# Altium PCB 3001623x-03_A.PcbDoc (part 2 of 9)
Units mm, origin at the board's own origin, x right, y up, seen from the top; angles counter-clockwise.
Board outline 210 x 130 mm, 9 copper layers (1-TOP, 2-GND, 3-INTOP, 4-PWR, 5-PWR, 6-INBOT, Signal_4, 7-GND, 8-BOTTOM), stack 1.979 mm thick; 755 components, 650 nets, 2980 pads, 2365 vias.

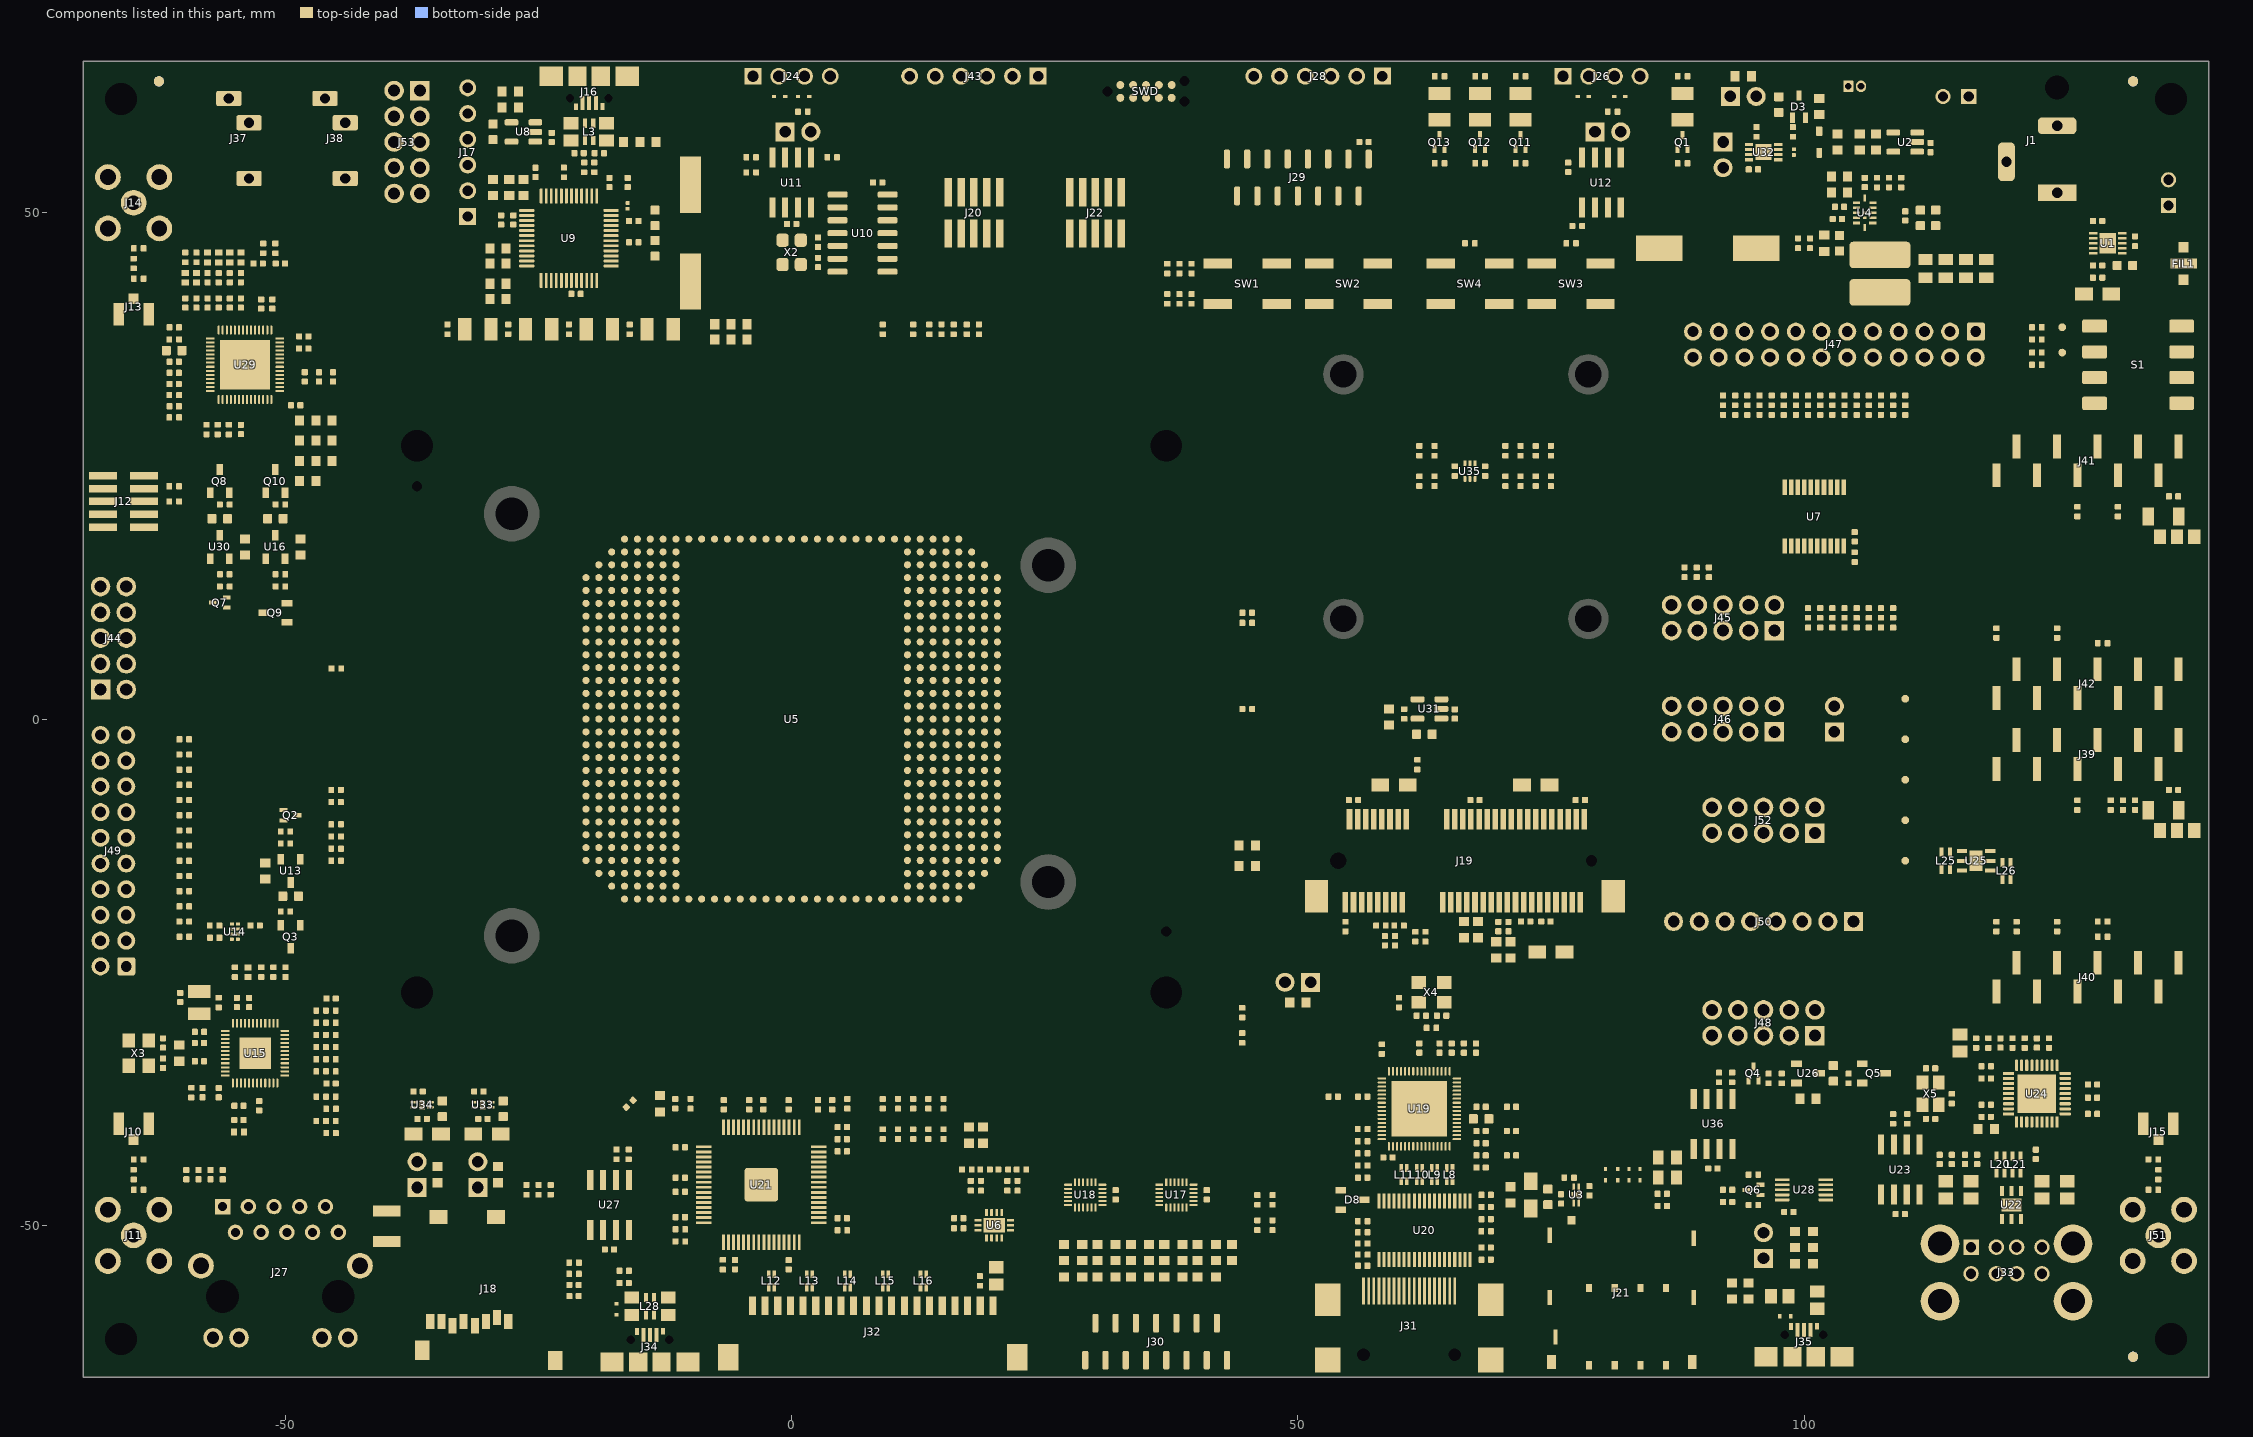
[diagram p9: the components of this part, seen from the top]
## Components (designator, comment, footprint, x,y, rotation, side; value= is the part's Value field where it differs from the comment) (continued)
U18 "NX3DV642" QFN40P340X250X50-24N 29,-47 r90 top locked
U19 "LT8912B" QFN40P750X750X80-65T620N 62,-38.5 r0 top
U20 "CM2020-01" SOP50P640X120-38N 62.5,-50.5 r270 top locked
U21 "SN65DSI83" QFP50P1200X1200X120-65L30T320N -3,-46 r90 top locked
U22 "TPD4E001DRSR" SON95P300X300X80-7N 120.5,-48 r0 top
U23 "MIC2026" SOIC127P600X175-8N 109.5,-44.5 r270 top locked
U24 "USB2514BI-AEZG" QFN50P600X600X100-37AN 123,-37 r90 top locked
U25 "TPD4E001DRSR" SON95P300X300X80-7N 117,-14 r270 top locked
U26 "SI2323DS-T1-E3" SOT95P240X110_GSD-3N 100.4,-35 r270 top
U27 "MIC2026" SOIC127P600X175-8N -18,-48 r270 top locked
U28 "FSUSB20MUX" SOP50P490X110-10L30N 100,-46.5 r180 top locked
U29 "MAX98089" QFN40P700X700X80-57T560X560N -54,35 r90 top locked
U30 "SI2323DS-T1-E3" SOT95P240X110_GSD-3N -56.5,17 r0 top
U31 "AP2202" SOT95P280X145-5N 63,1 r180 top
U32 "MCP6442T-E/MNY" SON50P300X200X80-9N 96,56 r90 top
U33 "SIP32401A" SON50P120X160X60-5T55X91N -30.5,-38.1 r180 top locked
U34 "SIP32401A" SON50P120X160X60-5T55X91N -36.5,-38.1 r180 top locked
U35 "DMN5L06VK-7" SOTFL50P160X60-6N 67,24.5 r90 top
U36 "MIC2026" SOIC127P600X175-8N 91,-40 r270 top locked
X1 "6MHz" "XTAL_ XT9M20HRR" -10,48 r270 top
X2 "RH100-40.000-9-F-1010-EXT-TR" OSCCC320X250X71N 0,46.1 r0 top
X3 "RH100-25.000-20-EXT-TR" OSC210P320X250X90-4N -64.5,-33 r0 top
X4 "RH100-25.000-20-EXT-TR" OSC210P320X250X90-4N 63.2,-27 r270 top
X5 "24MHz" XTAL_C3E-3427 112.5,-37 r90 top locked

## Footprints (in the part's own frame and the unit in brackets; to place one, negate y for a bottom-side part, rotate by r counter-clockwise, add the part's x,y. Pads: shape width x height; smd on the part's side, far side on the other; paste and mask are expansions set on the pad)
"BOBBINTRON_SMA A700T" [mil] "SMA JACK RA"
  round 100 hole 55.12: 1(0,0)
  round 100 hole 61: 2(-100,100) 3(100,100) 4(-100,-100) 5(100,-100)
  body extent -137,-138 457,138, height 398
CAPC1005X55N [mm]
  rrect30% 0.6x0.62 smd mask+0.1: 1(-0.46,0) 2(0.46,0)
  body extent -0.5,-0.25 0.5,0.25, height 0.55
CAPC1608X90N [mm] "0603"
  rrect22% 0.89x0.93 smd: 1(-0.77,0) 2(0.77,0)
  body extent -0.8,-0.4 0.8,0.4, height 0.9
CAPC2013X135N [mm] "0805, 1.35mm max height"
  rect 1.05x1.4 smd: 1(-0.9,0) 2(0.9,0)
  body extent -1,-0.62 1,0.63, height 1.35
CAPC3216X190N [mm]
  rect 1.15x1.8 smd: 1(-1.5,0) 2(1.5,0)
  body extent -1.6,-0.8 1.6,0.8, height 1.9
CAPMP3216X120N [mm]
  rect 1.75x1.3 smd: 1(-1.35,0) 2(1.35,0)
  body extent -1.7,-0.9 1.7,0.9, height 1.21
CONN_CSCD443CCS011B00G [mil] "Bobbintron : CSCD443CCS011B00G"
  rect 65x150 hole 40 slot 126 at 90 deg: 1(0,0)
  rrect50% 65x150 / inner rect 65x150 / far side rrect50% 65x150 hole 40 slot 126 at 90 deg: 2(-260,0)
  rrect50% 150x65 / inner rect 150x65 / far side rrect50% 150x65 hole 40 slot 126 at 0 deg: 3(-120,-197.01)
  round 0 hole 93 unplated: 4(-409,0)
  body extent -571,-207 20,177, height 433
CUI_SJ1-3533N [mm] "CON PWR JCK STEREO 3.5MM R/A 3.05mm"
  rrect25% 1.5x2.5 hole 1 slot 2 at 90 deg: 1(-3.8,-0.1) 2(-1.4,1.9) 3(4.1,1.9)
  body extent -9,-4.1 9,4.1, height 12.3
E-TEC_LPJ474-129M-32ABEW55L [mm]
  round 0.7 smd: A4(-20.32,-13.97) A5(-20.32,-12.7) A6(-20.32,-11.43) A7(-20.32,-10.16) A8(-20.32,-8.89) A9(-20.32,-7.62) A10(-20.32,-6.35) A11(-20.32,-5.08) A12(-20.32,-3.81) A13(-20.32,-2.54) A14(-20.32,-1.27) A15(-20.32,0) A16(-20.32,1.27) A17(-20.32,2.54) A18(-20.32,3.81) A19(-20.32,5.08) A20(-20.32,6.35) A21(-20.32,7.62) A22(-20.32,8.89) A23(-20.32,10.16) A24(-20.32,11.43) A25(-20.32,12.7) A26(-20.32,13.97) AA1(5.08,-17.78) AA29(5.08,17.78) AB1(6.35,-17.78) AB29(6.35,17.78) AC1(7.62,-17.78) AC29(7.62,17.78) AD1(8.89,-17.78) AD29(8.89,17.78) AE1(10.16,-17.78) AE29(10.16,17.78) AF1(11.43,-17.78) AF2(11.43,-16.51) AF3(11.43,-15.24) AF4(11.43,-13.97) AF5(11.43,-12.7) AF6(11.43,-11.43) AF7(11.43,-10.16) AF8(11.43,-8.89) AF9(11.43,-7.62) AF10(11.43,-6.35) AF11(11.43,-5.08) AF12(11.43,-3.81) AF13(11.43,-2.54) AF14(11.43,-1.27) AF15(11.43,0) AF16(11.43,1.27) AF17(11.43,2.54) AF18(11.43,3.81) AF19(11.43,5.08) AF20(11.43,6.35) AF21(11.43,7.62) AF22(11.43,8.89) AF23(11.43,10.16) AF24(11.43,11.43) AF25(11.43,12.7) AF26(11.43,13.97) AF27(11.43,15.24) AF28(11.43,16.51) AF29(11.43,17.78) AG1(12.7,-17.78) AG2(12.7,-16.51) AG3(12.7,-15.24) AG4(12.7,-13.97) AG5(12.7,-12.7) AG6(12.7,-11.43) AG7(12.7,-10.16) AG8(12.7,-8.89) AG9(12.7,-7.62) AG10(12.7,-6.35) AG11(12.7,-5.08) AG12(12.7,-3.81) AG13(12.7,-2.54) AG14(12.7,-1.27) AG15(12.7,0) AG16(12.7,1.27) AG17(12.7,2.54) AG18(12.7,3.81) AG19(12.7,5.08) AG20(12.7,6.35) AG21(12.7,7.62) AG22(12.7,8.89) AG23(12.7,10.16) AG24(12.7,11.43) AG25(12.7,12.7) AG26(12.7,13.97) AG27(12.7,15.24) AG28(12.7,16.51) AG29(12.7,17.78) AH1(13.97,-17.78) AH2(13.97,-16.51) AH3(13.97,-15.24) AH4(13.97,-13.97) AH5(13.97,-12.7) AH6(13.97,-11.43) AH7(13.97,-10.16) AH8(13.97,-8.89) AH9(13.97,-7.62) AH10(13.97,-6.35) AH11(13.97,-5.08) AH12(13.97,-3.81) AH13(13.97,-2.54) AH14(13.97,-1.27) AH15(13.97,0) AH16(13.97,1.27) AH17(13.97,2.54) AH18(13.97,3.81) AH19(13.97,5.08) AH20(13.97,6.35) AH21(13.97,7.62) AH22(13.97,8.89) AH23(13.97,10.16) AH24(13.97,11.43) AH25(13.97,12.7) AH26(13.97,13.97) AH27(13.97,15.24) AH28(13.97,16.51) AH29(13.97,17.78) AJ1(15.24,-17.78) AJ2(15.24,-16.51) AJ3(15.24,-15.24) AJ4(15.24,-13.97) AJ5(15.24,-12.7) AJ6(15.24,-11.43) AJ7(15.24,-10.16) AJ8(15.24,-8.89) AJ9(15.24,-7.62) AJ10(15.24,-6.35) AJ11(15.24,-5.08) AJ12(15.24,-3.81) AJ13(15.24,-2.54) AJ14(15.24,-1.27) AJ15(15.24,0) AJ16(15.24,1.27) AJ17(15.24,2.54) AJ18(15.24,3.81) AJ19(15.24,5.08) AJ20(15.24,6.35) AJ21(15.24,7.62) AJ22(15.24,8.89) AJ23(15.24,10.16) AJ24(15.24,11.43) AJ25(15.24,12.7) AJ26(15.24,13.97) AJ27(15.24,15.24) AJ28(15.24,16.51) AJ29(15.24,17.78) AK1(16.51,-17.78) AK2(16.51,-16.51) AK3(16.51,-15.24) AK4(16.51,-13.97) AK5(16.51,-12.7) AK6(16.51,-11.43) AK7(16.51,-10.16) AK8(16.51,-8.89) AK9(16.51,-7.62) AK10(16.51,-6.35) AK11(16.51,-5.08) AK12(16.51,-3.81) AK13(16.51,-2.54) AK14(16.51,-1.27) AK15(16.51,0) AK16(16.51,1.27) AK17(16.51,2.54) AK18(16.51,3.81) AK19(16.51,5.08) AK20(16.51,6.35) AK21(16.51,7.62) AK22(16.51,8.89) AK23(16.51,10.16) AK24(16.51,11.43) AK25(16.51,12.7) AK26(16.51,13.97) AK27(16.51,15.24) AK28(16.51,16.51) AK29(16.51,17.78) AL2(17.78,-16.51) AL3(17.78,-15.24) AL4(17.78,-13.97) AL5(17.78,-12.7) AL6(17.78,-11.43) AL7(17.78,-10.16) AL8(17.78,-8.89) AL9(17.78,-7.62) AL10(17.78,-6.35) AL11(17.78,-5.08) AL12(17.78,-3.81) AL13(17.78,-2.54) AL14(17.78,-1.27) AL15(17.78,0) AL16(17.78,1.27) AL17(17.78,2.54) AL18(17.78,3.81) AL19(17.78,5.08) AL20(17.78,6.35) AL21(17.78,7.62) AL22(17.78,8.89) AL23(17.78,10.16) AL24(17.78,11.43) AL25(17.78,12.7) AL26(17.78,13.97) AL27(17.78,15.24) AL28(17.78,16.51) AM3(19.05,-15.24) AM4(19.05,-13.97) AM5(19.05,-12.7) AM6(19.05,-11.43) AM7(19.05,-10.16) AM8(19.05,-8.89) AM9(19.05,-7.62) AM10(19.05,-6.35) AM11(19.05,-5.08) AM12(19.05,-3.81) AM13(19.05,-2.54) AM14(19.05,-1.27) AM15(19.05,0) AM16(19.05,1.27) AM17(19.05,2.54) AM18(19.05,3.81) AM19(19.05,5.08) AM20(19.05,6.35) AM21(19.05,7.62) AM22(19.05,8.89) AM23(19.05,10.16) AM24(19.05,11.43) AM25(19.05,12.7) AM26(19.05,13.97) AM27(19.05,15.24) AN4(20.32,-13.97) AN5(20.32,-12.7) AN6(20.32,-11.43) AN7(20.32,-10.16) AN8(20.32,-8.89) AN9(20.32,-7.62) AN10(20.32,-6.35) AN11(20.32,-5.08) AN12(20.32,-3.81) AN13(20.32,-2.54) AN14(20.32,-1.27) AN15(20.32,0) AN16(20.32,1.27) AN17(20.32,2.54) AN18(20.32,3.81) AN19(20.32,5.08) AN20(20.32,6.35) AN21(20.32,7.62) AN22(20.32,8.89) AN23(20.32,10.16) AN24(20.32,11.43) AN25(20.32,12.7) AN26(20.32,13.97) B3(-19.05,-15.24) B4(-19.05,-13.97) B5(-19.05,-12.7) B6(-19.05,-11.43) B7(-19.05,-10.16) B8(-19.05,-8.89) B9(-19.05,-7.62) B10(-19.05,-6.35) B11(-19.05,-5.08) B12(-19.05,-3.81) B13(-19.05,-2.54) B14(-19.05,-1.27) B15(-19.05,0) B16(-19.05,1.27) B17(-19.05,2.54) B18(-19.05,3.81) B19(-19.05,5.08) B20(-19.05,6.35) B21(-19.05,7.62) B22(-19.05,8.89) B23(-19.05,10.16) B24(-19.05,11.43) B25(-19.05,12.7) B26(-19.05,13.97) B27(-19.05,15.24) C2(-17.78,-16.51) C3(-17.78,-15.24) C4(-17.78,-13.97) C5(-17.78,-12.7) C6(-17.78,-11.43) C7(-17.78,-10.16) C8(-17.78,-8.89) C9(-17.78,-7.62) C10(-17.78,-6.35) C11(-17.78,-5.08) C12(-17.78,-3.81) C13(-17.78,-2.54) C14(-17.78,-1.27) C15(-17.78,0) C16(-17.78,1.27) C17(-17.78,2.54) C18(-17.78,3.81) C19(-17.78,5.08) C20(-17.78,6.35) C21(-17.78,7.62) C22(-17.78,8.89) C23(-17.78,10.16) C24(-17.78,11.43) C25(-17.78,12.7) C26(-17.78,13.97) C27(-17.78,15.24) C28(-17.78,16.51) D1(-16.51,-17.78) D2(-16.51,-16.51) D3(-16.51,-15.24) D4(-16.51,-13.97) D5(-16.51,-12.7) D6(-16.51,-11.43) D7(-16.51,-10.16) D8(-16.51,-8.89) D9(-16.51,-7.62) D10(-16.51,-6.35) D11(-16.51,-5.08) D12(-16.51,-3.81) D13(-16.51,-2.54) D14(-16.51,-1.27) D15(-16.51,0) D16(-16.51,1.27) D17(-16.51,2.54) D18(-16.51,3.81) D19(-16.51,5.08) D20(-16.51,6.35) D21(-16.51,7.62) D22(-16.51,8.89) D23(-16.51,10.16) D24(-16.51,11.43) D25(-16.51,12.7) D26(-16.51,13.97) D27(-16.51,15.24) D28(-16.51,16.51) D29(-16.51,17.78) E1(-15.24,-17.78) E2(-15.24,-16.51) E3(-15.24,-15.24) E4(-15.24,-13.97) E5(-15.24,-12.7) E6(-15.24,-11.43) E7(-15.24,-10.16) E8(-15.24,-8.89) E9(-15.24,-7.62) E10(-15.24,-6.35) E11(-15.24,-5.08) E12(-15.24,-3.81) E13(-15.24,-2.54) E14(-15.24,-1.27) E15(-15.24,0) E16(-15.24,1.27) E17(-15.24,2.54) E18(-15.24,3.81) E19(-15.24,5.08) E20(-15.24,6.35) E21(-15.24,7.62) E22(-15.24,8.89) E23(-15.24,10.16) E24(-15.24,11.43) E25(-15.24,12.7) E26(-15.24,13.97) E27(-15.24,15.24) E28(-15.24,16.51) E29(-15.24,17.78) F1(-13.97,-17.78) F2(-13.97,-16.51) F3(-13.97,-15.24) F4(-13.97,-13.97) F5(-13.97,-12.7) F6(-13.97,-11.43) F7(-13.97,-10.16) F8(-13.97,-8.89) F9(-13.97,-7.62) F10(-13.97,-6.35) F11(-13.97,-5.08) F12(-13.97,-3.81) F13(-13.97,-2.54) F14(-13.97,-1.27) F15(-13.97,0) F16(-13.97,1.27) F17(-13.97,2.54) F18(-13.97,3.81) F19(-13.97,5.08) F20(-13.97,6.35) F21(-13.97,7.62) F22(-13.97,8.89) F23(-13.97,10.16) F24(-13.97,11.43) F25(-13.97,12.7) F26(-13.97,13.97) F27(-13.97,15.24) F28(-13.97,16.51) F29(-13.97,17.78) G1(-12.7,-17.78) G2(-12.7,-16.51) G3(-12.7,-15.24) G4(-12.7,-13.97) G5(-12.7,-12.7) G6(-12.7,-11.43) G7(-12.7,-10.16) G8(-12.7,-8.89) G9(-12.7,-7.62) G10(-12.7,-6.35) G11(-12.7,-5.08) G12(-12.7,-3.81) G13(-12.7,-2.54) G14(-12.7,-1.27) G15(-12.7,0) G16(-12.7,1.27) G17(-12.7,2.54) G18(-12.7,3.81) G19(-12.7,5.08) G20(-12.7,6.35) G21(-12.7,7.62) G22(-12.7,8.89) G23(-12.7,10.16) G24(-12.7,11.43) G25(-12.7,12.7) G26(-12.7,13.97) G27(-12.7,15.24) G28(-12.7,16.51) G29(-12.7,17.78) H1(-11.43,-17.78) H2(-11.43,-16.51) H3(-11.43,-15.24) H4(-11.43,-13.97) H5(-11.43,-12.7) H6(-11.43,-11.43) H7(-11.43,-10.16) H8(-11.43,-8.89) H9(-11.43,-7.62) H10(-11.43,-6.35) H11(-11.43,-5.08) H12(-11.43,-3.81) H13(-11.43,-2.54) H14(-11.43,-1.27) H15(-11.43,0) H16(-11.43,1.27) H17(-11.43,2.54) H18(-11.43,3.81) H19(-11.43,5.08) H20(-11.43,6.35) H21(-11.43,7.62) H22(-11.43,8.89) H23(-11.43,10.16) H24(-11.43,11.43) H25(-11.43,12.7) H26(-11.43,13.97) H27(-11.43,15.24) H28(-11.43,16.51) H29(-11.43,17.78) J1(-10.16,-17.78) J29(-10.16,17.78) K1(-8.89,-17.78) K29(-8.89,17.78) L1(-7.62,-17.78) L29(-7.62,17.78) M1(-6.35,-17.78) M29(-6.35,17.78) N1(-5.08,-17.78) N29(-5.08,17.78) P1(-3.81,-17.78) P29(-3.81,17.78) R1(-2.54,-17.78) R29(-2.54,17.78) T1(-1.27,-17.78) T29(-1.27,17.78) U1(0,-17.78) U29(0,17.78) V1(1.27,-17.78) V29(1.27,17.78) W1(2.54,-17.78) W29(2.54,17.78) Y1(3.81,-17.78) Y29(3.81,17.78)
  round 0 hole 3.15 unplated: MH1(-37,27) MH2(37,27) MH3(37,-27) MH4(-37,-27)
  round 0 hole 1: MH5(-37,23) MH6(37,-21)
  Keep-Out Layer board cut-out: -10.75,16 -10.75,-16 -10.75,-16.098 -10.712,-16.292 -10.636,-16.474 -10.527,-16.638 -10.388,-16.777 -10.224,-16.886 -10.042,-16.962 -9.848,-17 -9.75,-17 -9.75,-17 10,-17 10.074,-17 10.219,-16.971 10.355,-16.915 10.478,-16.833 10.583,-16.728 10.665,-16.605 10.721,-16.469 10.75,-16.324 10.75,-16.25 10.75,-16.25 10.75,16 10.75,16.098 10.712,16.292 10.636,16.474 10.527,16.637 10.387,16.777 10.224,16.886 10.042,16.962 9.848,17 9.75,17 9.75,17 -9.75,17 -9.848,17 -10.042,16.962 -10.224,16.886 -10.387,16.777 -10.527,16.637 -10.636,16.474 -10.712,16.292 -10.75,16.099 -10.75,16
  Keep-Out Layer region: -38.9,27 -38.9,27.187 -38.827,27.554 -38.684,27.9 -38.476,28.211 -38.211,28.476 -37.9,28.684 -37.554,28.827 -37.187,28.9 -37,28.9 -36.813,28.9 -36.446,28.827 -36.1,28.684 -35.789,28.476 -35.524,28.211 -35.316,27.9 -35.173,27.554 -35.1,27.187 -35.1,27 -35.1,27 -35.1,26.813 -35.173,26.446 -35.316,26.1 -35.524,25.789 -35.789,25.524 -36.1,25.316 -36.446,25.173 -36.813,25.1 -37,25.1 -37,25.1 -37.187,25.1 -37.554,25.173 -37.9,25.316 -38.211,25.524 -38.476,25.789 -38.684,26.1 -38.827,26.446 -38.9,26.813 -38.9,27
  Keep-Out Layer region: 35.1,27 35.1,27.187 35.173,27.554 35.316,27.9 35.524,28.211 35.789,28.476 36.1,28.684 36.446,28.827 36.813,28.9 37,28.9 37.187,28.9 37.554,28.827 37.9,28.684 38.211,28.476 38.476,28.211 38.684,27.9 38.827,27.554 38.9,27.187 38.9,27 38.9,27 38.9,26.813 38.827,26.446 38.684,26.1 38.476,25.789 38.211,25.524 37.9,25.316 37.554,25.173 37.187,25.1 37,25.1 37,25.1 36.813,25.1 36.446,25.173 36.1,25.316 35.789,25.524 35.524,25.789 35.316,26.1 35.173,26.446 35.1,26.813 35.1,27
  Keep-Out Layer region: 35.1,-27 35.1,-26.813 35.173,-26.446 35.316,-26.1 35.524,-25.789 35.789,-25.524 36.1,-25.316 36.446,-25.173 36.813,-25.1 37,-25.1 37.187,-25.1 37.554,-25.173 37.9,-25.316 38.211,-25.524 38.476,-25.789 38.684,-26.1 38.827,-26.446 38.9,-26.813 38.9,-27 38.9,-27 38.9,-27.187 38.827,-27.554 38.684,-27.9 38.476,-28.211 38.211,-28.476 37.9,-28.684 37.554,-28.827 37.187,-28.9 37,-28.9 37,-28.9 36.813,-28.9 36.446,-28.827 36.1,-28.684 35.789,-28.476 35.524,-28.211 35.316,-27.9 35.173,-27.554 35.1,-27.187 35.1,-27
  Keep-Out Layer region: -38.9,-27 -38.9,-26.813 -38.827,-26.446 -38.684,-26.1 -38.476,-25.789 -38.211,-25.524 -37.9,-25.316 -37.554,-25.173 -37.187,-25.1 -37,-25.1 -36.813,-25.1 -36.446,-25.173 -36.1,-25.316 -35.789,-25.524 -35.524,-25.789 -35.316,-26.1 -35.173,-26.446 -35.1,-26.813 -35.1,-27 -35.1,-27 -35.1,-27.187 -35.173,-27.554 -35.316,-27.9 -35.524,-28.211 -35.789,-28.476 -36.1,-28.684 -36.446,-28.827 -36.813,-28.9 -37,-28.9 -37,-28.9 -37.187,-28.9 -37.554,-28.827 -37.9,-28.684 -38.211,-28.476 -38.476,-28.211 -38.684,-27.9 -38.827,-27.554 -38.9,-27.187 -38.9,-27
  Keep-Out Layer region: -37.7,23 -37.7,23.069 -37.673,23.204 -37.62,23.332 -37.544,23.446 -37.446,23.544 -37.332,23.62 -37.204,23.673 -37.069,23.7 -37,23.7 -36.931,23.7 -36.796,23.673 -36.668,23.62 -36.554,23.544 -36.456,23.446 -36.38,23.332 -36.327,23.204 -36.3,23.069 -36.3,23 -36.3,23 -36.3,22.931 -36.327,22.796 -36.38,22.668 -36.456,22.554 -36.554,22.456 -36.668,22.38 -36.796,22.327 -36.931,22.3 -37,22.3 -37,22.3 -37.069,22.3 -37.204,22.327 -37.332,22.38 -37.446,22.456 -37.544,22.554 -37.62,22.668 -37.673,22.796 -37.7,22.931 -37.7,23
  Keep-Out Layer region: 36.3,-21 36.3,-20.931 36.327,-20.796 36.38,-20.668 36.456,-20.554 36.554,-20.456 36.668,-20.38 36.796,-20.327 36.931,-20.3 37,-20.3 37.069,-20.3 37.204,-20.327 37.332,-20.38 37.446,-20.456 37.544,-20.554 37.62,-20.668 37.673,-20.796 37.7,-20.931 37.7,-21 37.7,-21 37.7,-21.069 37.673,-21.204 37.62,-21.332 37.544,-21.446 37.446,-21.544 37.332,-21.62 37.204,-21.673 37.069,-21.7 37,-21.7 37,-21.7 36.931,-21.7 36.796,-21.673 36.668,-21.62 36.554,-21.544 36.456,-21.446 36.38,-21.332 36.327,-21.204 36.3,-21.069 36.3,-21
  body extent -46.8,-36.5 43,36.5, height 52.8
FCI_68002-102HLF#1 [mil]
  rect 74x74 hole 45: 1(-50,0)
  round 74 hole 45: 2(50,0)
  silkscreen extent -135,-7 -120,7, body extent -101,-46 99,49, height 330
FCI_68002-102HLF#2 [mil]
  rect 74x74 hole 45: 1(0,0)
  round 74 hole 45: 2(100,0)
  silkscreen extent -85,-7 -70,7, body extent -51,-46 149,49, height 330
FCI_SFW15S-2STE1LF [mm] "CONN FFC FPC VERT 15POS 1MM SMD"
  rrect50% 0.6x1.85 smd: 1(-7,-1.825) 2(-6,1.825) 3(-5,-1.825) 4(-4,1.825) 5(-3,-1.825) 6(-2,1.825) 7(-1,-1.825) 8(0,1.825) 9(1,-1.825) 10(2,1.825) 11(3,-1.825) 12(4,1.825) 13(5,-1.825) 14(6,1.825) 15(7,-1.825)
  silkscreen extent -9,-3.45 -7.5,-1.95, body extent -10.7,-2.25 10.7,2.25, height 5.31
FIDUCIAL_40MIL_ROUND [mil]
  round 40 smd paste-40 mask+20: 1(0,0)
  1-TOP pour cut-out: -40,0 -40,3.94 -38.46,11.67 -35.45,18.95 -31.07,25.5 -25.5,31.07 -18.95,35.45 -11.67,38.46 -3.94,40 0,40 3.94,40 11.67,38.46 18.95,35.45 25.5,31.07 31.07,25.5 35.45,18.95 38.46,11.67 40,3.94 40,0 40,-3.94 38.46,-11.67 35.45,-18.95 31.07,-25.5 25.5,-31.07 18.95,-35.45 11.67,-38.46 3.94,-40 0,-40 -3.94,-40 -11.67,-38.46 -18.95,-35.45 -25.5,-31.07 -31.07,-25.5 -35.45,-18.95 -38.46,-11.67 -40,-3.94 -40,0
FIL_DLP11S [mm]
  rect 0.75x0.35 smd: 1(-0.65,-0.275) 2(0.65,-0.275) 3(0.65,0.275) 4(-0.65,0.275)
  body extent -0.67,-0.55 0.68,0.55, height 0.92
FIL_DLW21H [mm]
  rect 0.9x0.4 smd: 1(-0.85,-0.4) 2(0.85,-0.4) 3(0.85,0.4) 4(-0.85,0.4)
  1-TOP pour cut-out: -0.4,-0.85 -0.4,0.85 0.4,0.85 0.4,-0.85
  body extent -1.1,-0.7 1.1,0.7, height 1
FIL_NFE31P [mm]
  rect 1x1 smd: 1(-1.6,0) 3(1.6,0)
  rect 1x2.6 smd: 2(0,0)
  body extent -1.78,-0.87 1.77,0.87, height 1.75
FOXCONN_AS0B221-S68Q-7H [mm]
  rect 0.55x2 smd: 1(-11.8,-4.1) 2(-11.4,4.1) 3(-11,-4.1) 4(-10.6,4.1) 5(-10.2,-4.1) 6(-9.8,4.1) 7(-9.4,-4.1) 8(-9,4.1) 9(-8.6,-4.1) 10(-8.2,4.1) 11(-7.8,-4.1) 12(-7.4,4.1) 13(-7,-4.1) 14(-6.6,4.1) 15(-6.2,-4.1) 16(-5.8,4.1) 17(-2.2,-4.1) 18(-1.8,4.1) 19(-1.4,-4.1) 20(-1,4.1) 21(-0.6,-4.1) 22(-0.2,4.1) 23(0.2,-4.1) 24(0.6,4.1) 25(1,-4.1) 26(1.4,4.1) 27(1.8,-4.1) 28(2.2,4.1) 29(2.6,-4.1) 30(3,4.1) 31(3.4,-4.1) 32(3.8,4.1) 33(4.2,-4.1) 34(4.6,4.1) 35(5,-4.1) 36(5.4,4.1) 37(5.8,-4.1) 38(6.2,4.1) 39(6.6,-4.1) 40(7,4.1) 41(7.4,-4.1) 42(7.8,4.1) 43(8.2,-4.1) 44(8.6,4.1) 45(9,-4.1) 46(9.4,4.1) 47(9.8,-4.1) 48(10.2,4.1) 49(10.6,-4.1) 50(11,4.1) 51(11.4,-4.1) 52(11.8,4.1)
  round 0 hole 1.6 unplated: H1(-12.5,0)
  round 0 hole 1.1 unplated: H2(12.5,0)
  rect 2.3x3.2 smd: MT1(-14.65,-3.5) MT2(14.65,-3.5)
  body extent -14.9,-4.75 14.9,4.75, height 6.8
HDRV4W64P254_4X1_1016X248H1067 [mm] "Header, Vertical, 2.54 mm pitch; 0.64 mm lead width, 4 pins, 1 row, 4 pins per row, 10.16 mm L X 2.48 mm W X 10.67 mm H body"
  rect 1.67x1.67 hole 1.11 paste-1.67 mask+0.1: 1(-3.81,0)
  round 1.67 hole 1.11 paste-1.67 mask+0.1: 2(-1.27,0) 3(1.27,0) 4(3.81,0)
  silkscreen extent -5.6,-1.6 -5.4,-1.4, body extent -5.08,-1.24 5.08,1.24, height 10.67
HIROSE_DF14A-20P-1.25H [mm]
  rect 0.7x1.8 smd: 1(11.875,-2.55) 2(10.625,-2.55) 3(9.375,-2.55) 4(8.125,-2.55) 5(6.875,-2.55) 6(5.625,-2.55) 7(4.375,-2.55) 8(3.125,-2.55) 9(1.875,-2.55) 10(0.625,-2.55) 11(-0.625,-2.55) 12(-1.875,-2.55) 13(-3.125,-2.55) 14(-4.375,-2.55) 15(-5.625,-2.55) 16(-6.875,-2.55) 17(-8.125,-2.55) 18(-9.375,-2.55) 19(-10.625,-2.55) 20(-11.875,-2.55)
  rect 2x2.6 smd: MT1(14.275,2.55) MT21(-14.275,2.55)
  silkscreen extent 12.75,-3.05 13.25,-2.55, body extent -14.97,-3.02 14.97,3.67, height 2.49
HIROSE_U.FL-R-SMT(01) [mm]
  rect 1x1.05 smd: 1(0,-1.525)
  rect 1.05x2.2 smd: 2(-1.475,0.025) 3(1.475,0.025)
  1-TOP pour cut-out: -0.95,1.125 0.95,1.125 0.95,-1.075 -0.95,-1.075
  body extent -1.5,-1.5 1.5,1.6, height 1.25
IND_DG6045C [mm] "IND_DG6045C"
  rrect25% 6x2.6 smd mask+0.1: 1(0,1.85) 2(0,-1.85)
  1-TOP keep-out region: -3.1,0.4 -3.1,-0.4 3.1,-0.4 3.1,0.4
  body extent -3.15,-3.15 3.15,3.15, height 4.5
INDC1005X60N [mm]
  rect 0.59x0.72 smd: 1(-0.48,0) 2(0.48,0)
  body extent -0.5,-0.25 0.5,0.25, height 0.6
INDC2013X110N [mm]
  rect 1.2x1.45 smd: 1(-0.85,0) 2(0.85,0)
  body extent -1,-0.62 1,0.63, height 1.1
INDC2520X100L60N [mm] "Inductor, Chip; 2.50 mm L X 2.00 mm W X 1.00 mm H body"
  rect 1.24x2.22 smd: 1(-1.09,0) 2(1.09,0)
  body extent -1.25,-1 1.25,1, height 1
KYCON_KDMIX [mm]
  rect 0.28x2.7 smd: 1(4.5,6.3) 2(4,6.3) 3(3.5,6.3) 4(3,6.3) 5(2.5,6.3) 6(2,6.3) 7(1.5,6.3) 8(1,6.3) 9(0.5,6.3) 10(0,6.3) 11(-0.5,6.3) 12(-1,6.3) 13(-1.5,6.3) 14(-2,6.3) 15(-2.5,6.3) 16(-3,6.3) 17(-3.5,6.3) 18(-4,6.3) 19(-4.5,6.3)
  round 0 hole 1.27 unplated: H1(4.5,0) H2(-4.5,0)
  rect 2.5x3.2 smd: M1(8.05,5.45) M2(-8.05,5.45)
  rect 2.5x2.5 smd: M3(8.05,-0.51) M4(-8.05,-0.51)
  body extent -8.58,-5.17 8.62,6.95, height 6.11
KYCON_KMMX-ABSMT5 [mm]
  rect 0.4x0.7 smd mask+0.058: 1(-1.3,3)
  rect 0.4x1.4 smd: 2(-0.65,2.65) 3(0,2.65) 4(0.65,2.65)
  rect 0.4x0.65 smd mask+0.058: 5(1.3,3.025)
  rect 2.3x1.9 smd: 6(-3.75,0) 9(3.75,0)
  rect 1.8x1.9 smd: 7(-1.15,0) 8(1.15,0)
  round 0 hole 0.813 unplated mask+0: 10(-1.9,2.18) 11(1.9,2.18)
  1-TOP region: 1.1,3.025 1.1,1.95 1.275,1.95 1.275,2.18 1.278,2.235 1.28,2.258 1.282,2.278 1.285,2.29 1.288,2.305 1.292,2.328 1.3,2.355 1.308,2.378 1.315,2.4 1.32,2.412 1.335,2.448 1.342,2.462 1.358,2.49 1.372,2.515 1.388,2.538 1.4,2.555 1.418,2.578 1.435,2.598 1.482,2.645 1.5,2.66 1.5,3.025
  1-TOP region: -1.1,3 -1.1,1.95 -1.275,1.95 -1.275,2.18 -1.278,2.235 -1.28,2.258 -1.282,2.278 -1.285,2.29 -1.288,2.305 -1.292,2.328 -1.3,2.355 -1.308,2.378 -1.315,2.4 -1.32,2.412 -1.335,2.448 -1.342,2.462 -1.358,2.49 -1.372,2.515 -1.388,2.538 -1.4,2.555 -1.418,2.578 -1.435,2.598 -1.482,2.645 -1.5,2.66 -1.5,3
  body extent -4.4,-2.73 4.4,2.87, height 2.78
KYCON_KUSBX-AS2N_FLEX [mm]
  rect 1.524x1.524 hole 1: A1(-3.5,5.33)
  round 1.524 hole 1: A2(-1,5.33) A3(1,5.33) A4(3.5,5.33) B1(-3.5,2.71) B2(-1,2.71) B3(1,2.71) B4(3.5,2.71)
  round 3.81 hole 2.362: SH1(-6.57,0) SH2(-6.57,5.68) SH3(6.57,0) SH4(6.57,5.68)
  body extent -7.83,-10.75 7.83,6.75, height 16.1
LEDM3020X130N [mm]
  rect 1.3x2.2 smd: A(-1.3,0) K(1.3,0)
  body extent -1.6,-1.1 1.6,1.1, height 1.5
MH_185_125_NP [mm]
  round 0 hole 3.175 unplated mask+0.102: 1(0,0)
  Keep-Out Layer circle w0.102: c0,0 r2.349
MOLEX_53047-0210_FLEX [mm]
  rrect20% 1x1.15 hole 0.65: 1(-0.625,0)
  oval 1x1.15 hole 0.65: 2(0.625,0)
  silkscreen extent -3.13,-0.25 -2.63,0.25, body extent -2.15,-1.15 2.1,2.05, height 4.2
MOLEX_78727-0001 [mm]
  rect 0.8x0.6 smd: 1(0.33,4.38) 2(0.33,1.84) 3(0.33,-0.7) 4(0.33,-3.24) 5(-7.29,4.38) 6(-7.29,1.84) 7(-7.29,-0.7) 8(-7.29,-3.24)
  rect 0.85x0.8 smd: 9(-13.99,-4.98)
  rect 1.5x0.42 smd: 10(-2.47,-6.54) 12(-6.35,7.11) 13(-12.21,7.11) 14(-12.51,-7.11) 15(-6.35,-7.11)
  rect 1.4x0.87 smd: 11(0,6.95) 16(0,-6.95)
  body extent -14.58,-7.26 0.64,7.27, height 1.4
MOLEX_87914-1016#1 [mil]
  rect 76x76 hole 47: 1(-200,50)
  round 76 hole 47: 2(-200,-50) 3(-100,50) 4(-100,-50) 5(0,50) 6(0,-50) 7(100,50) 8(100,-50) 9(200,50) 10(200,-50)
  silkscreen extent -293,37 -273,57, body extent -250,-98 250,98, height 320
MOLEX_87914-1016#2 [mil]
  rect 76x76 hole 47: 1(0,0)
  round 76 hole 47: 2(0,-100) 3(100,0) 4(100,-100) 5(200,0) 6(200,-100) 7(300,0) 8(300,-100) 9(400,0) 10(400,-100)
  silkscreen extent -90,-10 -70,10, body extent -50,-148 450,48, height 320
MOLEX_500873-0806 [mm]
  rect 0.8x1.5 smd: 1(0,0) 2(1.1,-0.4) 3(2.2,0) 4(3.3,0.425) 5(4.4,0) 6(5.5,0.425) 7(6.6,0) 8(7.7,0)
  rect 1.8x1.4 smd: 9(1.2,-10.3) 10(6.9,-10.3)
  rect 1.4x1.9 smd: 11(8.5,2.85) 12(-4.65,3.85)
  1-TOP region: 8.6,1.75 9.2,1.75 9.2,-11 8.6,-11
  body extent -5.05,-10.7 8.95,4.5, height 1.87
MOLEX_0022284060 [mil]
  rect 66x66 hole 40: 1(-250,0)
  round 66 hole 40: 2(-150,0) 3(-50,0) 4(50,0) 5(150,0) 6(250,0)
  silkscreen extent -331,-8 -315,8, body extent -300,-49 300,49, height 330
NEXC474Z3.5V10.5X8.5TRF [mm] "NEXC474Z3.5V10.5X8.5TRF"
  rect 2.5x4.6 smd: 1(0,4.8) 2(0,-4.8)
  body extent -5.4,-5.4 5.4,5.4, height 8.5
OSC210P320X250X90-4N [mm]
  rect 1.25x1.425 smd: 1(-0.975,1.25) 2(-0.975,-1.25) 3(0.975,-1.25) 4(0.975,1.25)
  body extent -1.3,-1.63 1.3,1.62, height 0.6
OSCCC320X250X71N [mm] "Oscillator, Corner Concave; 3.20 mm L X 2.50 mm W X 0.71 mm H body"
  rrect50% 1.21x1.31 smd: 1(-0.9,1.2) 2(-0.9,-1.2) 3(0.9,-1.2) 4(0.9,1.2)
  body extent -1.25,-1.6 1.25,1.6, height 0.71
PSON50P195X100X50-8N [mm] "Pullback Small Outline No-Lead (PSON), 0.50 mm pitch; 8 pin, 1.95 mm L X 1.00 mm W X 0.50 mm H body"
  rrect25% 0.4x0.3 smd mask+0.05: 1(-0.3,0.75) 2(-0.3,0.25) 3(-0.3,-0.25) 4(-0.3,-0.75) 5(0.3,-0.75) 6(0.3,-0.25) 7(0.3,0.25) 8(0.3,0.75)
  silkscreen extent -0.8,1.08 -0.6,1.27, body extent -0.5,-0.97 0.5,0.97, height 0.5
QFN40P340X250X50-24N [mm] "Quad Flat No-Lead (QFN), 0.40 mm pitch; rect., 6 pin X 6 pin, 3.40 mm L X 2.50 mm W X 0.50 mm H body"
  rrect30% 0.765x0.2 smd mask+0.05: 1(-1.245,1) 2(-1.245,0.6) 3(-1.245,0.2) 4(-1.245,-0.2) 5(-1.245,-0.6) 6(-1.245,-1) 13(1.245,-1) 14(1.245,-0.6) 15(1.245,-0.2) 16(1.245,0.2) 17(1.245,0.6) 18(1.245,1)
  rrect30% 0.2x0.765 smd mask+0.05: 7(-1,-1.695) 8(-0.6,-1.695) 9(-0.2,-1.695) 10(0.2,-1.695) 11(0.6,-1.695) 12(1,-1.695) 19(1,1.695) 20(0.6,1.695) 21(0.2,1.695) 22(-0.2,1.695) 23(-0.6,1.695) 24(-1,1.695)
  silkscreen extent -1.88,1.42 -1.68,1.62, body extent -1.3,-1.75 1.3,1.75, height 0.5
QFN40P600X600X80-49T380N [mm] "Quad Flat No-Lead (QFN with Tab), 0.40 mm pitch; square, 12 pin X 12 pin, 6.00 mm L X 6.00 mm W X 0.80 mm H body"
  rrect25% 0.84x0.2 smd mask+0.05: 1(-2.95,2.2) 2(-2.95,1.8) 3(-2.95,1.4) 4(-2.95,1) 5(-2.95,0.6) 6(-2.95,0.2) 7(-2.95,-0.2) 8(-2.95,-0.6) 9(-2.95,-1) 10(-2.95,-1.4) 11(-2.95,-1.8) 12(-2.95,-2.2) 25(2.95,-2.2) 26(2.95,-1.8) 27(2.95,-1.4) 28(2.95,-1) 29(2.95,-0.6) 30(2.95,-0.2) 31(2.95,0.2) 32(2.95,0.6) 33(2.95,1) 34(2.95,1.4) 35(2.95,1.8) 36(2.95,2.2)
  rrect25% 0.2x0.84 smd mask+0.05: 13(-2.2,-2.95) 14(-1.8,-2.95) 15(-1.4,-2.95) 16(-1,-2.95) 17(-0.6,-2.95) 18(-0.2,-2.95) 19(0.2,-2.95) 20(0.6,-2.95) 21(1,-2.95) 22(1.4,-2.95) 23(1.8,-2.95) 24(2.2,-2.95) 37(2.2,2.95) 38(1.8,2.95) 39(1.4,2.95) 40(1,2.95) 41(0.6,2.95) 42(0.2,2.95) 43(-0.2,2.95) 44(-0.6,2.95) 45(-1,2.95) 46(-1.4,2.95) 47(-1.8,2.95) 48(-2.2,2.95)
  rect 3.1x3.1 smd paste-3.1 mask+0: 49(0,0)
  1-TOP region: -1.9,-1.9 -1.9,1.55 -1.55,1.9 1.9,1.9 1.9,-1.9 -1.9,-1.9
  silkscreen extent -3.55,2.65 -3.35,2.85, body extent -3.05,-3.05 3.05,3.05, height 0.8
QFN40P700X700X80-57T560X560N [mm] "Quad Flat No-Lead (QFN with Tab), 0.40 mm pitch; square, 14 pin X 14 pin, 7.00 mm L X 7.00 mm W X 0.80 mm H body"
  rrect50% 0.86x0.2 smd mask+0.05: 1(-3.43,2.6) 2(-3.43,2.2) 3(-3.43,1.8) 4(-3.43,1.4) 5(-3.43,1) 6(-3.43,0.6) 7(-3.43,0.2) 8(-3.43,-0.2) 9(-3.43,-0.6) 10(-3.43,-1) 11(-3.43,-1.4) 12(-3.43,-1.8) 13(-3.43,-2.2) 14(-3.43,-2.6) 29(3.43,-2.6) 30(3.43,-2.2) 31(3.43,-1.8) 32(3.43,-1.4) 33(3.43,-1) 34(3.43,-0.6) 35(3.43,-0.2) 36(3.43,0.2) 37(3.43,0.6) 38(3.43,1) 39(3.43,1.4) 40(3.43,1.8) 41(3.43,2.2) 42(3.43,2.6)
  rrect50% 0.2x0.86 smd mask+0.05: 15(-2.6,-3.43) 16(-2.2,-3.43) 17(-1.8,-3.43) 18(-1.4,-3.43) 19(-1,-3.43) 20(-0.6,-3.43) 21(-0.2,-3.43) 22(0.2,-3.43) 23(0.6,-3.43) 24(1,-3.43) 25(1.4,-3.43) 26(1.8,-3.43) 27(2.2,-3.43) 28(2.6,-3.43) 43(2.6,3.43) 44(2.2,3.43) 45(1.8,3.43) 46(1.4,3.43) 47(1,3.43) 48(0.6,3.43) 49(0.2,3.43) 50(-0.2,3.43) 51(-0.6,3.43) 52(-1,3.43) 53(-1.4,3.43) 54(-1.8,3.43) 55(-2.2,3.43) 56(-2.6,3.43)
  rect 4.9x4.9 smd paste-4.9 mask+0: 57(0,0)
  1-TOP region: -2.8,-2.8 -2.8,2.45 -2.45,2.8 2.8,2.8 2.8,-2.8 -2.8,-2.8
  silkscreen extent -4.04,3.08 -3.84,3.27, body extent -3.55,-3.55 3.55,3.55, height 0.8
QFN40P750X750X80-65T620N [mm] "Quad Flat No-Lead (QFN with Tab), 0.40 mm pitch; square, 16 pin X 16 pin, 7.50 mm L X 7.50 mm W X 0.80 mm H body"
  rrect50% 0.81x0.2 smd mask+0.05: 1(-3.705,3) 2(-3.705,2.6) 3(-3.705,2.2) 4(-3.705,1.8) 5(-3.705,1.4) 6(-3.705,1) 7(-3.705,0.6) 8(-3.705,0.2) 9(-3.705,-0.2) 10(-3.705,-0.6) 11(-3.705,-1) 12(-3.705,-1.4) 13(-3.705,-1.8) 14(-3.705,-2.2) 15(-3.705,-2.6) 16(-3.705,-3) 33(3.705,-3) 34(3.705,-2.6) 35(3.705,-2.2) 36(3.705,-1.8) 37(3.705,-1.4) 38(3.705,-1) 39(3.705,-0.6) 40(3.705,-0.2) 41(3.705,0.2) 42(3.705,0.6) 43(3.705,1) 44(3.705,1.4) 45(3.705,1.8) 46(3.705,2.2) 47(3.705,2.6) 48(3.705,3)
  rrect50% 0.2x0.81 smd mask+0.05: 17(-3,-3.705) 18(-2.6,-3.705) 19(-2.2,-3.705) 20(-1.8,-3.705) 21(-1.4,-3.705) 22(-1,-3.705) 23(-0.6,-3.705) 24(-0.2,-3.705) 25(0.2,-3.705) 26(0.6,-3.705) 27(1,-3.705) 28(1.4,-3.705) 29(1.8,-3.705) 30(2.2,-3.705) 31(2.6,-3.705) 32(3,-3.705) 49(3,3.705) 50(2.6,3.705) 51(2.2,3.705) 52(1.8,3.705) 53(1.4,3.705) 54(1,3.705) 55(0.6,3.705) 56(0.2,3.705) 57(-0.2,3.705) 58(-0.6,3.705) 59(-1,3.705) 60(-1.4,3.705) 61(-1.8,3.705) 62(-2.2,3.705) 63(-2.6,3.705) 64(-3,3.705)
  rect 5.5x5.5 smd paste-5.5 mask+0: 65(0,0)
  1-TOP region: -3.1,-3.1 -3.1,2.75 -2.75,3.1 3.1,3.1 3.1,-3.1 -3.1,-3.1
  silkscreen extent -4.53,2.9 -4.33,3.1, body extent -3.8,-3.8 3.8,3.8, height 0.8
QFN50P320X250X90-15T140X210N [mm] "Quad Flat No-Lead (QFN with Tab), 0.50 mm pitch; rect., 4 pin X 3 pin, 3.20 mm L X 2.50 mm W X 0.90 mm H body"
  rrect25% 0.7x0.27 smd mask+0.05: 1(-1.25,0.75) 2(-1.25,0.25) 3(-1.25,-0.25) 4(-1.25,-0.75) 8(1.25,-0.75) 9(1.25,-0.25) 10(1.25,0.25) 11(1.25,0.75)
  rrect25% 0.27x0.7 smd mask+0.05: 5(-0.5,-1.6) 6(0,-1.6) 7(0.5,-1.6) 12(0.5,1.6) 13(0,1.6) 14(-0.5,1.6)
  rect 1.4x2.1 smd paste-2.1 mask+0: 15(0,0)
  silkscreen extent -1.82,1.15 -1.63,1.35, body extent -1.3,-1.65 1.3,1.65, height 0.9
QFN50P600X600X100-37AN [mm]
  rrect50% 1.1x0.3 smd mask+0.05: 1(-2.8,2) 2(-2.8,1.5) 3(-2.8,1) 4(-2.8,0.5) 5(-2.8,0) 6(-2.8,-0.5) 7(-2.8,-1) 8(-2.8,-1.5) 9(-2.8,-2) 19(2.8,-2) 20(2.8,-1.5) 21(2.8,-1) 22(2.8,-0.5) 23(2.8,0) 24(2.8,0.5) 25(2.8,1) 26(2.8,1.5) 27(2.8,2)
  rrect50% 0.3x1.1 smd mask+0.05: 10(-2,-2.8) 11(-1.5,-2.8) 12(-1,-2.8) 13(-0.5,-2.8) 14(0,-2.8) 15(0.5,-2.8) 16(1,-2.8) 17(1.5,-2.8) 18(2,-2.8) 28(2,2.8) 29(1.5,2.8) 30(1,2.8) 31(0.5,2.8) 32(0,2.8) 33(-0.5,2.8) 34(-1,2.8) 35(-1.5,2.8) 36(-2,2.8)
  rect 3.8x3.8 smd: 37(0,0)
  silkscreen extent -3.63,2.53 -3.33,2.83, body extent -3.05,-3.05 3.05,3.05, height 1.01
QFN_MPS_MP2316 [mm]
  rect 0.75x0.25 smd mask+0.05: 1(-0.8,1)
  rect 0.7x0.25 smd mask+0.05: 2(-0.8,0.5) 3(-0.8,0) 4(-0.8,-0.5) 5(-0.8,-1) 7(0.8,-1) 8(0.8,-0.5) 9(0.8,0) 10(0.8,0.5) 11(0.8,1)
  rect 0.25x0.7 smd mask+0.05: 6(0,-1.45) 12(0,1.45)
  rect 0.35x0.25 smd mask+0.05: 13(0,0.5) 14(0,0)
  silkscreen extent -1.8,0.9 -1.6,1.1, body extent -1,-1.5 1,1.5, height 1.01
QFP50P900X900X160-48N [mm]
  rect 1.49x0.28 smd mask+0.051: 1(-4.17,2.75)
  rrect50% 1.49x0.28 smd mask+0.051: 2(-4.17,2.25) 3(-4.17,1.75) 4(-4.17,1.25) 5(-4.17,0.75) 6(-4.17,0.25) 7(-4.17,-0.25) 8(-4.17,-0.75) 9(-4.17,-1.25) 10(-4.17,-1.75) 11(-4.17,-2.25) 12(-4.17,-2.75) 25(4.17,-2.75) 26(4.17,-2.25) 27(4.17,-1.75) 28(4.17,-1.25) 29(4.17,-0.75) 30(4.17,-0.25) 31(4.17,0.25) 32(4.17,0.75) 33(4.17,1.25) 34(4.17,1.75) 35(4.17,2.25) 36(4.17,2.75)
  rrect50% 0.28x1.49 smd mask+0.051: 13(-2.75,-4.17) 14(-2.25,-4.17) 15(-1.75,-4.17) 16(-1.25,-4.17) 17(-0.75,-4.17) 18(-0.25,-4.17) 19(0.25,-4.17) 20(0.75,-4.17) 21(1.25,-4.17) 22(1.75,-4.17) 23(2.25,-4.17) 24(2.75,-4.17) 37(2.75,4.17) 38(2.25,4.17) 39(1.75,4.17) 40(1.25,4.17) 41(0.75,4.17) 42(0.25,4.17) 43(-0.25,4.17) 44(-0.75,4.17) 45(-1.25,4.17) 46(-1.75,4.17) 47(-2.25,4.17) 48(-2.75,4.17)
  silkscreen extent -5.33,2.65 -5.14,2.85, body extent -4.5,-4.5 4.5,4.5, height 1.6
QFP50P1200X1200X120-65L30T320N [mm] "Quad Flat Pack (QFP with Tab), 0.50 mm pitch; square, 16 pin X 16 pin, 10.00 mm L X 10.00 mm W X 1.20 mm H body"
  rect 1.56x0.28 smd mask+0.05: 1(-5.68,3.75)
  rrect25% 1.56x0.28 smd mask+0.05: 2(-5.68,3.25) 3(-5.68,2.75) 4(-5.68,2.25) 5(-5.68,1.75) 6(-5.68,1.25) 7(-5.68,0.75) 8(-5.68,0.25) 9(-5.68,-0.25) 10(-5.68,-0.75) 11(-5.68,-1.25) 12(-5.68,-1.75) 13(-5.68,-2.25) 14(-5.68,-2.75) 15(-5.68,-3.25) 16(-5.68,-3.75) 33(5.68,-3.75) 34(5.68,-3.25) 35(5.68,-2.75) 36(5.68,-2.25) 37(5.68,-1.75) 38(5.68,-1.25) 39(5.68,-0.75) 40(5.68,-0.25) 41(5.68,0.25) 42(5.68,0.75) 43(5.68,1.25) 44(5.68,1.75) 45(5.68,2.25) 46(5.68,2.75) 47(5.68,3.25) 48(5.68,3.75)
  rrect25% 0.28x1.56 smd mask+0.05: 17(-3.75,-5.68) 18(-3.25,-5.68) 19(-2.75,-5.68) 20(-2.25,-5.68) 21(-1.75,-5.68) 22(-1.25,-5.68) 23(-0.75,-5.68) 24(-0.25,-5.68) 25(0.25,-5.68) 26(0.75,-5.68) 27(1.25,-5.68) 28(1.75,-5.68) 29(2.25,-5.68) 30(2.75,-5.68) 31(3.25,-5.68) 32(3.75,-5.68) 49(3.75,5.68) 50(3.25,5.68) 51(2.75,5.68) 52(2.25,5.68) 53(1.75,5.68) 54(1.25,5.68) 55(0.75,5.68) 56(0.25,5.68) 57(-0.25,5.68) 58(-0.75,5.68) 59(-1.25,5.68) 60(-1.75,5.68) 61(-2.25,5.68) 62(-2.75,5.68) 63(-3.25,5.68) 64(-3.75,5.68)
  rrect16% 3.3x3.3 smd paste-3.2 mask+0.1: 65(0,0)
  silkscreen extent -6.35,4.3 -6.15,4.5, body extent -6,-6 6,6, height 1.2
RESC0603X28N [mm]
  rrect32% 0.37x0.4 smd mask+0.102: 1(-0.285,0) 2(0.285,0)
  body extent -0.3,-0.15 0.3,0.15, height 0.28
RESC1005X40N [mm]
  rrect25% 0.57x0.62 smd mask+0.05: 1(-0.48,0) 2(0.48,0)
  body extent -0.5,-0.25 0.5,0.25, height 0.4
RESC1609X55N [mm]
  rect 0.9x1 smd mask+0.05: 1(-0.8,0) 2(0.8,0)
  body extent -0.87,-0.48 0.87,0.48, height 0.55
RESC3225X60N [mm]
  rect 1.1x2.7 smd: 1(-1.5,0) 2(1.5,0)
  body extent -1.7,-1.35 1.7,1.35, height 0.6
SAMTEC_FTSH-105-01-F-DV [mil]
  rect 110x29 smd: 1(-80,100) 2(80,100) 3(-80,50) 4(80,50) 5(-80,0) 6(80,0) 7(-80,-50) 8(80,-50) 9(-80,-100) 10(80,-100)
  silkscreen extent -175,90 -155,110, body extent -115,-208 115,208, height 325
SAMTEC_SMM-110-02-F-S [mm]
  rect 0.8x2.35 smd: 1(-9,-1.425) 2(-7,1.425) 3(-5,-1.425) 4(-3,1.425) 5(-1,-1.425) 6(1,1.425) 7(3,-1.425) 8(5,1.425) 9(7,-1.425) 10(9,1.425)
  silkscreen extent -10.18,-1.74 -9.85,-1.41, body extent -9.99,-2.16 10,2.16, height 4.83
SAMTEC_TSW-108-07-X-S [mil]
  rect 74x74 hole 45: 1(-350,0)
  round 74 hole 45: 2(-250,0) 3(-150,0) 4(-50,0) 5(50,0) 6(150,0) 7(250,0) 8(350,0)
  silkscreen extent -429,-8 -413,8, body extent -400,-50 400,50, height 330
SAMTEC_TSW-110-26-L-D [mil] "150.08"
  rrect20% 70x70 hole 42: 1(-450,-50)
  round 70 hole 42: 2(-450,50) 3(-350,-50) 4(-350,50) 5(-250,-50) 6(-250,50) 7(-150,-50) 8(-150,50) 9(-50,-50) 10(-50,50) 11(50,-50) 12(50,50) 13(150,-50) 14(150,50) 15(250,-50) 16(250,50) 17(350,-50) 18(350,50) 19(450,-50) 20(450,50)
  silkscreen extent -545,-60 -526,-40, body extent -500,-100 500,100, height 330
SAMTEC_TSW-112-26-L-D [mil] "AREA -179.25"
  rrect20% 70x70 hole 42: 1(-550,-50)
  round 70 hole 42: 2(-550,50) 3(-450,-50) 4(-450,50) 5(-350,-50) 6(-350,50) 7(-250,-50) 8(-250,50) 9(-150,-50) 10(-150,50) 11(-50,-50) 12(-50,50) 13(50,-50) 14(50,50) 15(150,-50) 16(150,50) 17(250,-50) 18(250,50) 19(350,-50) 20(350,50) 21(450,-50) 22(450,50) 23(550,-50) 24(550,50)
  silkscreen extent -648,-60 -628,-40, body extent -600,-100 600,100, height 330
SODFL1006X43AN12 [mm]
  rrect25% 0.43x0.32 smd: 1(-0.55,0) 2(0.55,0)
  body extent -0.5,-0.3 0.5,0.3, height 0.4
SODFL1006X43N12 [mm]
  rect 0.32x0.43 smd: 1(-0.55,0) 2(0.55,0)
  body extent -0.58,-0.33 0.58,0.33, height 0.4
SODFL2513X80N [mm]
  rrect25% 0.97x0.57 smd: A(1.07,0)
  rrect25% 0.97x0.6 smd: K(-1.07,0)
  silkscreen extent -1.8,0.5 -1.6,0.7, body extent -1.25,-0.63 1.25,0.63, height 0.8
SOIC127P600X175-8N [mm]
  rect 1.97x0.6 smd mask+0.05: 1(-2.47,1.915) 2(-2.47,0.645) 3(-2.47,-0.625) 4(-2.47,-1.895) 5(2.47,-1.895) 6(2.47,-0.625) 7(2.47,0.645) 8(2.47,1.915)
  silkscreen extent -2.8,2.55 -2.55,2.8, body extent -3.1,-2.48 3.1,2.52, height 1.75
SOIC127P600X175-14N [mm]
  rrect50% 1.97x0.6 smd: 1(-2.47,3.81) 2(-2.47,2.54) 3(-2.47,1.27) 4(-2.47,0) 5(-2.47,-1.27) 6(-2.47,-2.54) 7(-2.47,-3.81) 8(2.47,-3.81) 9(2.47,-2.54) 10(2.47,-1.27) 11(2.47,0) 12(2.47,1.27) 13(2.47,2.54) 14(2.47,3.81)
  silkscreen extent -3.91,4.35 -3.71,4.54, body extent -3,-4.33 3,4.33, height 1.75
SOIC254P991X420-8N [mm]
  rrect25% 2.44x1.3 smd mask+0.05: 1(-4.3,3.81) 2(-4.3,1.27) 3(-4.3,-1.27) 4(-4.3,-3.81) 5(4.3,-3.81) 6(4.3,-1.27) 7(4.3,1.27) 8(4.3,3.81)
  silkscreen extent -4.4,4.85 -4.1,5.15, body extent -3.35,-5.75 3.5,5.75, height 4.2
SON50P120X160X60-5T55X91N [mm] "Small Outline No-Lead (SON with Tab), 0.50 mm pitch; 4 pin, 1.20 mm L X 1.60 mm W X 0.60 mm H body"
  rrect52% 0.67x0.27 smd mask+0.051: 1(-0.81,0.25) 2(-0.81,-0.25) 3(0.81,-0.25) 4(0.81,0.25)
  rect 0.55x0.91 smd paste-0.099 mask+0.025: 5(0,0)
  silkscreen extent -1.56,0.15 -1.37,0.35, body extent -0.85,-0.6 0.85,0.6, height 0.6
SON50P300X200X80-9N [mm]
  rect 0.3x0.8 smd: 1(-0.75,-1.45) 2(-0.25,-1.45) 3(0.25,-1.45) 4(0.75,-1.45) 5(0.75,1.45) 6(0.25,1.45) 7(-0.25,1.45) 8(-0.75,1.45)
  rect 1.6x1.6 smd: 9(0,0)
  silkscreen extent -1.46,-1.58 -1.25,-1.37, body extent -1.05,-1.55 1.05,1.55, height 0.8
SON50P300X300X80-11T164X238N [mm] "Small Outline No-Lead (SON with Tab), 0.50 mm pitch; 10 pin, 3.00 mm L X 3.00 mm W X 0.80 mm H body"
  rect 0.83x0.26 smd mask+0.065: 1(-1.44,1) 2(-1.44,0.5) 3(-1.44,0) 4(-1.44,-0.5) 5(-1.44,-1) 6(1.44,-1) 7(1.44,-0.5) 8(1.44,0) 9(1.44,0.5) 10(1.44,1)
  rect 1.646x1.984 smd paste-1.984 mask+0: 11(0,0)
  1-TOP region: 0,-1.192 -0.623,-1.192 -0.654,-1.189 -0.685,-1.182 -0.714,-1.17 -0.741,-1.154 -0.764,-1.133 -0.785,-1.11 -0.801,-1.083 -0.813,-1.054 -0.82,-1.023 -0.823,0.992 -0.623,1.192 0.623,1.192 0.654,1.189 0.685,1.182 0.714,1.17 0.741,1.154 0.764,1.133 0.785,1.11 0.801,1.083 0.813,1.054 0.82,1.023 0.823,-0.992 0.82,-1.023 0.813,-1.054 0.801,-1.083 0.785,-1.11 0.764,-1.133 0.741,-1.154 0.714,-1.17 0.685,-1.182 0.654,-1.189 0.623,-1.192 0,-1.192
  silkscreen extent -2.27,0.9 -2.08,1.1, body extent -1.55,-1.5 1.55,1.5, height 0.8
SON95P300X300X80-7N [mm]
  rect 0.4x1 smd: 1(-0.95,-1.4) 2(0,-1.4) 3(0.95,-1.4) 4(0.95,1.4) 5(0,1.4) 6(-0.95,1.4)
  rect 2x1.3 smd: 7(0,0)
  silkscreen extent -1.52,-1.97 -1.38,-1.83, body extent -1.58,-1.58 1.58,1.58, height 0.8
SOP50P490X110-10L30N [mm] "Small Outline Pkg (SOP), 0.50 mm pitch; 10 pin, 3.00 mm L X 3.00 mm W X 1.10 mm H body"
  rrect50% 1.45x0.28 smd mask+0.05: 1(-2.16,1) 2(-2.16,0.5) 3(-2.16,0) 4(-2.16,-0.5) 5(-2.16,-1) 6(2.16,-1) 7(2.16,-0.5) 8(2.16,0) 9(2.16,0.5) 10(2.16,1)
  silkscreen extent -2.8,1.5 -2.6,1.7, body extent -2.45,-1.5 2.45,1.5, height 1.1
SOP50P640X120-38N [mm]
  rect 1.5x0.3 smd: 1(-2.9,4.5) 2(-2.9,4) 3(-2.9,3.5) 4(-2.9,3) 5(-2.9,2.5) 6(-2.9,2) 7(-2.9,1.5) 8(-2.9,1) 9(-2.9,0.5) 10(-2.9,0) 11(-2.9,-0.5) 12(-2.9,-1) 13(-2.9,-1.5) 14(-2.9,-2) 15(-2.9,-2.5) 16(-2.9,-3) 17(-2.9,-3.5) 18(-2.9,-4) 19(-2.9,-4.5) 20(2.9,-4.5) 21(2.9,-4) 22(2.9,-3.5) 23(2.9,-3) 24(2.9,-2.5) 25(2.9,-2) 26(2.9,-1.5) 27(2.9,-1) 28(2.9,-0.5) 29(2.9,0) 30(2.9,0.5) 31(2.9,1) 32(2.9,1.5) 33(2.9,2) 34(2.9,2.5) 35(2.9,3) 36(2.9,3.5) 37(2.9,4) 38(2.9,4.5)
  silkscreen extent -3.11,5.12 -2.89,5.34, body extent -3.3,-4.9 3.3,4.9, height 1.1
SOP65P640X120-20N [mm]
  rect 1.5x0.45 smd mask+0.05: 1(-2.9,2.925) 2(-2.9,2.275) 3(-2.9,1.625) 4(-2.9,0.975) 5(-2.9,0.325) 6(-2.9,-0.325) 7(-2.9,-0.975) 8(-2.9,-1.625) 9(-2.9,-2.275) 10(-2.9,-2.925) 11(2.9,-2.925) 12(2.9,-2.275) 13(2.9,-1.625) 14(2.9,-0.975) 15(2.9,-0.325) 16(2.9,0.325) 17(2.9,0.975) 18(2.9,1.625) 19(2.9,2.275) 20(2.9,2.925)
  silkscreen extent -3.05,3.56 -2.79,3.81, body extent -3.2,-3.25 3.2,3.25, height 1.2
SOT65P210X100-3AN [mm]
  rect 0.5x1 smd: 1(-0.65,-1.1) 2(0.65,-1.1) 3(0,1.1)
  body extent -1.2,-1.12 1.2,1.12, height 1
SOT95P240X110_AXK-3N [mm]
  rect 0.65x1.05 smd: A(-0.95,-1.15) K(0,1.15) X(0.95,-1.15)
  body extent -1.46,-1.2 1.46,1.2, height 1.1
SOT95P240X110_GSD-3N [mm]
  rect 0.65x1.05 smd: D(0,1.15) G(-0.95,-1.15) S(0.95,-1.15)
  body extent -1.46,-1.2 1.46,1.2, height 1.1
SOT95P280X145-5N [mm]
  rrect50% 1.36x0.6 smd: 1(-1.18,0.95) 2(-1.18,0) 3(-1.18,-0.95) 4(1.18,-0.95) 5(1.18,0.95)
  silkscreen extent -2.26,1.42 -2.06,1.62, body extent -1.4,-1.45 1.4,1.45, height 1.45
SOTFL50P160X60-6N [mm]
  rrect53% 0.56x0.3 smd mask+0.05: 1(-0.78,0.5) 2(-0.78,0) 3(-0.78,-0.5) 4(0.78,-0.5) 5(0.78,0) 6(0.78,0.5)
  silkscreen extent -1.35,-0.85 0.5,1.1, body extent -0.8,-0.8 0.8,0.8, height 0.6
SOTFL50P160X80_GSD-3N [mm]
  rect 0.4x0.77 smd: D(0,0.69) G(-0.5,-0.69) S(0.5,-0.69)
  body extent -0.85,-0.85 0.85,0.85, height 0.8
SW_KSC221J [mm]
  rect 1x2.8 smd: 1(2,2.9) 2(2,-2.9) 3(-2,2.9) 4(-2,-2.9)
  body extent -3.1,-3.4 3.1,3.4, height 3.5
TC_TC2050-IDC-NL [mil]
  round 31 smd paste-50: 1(-100,-25) 2(-50,-25) 3(0,-25) 4(50,-25) 5(100,-25) 6(100,25) 7(50,25) 8(0,25) 9(-50,25) 10(-100,25)
  round 0 hole 39 unplated mask+4: MT1(-150,0) MT2(150,40) MT3(150,-40)
TE_640456-2 [mm] "CONN HEADER VERT 2POS .100 TIN"
  rect 1.5x1.5 hole 1.02: 1(-1.27,0)
  round 1.5 hole 1.02: 2(1.27,0)
  silkscreen extent -3.35,-0.25 -2.95,0.15, body extent -2.54,-3.14 2.54,2.7, height 10.03
TP0762 [mil] "30mil SMT Round Testpoint"
  round 30 smd paste-100: 1(0,0)
XMULTIPLE_XMG-J1B211 [mil]
  rect 60x60 hole 35 mask+4: 1(-225,350)
  round 60 hole 35 mask+4: 2(-175,250) 3(-125,350) 4(-75,250) 5(-25,350) 6(25,250) 7(75,350) 8(125,250) 9(175,350) 10(225,250)
  round 76 hole 47 mask+4: D1(-261.61,-160) D2(-161.22,-160) D3(161.61,-160) D4(262.01,-160)
  round 0 hole 127.95 unplated mask+4: MNT1(-225,0) MNT2(225,0)
  round 100 hole 63 mask+4: SHLD1(-309.25,120) SHLD2(309.25,120)
  body extent -394,-423 394,417, height 612
"XTAL_ XT9M20HRR" [mm]
  rect 5.55x2.05 smd: 1(-4.775,0) 2(4.775,0)
  body extent -6.15,-2.35 6.15,2.35, height 4.5
XTAL_C3E-3427 [mm]
  rect 1.4x1.15 smd: 1(-1.1,-0.8) 2(1.1,-0.8) 3(1.1,0.8) 4(-1.1,0.8)
  body extent -1.7,-1.35 1.7,1.35, height 0.75

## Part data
C1 C11 C12 C19 C188 C192: library part 1000998, "CAP CER 22UF 10V 20% X5R 0603", Manufacturer=Samsung, Manufacturer_Alt_1="TDK Corporation", Manufacturer_Alt_1_Part_Number=C1608X5R1A226M080AC, Manufacturer_Part_Number=CL10A226MP8NUNE, Package_Type=0603, Temp_Coef=X5R, Tolerance=20, Voltage=10V
C2 C14 C47 C48 C49 C187 C191: library part 1001196, "CAP TANT 100UF 6.3V 20% 1206", Manufacturer=Rohm, Manufacturer_Part_Number=TCTAL0J107M8R, Package_Type=3216, Tolerance=20%, Voltage=6.3V
C3 C10 C37 C40 C43 C66 C68 C82 C88 C94 C97 C99 C102 C104 C106 C108 C128 C129 C132 C143 C164 C171 C186 C190 C196: library part 1001168, "CAP CER 10UF 10V 20% X5R 0402", Manufacturer=Samsung, Manufacturer_Part_Number=CL05A106MP5NUNC, Package_Type=0402, Temp_Coef=X5R, Tolerance=20%, Voltage=10V
C4 C71 C73 C74 C109 C111 C126 C127 C141 C160 C163 C165 C166 C167 C168 C170 C172 C173 C194: library part 1001167, "CAP CER 1UF 10V 10% X5R 0402", Manufacturer=Murata, Manufacturer_Part_Number=GRM155R61A105KE15D, Package_Type=0402, Temp_Coef=X5R, Tolerance=10%, Voltage=10V
C5 C21 C31 C32: library part 1000007, "CAP 47pF 50V 5% NP0 0402", Manufacturer=Murata, Manufacturer_Alt_1="AVX Corporation", Manufacturer_Alt_1_Part_Number=04025A470JAT2A, Manufacturer_Part_Number=GRM1555C1H470JA01D, Package_Type=0402, Temp_Coef="C0G, NP0"
C6 C29 C169 C198: library part 1001303, "CAP CER 2.2UF 16V 10% X5R 0603", Manufacturer="TDK Corporation", Manufacturer_Part_Number=C1608X5R1C225K080AB, Package_Type=0603, Tolerance=10%, Voltage=16V
C7 C30 C145 C146 C147 C149 C150 C154 C156 C185 C197: library part 1000073, "CAP CER 1UF 6.3V 20% X5R 0402", Manufacturer=Murata, Manufacturer_Part_Number=GRM155R60J105ME19D, Package_Type=0402, Temp_Coef=X5R, Voltage=6.3V
C8: library part 1002775, "SMCAP, 0.47F 3.5V SUPERCAP 8.5x10.5x10.8mm SMT", Manufacturer=NIC
C9 C13 C20 C26 C27 C28 C35 C36 C38 C39 C41 C42 C44 C45 C46 C50 C51 C52 C53 C54 C55 C56 C59 C60 C61 C65 C67 C69 C70 C72 C75 C76 C79 C80 C81 C83 C84 C89 C90 C91 C92 C93 C95 C96 C98 C100 C101 C103 C105 C107 C110 C112 C113 C114 C115 C116 C117 C118 C119 C120 C121 C122 C123 C130 C131 C133 C134 C135 C136 C137 C138 C139 C142 C144 C159 C161 C175 C177 C180 C181 C182 C183 C184 C189 C193 C195: library part 1000006, "CAP 100nF 16V 10% X7R 0402", Manufacturer=Murata, Manufacturer_Part_Number=GRM155R71C104KA88D, Package_Type=0402, Tolerance=10
C15 C16 C17 C18 C178 C179: library part 1000111, "CAP CER 10UF 16V 10% X5R 0805", Manufacturer=Murata, Manufacturer_Part_Number=GRM21BR61C106KE15L, Package_Type=0805, Temp_Coef=X5R, Tolerance=10, Voltage=16V
C22: library part 1000110, "CAP CER 1UF 25V 10% X5R 0603", Manufacturer=Murata, Manufacturer_Alt_1="AVX Corporation", Manufacturer_Alt_1_Part_Number=TMK107BJ105KA-T, Manufacturer_Part_Number=GRM188R61E105KA12D, Package_Type=0603, Temp_Coef=X5R, Tolerance=10%, Voltage=25V
C23: library part 1000512, "CAP CER 0.015UF 16V 10% X7R 0402", Manufacturer=Murata, Manufacturer_Part_Number=GRM155R71C153KA01D, Package_Type=0402, Temp_Coef=X7R, Tolerance=10%, Voltage=16V
C24 C25 C77 C78: library part 1001883, "CAP CER 0.22UF 6.3V X7R 0402", Manufacturer="Taiyo Yuden", Manufacturer_Part_Number=JMK105B7224KV-F, Package_Type=0402, Tolerance=10%, Voltage=6.3V
C33 C34: library part 1002726, "CAP CER 20PF 50V C0G/NP0 0603", Manufacturer=Murata, Manufacturer_Part_Number=GRM1885C1H200JA01D, Package_Type=0603, Temp_Coef="C0G, NP0", Tolerance=5%, Voltage=50V
C57 C58 C148 C151 C152 C153 C155 C157: library part 1001541, "CAP CER 10PF 50V 5% NP0 0402", Manufacturer=Murata, Manufacturer_Part_Number=GRM1555C1H100JA01D, Package_Type=0402, Temp_Coef="C0G, NP0", Tolerance=5, Voltage=50V
C62 C63 C85 C86: library part 1001166, "CAP CER 22PF 50V 5% NP0 0402", Manufacturer=Murata, Manufacturer_Part_Number=GRM1555C1H220JA01D, Package_Type=0402, Temp_Coef="C0G, NP0", Tolerance=5%, Voltage=50V
C64 C87 C140 C158 C162: library part 1002727, "CAP CER 2200PF 50V X7R 5% 0603", Manufacturer=Kemet, Manufacturer_Part_Number=C0603C222J5RACTU, Package_Type=0603, Temp_Coef=X7R, Tolerance=5%, Voltage=50V
C124 C125: library part 1002646, "CAP CER 33PF 50V C0G/NP0 0402", Manufacturer=Murata, Manufacturer_Part_Number=GCM1555C1H330JA16D, Package_Type=0402, Tolerance=5%, Voltage=50
C174 C176: library part 1000566, "CAP CER 100UF 10V 20% X5R 1206", Manufacturer="TDK Corporation", Manufacturer_Part_Number=C3216X5R1A107M, Package_Type=1206, Temp_Coef=X5R, Tolerance=20%, Voltage=10V
D1 D4 D6 D11: library part 1001189, "LED GREEN 573NM 1208 SMD", Manufacturer=Dialight, Package_Type=SMT
D2: library part 1002592, "DIODE SCHOTTKY 30V 30MA SMINI2", Manufacturer="Panasonic - ECG", Package_Type=SODFL
D3: library part 1000794, "DIODE SCHOTTKY 30V 200MA SOT323", Manufacturer="Fairchild Semiconductor", Manufacturer Alt 1=none, Manufacturer Part Num=0082610201, Package_Type=SOT323, Part Number=SDS1920004
D5 D7 D10: library part 1001188, "LED YELLOW 588NM 1208 SMD", Manufacturer=Dialight, Package_Type=SMT
D8: library part 1001169, "DIODE SCHOTTKY 30V 0.2A SOT23-3", Manufacturer="Fairchild Semiconductor", Package_Type=SMT
D9 D21: library part 1001264, "TVS DIODE 5VWM SOD923", Manufacturer="On Semiconductor", Package_Type=SMT
D12: library part 1001190, "LED RED 653NM 20MA 1208 SMD", Manufacturer=Dialight, Package_Type=SMT
D13 D14 D15 D16 D17 D18 D19 D20: library part 1001637, "TVS DIODE 3.3VWM SOD923", Manufacturer="On Semiconductor", Package_Type=SMT
FIDUCIAL1 FIDUCIAL2 FIDUCIAL3 FIDUCIAL4 FIDUCIAL5 FIDUCIAL6: library part CAD0023, "40 Mil Round Fiducial", Package_Type=SMT
FIL1: library part 1002745, "FILTER LC(T) 22PF SMD", Manufacturer=Murata, Package_Type=1206
H1 H2 H3 H4: library part CAD0006, "NPTH for Tooling, 0.125in dia.", Package_Type=TH
J1: library part 1001105, "DC Power Jack", Manufacturer="Bobbintron Electrical Corp", Package_Type=TH
J2 J5: library part 1002003, "CONN HEADER VERT 2POS .100 TIN", Manufacturer="TE Connectivity", Package_Type=TH
J3 J6 J7 J8 J9 J23 J25 J36 J54: library part 1001128, "CONN HEADER 2POS .100\" SGL GOLD", Manufacturer=Samtec, Manufacturer_Part_Number=TSW-102-07-G-S, Package_Type=TH
J4: library part 1001136, "CONN HEADER 2POS 1.25MM VERT TIN", Manufacturer=Molex, Manufacturer_Part_Number=53047-0210, Package_Type=TH
J10 J13 J15: library part 1000027, "RF Connectors U.FL RECEPTACLE SMT GLD M CONTACT", Manufacturer=Hirose, Package_Type=SMT
J11 J14 J51: library part 1002720, "CONN SMA JACK R/A 50 OHM L15.1MM PCB TH", Manufacturer="Bobbintron Electrical Corp", Package_Type=TH
J12 J20 J22: library part 1000034, "CONN HEADER 10POS DUAL .05\" SMD", Manufacturer=Samtec, Package_Type=SMT
J16 J34 J35: library part 1001117, "CONN RECEPT MICRO-USB TYPE AB R/A", Manufacturer=KYCON, Package_Type=SMT
J17 J28 J43: library part 1002721, "CONN HEADER VERT 6POS 2.54MM", Manufacturer=Molex, Package_Type=TH
J18: library part 1001118, "CONN TRANSFLSH R/A PUSH-PUSH SMD", Manufacturer=Molex, Package_Type=SMT
J19: library part 1001130, "SMCONN,MINI PCI EXP, 6.8MM HT", Manufacturer=Foxconn, Manufacturer_Part_Number=AS0B226-S68Q-7H, Package_Type=SMT
J21: library part 1001120, "MEMORY CARD 6POS PUSH/PULL SMD", Manufacturer=Molex, Package_Type=SMT
J24 J26: library part 1002743, "CONN HEADER VERT 4POS 2.54MM", Manufacturer=Semtech, Manufacturer_Part_Number=TSW-104-14-G-S, Package_Type=TH
J27: library part 1002612, "CONN MAGJACK 1PORT 1000 BASE-T IND", Manufacturer=XMultiple, Manufacturer_Part_Number=XMG-J1B2211NPA-1-DIG, Package_Type=TH
J29 J30: library part 1001866, "CONN FFC FPC VERT 15POS 1MM SMD", Manufacturer=FCI, Package_Type=SMT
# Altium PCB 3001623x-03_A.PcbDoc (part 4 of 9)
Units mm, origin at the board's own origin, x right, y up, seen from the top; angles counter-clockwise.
Board outline 210 x 130 mm, 9 copper layers (1-TOP, 2-GND, 3-INTOP, 4-PWR, 5-PWR, 6-INBOT, Signal_4, 7-GND, 8-BOTTOM), stack 1.979 mm thick; 755 components, 650 nets, 2980 pads, 2365 vias.

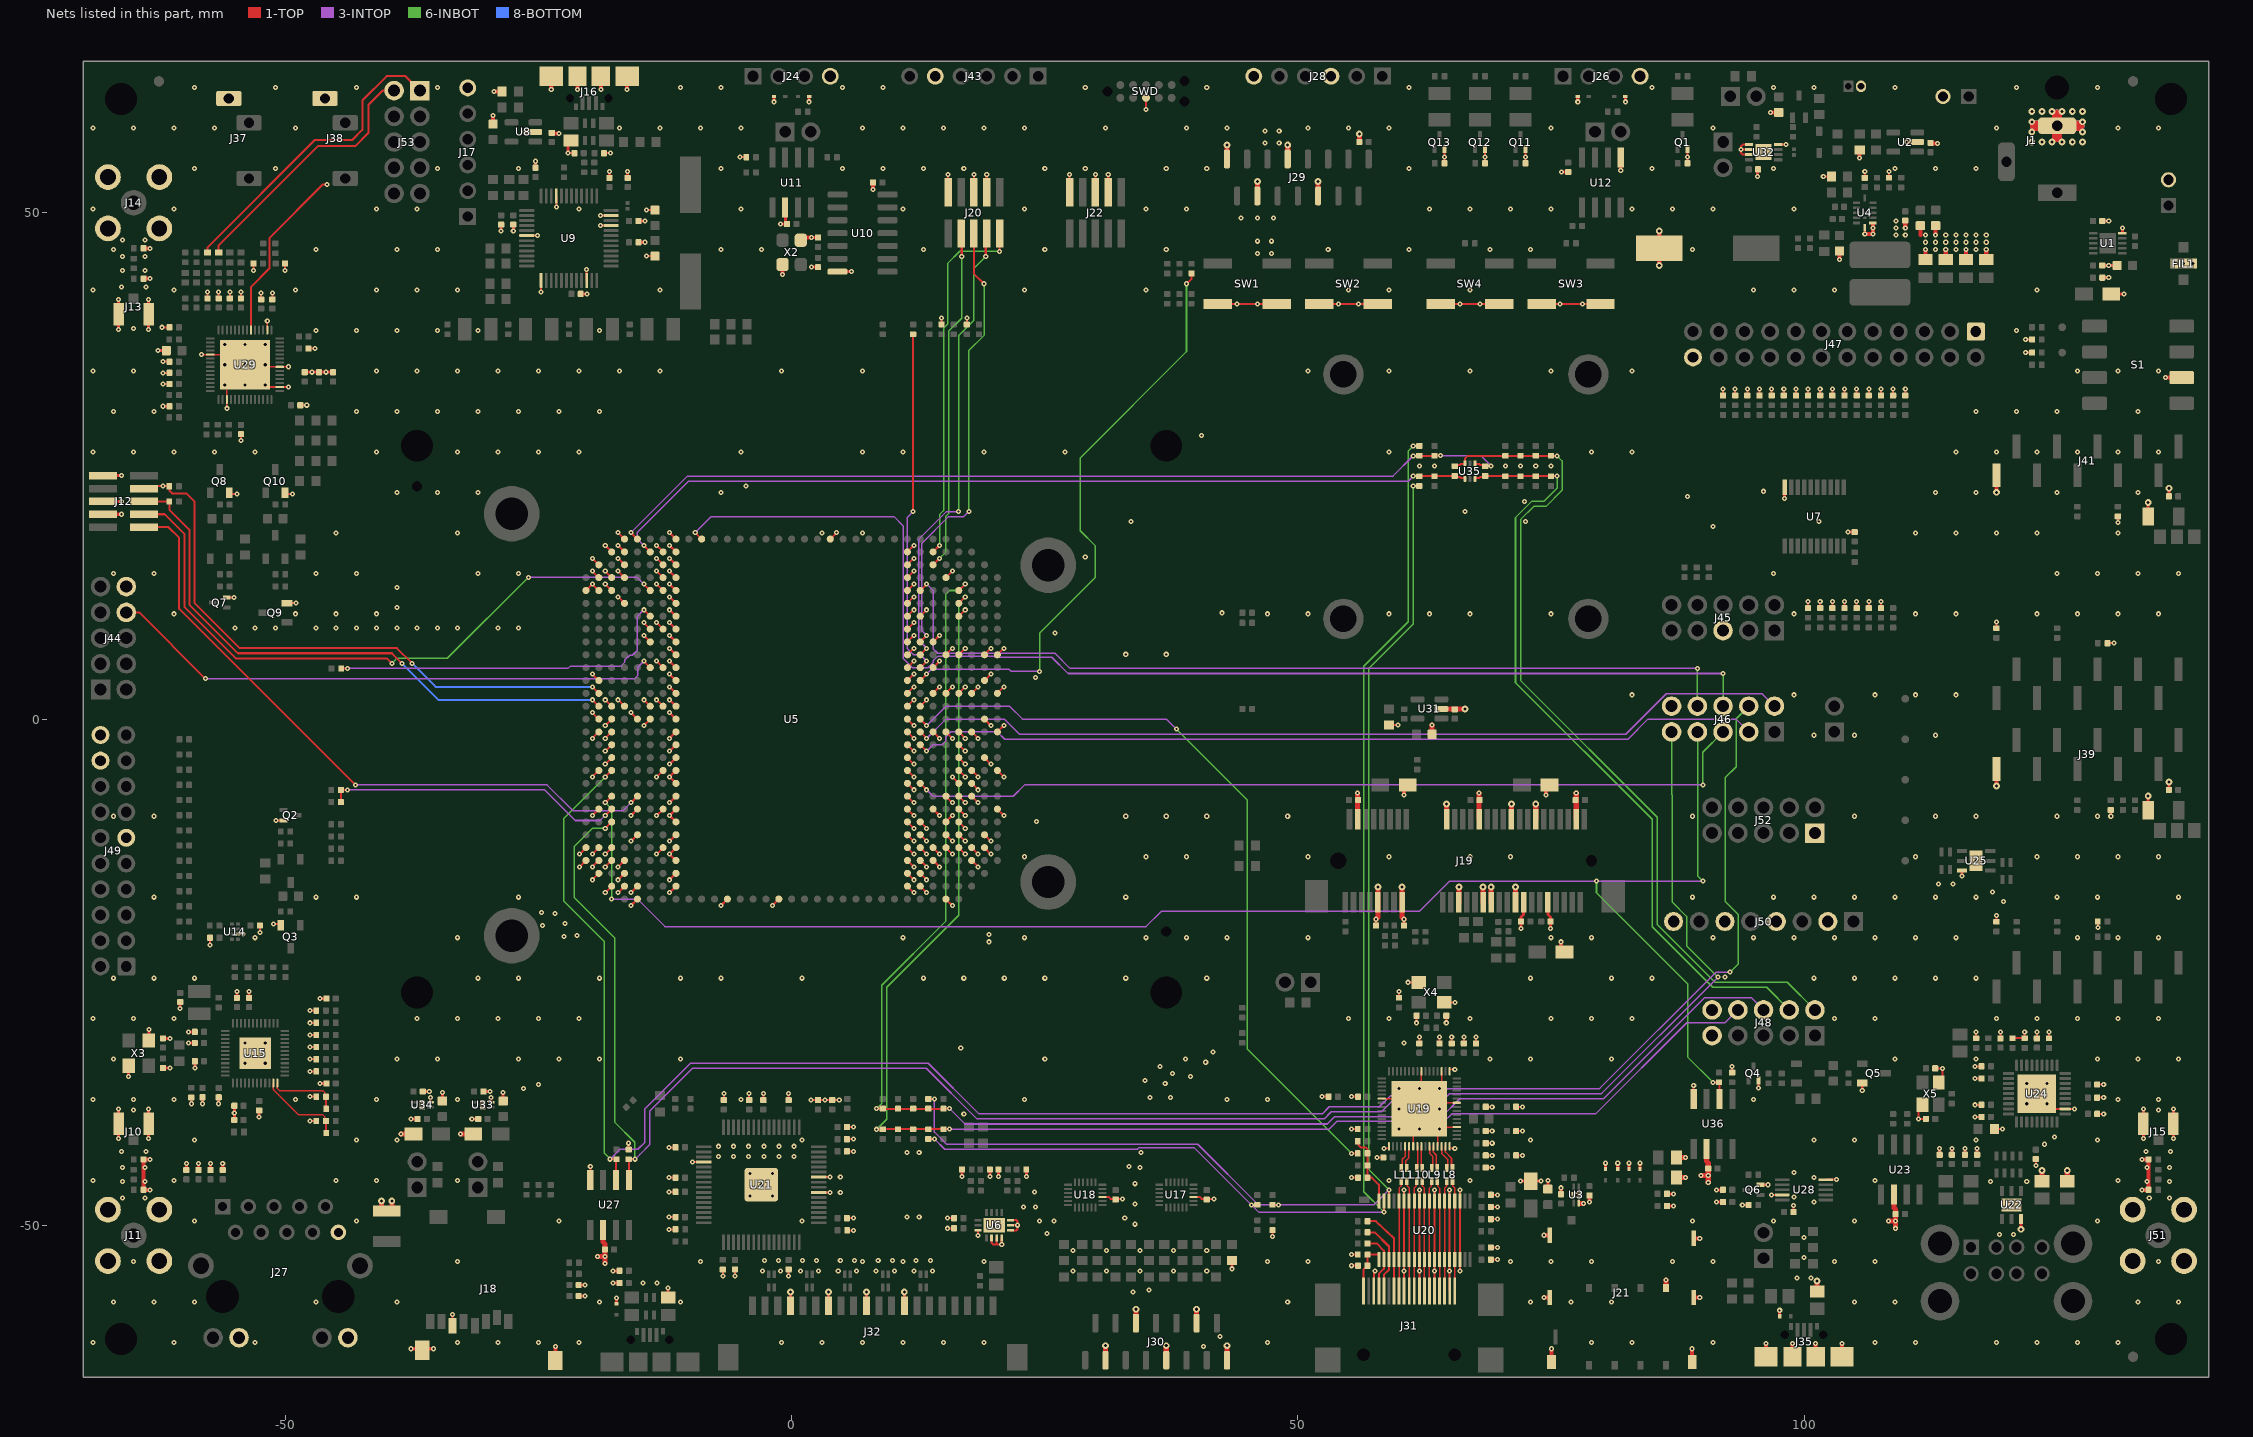
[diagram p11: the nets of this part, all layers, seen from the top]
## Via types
v1: diameter 0.5, hole 0.2, 1-TOP to 8-BOTTOM, 1743 vias
v2: diameter 0.5/0.5/0.5/0.5/0.5 (per signal layer), hole 0.2, 1-TOP to 8-BOTTOM, 440 vias
v3: diameter 0.68, hole 0.3, 1-TOP to 8-BOTTOM, 182 vias

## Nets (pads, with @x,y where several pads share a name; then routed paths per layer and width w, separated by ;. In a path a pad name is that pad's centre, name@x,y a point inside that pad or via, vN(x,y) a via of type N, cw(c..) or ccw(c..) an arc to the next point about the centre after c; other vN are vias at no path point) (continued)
GND: C1.1 C2.2 C3.1 C4.1 C5.1 C6.1 C7.1 C8.2 C10.1 C11.1 C12.1 C13.1 C14.2 C15.1 C16.1 C17.1 C18.1 C19.1 C20.1 C22.1 C23.1 C26.1 C27.1 C28.1 C29.1 C30.1 C31.1 C32.1 C33.1 C34.1 C35.1 C36.2 C37.1 C38.1 C39.1 C40.1 C41.1 C42.1 C43.1 C44.1 C47.2 C48.2 C49.2 C50.1 C51.1 C52.1 C53.1 C54.1 C55.2 C56.2 C57.1 C58.1 C59.1 C60.1 C61.1 C62.1 C63.1 C65.1 C66.1 C67.1 C68.1 C69.1 C70.1 C71.1 C72.1 C73.1 C74.1 C75.1 C76.1 C77.1 C78.1 C79.2 C80.2 C81.1 C82.1 C83.1 C84.1 C85.1 C86.1 C88.1 C89.1 C90.1 C91.1 C92.1 C93.1 C94.1 C95.1 C96.1 C97.1 C98.1 C99.1 C100.1 C101.1 C102.1 C103.1 C104.1 C105.1 C106.1 C107.1 C108.1 C109.1 C110.2 C111.1 C112.1 C113.1 C114.1 C115.1 C116.1 C117.1 C118.1 C119.1 C120.1 C121.1 C122.1 C123.1 C124.2 C125.2 C126.2 C127.1 C128.1 C129.1 C130.1 C131.1 C132.1 C133.1 C134.1 C135.1 C136.1 C137.1 C138.1 C139.1 C141.1 C142.1 C143.1 C144.2 C145.2 C148.2 C151.2 C152.2 C153.2 C155.2 C157.2 C159.1 C161.1 C163.1 C164.1 C165.2 C166.2 C167.2 C168.1 C169.1 C170.1 C171.1 C172.2 C173.2 C174.1 C175.1 C176.1 C177.1 C178.1 C179.1 C180.1 C181.1 C182.1 C183.1 C184.1 C185.1 C186.1 C187.2 C188.1 C189.1 C190.1 C191.2 C192.1 C193.1 C194.1 C195.1 C196.1 C197.1 C198.1 D9.1 D13.1 D14.1 D15.1 D16.1 D17.1 D18.1 D19.1 D20.1 D21.1 FIL1.2 J1.2 J2.2 J4.2 J5.2 J10.2 J10.3 J11.2 J11.3 J11.4 J11.5 J12.4 J12.6 J12.10 J13.2 J13.3 J14.2 J14.3 J14.4 J14.5 J15.2 J15.3 J16.6 J16.7 J16.8 J16.9 J17.6 J18.6 J18.11 J18.12 J19.4 J19.9 J19.15 J19.18 J19.21 J19.26 J19.27 J19.29 J19.34 J19.35 J19.37 J19.40 J19.43 J19.50 J20.3 J20.5 J20.9 J21.5 J21.11 J21.12 J21.13 J21.14 J21.15 J21.16 J22.3 J22.5 J22.9 J24.4 J26.4 J27.10 J27.D2 J27.D4 J28.3 J28.6 J29.6 J29.9 J29.12 J29.15 J30.3 J30.6 J30.9 J30.12 J30.15 J31.2 J31.5 J31.8 J31.11 J31.17 J32.4 J32.7 J32.10 J32.13 J35.6 J35.7 J35.8 J35.9 J37.1 J38.1 J39.10 J41.10 J43.5 J44.10 J45.5 J46.10 J47.1 J47.24 J48.9 J48.10 J49.11 J49.18 J49.20 J50.2 J50.4 J50.6 J50.8 J51.2 J51.3 J51.4 J51.5 J52.1 L4.2 L23.1 L24.1 L29.1 L31.2 Q1.S Q2.S Q3.S Q4.S Q5.S Q6.S Q7.S Q8.S Q9.S Q10.S Q11.S Q12.S Q13.S R11.2 R17.1 R26.1 R27.1 R54.1 R55.1 R61.1 R62.1 R73.1 R74.1 R75.2 R76.2 R78.2 R80.1 R82.1 R84.1 R101.2 R102.2 R103.2 R104.2 R105.2 R106.2 R107.2 R108.2 R109.2 R110.2 R111.2 R112.2 R113.2 R114.2 R115.2 R116.2 R125.1 R126.1 R127.1 R128.1 R129.1 R130.1 R131.1 R140.1 R162.1 R163.1 R168.1 R180.1 R184.1 R194.1 R195.1 R196.1 R197.1 R198.1 R199.1 R200.1 R201.1 R202.1 R203.1 R228.2 R229.1 R230.1 R242.2 R243.1 R246.1 R251.2 R252.1 R253.1 R254.1 R255.1 R256.1 R264.1 R304.1 R307.1 R308.2 R309.1 R312.1 R313.2 R317.2 R318.2 R319.2 R322.1 R332.1 R337.2 R350.1 R358.1 S1.6 SW1.1 SW1.2 SW2.1 SW2.2 SW3.1 SW3.2 SW4.1 SW4.2 SWD.3 U1.5 U2.2 U3.2 U3.5 U4.1 U4.12 U5.A4 U5.A5 U5.A25 U5.AF2 U5.AF3 U5.AF4 U5.AF5 U5.AF6 U5.AF7 U5.AF8 U5.AF9 U5.AF10 U5.AF11 U5.AF12 U5.AF13 U5.AF14 U5.AF15 U5.AF16 U5.AF17 U5.AF18 U5.AF19 U5.AF20 U5.AF21 U5.AF22 U5.AF23 U5.AF24 U5.AF25 U5.AF26 U5.AF27 U5.AF28 U5.AG2 U5.AG3 U5.AG4 U5.AG5 U5.AG6 U5.AG7 U5.AG16 U5.AG23 U5.AH4 U5.AH5 U5.AH8 U5.AH14 U5.AH17 U5.AH19 U5.AH21 U5.AJ1 U5.AJ5 U5.AJ6 U5.AJ7 U5.AJ9 U5.AJ14 U5.AJ17 U5.AJ20 U5.AJ26 U5.AK5 U5.AK6 U5.AK7 U5.AK8 U5.AK9 U5.AK10 U5.AK11 U5.AK12 U5.AK13 U5.AK14 U5.AK17 U5.AK20 U5.AK23 U5.AL4 U5.AL5 U5.AL9 U5.AL10 U5.AL11 U5.AL14 U5.AL17 U5.AM5 U5.AM6 U5.AM12 U5.AM15 U5.AM18 U5.AM20 U5.AN8 U5.AN11 U5.AN14 U5.AN17 U5.AN20 U5.B3 U5.B4 U5.B5 U5.B8 U5.B11 U5.B14 U5.B15 U5.B18 U5.B25 U5.B26 U5.B27 U5.C2 U5.C4 U5.C5 U5.C12 U5.C13 U5.C14 U5.C15 U5.C16 U5.C25 U5.C26 U5.C28 U5.D2 U5.D3 U5.D4 U5.D16 U5.D24 U5.D26 U5.D27 U5.D28 U5.D29 U5.E1 U5.E2 U5.E6 U5.E8 U5.E15 U5.F15 U5.F16 U5.F21 U5.F22 U5.G5 U5.G8 U5.G11 U5.G16 U5.G19 U5.G22 U5.G25 U5.G26 U5.G27 U5.G28 U5.H2 U5.H3 U5.H4 U5.H5 U5.H6 U5.H7 U5.H8 U5.H9 U5.H10 U5.H11 U5.H12 U5.H13 U5.H14 U5.H15 U5.H16 U5.H17 U5.H18 U5.H19 U5.H20 U5.H21 U5.H22 U5.H23 U5.H24 U5.H25 U5.H26 U5.H27 U5.H28 U5.H29 U5.M1 U5.T1 U5.Y29 U6.2 U6.3 U6.4 U6.5 U6.6 U6.7 U6.14 U6.15 U7.10 U8.2 U9.9 U9.18 U9.25 U9.34 U9.45 U9.47 U10.7 U11.2 U12.5 U14.2 U15.49 U17.9 U18.9 U19.6 U19.17 U19.23 U19.29 U19.32 U19.36 U19.42 U19.49 U19.51 U19.56 U19.65 U20.3 U20.5 U20.8 U20.11 U20.14 U20.25 U20.28 U20.31 U20.34 U20.36 U21.23 U21.26 U21.52 U21.65 U22.3 U22.7 U23.6 U24.11 U24.37 U25.3 U25.7 U27.4 U27.6 U28.5 U28.9 U29.3 U29.16 U29.21 U29.30 U29.34 U29.47 U29.57 U31.2 U32.4 U32.5 U32.6 U32.7 U32.9 U33.2 U33.5 U34.2 U34.5 U36.4 U36.6 X2.2 X2.4 X3.2 X3.4 X4.2 X4.4 X5.2 X5.4 | length 655.9
  1-TOP w0.15: v1(-58.3,36) U29.47@-57.43,36 -56.5,36 ; v1(-55.8,30.7) U29.3@-55.8,31.57 -55.8,32.5 ; U29.34@-53.4,38.43 -53.4,39 ; U29.30@-51.8,38.43 v1(-51.8,39.3) ; -51.5,32.8 U29.16@-50.57,32.8 v1(-49.7,32.8) ; -51.5,34.8 U29.21@-50.57,34.8 v1(-49.7,34.8) ; U19.6@58.32,-37.5 U19.65@59.5,-37.5 ; v1(58.5,-42.4) U19.17@59,-42.4 ; U19.23@61.4,-42.205 61.4,-41.3 U19.65@61.4,-41 ; U19.65@62.2,-36 U19.56@62.2,-34.795 ; U19.29@63.8,-42.205 U19.65@63.8,-41 ; U19.65@64.2,-36 U19.51@64.2,-34.795 ; U19.65@64.5,-40.3 U19.36@65.705,-40.3 ; U19.65@64.5,-37.9 64.8,-37.9 U19.42@65.705,-37.9 ; U19.32@65,-42.4 v1(65.5,-42.4) ; U19.49@65,-34.6 v1(65.5,-34.6)
  1-TOP w0.2: J44.10@-65.73,13.08 J44.10@-65.58,13.08 ; v1(-62.2,38.7) C145.2@-61.46,38.7 ; v1(-62.1,30.9) C161.1@-61.46,30.9 ; v1(-62.1,33.1) C166.2@-61.46,33.1 ; v1(-62.1,34.2) C165.2@-61.46,34.2 ; v1(-62.1,35.3) C170.1@-61.46,35.3 ; v1(-59.3,-38) R194.1@-59.3,-37.36 ; C148.2@-57.7,41.56 v1(-57.7,42.2) ; v1(-57.46,-22.3) C61.1@-57.46,-21.6 ; C152.2@-56.6,41.56 v1(-56.6,42.2) ; Q7.S@-55.81,12 v1(-55.075,12) ; Q8.S@-55.55,22.25 v1(-54.8,22.25) ; C153.2@-55.5,41.56 v1(-55.5,42.2) ; U14.2@-54.7,-21.25 v1(-54.2,-21.25) ; v1(-54.4,27.5) C159.1@-54.4,28.14 ; C157.2@-54.4,41.56 v1(-54.4,42.2) ; -53.4,39 -53.4,42.7 -51.592,44.508 -51.592,47.515 -46.307,52.8 -46,52.8 v1(-45.9,52.8) ; v1(-53.16,44.3) C151.2@-53.16,45 ; v1(-52.54,-21.1) C60.1@-52.54,-20.4 ; C163.1@-52.4,41.46 v1(-52.4,42.1) ; C168.1@-51.3,41.46 v1(-51.3,42.1) ; v1(-51.2,-20.25) Q3.S@-50.45,-20.25 ; v1(-50.925,-10) Q2.S@-50.19,-10 ; Q10.S@-50.05,22.25 v1(-49.3,22.25) ; v1(-50.04,44.3) C155.2@-50.04,45 ; Q9.S@-49.85,11.45 v1(-48.975,11.45) ; C164.1@-48.54,31 v1(-47.9,31) ; C167.2@-47.74,36.6 v1(-47.1,36.6) ; v1(-47.6,-39.7) R197.1@-46.96,-39.7 ; v1(-47.6,-37.3) R202.1@-46.96,-37.3 ; v1(-47.6,-34.8) R201.1@-46.96,-34.8 ; v1(-47.6,-33.6) R199.1@-46.96,-33.6 ; v1(-47.6,-32.4) R196.1@-46.96,-32.4 ; v1(-47.6,-31.2) R195.1@-46.96,-31.2 ; v1(-47.6,-30) R198.1@-46.96,-30 ; v1(-47.6,-28.8) R200.1@-46.96,-28.8 ; J18.6@-33.5,-59.925 v1(-33.5,-58.8) ; U9.18@-26.17,47.75 v1(-25.1,47.75) ; v1(-24.75,42.2) U9.25@-24.75,43.33 ; v1(-23.25,50.6) U9.9@-23.25,51.67 ; v1(-22.1,55.9) C32.1@-21.46,55.9 ; v1(-20.955,-14.605) U5.A4@-20.32,-13.97 ; v1(-20.955,-13.335) U5.A5@-20.32,-12.7 ; U5.A25@-20.32,12.7 v1(-19.685,13.335) U5.B25@-19.05,12.7 ; U9.34@-20.25,43.33 v1(-20.25,44.4) ; U27.4@-19.895,-45.53 v1(-19.895,-44.2) ; v1(-19.685,-15.875) U5.B3@-19.05,-15.24 ; v1(-19.685,-14.605) U5.B4@-19.05,-13.97 ; v1(-19.685,-13.335) U5.B5@-19.05,-12.7 ; v1(-19.685,-9.525) U5.B8@-19.05,-8.89 ; v1(-19.685,-5.715) U5.B11@-19.05,-5.08 ; v1(-19.685,-1.905) U5.B14@-19.05,-1.27 ; v1(-19.685,0.635) U5.B15@-19.05,0 ; v1(-19.685,4.445) U5.B18@-19.05,3.81 ; v1(-19.685,14.605) U5.B26@-19.05,13.97 ; v1(-19.685,15.875) U5.B27@-19.05,15.24 ; v1(-18.9,48.75) U9.45@-17.83,48.75 ; v1(-18.9,49.75) U9.47@-17.83,49.75 ; C31.1@-18.54,55.9 v1(-17.9,55.9) ; v1(-18.415,-17.145) U5.C2@-17.78,-16.51 ; v1(-18.415,-14.605) U5.C4@-17.78,-13.97 ; v1(-18.415,-13.335) U5.C5@-17.78,-12.7 ; v1(-18.415,-4.445) U5.C12@-17.78,-3.81 ; v1(-18.415,-3.175) U5.C13@-17.78,-2.54 ; v1(-18.415,-1.905) U5.C14@-17.78,-1.27 ; v1(-18.415,-0.635) U5.C15@-17.78,0 ; v1(-18.415,1.905) U5.C16@-17.78,1.27 ; v1(-18.415,13.335) U5.C25@-17.78,12.7 ; v1(-18.415,14.605) U5.C26@-17.78,13.97 ; v1(-18.415,17.145) U5.C28@-17.78,16.51 ; v1(-17.145,-17.145) U5.D2@-16.51,-16.51 ; v1(-17.145,-15.875) U5.D3@-16.51,-15.24 ; v1(-17.145,-14.605) U5.D4@-16.51,-13.97 ; v1(-17.145,1.905) U5.D16@-16.51,1.27 ; v1(-17.145,12.065) U5.D24@-16.51,11.43 ; v1(-17.145,14.605) U5.D26@-16.51,13.97 ; v1(-17.145,15.875) U5.D27@-16.51,15.24 ; v1(-17.145,17.145) U5.D28@-16.51,16.51 ; v1(-17.145,18.415) U5.D29@-16.51,17.78 ; R184.1@-16.1,-42.52 v1(-16.1,-41.9) ; v1(-15.875,-18.415) U5.E1@-15.24,-17.78 ; v1(-15.875,-17.145) U5.E2@-15.24,-16.51 ; v1(-15.875,-12.065) U5.E6@-15.24,-11.43 ; v1(-15.875,-9.525) U5.E8@-15.24,-8.89 ; v1(-15.875,0.635) U5.E15@-15.24,0 ; v1(-14.605,-0.635) U5.F15@-13.97,0 ; v1(-14.605,1.905) U5.F16@-13.97,1.27 ; v1(-14.605,8.255) U5.F21@-13.97,7.62 ; v1(-14.605,9.525) U5.F22@-13.97,8.89 ; v1(-14.325,45.73) C33.1@-13.5,45.73 ; v1(-14.325,50.27) C34.1@-13.5,50.27 ; v1(-13.335,-13.335) U5.G5@-12.7,-12.7 ; v1(-13.335,-9.525) U5.G8@-12.7,-8.89 ; v1(-13.335,-5.715) U5.G11@-12.7,-5.08 ; v1(-13.335,1.905) U5.G16@-12.7,1.27 ; v1(-13.335,5.715) U5.G19@-12.7,5.08 ; v1(-13.335,9.525) U5.G22@-12.7,8.89 ; v1(-13.335,13.335) U5.G25@-12.7,12.7 ; v1(-13.335,14.605) U5.G26@-12.7,13.97 ; v1(-13.335,15.875) U5.G27@-12.7,15.24 ; v1(-13.335,17.145) U5.G28@-12.7,16.51 ; v1(-12.1,-50.4) R246.1@-11.48,-50.4 ; v1(-12.1,-49.2) C120.1@-11.46,-49.2 ; v1(-12.1,-46.7) C114.1@-11.46,-46.7 ; v1(-12.1,-45.3) C112.1@-11.46,-45.3 ; v1(-12.1,-42.3) C123.1@-11.46,-42.3 ; v1(-12.065,-17.145) U5.H2@-11.43,-16.51 ; v1(-12.065,-15.875) U5.H3@-11.43,-15.24 ; v1(-12.065,-12.065) U5.H6@-11.43,-11.43 ; v1(-12.065,-8.255) U5.H9@-11.43,-7.62 ; v1(-12.065,-4.445) U5.H12@-11.43,-3.81 ; v1(-12.065,-3.175) U5.H13@-11.43,-2.54 ; v1(-12.065,-1.905) U5.H14@-11.43,-1.27 ; v1(-12.065,0.635) U5.H15@-11.43,0 ; v1(-12.065,1.905) U5.H16@-11.43,1.27 ; v1(-12.065,3.175) U5.H17@-11.43,2.54 ; v1(-12.065,4.445) U5.H18@-11.43,3.81 ; v1(-12.065,5.715) U5.H19@-11.43,5.08 ; v1(-12.065,6.985) U5.H20@-11.43,6.35 ; v1(-12.065,8.255) U5.H21@-11.43,7.62 ; v1(-12.065,9.525) U5.H22@-11.43,8.89 ; v1(-12.065,10.795) U5.H23@-11.43,10.16 ; v1(-12.065,12.065) U5.H24@-11.43,11.43 ; v1(-12.065,13.335) U5.H25@-11.43,12.7 ; v1(-12.065,14.605) U5.H26@-11.43,13.97 ; v1(-12.065,15.875) U5.H27@-11.43,15.24 ; v1(-12.065,17.145) U5.H28@-11.43,16.51 ; v1(-12.065,18.415) U5.H29@-11.43,17.78 ; U5.H4@-11.43,-13.97 v1(-12.065,-13.335) U5.H5@-11.43,-12.7 ; U5.H7@-11.43,-10.16 v1(-12.065,-9.525) U5.H8@-11.43,-8.89 ; U5.H10@-11.43,-6.35 v1(-12.065,-5.715) U5.H11@-11.43,-5.08 ; v1(-9.8,-43.75) U21.52@-8.68,-43.75 ; v1(-6.985,-18.415) U5.M1@-6.35,-17.78 ; v1(-6.8,-55) R243.1@-6.8,-54.38 ; C113.1@-6.7,-37.64 v1(-6.7,-37) ; v1(-5.6,-55) C122.1@-5.6,-54.36 ; v1(-5.1,55.5) R168.1@-4.48,55.5 ; C119.1@-4.2,-37.64 v1(-4.2,-37) ; C116.1@-2.8,-37.64 v1(-2.8,-37) ; v1(-1.905,-18.415) U5.T1@-1.27,-17.78 ; v1(-0.3,-55) C118.1@-0.3,-54.36 ; C115.1@-0.3,-37.64 v1(-0.3,-37) ; v1(1.9,-37.64) C108.1@2.6,-37.64 v1(3.3,-37.64) C109.1@4,-37.64 v1(4.7,-37.64) ; U21.23@2.68,-46.75 v1(3.8,-46.75) ; U21.26@2.68,-45.25 v1(3.8,-45.25) ; U5.Y29@3.81,17.78 v1(4.445,18.415) ; C117.1@5.46,-49.3 v1(6.1,-49.3) ; C110.2@5.46,-42.7 v1(6.1,-42.7) ; C111.1@5.46,-41.5 v1(6.1,-41.5) ; C121.1@5.46,-40.3 v1(6.1,-40.3) ; R242.2@5.48,-50.5 v1(6.1,-50.5) ; U5.AF2@11.43,-16.51 v1(12.065,-17.145) ; U5.AF3@11.43,-15.24 v1(12.065,-15.875) ; U5.AF4@11.43,-13.97 v1(12.065,-14.605) ; U5.AF5@11.43,-12.7 v1(12.065,-13.335) ; U5.AF6@11.43,-11.43 v1(12.065,-12.065) ; U5.AF7@11.43,-10.16 v1(12.065,-10.795) ; U5.AF8@11.43,-8.89 v1(12.065,-9.525) ; U5.AF9@11.43,-7.62 v1(12.065,-8.255) ; U5.AF10@11.43,-6.35 v1(12.065,-6.985) ; U5.AF11@11.43,-5.08 v1(12.065,-5.715) ; U5.AF12@11.43,-3.81 v1(12.065,-4.445) ; U5.AF13@11.43,-2.54 v1(12.065,-3.175) ; U5.AF14@11.43,-1.27 v1(12.065,-1.905) ; U5.AF15@11.43,0 v1(12.065,-0.635) ; U5.AF16@11.43,1.27 v1(12.065,1.905) ; U5.AF17@11.43,2.54 v1(12.065,3.175) ; U5.AF18@11.43,3.81 v1(12.065,4.445) ; U5.AF19@11.43,5.08 v1(12.065,5.715) ; U5.AF20@11.43,6.35 v1(12.065,6.985) ; U5.AF21@11.43,7.62 v1(12.065,8.255) ; U5.AF22@11.43,8.89 v1(12.065,9.525) ; U5.AF23@11.43,10.16 v1(12.065,10.795) ; U5.AF24@11.43,11.43 v1(12.065,12.065) ; U5.AF25@11.43,12.7 v1(12.065,13.335) ; U5.AF26@11.43,13.97 v1(12.065,14.605) ; U5.AF27@11.43,15.24 v1(12.065,15.875) ; U5.AF28@11.43,16.51 v1(12.065,17.145) ; U5.AG2@12.7,-16.51 v1(13.335,-17.145) ; U5.AG3@12.7,-15.24 v1(13.335,-15.875) ; U5.AG4@12.7,-13.97 v1(13.335,-14.605) ; U5.AG5@12.7,-12.7 v1(13.335,-13.335) ; U5.AG6@12.7,-11.43 v1(13.335,-12.065) ; U5.AG7@12.7,-10.16 v1(13.335,-10.795) ; U5.AG16@12.7,1.27 v1(13.335,1.905) ; U5.AG23@12.7,10.16 v1(13.335,10.795) ; U5.AH4@13.97,-13.97 v1(14.605,-14.605) ; U5.AH5@13.97,-12.7 v1(14.605,-13.335) ; U5.AH8@13.97,-8.89 v1(14.605,-9.525) ; U5.AH14@13.97,-1.27 v1(14.605,-1.905) ; U5.AH17@13.97,2.54 v1(14.605,3.175) ; U5.AH19@13.97,5.08 v1(14.605,5.715) ; U5.AH21@13.97,7.62 v1(14.605,8.255) ; R82.1@14.8,39 v1(14.8,39.62) ; U5.AJ1@15.24,-17.78 v1(15.875,-18.415) ; U5.AJ5@15.24,-12.7 v1(15.875,-13.335) ; U5.AJ6@15.24,-11.43 v1(15.875,-12.065) ; U5.AJ7@15.24,-10.16 v1(15.875,-9.525) ; U5.AJ9@15.24,-7.62 v1(15.875,-8.255) ; U5.AJ14@15.24,-1.27 v1(15.875,-1.905) ; U5.AJ17@15.24,2.54 v1(15.875,3.175) ; U5.AJ20@15.24,6.35 v1(15.875,6.985) ; U5.AJ26@15.24,13.97 v1(15.875,14.605) ; v1(15.4,-50.3) C27.1@16.04,-50.3 ; v1(15.4,-49.3) C26.1@16.04,-49.3 ; J20.9@15.46,52.032 v1(15.46,53.8) ; v1(15.875,-5.715) U5.AK10@16.51,-6.35 ; U5.AK5@16.51,-12.7 v1(17.145,-13.335) ; U5.AK6@16.51,-11.43 v1(17.145,-12.065) ; U5.AK7@16.51,-10.16 v1(17.145,-10.795) ; U5.AK8@16.51,-8.89 v1(17.145,-9.525) ; U5.AK9@16.51,-7.62 v1(17.145,-8.255) ; U5.AK11@16.51,-5.08 v1(17.145,-5.715) ; U5.AK12@16.51,-3.81 v1(17.145,-4.445) ; U5.AK13@16.51,-2.54 v1(17.145,-3.175) ; U5.AK14@16.51,-1.27 v1(17.145,-1.905) ; U5.AK17@16.51,2.54 v1(17.145,3.175) ; U5.AK20@16.51,6.35 v1(17.145,6.985) ; U5.AK23@16.51,10.16 v1(17.145,10.795) ; R84.1@17.3,39 v1(17.3,39.62) ; U5.AL4@17.78,-13.97 v1(18.415,-14.605) ; U5.AL5@17.78,-12.7 v1(18.415,-13.335) ; U5.AL9@17.78,-7.62 v1(18.415,-8.255) ; U5.AL10@17.78,-6.35 v1(18.415,-6.985) ; U5.AL11@17.78,-5.08 v1(18.415,-5.715) ; U5.AL14@17.78,-1.27 v1(18.415,-1.905) ; U5.AL17@17.78,2.54 v1(18.415,3.175) ; J20.5@18,52.032 v1(18,53.8) ; v1(18.4,-51) U6.14@18.4,-50.5 ; U5.AM5@19.05,-12.7 v1(19.685,-13.335) ; U5.AM6@19.05,-11.43 v1(19.685,-12.065) ; U5.AM12@19.05,-3.81 v1(19.685,-4.445) ; U5.AM15@19.05,0 v1(19.685,-0.635) ; U5.AM18@19.05,3.81 v1(19.685,4.445) ; U5.AM20@19.05,6.35 v1(19.685,6.985) ; J20.3@19.27,52.032 v1(19.27,53.8) ; U6.2@19.75,-51.25 19.75,-51.75 19.9,-51.9 20.25,-51.9 ; U6.3@20.25,-51.25 20.25,-51.9 ; U5.AN8@20.32,-8.89 v1(20.955,-9.525) ; U5.AN11@20.32,-5.08 v1(20.955,-5.715) ; U5.AN14@20.32,-1.27 v1(20.955,-0.635) ; U5.AN17@20.32,2.54 v1(20.955,3.175) ; U5.AN20@20.32,6.35 v1(20.955,6.985) ; U6.4@20.75,-51.25 v1(20.75,-51.9) 20.25,-51.9 ; U6.5@21.6,-50.5 22.2,-50.5 22.3,-50.4 v1(22.3,-50) ; U6.6@21.6,-50 v1(22.3,-50) ; U6.7@21.6,-49.5 22.2,-49.5 22.3,-49.6 v1(22.3,-50) ; J22.9@27.46,52.032 v1(27.46,53.8) ; J22.5@30,52.032 v1(30,53.8) ; U18.9@30.695,-47.2 31.3,-47.2 31.5,-47.4 v1(32.7,-47.4) ; J22.3@31.27,52.032 v1(31.27,53.8) ; v1(35,60.2) SWD.3@35,61.365 ; U17.9@39.695,-47.2 40.3,-47.2 40.5,-47.4 v1(41.7,-47.4) ; SW1.2@42.1,41 v1(44,41) v1(46,41) SW1.1@47.9,41 ; v1(47.5,-51.1) R337.2@47.5,-50.48 ; SW2.2@52.1,41 v1(54,41) v1(56,41) SW2.1@57.9,41 ; v1(52.4,-37.3) C94.1@53.04,-37.3 ; v1(55.3,-54) C96.1@55.94,-54 ; v1(55.3,-52.9) R230.1@55.92,-52.9 ; v1(55.3,-45.3) C92.1@55.94,-45.3 ; v1(55.3,-40.5) R228.2@55.92,-40.5 ; v1(55.3,-37.3) C95.1@55.94,-37.3 ; J31.17@57.5,-56.5 v1@57.5,-54.5 ; v1(57.8,-43.3) C89.1@58.44,-43.3 ; R358.1@59,-0.6 v1(59.9,-0.6) ; R229.1@60,-27.54 v1(60,-26.9) ; J31.11@60.5,-56.5 U20.14@60.5,-47.6 v1(60.5,-46.5) ; v1(60.875,-26) X4.2@61.95,-26 ; v1(61.74,-30) C86.1@61.74,-29.3 ; J31.8@62,-56.5 U20.11@62,-47.6 v1(62,-46.5) ; C91.1@62,-32.04 v1(62,-31.4) ; J31.5@63.5,-56.5 U20.8@63.5,-47.6 v1(63.5,-46.5) ; C107.1@64,-32.04 v1(64,-31.4) ; SW4.2@64.1,41 v1(66,41) v1(68,41) SW4.1@69.9,41 ; X4.4@64.45,-28 v1(65.525,-28) ; R319.2@64.5,54.9 Q13.S@64.5,56.31 ; v1(64.66,-30) C85.1@64.66,-29.3 ; J31.2@65,-56.5 U20.5@65,-47.6 v1(65,-46.5) ; C105.1@65.2,-32.04 v1(65.2,-31.4) ; v1(66,-54.5) U20.36@66,-53.4 v1(66,-46.5) ; C106.1@66.4,-32.04 v1(66.4,-31.4) ; C104.1@67.6,-32.04 v1(67.6,-31.4) ; R318.2@68.5,54.9 Q12.S@68.5,56.31 ; C88.1@68.56,-44.3 v1(69.2,-44.3) ; C98.1@68.56,-43.1 v1(69.2,-43.1) ; C90.1@68.56,-41.9 v1(69.2,-41.9) ; C100.1@68.56,-40.7 v1(69.2,-40.7) ; C103.1@68.56,-38.3 v1(69.2,-38.3) ; C101.1@69.06,-53.4 v1(69.7,-53.4) ; C93.1@69.06,-52.2 v1(69.7,-52.2) ; C84.1@69.06,-49.4 v1(69.7,-49.4) ; C82.1@69.06,-48.2 v1(69.7,-48.2) ; C83.1@69.06,-47 v1(69.7,-47) ; C97.1@71.56,-43.1 v1(72.2,-43.1) ; C99.1@71.56,-40.7 v1(72.2,-40.7) ; C102.1@71.56,-38.3 v1(72.2,-38.3) ; R317.2@72.5,54.9 Q11.S@72.5,56.31 ; SW3.2@74.1,41 v1(75.9,41) v1(78.1,41) SW3.1@79.9,41 ; R11.2@88.5,54.9 Q1.S@88.5,56.31 ; U36.4@89.105,-37.53 v1(89.105,-36.2) ; R108.2@92,31.96 v1(92,32.624) ; R350.1@92.9,-34.92 v1(92.9,-34.3) ; R116.2@93.2,31.96 v1(93.2,32.624) ; v1(93.9,-48) R264.1@94.52,-48 ; R107.2@94.4,31.96 v1(94.4,32.624) ; U32.7@94.55,55.75 93.95,55.75 93.785,55.915 v1(93.785,56.25) ; U32.6@94.55,56.25 v1(93.785,56.25) ; U32.5@94.55,56.75 93.95,56.75 93.785,56.585 v1(93.785,56.25) ; v1(95.5,-36.425) Q4.S@95.5,-35.69 ; R115.2@95.6,31.96 v1(95.6,32.624) ; Q6.S@95.69,-46 v1(96.425,-46) ; v1(96.8,-47) U28.9@97.84,-47 ; R106.2@96.8,31.96 v1(96.8,32.624) ; U32.4@97.45,56.75 v1(98.215,56.75) ; R114.2@98,31.96 v1(98,32.624) ; C144.2@98.96,-48.7 v1(98.96,-48.05) ; R105.2@99.2,31.96 v1(99.2,32.624) ; R131.1@100.4,10.96 v1(100.4,11.6) v1@100.4,11.7 ; R113.2@100.4,31.96 v1(100.4,32.624) ; R127.1@101.6,10.96 v1(101.6,11.6) v1@101.6,11.7 ; R104.2@101.6,31.96 v1(101.6,32.624) ; v1(101.9,53.6) R27.1@102.7,53.6 ; U28.5@102.16,-45.5 v1(103.2,-45.5) ; R130.1@102.8,10.96 v1(102.8,11.6) v1@102.8,11.7 ; R112.2@102.8,31.96 v1(102.8,32.624) ; R129.1@104,10.96 v1(104,11.6) v1@104,11.7 ; R103.2@104,31.96 v1(104,32.624) ; R126.1@105.2,10.96 v1(105.2,11.6) v1@105.2,11.7 ; R111.2@105.2,31.96 v1(105.2,32.624) ; v1(105.75,-36.7) Q5.S@105.75,-35.95 ; v1(106,47.9) U4.12@106,48.55 ; C23.1@106,53.46 v1(106,54.1) ; R128.1@106.4,10.96 v1(106.4,11.6) v1@106.4,11.7 ; R102.2@106.4,31.96 v1(106.4,32.624) ; R125.1@107.6,10.96 v1(107.6,11.6) v1@107.6,11.7 ; R110.2@107.6,31.96 v1(107.6,32.624) ; R26.1@108.4,53.48 v1(108.4,54.1) ; R101.2@108.8,31.96 v1(108.8,32.624) ; R109.2@110,31.96 v1(110,32.624) ; X5.4@111.32,-38 v1(111.32,-39.5) C125.2@112.04,-39.5 ; C124.2@113.06,-34.5 v1(113.68,-34.5) X5.2@113.68,-36 ; v1(116.9,-39.3) C132.1@117.54,-39.3 ; v1(116.9,-38.1) C139.1@117.54,-38.1 ; v1(116.9,-35.5) C136.1@117.54,-35.5 ; v1(116.9,-34.3) R251.2@117.52,-34.3 ; R252.1@117,-31.52 v1(117,-30.9) ; R253.1@118.8,-40.5 v1(119.6,-40.5) ; R308.2@119,-20.02 v1(119,-19.4) ; R313.2@119,8.98 v1(119,9.6) ; C127.1@119.4,-31.54 v1(119.4,-30.9) ; R256.1@120.6,-31.52 R255.1@121.8,-31.52 v1(121.8,-30.9) ; v1(121.9,36.2) R80.1@122.52,36.2 ; v1(121.9,37.5) R78.2@122.52,37.5 ; v1(122.9,-44.105) C133.1@122.9,-43.46 ; C137.1@123,-31.54 v1(123,-30.9) ; R254.1@124.2,-31.52 v1(124.2,-30.9) ; U24.37@124.5,-38.5 v1(126.7,-38.5) ; C134.1@128.96,-39 v1(129.605,-39) ; C138.1@128.96,-37.4 v1(129.605,-37.4) ; C135.1@128.96,-36.1 v1(129.605,-36.1) ; v1(129.02,-20.6) R307.1@129.02,-20 ; R312.1@129.98,7.5 v1(130.6,7.5) ; v1(130.3,-9.6) R304.1@130.3,-8.98 ; v1(131,19.4) R309.1@131,20.02
  1-TOP w0.3: J12.4@-68.032,20.23 v1(-66.2,20.23) ; J12.6@-68.032,21.5 v1(-66.2,21.5) ; J12.10@-68.032,24.04 v1(-66.2,24.04) ; v1(-66.475,-41.45) J10.2@-66.475,-39.975 v1(-66.475,-38.5) ; v1(-66.475,38.5) J13.3@-66.475,39.975 v1(-66.475,41.45) ; v1(-65.5,-35.325) X3.2@-65.5,-34.25 ; v1(-63.525,-41.45) J10.3@-63.525,-39.975 v1(-63.525,-38.5) ; v1(-63.525,38.5) J13.2@-63.525,39.975 v1(-63.525,41.45) ; X3.4@-63.5,-31.75 v1(-63.5,-30.675) ; v1(-62.6,36.4) C169.1@-61.77,36.4 ; C62.1@-62.05,-34.46 v1(-61.425,-34.46) ; C63.1@-62.05,-31.54 v1(-61.425,-31.54) ; v1(-60.4,-28.6) C68.1@-60.4,-27.96 ; C184.1@-59.8,-44.54 v1(-59.8,-43.9) ; v1(-59.6,-32) C67.1@-58.96,-32 ; v1(-59.6,-30.9) C66.1@-58.96,-30.9 ; v1(-58.96,-34.45) C75.1@-58.96,-33.8 ; C183.1@-58.6,-44.54 v1(-58.6,-43.9) ; v1(-58.2,-38) C74.1@-58.2,-37.36 ; C182.1@-57.4,-44.54 v1(-57.4,-43.9) ; v1(-56.6,-38) C77.1@-56.6,-37.36 ; C65.1@-56.2,-44.54 v1(-56.2,-43.9) ; C71.1@-55.06,-39.6 v1(-55.06,-38.9) C70.1@-55.06,-38.2 ; C69.1@-54.8,-27.54 v1(-54.8,-26.9) ; C78.1@-53.6,-27.54 v1(-53.6,-26.9) ; v1(-52.6,-39.3) C76.1@-52.6,-38.66 ; C173.2@-48.1,34.26 C172.2@-46.7,34.26 v1(-46,34.26) C171.1@-45.3,34.26 ; v1(-46.6,-36) C72.1@-45.96,-36 ; v1(-46.6,-27.6) C73.1@-45.96,-27.6 ; v1(-37.6,-62.2) v1(-35.4,-62.2) ; v1(-37.6,-39.5) C193.1@-36.96,-39.5 ; C190.1@-36.44,-36.8 v1(-35.8,-36.8) ; U34.2@-35.69,-37.8 v1(-35.69,-37.4) ; C192.1@-34.5,-37.73 v1(-34.5,-36.9) ; v1(-31.6,-39.5) C189.1@-30.96,-39.5 ; C186.1@-30.44,-36.8 v1(-29.8,-36.8) ; U33.2@-29.69,-37.8 v1(-29.69,-37.4) ; v1(-28.7,48.2) C40.1@-28.7,48.84 ; C188.1@-28.5,-37.73 v1(-28.5,-36.9) ; v1(-27.5,48.2) C41.1@-27.5,48.84 ; C36.2@-25.3,54.46 v1(-25.3,55.1) ; v1(-22.1,55.9) L4.2@-22.1,57.03 ; C44.1@-21.04,-57 v1(-20.4,-57) ; C43.1@-21.04,-55.9 v1(-20.4,-55.9) ; C42.1@-20.84,42 v1(-20.2,42) ; C38.1@-18,53.46 v1(-18,54.1) ; v1(-17.65,-55.7) C143.1@-17.01,-55.7 ; v1(-17.65,-54.5) C142.1@-17.01,-54.5 ; D9.1@-17.3,-57.75 v1(-17.3,-57.2) ; C37.1@-16.2,53.46 v1(-16.2,54.1) ; C39.1@-15.14,47.1 v1(-14.5,47.1) ; C35.1@-15.14,49.2 v1(-14.5,49.2) ; L29.1@-12.2,-57.15 v1(-12.2,-56.2) ; v1(-1.745,60.975) D18.1@-1.745,61.5 ; v1(-1.1,48.9) C56.2@-0.6,48.9 ; U11.2@-0.6,50.53 C56.2@-0.6,48.9 ; C56.2@-0.5,48.9 C56.2@-0.6,48.9 ; J32.4@-0.125,-57.95 v3(-0.125,-56.6) ; v1(1.725,60.975) D17.1@1.725,61.5 ; v1(1.95,44.64) C57.1@2.6,44.64 ; v1(1.95,47.56) C58.1@2.55,47.56 ; J32.7@3.625,-57.95 v3(3.625,-56.6) ; U10.7@4.53,44.19 v1(5.9,44.19) ; J32.10@7.375,-57.95 v3(7.375,-56.6) ; J32.13@11.125,-57.95 v3(11.125,-56.6) ; v1(16.82,-45.19) R75.2@16.82,-44.5 ; v1(19.58,-45.19) R76.2@19.58,-44.5 ; v1(20.42,-45.19) R74.1@20.42,-44.5 ; v1(23.18,-45.19) R73.1@23.18,-44.5 ; v1(43.5,-54.3) R203.1@43.5,-53.5 ; R163.1@57.72,-20.4 v1(57.72,-19.775) ; R162.1@60.48,-20.4 v1(60.48,-19.775) ; v1(72,-45.65) C14.2@73,-45.65 v1(74,-45.65) ; v1(72.04,-20.675) C53.1@72.04,-20 72.04,-19.56 72.3,-19.3 J19.37@72.3,-18.1 ; C19.1@74.7,-46.43 v1(74.7,-45.6) ; J19.43@74.7,-18.1 74.7,-19.3 74.96,-19.56 C54.1@74.96,-20 v1(74.96,-20.675) ; v1(76.05,54.04) C59.1@76.7,54.04 ; v1(77.65,60.975) D20.1@77.65,61.5 ; D16.1@80.4,-44.45 v1(80.4,-43.875) ; D14.1@81.6,-44.45 v1(81.6,-43.875) ; v1(81.895,54.195) U12.5@81.895,55.47 ; v1(82.35,60.975) D19.1@82.35,61.5 ; D13.1@82.7,-44.45 v1(82.7,-43.875) ; D15.1@83.8,-44.45 v1(83.8,-43.875) ; C180.1@86.46,-48.1 v1(87.1,-48.1) ; C181.1@86.46,-46.9 v1(87.1,-46.9) ; v1(91.35,-47.7) C196.1@91.99,-47.7 ; v1(91.35,-46.5) C195.1@91.99,-46.5 ; v1(95.4,53.6) C185.1@95.4,54.3 ; D21.1@97.6,-59 v1(97.6,-58.4) ; v1(98.075,21.8) U7.10@98.075,22.9 ; v1(104.35,18.46) C28.1@105,18.46 ; C131.1@113.4,-43.04 v1(113.4,-42.4) ; C128.1@114.6,-43.04 v1(114.6,-42.4) ; v1(115.6,-15.5) U25.3@115.6,-14.95 ; C130.1@115.9,-43.04 v1(115.9,-42.4) ; C129.1@117.1,-43.04 v1(117.1,-42.4) ; v3(121.45,-50.4) U22.3@121.45,-49.4 ; C3.1@129.46,43.6 v1(130.1,43.6) ; C4.1@129.46,44.8 v1(130.1,44.8) C1.1@130.93,44.8 ; C5.1@129.46,49.2 v1(130.1,49.2) ; C2.2@130.96,42 v1(131.6,42) ; U1.5@131.44,48.1 v1(131.44,48.5) ; v1(133.525,-41.45) J15.2@133.525,-39.975 v1(133.525,-38.5) ; C174.1@134,-9 v3(134,-7.6) ; C176.1@134,20 v3(134,21.4) ; C175.1@136.04,-7 v3(136.04,-6.2) ; C177.1@136.04,22 v3(136.04,22.8) ; v1(136.475,-41.45) J15.3@136.475,-39.975 v1(136.475,-38.5)
  1-TOP w0.4: R55.1@-64.02,-46.5 R54.1@-64.02,-43.5 ; R62.1@-64.02,46.5 v1(-63.38,46.5) ; R54.1@-64,-43.5 v1(-63.4,-43.5) ; R61.1@-64,43.5 v1(-63.4,43.5) ; R55.1@-63.98,-46.5 v1(-63.38,-46.5) ; C29.1@-29.5,58.77 v1(-29.5,59.6) ; v1(-29.4,62) R140.1@-28.6,62 ; v1(-26.4,58) U8.2@-25.32,58 ; v1(-23.75,62.2) J16.9@-23.75,63.5 ; C30.1@-23.7,57.85 v1(-23,57.85) ; J18.12@-23.35,-63.35 v1(-23.35,-62) ; v1(-21.15,62.2) J16.8@-21.15,63.5 ; v1(-18.85,62.2) J16.7@-18.85,63.5 ; v1(-16.25,62.2) J16.6@-16.25,63.5 ; v1(-0.9,43.9) X2.2@-0.9,44.9 ; X2.4@0.95,47.56 v1(1.95,47.56) ; v1(8.04,52.3) C55.2@8.04,53 ; v1(60.5,-7.5) 60.5,-6.85 C47.2@60.85,-6.5 ; v1(74.3,-57.15) J21.15@74.89,-57.15 ; v1(74.3,-50.99) J21.14@74.89,-50.99 ; v1(74.5,-7.5) 74.5,-6.85 C48.2@74.85,-6.5 ; J21.16@75.05,-63.5 v1(75.05,-62.2) ; C20.1@76,-46.94 v1(76,-46.3) ; v1(76,-22) 76,-22.65 C49.2@76.35,-23 ; v1(78.8,-47.7) C10.1@78.8,-47.06 ; v3(85.7,44.8) C8.2@85.7,46.5 v3(85.7,48.2) ; J21.11@88.95,-63.5 v1(88.95,-62.2) ; J21.12@89.11,-57.15 v1(89.7,-57.15) ; J21.13@89.11,-51.29 v1(89.7,-51.29) ; J35.6@96.25,-63 v1(96.25,-61.7) ; v1(96.675,59.93) C6.1@97.5,59.93 ; J35.7@98.85,-63 v1(98.85,-61.7) ; J35.8@101.15,-63 v1(101.15,-61.7) ; v1(103.5,45.4) C22.1@103.5,46.23 ; J35.9@103.75,-63 v1(103.75,-61.7) ; v1(105.5,55.4) R17.1@105.5,56.2 ; v1(106,47.9) v1(106.8,47.9) U4.1@106.8,48.9 ; v1@110,48.6 C13.1@110,49.24 ; v1(110.1,57) U2.2@111.18,57 ; 111.5,47.8 C12.1@111.5,48.73 ; C18.1@112,45.4 v1@112,46.3 ; C7.1@112.5,56.85 v1(113.2,56.85) ; v1(113,47.8) C11.1@113,48.73 ; C17.1@114,45.4 v1@114,46.3 ; C16.1@116,45.4 v1@116,46.3 ; C15.1@118,45.4 v1@118,46.3 ; v3(119,-6.6) J39.10@119,-4.925 ; v3(119,22.4) J41.10@119,24.075 ; v1(133.38,-46.5) R332.1@133.98,-46.5 ; v1(133.4,-43.5) R322.1@134,-43.5 ; R332.1@134.02,-46.5 R322.1@134.02,-43.5 ; v1(135.7,33.73) S1.6@137.3,33.73
  1-TOP w0.5: R180.1@-40.5,-48.6 v3(-40.5,-47.6) ; R180.1@-39.5,-48.6 v3(-39.5,-47.6) ; v1(-38.6,-41) C191.2@-37.35,-41 ; v1(-32.7,-41) C187.2@-31.45,-41 ; v1(-19.16,-53.1) v1(-18.46,-53.1) ; U27.6@-18.625,-50.47 -18.625,-51.675 -18.46,-51.84 C141.1@-18.46,-52.4 v1(-18.46,-53.1) ; v1(-18.46,-53.8) v1(-18.46,-53.1) ; J30.3@31,-63.225 v3(31,-61.9) ; J30.6@34,-59.625 v3(34,-58.3) ; J30.9@37,-63.325 v3(37,-61.9) ; J30.12@40,-59.625 v3(40,-58.3) ; J30.15@43,-63.325 v3(43,-61.9) ; J29.15@43,55.325 v3(43,56.7) ; J29.12@46,51.675 v3(46,53.1) ; J29.9@49,55.325 v3(49,56.7) ; J29.6@52,51.675 v3(52,53.1) ; J19.4@55.9,-9.9 v1(55.9,-7.3) ; C81.1@56.07,57 v3(56.07,57.8) ; v1(57.72,-19.775) 57.9,-19.595 J19.9@57.9,-18.1 v3(57.9,-16.6) ; v3(60.3,-16.6) J19.15@60.3,-18.1 60.3,-19.595 v1(60.48,-19.775) ; C198.1@63.27,-1.5 v1(63.27,-0.6) ; U31.2@64.18,1 v3(66.5,1) ; J19.18@64.7,-9.9 v3(64.7,-8.4) ; J19.21@65.9,-18.1 v3(65.9,-16.6) ; J19.26@67.9,-9.9 v1(67.9,-7.3) ; J19.27@68.3,-18.1 v3(68.3,-16.6) ; J19.29@69.1,-18.1 v3(69.1,-16.6) ; J19.34@71.1,-9.9 v3(71.1,-8.4) ; J19.35@71.5,-18.1 v3(71.5,-16.6) ; J19.40@73.5,-9.9 v3(73.5,-8.4) ; J19.50@77.5,-9.9 v1(77.5,-7.3) ; 77.9,-47.86 v1(78.2,-47.86) ; J21.5@86.38,-56.21 v1(86.38,-55.4) ; C178.1@87.4,-45.3 v1(88.3,-45.3) ; C179.1@87.4,-43.3 v1(88.3,-43.3) ; v1(89.84,-45.1) v1(90.54,-45.1) ; U36.6@90.375,-42.47 90.375,-43.675 90.54,-43.84 C194.1@90.54,-44.4 v1(90.54,-45.1) ; v1(90.54,-45.8) v1(90.54,-45.1) ; L31.2@101.3,-56.55 v3(101.3,-55.5) ; v1(108.34,-49.6) v1(109.04,-49.6) ; U23.6@108.875,-46.97 108.875,-48.275 109.04,-48.44 C126.2@109.04,-48.9 v1(109.04,-49.6) ; v1(109.04,-50.3) v1(109.04,-49.6) ; L23.1@123.5,-45.65 v3(123.5,-44.6) ; L24.1@126,-45.65 v3(126,-44.6)
  1-TOP w1: 122.8,58.604 J1.2@125,58.604 ; 125,57.504 J1.2@125,58.604 ; 125,59.704 J1.2@125,58.604 ; 127.2,58.604 J1.2@125,58.604
  8-BOTTOM w1: 122.8,58.604 J1.2@125,58.604 ; 125,57.504 J1.2@125,58.604 ; 125,59.704 J1.2@125,58.604 ; 127.2,58.604 J1.2@125,58.604
  other v1: 40.7,-62 42.3,-61 33.7,-56.6 35.3,-56.4 -14.7,-55.7 -13.3,-55.7 99.3,-55.2 100.7,-55.2 -2.9,-54.5 -1.1,-54.5 0.85,-54.5 2.65,-54.5 4.6,-54.5 6.4,-54.5 8.35,-54.5 10.15,-54.5 12.1,-54.5 13.9,-54.5 27.8,-54.5 31.1,-54.5 34.4,-54.5 37.7,-54.5 41,-54.5 57.6,-54.5 60.5,-54.5 62,-54.5 63.5,-54.5 65,-54.5 -2.7,-53.5 -1.3,-53.5 1.05,-53.5 2.45,-53.5 4.8,-53.5 6.2,-53.5 8.55,-53.5 9.95,-53.5 12.3,-53.5 13.7,-53.5 100,-53.2 27.8,-52.5 31.1,-52.5 34.4,-52.5 37.7,-52.5 41,-52.5 100,-51.2 119.3,-50.9 120.7,-50.9 25.2,-50.8 33.9,-49.9 24.5,-49.6 25.9,-49.6 32.9,-49.3 11.4,-49.2 12.6,-49.2 22.9,-48.2 24.1,-48.2 33.9,-47.9 101,-47.7 -66.1,-47.3 -63.9,-47.3 134.1,-47.3 136.1,-47.3 99,-47.2 77.5,-47 4.8,-46.75 24,-46.7 33.9,-45.9 -66.1,-45.7 -63.9,-45.7 118.4,-45.7 122,-45.7 133.9,-45.7 136.1,-45.7 101,-45.3 4.8,-45.25 99,-44.8 -66.1,-44.3 -63.9,-44.3 34.4,-44.3 133.9,-44.3 136.1,-44.3 33.3,-44.2 -7.25,-43.2 -5.75,-43.2 -4.25,-43.2 -2.75,-43.2 -1.25,-43.2 0.25,-43.2 11.4,-42.8 12.6,-42.8 34.5,-42.8 -66.2,-42.7 -63.8,-42.7 133.8,-42.7 136.2,-42.7 -7.25,-42.2 -5.75,-42.2 -4.25,-42.2 -2.75,-42.2 -1.25,-42.2 0.25,-42.2 123.75,-42 124.75,-41.3 17,-39 -65,-38.6 135,-38.6 -36.5,-38.1 -30.5,-38.1 35.4,-37.4 37.4,-37.4 -26.5,-36.5 -25,-36.1 36.9,-36 34.9,-35.7 39.4,-35.3 37.6,-35 36.4,-34.3 40.9,-33.9 38.9,-33.6 41.6,-32.9 16.7,-32.5 60.5,-32 92.2,-25.5 19.5,-22 -22.5,-21.5 -21.2,-21.4 19.5,-21.3 -24.6,-20.4 -22.4,-20.2 -23.4,-19.2 -24.7,-19.1 119.7,-18 118.6,-17.1 113.3,-16.3 114.7,-16.3 24.2,-10.1 24.1,4.1 26,8.5 -55,9 -53,9 -51,9 -47,9 -45,9 -43,9 -41,9 -39,9 -37,9 -35,9 -33,9 -29,9 -27,9 42.5,10.5 -39,11 -39,13 29,16 91,19 33.5,19.5 72.5,19.5 101.5,19.5 66.5,20.5 72.4,21.5 88.5,22 96,22.5 -4.5,23 62,25 63.5,25 70.5,25 72,25 73.5,25 75,25 40.5,28 -47.4,34.26 -65,38.6 -66.2,42.7 -63.8,42.7 -66.1,44.3 -63.9,44.3 -66.1,45.7 -63.9,45.7 46,46 47.4,46 112,46.4 113,46.4 114,46.4 115,46.4 116,46.4 117,46.4 118,46.4 112,47.1 113,47.1 114,47.1 115,47.1 116,47.1 117,47.1 118,47.1 46,47.2 47.4,47.2 -66.1,47.3 -63.9,47.3 109.1,47.8 110,47.8 112,47.8 114,47.8 115,47.8 116,47.8 117,47.8 118,47.8 106.8,48.5 109.1,48.5 110,48.5 109.1,49.2 44.4,49.5 46,49.5 47.6,49.5 64.5,55.5 68.5,55.5 72.5,55.5 88.5,55.5 46.76,56.9 48.16,56.9 46.76,58.1 48.16,58.1
  other v2: -69,-61.6 -61,-61.6 -53,-61.6 -33,-61.6 -29,-61.6 -25,-61.6 -21,-61.6 -1,-61.6 3,-61.6 7,-61.6 11,-61.6 15,-61.6 19,-61.6 47,-61.6 79,-61.6 83,-61.6 91,-61.6 107,-61.6 111,-61.6 119,-61.6 123,-61.6 127,-61.6 131,-61.6 -67,-57.6 -63,-57.6 -59,-57.6 -47,-57.6 -39,-57.6 -19,-57.6 -11,-57.6 49,-57.6 73,-57.6 77,-57.6 81,-57.6 105,-57.6 109,-57.6 133,-57.6 137,-57.6 -65,-53.6 -33,-53.6 -9,-53.6 7,-53.6 11,-53.6 19,-53.6 47,-53.6 51,-53.6 71,-53.6 75,-53.6 79,-53.6 87,-53.6 91,-53.6 103,-53.6 107,-53.6 135,-53.6 -59,-49.6 -43,-49.6 -23,-49.6 1,-49.6 89,-49.6 97,-49.6 105,-49.6 129,-49.6 -69,-45.6 -61,-45.6 -45,-45.6 -41,-45.6 -33,-45.6 59,-45.6 67,-45.6 107,-45.6 131,-45.6 -59,-41.6 -43,-41.6 -39,-41.6 1,-41.6 73,-41.6 101,-41.6 105,-41.6 117,-41.6 129,-41.6 -69,-37.6 -65,-37.6 -61,-37.6 -49,-37.6 -41,-37.6 -33,-37.6 -5,-37.6 23,-37.6 43,-37.6 47,-37.6 95,-37.6 131,-37.6 135,-37.6 -67,-33.6 -39,-33.6 -35,-33.6 -27,-33.6 -23,-33.6 -19,-33.6 -11,-33.6 25,-33.6 69,-33.6 73,-33.6 81,-33.6 109,-33.6 117,-33.6 129,-33.6 133,-33.6 137,-33.6 -69,-29.6 -65,-29.6 -61,-29.6 -37,-29.6 -33,-29.6 -29,-29.6 -25,-29.6 -21,-29.6 55,-29.6 59,-29.6 67,-29.6 75,-29.6 79,-29.6 83,-29.6 103,-29.6 107,-29.6 119,-29.6 123,-29.6 127,-29.6 131,-29.6 135,-29.6 -67,-25.6 -63,-25.6 -59,-25.6 -31,-25.6 -27,-25.6 -19,-25.6 -11,-25.6 -7,-25.6 1,-25.6 13,-25.6 17,-25.6 21,-25.6 25,-25.6 33,-25.6 41,-25.6 73,-25.6 81,-25.6 85,-25.6 101,-25.6 105,-25.6 109,-25.6 113,-25.6 117,-25.6 -53,-21.6 -33,-21.6 11,-21.6 23,-21.6 35,-21.6 39,-21.6 43,-21.6 51,-21.6 75,-21.6 79,-21.6 91,-21.6 95,-21.6 99,-21.6 103,-21.6 107,-21.6 111,-21.6 115,-21.6 127,-21.6 131,-21.6 135,-21.6 -63,-17.6 -47,-17.6 -43,-17.6 -27,-17.6 33,-17.6 89,-17.6 97,-17.6 101,-17.6 105,-17.6 109,-17.6 113,-17.6 117,-17.6 125,-17.6 129,-17.6 137,-17.6 23,-13.6 35,-13.6 39,-13.6 51,-13.6 59,-13.6 67,-13.6 71,-13.6 111,-13.6 123,-13.6 127,-13.6 131,-13.6 135,-13.6 -67,-9.6 -63,-9.6 33,-9.6 37,-9.6 41,-9.6 49,-9.6 89,-9.6 105,-9.6 113,-9.6 117,-9.6 125,-9.6 129,-9.6 101,-1.6 105,-1.6 113,-1.6 83,2.4 99,2.4 107,2.4 111,2.4 115,2.4 33,6.4 37,6.4 -61,10.4 -49,10.4 -45,10.4 -41,10.4 47,10.4 51,10.4 59,10.4 63,10.4 67,10.4 75,10.4 99,10.4 111,10.4 115,10.4 123,10.4 127,10.4 131,10.4 135,10.4 -67,14.4 -63,14.4 -47,14.4 -43,14.4 -31,14.4 -27,14.4 97,14.4 125,14.4 129,14.4 133,14.4 137,14.4 -45,18.4 -33,18.4 3,18.4 7,18.4 111,18.4 115,18.4 119,18.4 123,18.4 131,18.4 -39,22.4 -35,22.4 -31,22.4 -7,22.4 113,22.4 117,22.4 125,22.4 133,22.4 -69,26.4 -65,26.4 -61,26.4 -57,26.4 -53,26.4 -41,26.4 -33,26.4 -29,26.4 -25,26.4 -21,26.4 -5,26.4 7,26.4 11,26.4 19,26.4 27,26.4 59,26.4 79,26.4 83,26.4 115,26.4 119,26.4 123,26.4 127,26.4 131,26.4 135,26.4 -67,30.4 -63,30.4 -43,30.4 -39,30.4 -35,30.4 -31,30.4 -27,30.4 -23,30.4 -19,30.4 117,30.4 121,30.4 125,30.4 133,30.4 -69,34.4 -65,34.4 -41,34.4 -37,34.4 -33,34.4 -29,34.4 -25,34.4 -21,34.4 -17,34.4 -13,34.4 -1,34.4 7,34.4 51,34.4 59,34.4 67,34.4 75,34.4 83,34.4 127,34.4 131,34.4 135,34.4 -47,38.4 -43,38.4 -39,38.4 -35,38.4 -31,38.4 -19,38.4 121,38.4 -69,42.4 -61,42.4 -49,42.4 -41,42.4 -37,42.4 -33,42.4 -13,42.4 23,42.4 35,42.4 55,42.4 59,42.4 67,42.4 95,42.4 99,42.4 103,42.4 123,42.4 -67,46.4 -47,46.4 -39,46.4 -35,46.4 -7,46.4 -3,46.4 13,46.4 25,46.4 37,46.4 53,46.4 61,46.4 69,46.4 73,46.4 89,46.4 -69,50.4 -61,50.4 -41,50.4 -37,50.4 -21,50.4 -5,50.4 11,50.4 23,50.4 35,50.4 39,50.4 63,50.4 67,50.4 71,50.4 75,50.4 83,50.4 87,50.4 91,50.4 99,50.4 -59,54.4 -51,54.4 -35,54.4 -27,54.4 -7,54.4 5,54.4 9,54.4 13,54.4 17,54.4 25,54.4 29,54.4 37,54.4 41,54.4 61,54.4 85,54.4 97,54.4 109,54.4 113,54.4 117,54.4 -69,58.4 -65,58.4 -61,58.4 -57,58.4 -49,58.4 -17,58.4 -13,58.4 -9,58.4 -5,58.4 7,58.4 11,58.4 15,58.4 19,58.4 23,58.4 31,58.4 39,58.4 43,58.4 51,58.4 55,58.4 59,58.4 75,58.4 91,58.4 119,58.4 131,58.4 135,58.4 -59,62.4 -51,62.4 -43,62.4 -35,62.4 -11,62.4 -7,62.4 5,62.4 9,62.4 29,62.4 41,62.4 61,62.4 85,62.4 97,62.4 101,62.4 109,62.4 121,62.4 129,62.4
  other v3: 20,-50 120.5,-48 -4.1,-47.1 -1.9,-47.1 -3,-46 -4.1,-44.9 -1.9,-44.9 60,-40.5 62,-40.5 64,-40.5 60,-38.5 62,-38.5 64,-38.5 122,-38 124,-38 60,-36.5 62,-36.5 64,-36.5 122,-36 124,-36 -54,-34 -52,-34 -54,-32 -52,-32 117,-14 -56,33 -54,33 -52,33 -56,35 -54,35 -52,35 -56,37 -54,37 -52,37 136.6,45 137.5,45 138.4,45 96,56 122.5,57 123.5,57 124.5,57 125.5,57 126.5,57 127.5,57 122.5,58 127.5,58 122.5,59 127.5,59 122.5,60 123.5,60 124.5,60 125.5,60 126.5,60 127.5,60
GPIO1_IO03: J46.2 U5.AG14 | length 88.2
  1-TOP w0.2: U5.AG14@12.7,-1.27 v1(13.335,-1.905)
  3-INTOP w0.15: v1(13.335,-1.905) 15.24,0 21,0 22.5,-1.5 82.4,-1.5 86.4,2.5 95.85,2.5 J46.2@97.08,1.27
GPIO1_IO10: J46.3 U5.AG13 | length 84.8
  1-TOP w0.2: U5.AG13@12.7,-2.54 v1(13.335,-3.175)
  3-INTOP w0.15: v1(13.335,-3.175) 13.97,-2.54 14.86,-2.54 15.24,-2.16 15.24,-1.76 15.73,-1.27 20.32,-1.27 21.05,-2 82.6,-2 84.6,0 93.27,0 J46.3@94.54,-1.27
GPIO1_IO11: J46.5 U5.AG10 | length 84.3
  1-TOP w0.2: U5.AG10@12.7,-6.35 v1(13.335,-6.985)
  3-INTOP w0.15: v1(13.335,-6.985) 13.97,-7.62 21.88,-7.62 23,-6.5 v1(90,-6.5)
  6-INBOT w0.15: v1(90,-6.5) 90,-3.27 J46.5@92,-1.27
GPIO1_IO12: R352.2 R353.2 U5.C8 | length 29.6
  1-TOP w0.2: R353.2@-44.52,-8.2 R352.2@-44.52,-7 v1(-43.88,-7) ; v1(-18.415,-9.525) U5.C8@-17.78,-8.89
  3-INTOP w0.15: v1(-43.88,-7) -24.4,-7 -21.38,-10.02 -18.928,-10.02 v1@-18.433,-9.525
GPIO1_IO13: J46.7 R351.1 U5.C9 U36.2 | length 163.2
  1-TOP w0.2: v1(-18.415,-8.255) U5.C9@-17.78,-7.62 ; v1(91,-35.88) R351.1@91.6,-35.88 ; U36.2@91.645,-37.53 R351.1@91.645,-36
  3-INTOP w0.15: v1(-17.78,-17.78) -15.24,-17.78 -12.52,-20.5 -10.6,-20.5 35,-20.5 36.5,-19 62,-19 65,-16 v1(79.5,-16) v1(90,-16)
  6-INBOT w0.15: v1(-18.415,-8.255) -17.78,-8.89 v1(-17.78,-17.78) ; v1(79.5,-16) 79.5,-17.151 88.5,-26.151 88.5,-33.38 v1(91,-35.88) ; J46.7@89.46,-1.27 89.5,-1.31 89.5,-15.5 v1(90,-16)
GPIO1_IO14: J46.9 R184.2 U5.C7 U27.1 | length 187.4
  1-TOP w0.2: v1(-18.415,-10.795) U5.C7@-17.78,-10.16 ; R184.2@-16.1,-43.48 v1@-15.5,-43.48 ; U27.1@-16.085,-45.53 R184.2@-16.085,-43.495
  3-INTOP w0.15: v1(-15.475,-43.48) -14.995,-43 -14,-42.005 -14,-38.7 -9.8,-34.5 13.3,-34.5 18.3,-39.5 52.6,-39.5 53.3,-38.8 58.25,-38.8 59.35,-37.7 64.3,-37.7 65,-37 80,-37 v1(91.5,-25.5)
  6-INBOT w0.15: v1(-18.415,-10.795) -19.685,-10.795 -21.5,-12.61 -21.5,-17.6 -17.5,-21.6 -17.5,-39.8 -15.5,-41.8 v1@-15.5,-43.48 ; J46.9@86.92,-1.27 86.92,-7.42 87,-7.5 87,-18.1 88.4,-19.5 88.4,-22.4 v1(91.5,-25.5)
GPIO1_IO15: J46.4 R261.1 U5.C11 U27.2 | length 197.4
  1-TOP w0.2: v1(-18.415,-5.715) U5.C11@-17.78,-5.08 ; v1@-17.9,-43.48 R261.1@-17.3,-43.48 ; U27.2@-17.355,-45.53 R261.1@-17.355,-43.5
  3-INTOP w0.15: v1(-17.925,-43.48) -16.945,-42.5 -15.202,-42.5 -14.5,-41.798 -14.5,-38.5 -10,-34 13.5,-34 18.5,-39 52.4,-39 53.1,-38.3 58.05,-38.3 59.15,-37.2 64.1,-37.2 64.8,-36.5 79.8,-36.5 91.3,-25 v1(92.7,-25)
  6-INBOT w0.15: v1(-18.415,-5.715) -22.5,-9.8 -22.5,-18.007 -18.5,-22.007 -18.5,-42.88 v1@-17.9,-43.48 ; v1(92.7,-25) 93.5,-24.2 93.5,-19.3 92.2,-18 92.2,-5.8 93.3,-4.7 93.3,0.03 J46.4@94.54,1.27
GPIO3_IO01_1V8: J46.6 U5.K29 | length 121.4
  1-TOP w0.2: v1(-9.525,18.415) U5.K29@-8.89,17.78
  3-INTOP w0.15: v1(-9.525,18.415) -7.94,20 10.1,20 11,19.1 11,6 11.92,5.08 13.48,5.08 13.97,5.57 13.97,5.752 14.408,6.19 20.01,6.19 20.1,6.1 25.7,6.1 27.3,4.5 v1(92,4.5)
  6-INBOT w0.15: J46.6@92,1.27 v1(92,4.5)
GPIO3_IO14_1V8: J46.8 U5.AG25 | length 87.6
  1-TOP w0.2: U5.AG25@12.7,12.7 v1(13.335,13.335)
  3-INTOP w0.15: v1(13.335,13.335) 13.97,12.7 13.97,6.948 14.418,6.5 26,6.5 27.5,5 v1(89.46,5)
  6-INBOT w0.15: J46.8@89.46,1.27 v1(89.46,5)
HDMI_CLK_N: L11.1 U19.21 | length 2.3
  1-TOP w0.15: L11.1@60.225,-44.35 60.323,-44.252 60.323,-43.477 60.623,-43.177 60.623,-42.203 U19.21@60.6,-42.18
HDMI_CLK_P: L11.4 U19.22 | length 2.3
  1-TOP w0.15: L11.4@60.775,-44.35 60.677,-44.252 60.677,-43.624 60.977,-43.324 60.977,-42.203 U19.22@61,-42.18
HDMI_D0_N: L10.1 U19.24 | length 2.2
  1-TOP w0.15: L10.1@61.725,-44.35 61.823,-44.252 61.823,-42.203 U19.24@61.8,-42.18
HDMI_D0_P: L10.4 U19.25 | length 2.2
  1-TOP w0.15: U19.25@62.2,-42.18 62.177,-42.203 62.177,-44.252 L10.4@62.275,-44.35
HDMI_D1_N: L9.1 U19.27 | length 2.3
  1-TOP w0.15: U19.27@63,-42.18 63.023,-42.203 63.023,-42.924 63.323,-43.224 63.323,-44.252 L9.1@63.225,-44.35
HDMI_D1_P: L9.4 U19.28 | length 2.3
  1-TOP w0.15: U19.28@63.4,-42.18 63.377,-42.203 63.377,-42.777 63.677,-43.077 63.677,-44.252 L9.4@63.775,-44.35
HDMI_D2_N: L8.1 U19.30 | length 2.5
  1-TOP w0.15: U19.30@64.2,-42.18 64.223,-42.203 64.223,-42.924 64.823,-43.524 64.823,-44.252 L8.1@64.725,-44.35
HDMI_D2_P: L8.4 U19.31 | length 2.5
  1-TOP w0.15: U19.31@64.6,-42.18 64.577,-42.203 64.577,-42.777 65.177,-43.377 65.177,-44.252 L8.4@65.275,-44.35
HDMI_FIL_CLK_N: J31.12 L11.2 U20.15 U20.24 | length 10.9
  1-TOP w0.15: J31.12@60,-56.5 U20.15@60,-47.6 60,-46.328 60.2,-46.128 L11.2@60.2,-45.65
HDMI_FIL_CLK_P: J31.10 L11.3 U20.13 U20.26 | length 10.9
  1-TOP w0.15: L11.3@60.8,-45.65 60.8,-46.128 61,-46.328 U20.13@61,-47.6 J31.10@61,-56.5
HDMI_FIL_D0_N: J31.9 L10.2 U20.12 U20.27 | length 10.9
  1-TOP w0.15: J31.9@61.5,-56.5 U20.27@61.5,-53.4 U20.12@61.5,-47.6 61.5,-46.328 61.7,-46.128 L10.2@61.7,-45.65
HDMI_FIL_D0_P: J31.7 L10.3 U20.10 U20.29 | length 10.9
  1-TOP w0.15: L10.3@62.3,-45.65 62.3,-46.128 62.5,-46.328 U20.29@62.5,-53.4 J31.7@62.5,-56.5
HDMI_FIL_D1_N: J31.6 L9.2 U20.9 U20.30 | length 10.9
  1-TOP w0.15: J31.6@63,-56.5 U20.9@63,-47.6 63,-46.328 63.2,-46.128 L9.2@63.2,-45.65
HDMI_FIL_D1_P: J31.4 L9.3 U20.7 U20.32 | length 10.9
  1-TOP w0.15: L9.3@63.8,-45.65 63.8,-46.128 64,-46.328 U20.7@64,-47.6 U20.32@64,-53.4 J31.4@64,-56.5
HDMI_FIL_D2_N: J31.3 L8.2 U20.6 U20.33 | length 10.9
  1-TOP w0.15: J31.3@64.5,-56.5 U20.33@64.5,-53.4 U20.6@64.5,-47.6 64.5,-46.328 64.7,-46.128 L8.2@64.7,-45.65
HDMI_FIL_D2_P: J31.1 L8.3 U20.4 U20.35 | length 10.9
  1-TOP w0.15: L8.3@65.3,-45.65 65.3,-46.128 65.5,-46.328 U20.4@65.5,-47.6 J31.1@65.5,-56.5
HDMI_FIL_SCL: J31.15 R233.2 U20.22 | length 7.3
  1-TOP w0.2: R233.2@56.88,-50.7 57.6,-50.7 59,-52.1 U20.22@59,-53.4 59,-54.4 58.5,-54.9 J31.15@58.5,-56.5
HDMI_FIL_SDA: J31.16 R234.2 U20.21 | length 6.1
  1-TOP w0.2: R234.2@56.88,-51.8 57.8,-51.8 58.5,-52.5 U20.21@58.5,-53.4 58.5,-54.3 58,-54.8 J31.16@58,-56.5
HDMI_HPD_1V8: C92.2 R231.2 R232.1 R326.1 U20.19 | length 7.3
  1-TOP w0.2: R326.1@56,-41.7 56,-42.1 56.2,-42.3 56.7,-42.3 56.86,-42.46 C92.2@56.86,-45.3 57.3,-45.3 58,-46 U20.19@58,-47.6
HDMI_HPD_1V8_CPU: R232.2 U5.AG15 | length 77
  1-TOP w0.2: U5.AG15@12.7,0 v1(13.335,-0.635) ; v1(55.3,-42.9) R232.2@55.92,-42.9
  3-INTOP w0.15: v1(13.335,-0.635) 15.24,1.27 21.53,1.27 22.8,0 37,0 v1(38,-1)
  6-INBOT w0.15: v1(38,-1) 45,-8 45,-32.6 v1(55.3,-42.9)
HDMI_SCL_1V8: R286.2 R327.1 R328.1 U20.17 | length 126.9
  1-TOP w0.2: R286.2@13.5,-37.52 v1(14.1,-37.52) ; R327.1@47.5,-48 v1(48.1,-48) ; U20.17@59,-47.6 v1(59,-46.5) ; v1(61.4,23.02) R328.1@62,23.02
  3-INTOP w0.15: v1(14.1,-37.52) 14.1,-40.8 15.3,-42 40.12,-42 46.12,-48 v1(48.1,-48) 57.5,-48 v1(59,-46.5)
  6-INBOT w0.15: v1(59,-46.5) 57,-44.5 57,5 61.4,9.4 v1(61.4,23.02)
HDMI_SDA_1V8: R287.2 R329.1 R330.1 U20.18 | length 129
  1-TOP w0.2: R287.2@13.5,-41.48 v1(14.1,-41.48) ; v1(45.4,-47.98) R329.1@46,-47.98 ; v1(58.5,-48.7) U20.18@58.5,-47.6 ; v1(61.4,26.98) R330.1@62,26.98
  3-INTOP w0.15: v1(14.1,-41.48) 15.12,-42.5 34.128,-42.5 34.303,-42.325 39.745,-42.325 v1@45.42,-48 ; v1(45.4,-47.98) v1@45.42,-48 ; v1(58.5,-48.7) 46.12,-48.7 v1@45.42,-48
  6-INBOT w0.15: v1(58.5,-48.7) 56.5,-46.7 56.5,5.207 60.9,9.607 60.9,26.48 v1(61.4,26.98)
HDMICEC: J31.13 R226.2 U20.23 | length 8.5
  1-TOP w0.2: R226.2@56.88,-49.6 57.3,-49.6 57.709,-49.59 59.5,-51.3 U20.23@59.5,-53.4 J31.13@59.5,-56.5
HDMIHPD: C96.2 J31.19 R230.2 U20.20 | length 4.9
  1-TOP w0.2: J31.19@56.5,-56.5 56.5,-54.36 C96.2@56.86,-54 56.88,-53.98 R230.2@56.88,-52.9 U20.20@57.98,-52.9
I2C2_SCL_1V8: R33.1 R328.2 R340.1 U5.F28 U35.1 | length 86.4
  1-TOP w0.2: v1(-14.605,17.145) U5.F28@-13.97,16.51 ; v1(61.4,24) 63.5,24 R340.1@65.5,24 ; R340.1@65.62,23.9 66,23.9 66.1,23.8 U35.1@66.5,23.8
  3-INTOP w0.15: v1(-14.605,17.145) -15.24,17.78 -15.24,18.452 -10.192,23.5 60.9,23.5 v1(61.4,24)
I2C2_SCL_3V3: J48.2 R34.1 R288.1 R290.1 R300.1 R340.2 U35.6 | length 84.2
  1-TOP w0.2: R340.2@65.62,25.1 66,25.1 66.1,25.2 U35.6@66.5,25.2 ; U35.6@66.5,25.28 66.5,25.7 66.8,26 70.48,26 R34.1@70.5,26.02 70.52,26 71.98,26 R288.1@72,26.02 ; R288.1@72,26 v1(75.6,26)
  6-INBOT w0.15: v1(75.6,26) 76.1,25.5 76.1,22.6 74.5,21 73.3,21 72,19.7 72,3.8 85.5,-9.7 85.5,-20.3 91.2,-26 98.35,-26 J48.2@101.08,-28.73
I2C2_SDA_1V8: R330.2 R361.1 R363.1 U5.E29 U35.4 | length 91
  1-TOP w0.2: v1(-15.875,18.415) U5.E29@-15.24,17.78 ; v1(61.4,26) R361.1@63.5,26 ; R361.1@63.5,26.02 v1(64.1,26.02) ; U35.4@67.5,25.2 67.9,25.2 68,25.1 R363.1@68.38,25.1 ; R363.1@68.5,25 v1(69.1,25)
  3-INTOP w0.15: v1(-15.875,18.415) -10.29,24 59.4,24 v1(61.4,26) ; v1(64.1,26.02) 68.08,26.02 v1(69.1,25)
I2C2_SDA_3V3: J48.4 R289.1 R293.1 R302.1 R362.1 R363.2 U35.3 | length 77.6
  1-TOP w0.2: U35.3@67.5,23.8 67.9,23.8 68,23.9 R363.2@68.38,23.9 ; R363.2@68.38,24 v1(75.6,24)
  6-INBOT w0.15: v1(75.6,24) 75.6,22.807 74.293,21.5 73.093,21.5 71.5,19.907 71.5,3.593 85,-9.907 85,-20.507 90.993,-26.5 96.31,-26.5 J48.4@98.54,-28.73
I2C3_SCL_1V8: J48.6 R286.1 R294.1 R296.1 R297.1 R301.1 U5.AK25 | length 150.9
  1-TOP w0.2: v1(8.4,-38.48) R294.1@9,-38.48 ; R294.1@8.9,-38.5 R297.1@10.5,-38.5 ; R297.1@10.5,-38.48 10.529,-38.509 13.471,-38.509 R286.1@13.5,-38.48 ; R286.1@13.5,-38.5 R301.1@15,-38.5 ; R301.1@15,-38.48 v1(15.6,-38.48) ; U5.AK25@16.51,12.7 v1(17.145,13.335)
  3-INTOP w0.15: v1(15.6,-38.48) 17.12,-40 52.9,-40 53.6,-39.3 64.2,-39.3 66,-37.5 80.2,-37.5 90.189,-27.511 94.781,-27.511 J48.6@96,-28.73
  6-INBOT w0.15: v1(8.4,-38.48) 8.905,-37.975 8.905,-26.295 15.24,-19.96 15.24,12.34 15.6,12.7 16.51,12.7 v1(17.145,13.335)
I2C3_SDA_1V8: J48.8 R287.1 R295.1 R298.1 R299.1 R303.1 U5.AK24 | length 146.7
  1-TOP w0.2: v1(8.4,-40.52) R295.1@9,-40.52 ; 9.395,-40.5 R298.1@12,-40.5 ; R298.1@12,-40.52 12.02,-40.5 13.48,-40.5 R287.1@13.5,-40.52 ; R287.1@13.5,-40.5 v1(15.6,-40.5) ; U5.AK24@16.51,11.43 v1(17.145,12.065)
  3-INTOP w0.15: v1(15.6,-40.5) 53.1,-40.5 53.85,-39.75 64.45,-39.75 65.2,-39 79.407,-39 88.407,-30 92.19,-30 J48.8@93.46,-28.73
  6-INBOT w0.15: v1(8.4,-40.52) 9.4,-39.52 9.4,-26.5 16.51,-19.39 16.51,11.43 v1(17.145,12.065)
IMX8_ON_OFF: R4.2 U5.AG18 | length 59.1
  1-TOP w0.2: U5.AG18@12.7,3.81 v1(13.335,4.445) ; v1(39,43) 39.5,43.5 R4.2@39.5,44.02
  3-INTOP w0.15: v1(13.335,4.445) 13.81,4.92 21.48,4.92 21.7,4.7 v1(24.5,4.7)
  6-INBOT w0.15: v1(24.5,4.7) 24.5,8.5 30,14 30,17.1 28.5,18.6 28.5,25.8 39,36.3 v1(39,43)
JTAG_SEL: J44.8 U5.F19 | length 55.9
  1-TOP w0.2: J44.8@-65.73,10.54 -64.454,10.54 v1(-57.914,4) ; v1(-14.605,5.715) U5.F19@-13.97,5.08
  3-INTOP w0.15: v1(-57.914,4) -22.6,4 -19.93,4 -19.9,3.97 -15.53,3.97 -15.2,4.3 -15.2,5.12 v1(-14.605,5.715)
JTAG_TCK: J20.4 U5.AG20 | length 45.7
  1-TOP w0.2: U5.AG20@12.7,6.35 v1(13.335,6.985) ; v1(19.17,45.7) J20.4@19.17,47.968
  3-INTOP w0.15: v1(13.335,6.985) 12.54,7.78 12.54,17.74 15.3,20.5 v1(16.5,20.5)
  6-INBOT w0.15: v1(16.5,20.5) 16.5,37.9 18,39.4 18,44.53 v1(19.17,45.7)
JTAG_TCK/GPIO_2: J12.3 U5.F25 | length 64.4
  1-TOP w0.2: J12.3@-63.968,20.23 -61.93,20.23 -60,18.3 -60,11.1 -54.9,6 -40,6 v1(-39.5,5.5) ; v1(-14.605,13.335) U5.F25@-13.97,12.7
  3-INTOP w0.15: v1(-26,14) -15.27,14 v1(-14.605,13.335)
  6-INBOT w0.15: v1(-39.5,5.5) -39,6 -34.02,6 v1@-26.01,14.01
JTAG_TDI: J20.8 U5.AH27 | length 33.9
  1-TOP w0.2: U5.AH27@13.97,15.24 v1(14.605,15.875) ; v1(16.8,45.7) J20.8@16.8,47.968
  6-INBOT w0.15: v1(14.605,15.875) 15.24,16.51 15.24,20.04 15.5,20.3 15.5,38.3 16.8,39.6 v1(16.8,45.7)
JTAG_TDI/GPIO_4: J12.7 R42.1 U5.B17 | length 59.3
  1-TOP w0.2: J12.7@-63.738,23 v1(-62.1,23) R42.1@-61.48,23 -61.48,22.58 -61.2,22.3 -59.8,22.3 -59,21.5 -59,11.5 -54.5,7 -39,7 v1(-37.5,5.5) ; v1(-19.685,3.175) U5.B17@-19.05,2.54
  8-BOTTOM w0.2: v1(-37.5,5.5) -35.175,3.175 v1(-19.685,3.175)
JTAG_TDO: J20.6 U5.AG21 | length 44.6
  1-TOP w0.2: U5.AG21@12.7,7.62 v1(13.335,8.255) ; J20.6@18,47.968 18,44 v1(19,43)
  3-INTOP w0.15: v1(13.335,8.255) 12.86,8.73 12.86,17.36 15.5,20 17,20 v1(17.5,20.5)
  6-INBOT w0.15: v1(17.5,20.5) 17.5,36.4 19,37.9 v1(19,43)
JTAG_TDO/GPIO_5: J12.5 R46.1 U5.B16 | length 58.1
  1-TOP w0.2: J12.5@-63.968,21.5 R46.1@-61.48,21.5 -61.48,20.68 -59.5,18.7 -59.5,11.3 -54.7,6.5 -39.5,6.5 v1(-38.5,5.5) ; v1(-19.685,1.905) U5.B16@-19.05,1.27
  8-BOTTOM w0.2: v1(-38.5,5.5) -34.905,1.905 v1(-19.685,1.905)
JTAG_TMS: J20.2 U5.AH28 | length 36.5
  1-TOP w0.2: U5.AH28@13.97,16.51 v1(14.605,17.145) ; v1(20.54,46.2) J20.2@20.54,47.968
  6-INBOT w0.15: v1(14.605,17.145) 14.605,20.2 15,20.595 15,38.6 15.4,39 15.4,45 16.6,46.2 v1(20.54,46.2)
JTAG_TMS/GPIO_3: J12.1 U5.E9 | length 65
  1-TOP w0.2: J12.1@-63.968,18.96 -61.56,18.96 -60.5,17.9 -60.5,10.879 ; -60.479,10.879 v1(-43.1,-6.5) ; v1(-15.875,-8.255) U5.E9@-15.24,-7.62
  3-INTOP w0.15: v1(-43.1,-6.5) -24.164,-6.5 -21.614,-9.05 -16.67,-9.05 v1(-15.875,-8.255)
JTAG_TRST_GPIO: R164.2 U5.AG19 | length 34.6
  1-TOP w0.2: v1(12,20.5) R164.2@12,38.02 ; U5.AG19@12.7,5.08 v1(13.335,5.715)
  3-INTOP w0.15: v1(12,20.5) 11.43,19.93 11.43,6.948 12.028,6.35 12.7,6.35 v1(13.335,5.715)
JTAG_TRST_L/GPIO_6: R53.1 U5.F23 | length 35.3
  1-TOP w0.2: R53.1@-44.5,5 v1(-43.88,5) ; v1(-14.605,10.795) U5.F23@-13.97,10.16
  3-INTOP w0.15: v1(-43.88,5) -22.1,5 -21.86,5.24 -16.86,5.24 -16.5,5.6 -16.5,5.8 -16,6.3 -15.74,6.3 -15.24,6.8 -15.24,10.16 v1(-14.605,10.795)
LED_1_1000: R176.1 R193.1 R202.2 U15.24 | length 7
  1-TOP w0.15: U15.24@-50.8,-35.95 -50.8,-36.5 -50.6,-36.7 -46.3,-36.7 -46.1,-36.9 R202.2@-46.1,-37.3
  1-TOP w0.2: R176.1@-45.98,-38.5 R202.2@-45.98,-37.3
LED_1_ACT: R182.1 R188.1 R197.2 U15.23 | length 8.5
  1-TOP w0.15: U15.23@-51.2,-35.95 -51.2,-36.6 -48.7,-39.1 -46.3,-39.1 -46.1,-39.3 R197.2@-46.1,-39.7
  1-TOP w0.2: R182.1@-45.98,-40.9 R197.2@-45.98,-39.7
LINE1_IN_L: J53.2 L35.1 | length 26
  1-TOP w0.2: L35.1@-56.6,46.08 -56.6,46.8 -46.8,56.6 -43.1,56.6 -41.8,57.9 -41.8,60.7 -40.42,62.08 J53.2@-39.27,62.08
LINE1_IN_R: J53.1 L34.1 | length 30.8
  1-TOP w0.2: L34.1@-57.7,46.08 -57.7,46.6 -47.1,57.2 -43.4,57.2 -42.4,58.2 -42.4,61.1 -40,63.5 -38.15,63.5 J53.1@-36.73,62.08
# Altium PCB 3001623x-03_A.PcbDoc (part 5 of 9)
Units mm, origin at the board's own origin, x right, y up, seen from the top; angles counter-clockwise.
Board outline 210 x 130 mm, 9 copper layers (1-TOP, 2-GND, 3-INTOP, 4-PWR, 5-PWR, 6-INBOT, Signal_4, 7-GND, 8-BOTTOM), stack 1.979 mm thick; 755 components, 650 nets, 2980 pads, 2365 vias.

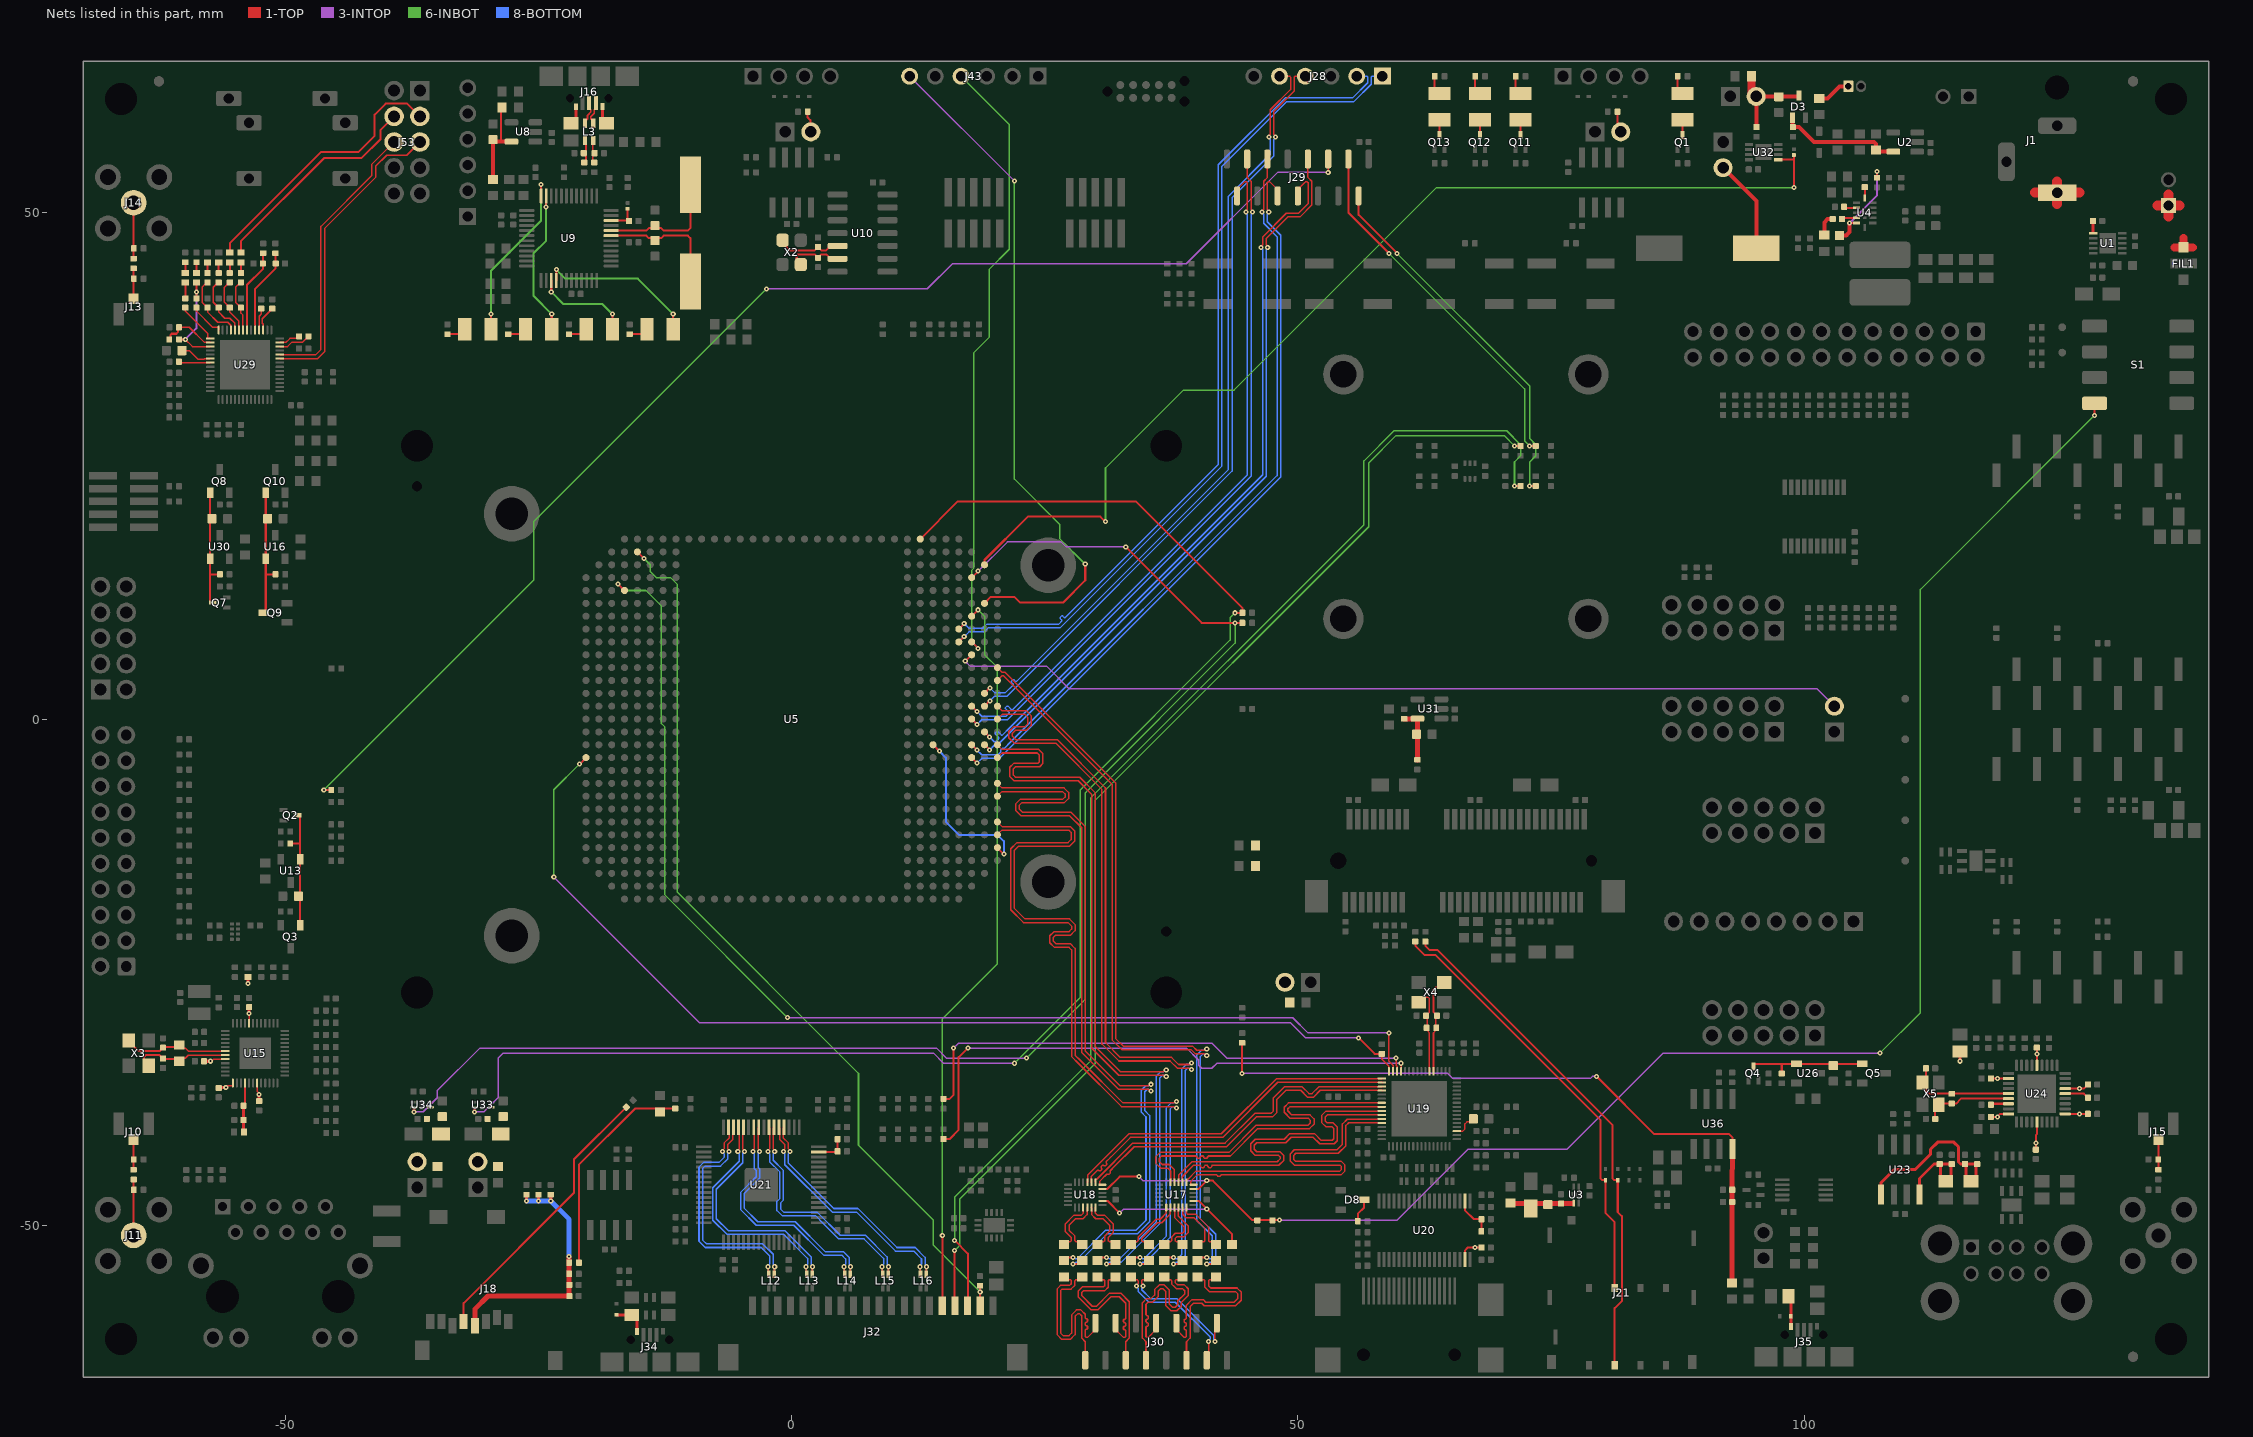
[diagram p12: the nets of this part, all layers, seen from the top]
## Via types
v1: diameter 0.5, hole 0.2, 1-TOP to 8-BOTTOM, 1743 vias
v2: diameter 0.5/0.5/0.5/0.5/0.5 (per signal layer), hole 0.2, 1-TOP to 8-BOTTOM, 440 vias
v3: diameter 0.68, hole 0.3, 1-TOP to 8-BOTTOM, 182 vias

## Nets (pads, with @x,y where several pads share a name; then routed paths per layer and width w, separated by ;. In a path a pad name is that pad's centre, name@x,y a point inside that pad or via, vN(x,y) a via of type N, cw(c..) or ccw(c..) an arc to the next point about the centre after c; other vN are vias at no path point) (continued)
LINE2_IN_L: J53.4 L37.1 | length 21.9
  1-TOP w0.2: L37.1@-54.4,46.08 -54.4,47.2 -46.2,55.4 -42.5,55.4 -40.6,57.3 -40.6,58.21 J53.4@-39.27,59.54
LINE2_IN_R: J53.3 L36.1 | length 27.2
  1-TOP w0.2: L36.1@-55.5,46.08 -55.5,47 -46.5,56 -42.8,56 -41.2,57.6 -41.2,59.7 -40.1,60.8 -37.99,60.8 J53.3@-36.73,59.54
LINE_OUT_L: J53.6 U29.24 | length 27.8
  1-TOP w0.15: U29.24@-50.57,36 -50,36 -47,36 -46.5,36.5 -46.5,48.666 -41.5,53.666 -41.5,54.77 J53.6@-39.27,57
LINE_OUT_R: J53.5 U29.23 | length 30.5
  1-TOP w0.15: U29.23@-50.57,35.6 -46.834,35.6 -46.1,36.334 -46.1,48.5 -41.1,53.5 -41.1,54.604 -40.004,55.7 -38.03,55.7 J53.5@-36.73,57
LT8912B_CLK_N: U17.16 U19.8 | length 33.7
  1-TOP w0.15: U17.16@37.8,-45.755 37.777,-45.732 37.777,-44.477 37.3,-44 36.6,-44 36.3,-43.7 36.3,-43.4 36.538,-43.162 39.675,-43.162 39.955,-43.162 40.025,-43.232 40.025,-43.32 40.095,-43.39 40.305,-43.39 40.375,-43.32 40.375,-43.232 40.445,-43.162 40.655,-43.162 40.725,-43.232 40.725,-43.32 40.795,-43.39 41.005,-43.39 41.075,-43.32 41.075,-43.232 41.145,-43.162 41.8,-43.162 43.338,-43.162 46.046,-40.454 51.163,-40.454 51.6,-40.017 51.6,-39.499 51.201,-39.1 49.4,-39.1 49.001,-38.701 49.001,-38.499 49.223,-38.277 58.297,-38.277 U19.8@58.32,-38.3
LT8912B_CLK_P: U17.17 U19.7 | length 33.7
  1-TOP w0.15: U17.17@37.4,-45.755 37.423,-45.732 37.423,-44.624 37.153,-44.354 36.453,-44.354 35.946,-43.847 35.946,-43.253 36.392,-42.808 43.192,-42.808 45.899,-40.1 51.016,-40.1 51.246,-39.87 51.246,-39.646 51.054,-39.454 49.253,-39.454 48.646,-38.847 48.646,-38.353 49.076,-37.923 58.297,-37.923 U19.7@58.32,-37.9
LT8912B_D0_N: U18.14 U19.2 | length 33.8
  1-TOP w0.15: U18.14@29.6,-45.755 29.577,-45.732 29.577,-45.207 29.892,-44.892 30.016,-44.768 30.214,-44.57 30.313,-44.57 30.376,-44.633 30.475,-44.633 30.623,-44.485 30.623,-44.386 30.56,-44.323 30.56,-44.224 30.709,-44.075 30.808,-44.075 30.871,-44.138 30.97,-44.138 31.118,-43.99 31.118,-43.891 31.055,-43.828 31.055,-43.729 31.484,-43.3 33.461,-41.323 42.578,-41.323 48.024,-35.877 58.297,-35.877 U19.2@58.32,-35.9
LT8912B_D0_P: U18.15 U19.1 | length 33.8
  1-TOP w0.15: U18.15@29.2,-45.755 29.223,-45.732 29.223,-45.061 33.315,-40.969 42.431,-40.969 47.877,-35.523 58.297,-35.523 U19.1@58.32,-35.5
LT8912B_D1_N: U18.12 U19.4 | length 33.7
  1-TOP w0.15: U18.12@30.695,-46 30.434,-46 30.409,-45.975 30.409,-45.675 30.8,-45.284 30.924,-45.161 31.122,-44.963 31.221,-44.963 31.24,-44.982 31.339,-44.982 31.487,-44.833 31.487,-44.734 31.468,-44.715 31.468,-44.616 31.9,-44.184 33.842,-42.242 42.958,-42.242 45.9,-39.3 47.5,-39.3 47.9,-38.9 47.9,-37.6 48.823,-36.677 50.276,-36.677 50.953,-37.354 51.546,-37.354 52.223,-36.677 58.297,-36.677 U19.4@58.32,-36.7
LT8912B_D1_P: U18.13 U19.3 | length 33.7
  1-TOP w0.15: U18.13@30,-45.755 30,-45.472 30.025,-45.448 30.136,-45.448 33.695,-41.888 42.811,-41.888 45.753,-38.946 47.353,-38.946 47.546,-38.753 47.546,-37.453 48.676,-36.323 50.423,-36.323 51.1,-37 51.399,-37 52.076,-36.323 58.297,-36.323 U19.3@58.32,-36.3
LT8912B_D2_N: U17.14 U19.10 | length 33.7
  1-TOP w0.15: U17.14@38.6,-45.755 38.577,-45.732 38.577,-45.207 39.704,-44.081 39.9,-44.081 40.075,-44.081 40.355,-44.081 40.425,-44.151 40.425,-44.239 40.495,-44.309 40.705,-44.309 40.775,-44.239 40.775,-44.151 40.845,-44.081 41.055,-44.081 41.125,-44.151 41.125,-44.239 41.195,-44.309 41.405,-44.309 41.475,-44.239 41.475,-44.151 41.545,-44.081 42.2,-44.081 48.119,-44.081 48.6,-43.6 48.6,-43.1 48.246,-42.746 45.946,-42.746 45.7,-42.5 45.7,-42.1 45.946,-41.854 48.8,-41.854 49.354,-41.3 51.499,-41.3 52.153,-41.954 53.599,-41.954 53.9,-41.653 53.9,-40.3 53.5,-39.9 52.907,-39.9 52.7,-39.693 52.7,-39.3 52.923,-39.077 58.297,-39.077 U19.10@58.32,-39.1
LT8912B_D2_P: U17.15 U19.9 | length 33.7
  1-TOP w0.15: U17.15@38.2,-45.755 38.223,-45.732 38.223,-45.061 39.557,-43.727 47.973,-43.727 48.246,-43.453 48.246,-43.247 48.099,-43.1 45.799,-43.1 45.346,-42.647 45.346,-41.953 45.799,-41.5 48.653,-41.5 49.207,-40.946 51.646,-40.946 52.3,-41.6 53.4,-41.6 53.546,-41.454 53.546,-40.447 53.353,-40.254 52.761,-40.254 52.346,-39.839 52.346,-39.153 52.776,-38.723 58.297,-38.723 U19.9@58.32,-38.7
LT8912B_D3_N: U17.12 U19.12 | length 33.9
  1-TOP w0.15: U17.12@39.695,-46 39.434,-46 39.409,-45.975 39.409,-45.675 40.084,-45 41.5,-45 41.675,-45 41.955,-45 42.025,-45.07 42.025,-45.097 42.095,-45.167 42.305,-45.167 42.375,-45.097 42.375,-45.07 42.445,-45 43,-45 43.6,-45 54.3,-45 54.654,-44.646 54.654,-44.054 54.3,-43.7 49.8,-43.7 49.6,-43.5 49.6,-43.1 49.8,-42.9 54,-42.9 54.754,-42.146 54.754,-40.146 55.023,-39.877 U19.12@58.197,-39.877 ; U19.12@58.22,-39.9 U19.12@58.197,-39.877 ; U19.12@58.297,-39.877 U19.12@58.197,-39.877
LT8912B_D3_P: U17.13 U19.11 | length 33.5
  1-TOP w0.15: 39.136,-45.448 39.938,-44.646 43.6,-44.646 43.747,-44.646 54.153,-44.646 54.3,-44.499 54.3,-44.201 54.153,-44.054 49.653,-44.054 49.246,-43.647 49.246,-42.953 49.653,-42.546 53.853,-42.546 54.4,-41.999 54.4,-39.999 54.876,-39.523 58.297,-39.523 U19.11@58.32,-39.5
LT8912B_INT: U5.D25 U19.63 | length 115.9
  1-TOP w0.15: v1(59,-31) 59,-33.8 59.4,-34.2 U19.63@59.4,-34.82
  1-TOP w0.2: v1(-17.145,13.335) U5.D25@-16.51,12.7
  3-INTOP w0.15: v1@-0.4,-29.494 49.494,-29.494 51,-31 v1(59,-31)
  6-INBOT w0.15: v1(-17.145,13.335) -16.51,12.7 -14.4,12.7 -12.86,11.16 -12.86,-0.44 -12.56,-0.74 -12.56,-17.34 v1(-0.4,-29.5)
LT8912B_RST: R225.2 U5.A12 U19.64 | length 104.2
  1-TOP w0.15: R225.2@58.3,-33.08 58.3,-33.6 59,-34.3 U19.64@59,-34.82
  1-TOP w0.2: v1(-20.955,-4.445) U5.A12@-20.32,-3.81 ; v1(56,-31.5) 57.58,-33.08 R225.2@58.3,-33.08
  3-INTOP w0.15: v1(-23.5,-15.607) -9.107,-30 49.285,-30 50.785,-31.5 v1(56,-31.5)
  6-INBOT w0.15: v1@-23.5,-15.6 -23.5,-6.99 v1(-20.955,-4.445)
LT8912B_SCL: R301.2 U19.62 | length 51.7
  1-TOP w0.15: v1(59.7,-33.5) 59.7,-34.2 59.8,-34.3 U19.62@59.8,-34.795
  1-TOP w0.2: R301.2@15,-37.52 15.6,-37.52 16,-37.12 v1(16,-32.5)
  3-INTOP w0.15: v1(16,-32.5) 16.5,-32 41.5,-32 43,-33.5 v1(59.7,-33.5)
LT8912B_SDA: R303.2 U19.61 | length 55.2
  1-TOP w0.15: U19.61@60.2,-34.795 v1(60.2,-34)
  1-TOP w0.2: R303.2@15,-41.48 15.6,-41.48 16.5,-40.58 16.5,-33.4 16.9,-33 16.907,-33 17.2,-32.707 17.2,-32.7 v1(17.4,-32.5)
  3-INTOP w0.15: v1@17.5,-32.5 39,-32.5 40.2,-33.7 40.2,-34.2 40.5,-34.5 41.5,-34.5 42,-34 v1(60.2,-34)
LVDS_CLK_N: L15.1 U21.39 | length 23
  1-TOP w0.15: v1(-2.325,-42.7) -2.325,-42.605 -2.177,-42.457 -2.177,-41.113 -2.185,-41.105 -2.185,-40.385 U21.39@-2.25,-40.32 ; v1(8.925,-54.1) 8.95,-54.125 8.95,-54.825 L15.1@8.975,-54.85
  8-BOTTOM w0.15: v1(-2.325,-42.7) -2.325,-42.795 -2.177,-42.943 -2.177,-43.724 -1.2,-44.701 -1.2,-47.4 -1.454,-47.654 -1.454,-48.547 -0.95,-49.05 2.35,-49.05 3.107,-49.808 4.653,-51.354 7.154,-51.354 9.073,-53.273 9.073,-53.857 8.925,-54.005 v1(8.925,-54.1)
LVDS_CLK_P: L15.4 U21.38 | length 23
  1-TOP w0.15: U21.38@-1.75,-40.32 -1.815,-40.385 -1.815,-41.105 -1.823,-41.113 -1.823,-42.457 -1.675,-42.605 v1(-1.675,-42.7) ; L15.4@9.525,-54.85 9.55,-54.825 9.55,-54.125 v1(9.575,-54.1)
  8-BOTTOM w0.15: v1(-1.675,-42.7) -1.675,-42.795 -1.823,-42.943 -1.823,-43.577 -0.846,-44.554 -0.846,-47.547 -1.1,-47.801 -1.1,-48.4 -0.804,-48.696 2.496,-48.696 4.8,-51 7.301,-51 9.427,-53.126 9.427,-53.857 9.575,-54.005 v1(9.575,-54.1)
LVDS_I2C_SCL: J32.17 R288.2 | length 116.7
  1-TOP w0.2: J32.17@16.1,-57.95 v1(16.1,-52.5) ; v1(71.4,26.98) R288.2@72,26.98
  6-INBOT w0.15: v1(16.1,-52.5) 16.6,-52 16.6,-47.4 30,-34 30,-8 57,19 57,25.3 59.7,28 69,28 70.38,28 v1(71.4,26.98)
LVDS_I2C_SDA: J32.18 R289.2 | length 123
  1-TOP w0.2: v1(16.1,-51.5) 17.4,-52.8 J32.18@17.4,-57.95 ; v1(71.4,23) R289.2@72,23
  6-INBOT w0.15: v1(16.1,-51.5) 16.1,-47.2 29.525,-33.775 29.525,-7.803 56.525,19.197 56.525,25.497 59.503,28.475 69.5,28.475 70.625,28.475 72,27.1 72,26 71.4,25.4 v1(71.4,23)
LVDS_IRQ_N: J32.19 R244.2 U5.E28 | length 89.9
  1-TOP w0.2: U5.E28@-15.24,16.51 v1(-14.605,15.875) ; J32.19@18.625,-57.95 v1(18.625,-56.6) R244.2@18.625,-55.98
  6-INBOT w0.15: v1(-14.605,15.875) -13.97,15.24 -13.97,14.568 -13.372,13.97 -11.97,13.97 -11.29,13.29 -11.29,-17.11 6.6,-35 6.6,-42.1 14,-49.5 14,-51.975 v1(18.625,-56.6)
LVDS_PWM_OUT: J32.16 U5.AL23 | length 72.7
  1-TOP w0.2: J32.16@14.875,-57.95 v1(14.875,-51) ; U5.AL23@17.78,10.16 v1(18.415,10.795)
  6-INBOT w0.15: v1(14.875,-51) 14.875,-29.625 20.32,-24.18 20.32,5.08 19.05,6.35 19.05,10.16 v1(18.415,10.795)
LVDS_TX0_N: L12.1 U21.47 | length 23
  1-TOP w0.15: v1(-6.825,-42.7) -6.825,-42.605 -6.677,-42.457 -6.677,-41.877 -6.177,-41.377 -6.177,-41.113 -6.185,-41.105 -6.185,-40.385 U21.47@-6.25,-40.32 ; v1(-2.325,-54.1) -2.3,-54.125 -2.3,-54.825 L12.1@-2.275,-54.85
  8-BOTTOM w0.15: v1(-6.825,-42.7) -6.825,-42.795 -6.677,-42.943 -6.677,-43.299 -7.178,-43.8 -8.701,-43.8 -9.154,-44.253 -9.154,-51.592 -8.546,-52.2 -3,-52.2 -2.177,-53.023 -2.177,-53.857 -2.325,-54.005 v1(-2.325,-54.1)
LVDS_TX0_P: L12.4 U21.46 | length 23
  1-TOP w0.15: v1(-6.175,-42.7) -6.175,-42.605 -6.323,-42.457 -6.323,-42.024 -5.823,-41.524 -5.823,-41.113 -5.815,-41.105 -5.815,-40.385 U21.46@-5.75,-40.32 ; L12.4@-1.725,-54.85 -1.7,-54.825 -1.7,-54.125 v1(-1.675,-54.1)
  8-BOTTOM w0.15: v1(-6.175,-42.7) -6.175,-42.795 -6.323,-42.943 -6.323,-43.445 -7.032,-44.154 -8.554,-44.154 -8.8,-44.4 -8.8,-51.445 -8.399,-51.846 -2.853,-51.846 -1.823,-52.876 -1.823,-53.857 -1.675,-54.005 v1(-1.675,-54.1)
LVDS_TX1_N: L13.1 U21.45 | length 23
  1-TOP w0.15: v1(-5.325,-42.7) -5.325,-42.605 -5.177,-42.457 -5.177,-41.113 -5.185,-41.105 -5.185,-40.385 U21.45@-5.25,-40.32 ; v1(1.425,-54.1) 1.45,-54.125 1.45,-54.825 L13.1@1.475,-54.85
  8-BOTTOM w0.15: v1(-5.325,-42.7) -5.325,-42.795 -5.177,-42.943 -5.177,-43.677 -7.8,-46.3 -7.8,-49.501 -6.401,-50.9 -0.8,-50.9 1.573,-53.273 1.573,-53.857 1.425,-54.005 v1(1.425,-54.1)
LVDS_TX1_P: L13.4 U21.44 | length 23
  1-TOP w0.15: U21.44@-4.75,-40.32 -4.815,-40.385 -4.815,-41.105 -4.823,-41.113 -4.823,-42.457 -4.675,-42.605 v1(-4.675,-42.7) ; L13.4@2.025,-54.85 2.05,-54.825 2.05,-54.125 v1(2.075,-54.1)
  8-BOTTOM w0.15: v1(-4.675,-42.7) -4.675,-42.795 -4.823,-42.943 -4.823,-43.824 -7.446,-46.447 -7.446,-49.354 -6.254,-50.546 -0.653,-50.546 1.927,-53.126 1.927,-53.857 2.075,-54.005 v1(2.075,-54.1)
LVDS_TX2_N: L14.1 U21.42 | length 23
  1-TOP w0.15: v1(-3.825,-42.7) -3.825,-42.605 -3.677,-42.457 -3.677,-41.113 -3.685,-41.105 -3.685,-40.385 U21.42@-3.75,-40.32 ; v1(5.175,-54.1) 5.2,-54.125 5.2,-54.825 L14.1@5.225,-54.85
  8-BOTTOM w0.15: v1(-3.825,-42.7) -3.825,-42.795 -3.677,-42.943 -3.677,-44.424 -3.5,-44.601 -3.5,-45.2 -5.054,-46.754 -5.054,-48.447 -3.501,-50 0.199,-50 3.153,-52.954 4.954,-52.954 5.323,-53.323 5.323,-53.857 5.175,-54.005 v1(5.175,-54.1)
LVDS_TX2_P: L14.4 U21.41 | length 23
  1-TOP w0.15: U21.41@-3.25,-40.32 -3.315,-40.385 -3.315,-41.105 -3.323,-41.113 -3.323,-42.457 -3.175,-42.605 v1(-3.175,-42.7) ; L14.4@5.775,-54.85 5.8,-54.825 5.8,-54.125 v1(5.825,-54.1)
  8-BOTTOM w0.15: v1(-3.175,-42.7) -3.175,-42.795 -3.323,-42.943 -3.323,-44.277 -3.25,-44.35 -3.146,-44.454 -3.146,-45.347 -4.7,-46.901 -4.7,-48.3 -3.354,-49.646 0.346,-49.646 3.3,-52.6 5.101,-52.6 5.677,-53.176 5.677,-53.857 5.825,-54.005 v1(5.825,-54.1)
LVDS_TX3_N: L16.1 U21.37 | length 23
  1-TOP w0.15: U21.37@-1.25,-40.32 -1.185,-40.385 -1.185,-41.105 -1.177,-41.113 -1.177,-41.524 -0.677,-42.024 -0.677,-42.457 -0.825,-42.605 v1(-0.825,-42.7) ; v1(12.675,-54.1) 12.7,-54.125 12.7,-54.825 L16.1@12.725,-54.85
  8-BOTTOM w0.15: v1(-0.825,-42.7) -0.825,-42.795 -0.677,-42.943 -0.677,-44.02 4.003,-48.7 6.4,-48.7 10.253,-52.553 12.053,-52.553 12.823,-53.323 12.823,-53.857 12.675,-54.005 v1(12.675,-54.1)
LVDS_TX3_P: L16.4 U21.36 | length 23
  1-TOP w0.15: U21.36@-0.75,-40.32 -0.815,-40.385 -0.815,-41.105 -0.823,-41.113 -0.823,-41.377 -0.323,-41.877 -0.323,-42.457 -0.175,-42.605 v1(-0.175,-42.7) ; L16.4@13.275,-54.85 13.3,-54.825 13.3,-54.125 v1(13.325,-54.1)
  8-BOTTOM w0.15: v1(-0.175,-42.7) -0.175,-42.795 -0.323,-42.943 -0.323,-43.874 4.149,-48.346 6.547,-48.346 10.4,-52.199 12.2,-52.199 13.177,-53.176 13.177,-53.857 13.325,-54.005 v1(13.325,-54.1)
MCA_CLKOUT32K: J43.4 U5.AL21 | length 61.2
  1-TOP w0.2: U5.AL21@17.78,7.62 v1(18.415,6.985)
  6-INBOT w0.15: J43.4@16.73,63.5 21.5,58.73 21.5,46.4 19.5,44.4 19.5,37.7 18,36.2 18,14.92 17.8,14.72 17.8,7.6 v1(18.415,6.985)
MCA_IO9: R348.1 U5.AG29 U33.4 | length 151.3
  1-TOP w0.2: U5.AG29@12.7,17.78 16.42,21.5 34,21.5 44.52,10.98 R348.1@44.52,10.5 v1(43.8,10.5)
  1-TOP w0.3: v1(-31.31,-38.8) U33.4@-31.31,-38.4
  3-INTOP w0.15: v1(-31.31,-38.8) -30.4,-38.8 -29,-37.4 -29,-33.5 -28.5,-33 14,-33 15,-34 v1(22,-34)
  6-INBOT w0.15: v1(22,-34) 28.5,-27.5 28.5,-7 43.3,7.8 43.3,10 v1(43.8,10.5)
MCA_IO14: R341.1 U5.AL26 U34.4 | length 147.4
  1-TOP w0.2: U5.AL26@17.78,13.97 v1(18.415,14.605) ; v1(33,17) 40.5,9.5 v1(43.8,9.5) R341.1@44.52,9.5
  1-TOP w0.3: v1(-37.31,-38.8) U34.4@-37.31,-38.4
  3-INTOP w0.15: v1(-37.31,-38.8) -36.4,-38.8 -35,-37.4 -35,-36.7 -30.8,-32.5 14.3,-32.5 15.3,-33.5 v1(23.2,-33.5) ; v1(18.415,14.605) 21.31,17.5 26.6,17.5 27.1,17 v1(33,17)
  6-INBOT w0.15: v1(23.2,-33.5) 29,-27.7 29,-7.3 43.8,7.5 v1(43.8,9.5)
MCA_VIN_DET: R339.2 U5.AM27 U32.1 | length 103.9
  1-TOP w0.2: U5.AM27@19.05,15.24 19.05,15.71 23.34,20 30.5,20 v1(31,19.5) ; U32.1@97.45,55.25 99,55.25 ; v1(99,52.5) 99,55.25 ; R339.2@99,55.715 99,55.25
  6-INBOT w0.15: v1(31,19.5) 31,24.8 38.7,32.5 43.7,32.5 63.7,52.5 v1(99,52.5)
MCA_VREF_OUT: J43.6 U5.AM24 | length 68.3
  1-TOP w0.2: U5.AM24@19.05,11.43 19.685,12.065 22,12.065 22.565,11.5 26.8,11.5 29,13.7 v1(29,15.3)
  3-INTOP w0.15: J43.6@11.65,63.5 v1(22,53.15)
  6-INBOT w0.15: v1(22,53.15) 22,23.7 26.5,19.2 26.5,17.8 v1(29,15.3)
MIC_BIAS: C146.2 L32.2 R273.1 U29.45 | length 10.2
  1-TOP w0.15: v1(-59.9,37.5) -59.2,36.8 U29.45@-57.43,36.8
  1-TOP w0.2: R273.1@-60.52,37.5 v1(-59.9,37.5) ; C146.2@-58.8,41.5 C146.2@-58.8,41.56 L32.2@-58.8,43.12
  3-INTOP w0.2: v1(-59.9,37.5) -58.8,38.6 v1(-58.8,42.2)
MIC_N: L33.1 R275.1 | length 1
  1-TOP w0.2: L33.1@-59.9,44.08 R275.1@-59.9,45.12
MIC_P: L32.1 R274.1 | length 1
  1-TOP w0.2: L32.1@-58.8,44.08 R274.1@-58.8,45.12
MIPI_CSI_CLK_N: J29.8 U5.AM14 | length 73.7
  1-TOP w0.15: v1(46.375,46.6) 46.375,46.695 46.523,46.843 46.523,47.624 48.853,49.954 50.054,49.954 51.023,50.923 51.023,52.976 50.912,53.087 50.787,53.087 50,52.3 J29.8@50,51.675
  1-TOP w0.2: U5.AM14@18.95,-1.17 U5.AM14@19.05,-1.27 v1(19.558,-1.778)
  8-BOTTOM w0.15: v1@19.485,-1.705 v1(19.558,-1.778) 20.016,-2.236 20.164,-2.236 20.4,-2 20.474,-1.926 20.474,-1.827 20.111,-1.464 20.111,-1.365 20.26,-1.216 20.359,-1.216 20.722,-1.579 20.821,-1.579 21.019,-1.381 21.35,-1.05 46.523,24.123 46.523,46.357 46.375,46.505 v1(46.375,46.6)
MIPI_CSI_CLK_P: J29.7 U5.AM13 | length 73.6
  1-TOP w0.15: v1(47.025,46.6) 47.025,46.695 46.877,46.843 46.877,47.477 49,49.6 50.201,49.6 51.377,50.776 51.377,53.121 51,53.498 J29.7@51,55.325
  1-TOP w0.2: U5.AM13@18.95,-2.44 U5.AM13@19.05,-2.54 v1(19.558,-3.048)
  8-BOTTOM w0.15: v1(19.558,-3.048) 20.016,-2.59 20.311,-2.59 46.877,23.976 46.877,46.357 47.025,46.505 v1(47.025,46.6)
MIPI_CSI_DATA0_N: J29.14 U5.AL16 | length 69.7
  1-TOP w0.15: J29.14@44,51.675 44,52.3 44.787,53.087 44.912,53.087 45.023,52.976 45.023,50.343 44.875,50.195 v1(44.875,50.1)
  1-TOP w0.2: U5.AL16@17.78,1.27 v1(18.315,0.735)
  8-BOTTOM w0.15: v1(18.315,0.735) 18.773,0.277 21.177,0.277 21.4,0.5 21.474,0.574 21.474,0.673 21.111,1.036 21.111,1.135 21.26,1.284 21.359,1.284 21.722,0.921 21.821,0.921 22.019,1.119 22.65,1.75 45.023,24.123 45.023,49.857 44.875,50.005 v1(44.875,50.1)
MIPI_CSI_DATA0_P: J29.13 U5.AL15 | length 69.6
  1-TOP w0.15: J29.13@45,55.325 45,53.498 45.377,53.121 45.377,50.343 45.525,50.195 v1(45.525,50.1)
  1-TOP w0.2: U5.AL15@17.78,0 v1(18.315,-0.535)
  8-BOTTOM w0.15: v1(18.315,-0.535) 18.773,-0.077 21.324,-0.077 45.377,23.976 45.377,49.857 45.525,50.005 v1(45.525,50.1)
MIPI_CSI_DATA1_N: J29.11 U5.AL13 | length 74.2
  1-TOP w0.15: v1(46.475,50.1) 46.475,50.195 46.623,50.343 46.623,53.121 47,53.498 J29.11@47,55.325
  1-TOP w0.2: U5.AL13@17.78,-2.54 v1(18.315,-3.075)
  8-BOTTOM w0.15: v1(18.315,-3.075) 18.773,-3.533 20.367,-3.533 20.6,-3.3 20.674,-3.226 20.674,-3.127 20.674,-3.028 20.823,-2.879 20.922,-2.879 21.021,-2.879 21.6,-2.3 47.946,24.046 47.946,47.653 46.623,48.976 46.623,49.857 46.475,50.005 v1(46.475,50.1)
MIPI_CSI_DATA1_P: J29.10 U5.AL12 | length 74.2
  1-TOP w0.15: v1(47.125,50.1) 47.125,50.195 46.977,50.343 46.977,52.976 47.088,53.087 47.213,53.087 48,52.3 J29.10@48,51.675
  1-TOP w0.2: U5.AL12@17.78,-3.81 v1(18.315,-4.345)
  8-BOTTOM w0.15: v1(18.315,-4.345) 18.773,-3.887 20.514,-3.887 48.3,23.899 48.3,47.8 46.977,49.123 46.977,49.857 47.125,50.005 v1(47.125,50.1)
MIPI_CSI_DATA2_N: J28.5 U5.AM17 | length 76.8
  1-TOP w0.15: v1(47.135,57.5) 47.135,57.595 47.283,57.743 47.283,60.183 49.283,62.183 49.283,63.412 49.195,63.5 J28.5@48.19,63.5
  1-TOP w0.2: U5.AM17@19.05,2.54 v1(19.585,3.075)
  8-BOTTOM w0.15: v1(19.585,3.075) 20.043,2.617 21.117,2.617 21.8,3.3 21.874,3.374 21.874,3.473 21.708,3.64 21.708,3.739 21.856,3.887 21.955,3.887 22.122,3.721 22.221,3.721 22.419,3.919 23.25,4.75 43.146,24.646 43.146,51.647 47.283,55.784 47.283,57.257 47.135,57.405 v1(47.135,57.5)
MIPI_CSI_DATA2_P: J28.4 U5.AM16 | length 76.8
  1-TOP w0.15: v1(47.785,57.5) 47.785,57.595 47.637,57.743 47.637,60.036 49.637,62.036 49.637,63.412 49.725,63.5 J28.4@50.73,63.5
  1-TOP w0.2: U5.AM16@19.05,1.27 v1(19.585,1.805)
  8-BOTTOM w0.15: v1(19.585,1.805) 20.043,2.263 21.264,2.263 43.5,24.499 43.5,51.5 47.637,55.637 47.637,57.257 47.785,57.405 v1(47.785,57.5)
MIPI_CSI_DATA3_N: J28.2 U5.AK22 | length 82.7
  1-TOP w0.2: U5.AK22@16.51,8.89 v1(17.045,9.425)
  8-BOTTOM w0.15: v1(17.045,9.425) 17.503,8.967 18.866,8.967 19.253,9.354 26.354,9.354 26.6,9.6 26.674,9.674 26.674,9.773 26.508,9.94 26.508,10.039 26.656,10.187 26.755,10.187 26.922,10.021 27.021,10.021 27.219,10.219 27.85,10.85 42.146,25.146 42.146,54.747 48.753,61.354 55.394,61.354 56.903,62.863 56.903,63.412 56.815,63.5 J28.2@55.81,63.5
MIPI_CSI_DATA3_P: J28.1 U5.AK21 | length 82.7
  1-TOP w0.2: U5.AK21@16.51,7.62 v1(17.045,8.155)
  8-BOTTOM w0.15: v1(17.045,8.155) 17.503,8.613 19.013,8.613 19.4,9 26.501,9 42.5,24.999 42.5,54.6 48.9,61 55.541,61 57.257,62.716 57.257,63.412 57.345,63.5 J28.1@58.35,63.5
MIPI_CSI_I2C_SCL: J29.3 R290.2 | length 36.4
  1-TOP w0.2: J29.3@55,55.325 55,50 v1(59,46) ; v1(72.9,26.98) R290.2@73.5,26.98
  6-INBOT w0.15: v1(59,46) 72.392,32.608 72.392,27.488 v1(72.9,26.98)
MIPI_CSI_I2C_SDA: J29.2 R293.2 | length 36.8
  1-TOP w0.2: J29.2@56,51.675 56,49.8 v1(59.8,46) ; v1(72.9,23) R293.2@73.5,23
  6-INBOT w0.15: v1(59.8,46) 72.9,32.9 72.9,27.7 73.5,27.1 73.5,26 72.9,25.4 v1(72.9,23)
MIPI_CSI_RESET_N: J29.5 R352.1 | length 129.9
  1-TOP w0.15: v1(53,54) J29.5@53,55.325
  1-TOP w0.2: v1(-46.22,-7) R352.1@-45.48,-7
  3-INTOP w0.15: v1(-2.5,42.5) 13.4,42.5 15.88,44.98 38.98,44.98 48,54 v1(53,54)
  6-INBOT w0.15: v1(-46.22,-7) -25.51,13.71 ; -25.5,13.7 -25.5,19.5 v1(-2.5,42.5)
MIPI_DSI_CLK_N: R206.1 R207.1 U5.AN6 | length 74.8
  1-TOP w0.15: U5.AN6@20.32,-11.43 20.778,-10.972 27.372,-10.972 27.6,-11.2 27.6,-11.9 27.3,-12.2 22.251,-12.2 21.646,-12.805 21.646,-18.847 22.899,-20.1 27.3,-20.1 27.646,-20.446 27.646,-20.747 27.393,-21 25.9,-21 25.5,-21.4 25.5,-22.1 25.954,-22.554 27.4,-22.554 27.646,-22.8 27.646,-33.346 28.35,-34.05 32.577,-38.277 37.757,-38.277 37.905,-38.425 v1(38,-38.425)
  1-TOP w0.2: v1(34.4,-53.825) R206.1@35.5,-53.825
  8-BOTTOM w0.15: v1(34.4,-53.825) 34.495,-53.825 34.643,-53.677 34.924,-53.677 37.377,-51.224 37.377,-38.524 37.624,-38.277 37.757,-38.277 37.905,-38.425 v1(38,-38.425)
MIPI_DSI_CLK_P: R204.1 R205.1 U5.AN7 | length 74.8
  1-TOP w0.15: U5.AN7@20.32,-10.16 20.778,-10.618 27.519,-10.618 27.954,-11.053 27.954,-12.047 27.447,-12.554 22.398,-12.554 22,-12.952 22,-18.7 23.046,-19.746 27.447,-19.746 28,-20.299 28,-20.893 27.539,-21.354 26.047,-21.354 25.854,-21.547 25.854,-21.953 26.101,-22.2 27.547,-22.2 28,-22.653 28,-33.199 28.497,-33.696 28.6,-33.8 32.724,-37.923 37.757,-37.923 37.905,-37.775 v1(38,-37.775)
  1-TOP w0.2: R204.1@33.3,-53.175 v1(34.4,-53.175)
  8-BOTTOM w0.15: v1(34.4,-53.175) 34.495,-53.175 34.643,-53.323 34.777,-53.323 37.023,-51.077 37.023,-38.377 37.477,-37.923 37.757,-37.923 37.905,-37.775 v1(38,-37.775)
MIPI_DSI_DATA0_N: R210.1 R211.1 U5.AN9 | length 74.8
  1-TOP w0.15: U5.AN9@20.32,-7.62 20.778,-7.162 26.761,-7.162 27,-7.401 27,-7.7 26.8,-7.9 22.599,-7.9 22.146,-8.353 22.146,-9.047 22.653,-9.554 27.453,-9.554 28.646,-10.747 28.646,-32.932 32.291,-36.577 35.257,-36.577 35.405,-36.725 v1(35.5,-36.725)
  1-TOP w0.2: v1(27.8,-53.825) R211.1@28.9,-53.825
  8-BOTTOM w0.15: v1(27.8,-53.825) 27.895,-53.825 28.043,-53.677 28.324,-53.677 31.147,-50.854 34.146,-50.854 35.354,-49.646 35.354,-39.153 34.877,-38.676 34.877,-36.824 35.124,-36.577 35.257,-36.577
MIPI_DSI_DATA0_P: R208.1 R209.1 U5.AN10 | length 74.8
  1-TOP w0.15: U5.AN10@20.32,-6.35 20.778,-6.808 26.908,-6.808 27.354,-7.254 27.354,-7.847 26.947,-8.254 22.746,-8.254 22.5,-8.5 22.5,-8.9 22.8,-9.2 27.6,-9.2 29,-10.6 29,-32.785 32.438,-36.223 35.257,-36.223 35.405,-36.075 v1(35.5,-36.075)
  1-TOP w0.2: R208.1@26.7,-53.175 v1(27.8,-53.175)
  8-BOTTOM w0.15: v1(27.8,-53.175) 27.895,-53.175 28.043,-53.323 28.177,-53.323 31,-50.5 33.999,-50.5 35,-49.499 35,-39.3 34.523,-38.823 34.523,-36.677 34.977,-36.223 35.257,-36.223
MIPI_DSI_DATA1_N: R214.1 R215.1 U5.AN12 | length 74.8
  1-TOP w0.15: U5.AN12@20.32,-3.81 20.778,-3.352 24.251,-3.352 24.446,-3.547 24.446,-4.253 24.353,-4.346 21.953,-4.346 21.546,-4.753 21.546,-5.685 21.961,-6.1 28.299,-6.1 29.646,-7.447 29.646,-32.518 32.305,-35.177 36.757,-35.177 36.905,-35.325 v1(37,-35.325)
  1-TOP w0.2: v1(31.1,-53.825) R214.1@32.2,-53.825
  8-BOTTOM w0.15: v1(31.1,-53.825) 31.195,-53.825 31.343,-53.677 31.575,-53.677 32.523,-53.677 36.377,-49.823 36.377,-35.424 36.624,-35.177 36.757,-35.177 36.905,-35.325 v1(37,-35.325)
MIPI_DSI_DATA1_P: R212.1 R213.1 U5.AN13 | length 74.8
  1-TOP w0.15: U5.AN13@20.32,-2.54 20.778,-2.998 24.398,-2.998 24.8,-3.4 24.8,-4.4 24.5,-4.7 22.1,-4.7 21.9,-4.9 21.9,-5.539 22.107,-5.746 28.446,-5.746 30,-7.3 30,-32.371 32.452,-34.823 36.757,-34.823 36.905,-34.675 v1(37,-34.675)
  1-TOP w0.2: R213.1@30,-53.175 v1(31.1,-53.175)
  8-BOTTOM w0.15: v1(31.1,-53.175) 31.195,-53.175 31.343,-53.323 31.722,-53.323 32.376,-53.323 36.023,-49.676 36.023,-35.277 36.477,-34.823 36.757,-34.823 36.905,-34.675 v1(37,-34.675)
MIPI_DSI_DATA2_N: R218.1 R219.1 U5.AN15 | length 74.8
  1-TOP w0.15: U5.AN15@20.32,0 20.778,0.458 23.041,0.458 23.3,0.199 23.3,-0.499 23.053,-0.746 21.953,-0.746 21.446,-1.253 21.446,-1.847 21.999,-2.4 26.099,-2.4 30.646,-6.947 30.646,-32.103 32.32,-33.777 37.376,-33.777 38.076,-34.477 39.257,-34.477 39.405,-34.625 v1(39.5,-34.625)
  1-TOP w0.2: v1(37.7,-53.825) R219.1@38.8,-53.825
  8-BOTTOM w0.15: v1(37.7,-53.825) 37.795,-53.825 37.943,-53.677 38.175,-53.677 38.224,-53.677 38.877,-53.024 38.877,-34.724 39.124,-34.477 39.257,-34.477 39.405,-34.625 v1(39.5,-34.625)
MIPI_DSI_DATA2_P: R216.1 R217.1 U5.AN16 | length 74.8
  1-TOP w0.15: U5.AN16@20.32,1.27 20.778,0.812 23.188,0.812 23.654,0.346 23.654,-0.646 23.2,-1.1 22.1,-1.1 21.8,-1.4 21.8,-1.7 22.146,-2.046 26.246,-2.046 31,-6.8 31,-31.957 32.466,-33.423 37.523,-33.423 38.223,-34.123 39.257,-34.123 39.405,-33.975 v1(39.5,-33.975)
  1-TOP w0.2: R217.1@36.6,-53.175 v1(37.7,-53.175)
  8-BOTTOM w0.15: v1(37.7,-53.175) 37.795,-53.175 37.943,-53.323 38.077,-53.323 38.523,-52.877 38.523,-34.577 38.977,-34.123 39.257,-34.123 39.405,-33.975 v1(39.5,-33.975)
MIPI_DSI_DATA3_N: R222.1 R223.1 U5.AN18 | length 74.8
  1-TOP w0.15: U5.AN18@20.32,3.81 20.778,4.268 20.931,4.268 31.646,-6.447 31.646,-31.689 32.611,-32.654 39.453,-32.654 39.876,-33.077 40.757,-33.077 40.905,-33.225 v1(41,-33.225)
  1-TOP w0.2: v1(41,-53.825) R223.1@42.1,-53.825
  8-BOTTOM w0.15: v1(41,-53.825) 41.095,-53.825 41.243,-53.677 41.524,-53.677 41.9,-53.301 41.9,-50.9 40.377,-49.377 40.377,-33.324 40.624,-33.077 40.757,-33.077 40.905,-33.225 v1(41,-33.225)
MIPI_DSI_DATA3_P: R220.1 R221.1 U5.AN19 | length 74.8
  1-TOP w0.15: U5.AN19@20.32,5.08 20.778,4.622 21.078,4.622 32,-6.3 32,-31.543 32.757,-32.3 39.6,-32.3 40.023,-32.723 40.757,-32.723 40.905,-32.575 v1(41,-32.575)
  1-TOP w0.2: R221.1@39.9,-53.175 v1(41,-53.175)
  8-BOTTOM w0.15: v1(41,-53.175) 41.095,-53.175 41.243,-53.323 41.377,-53.323 41.546,-53.154 41.546,-51.047 40.023,-49.524 40.023,-33.177 40.477,-32.723 40.757,-32.723 40.905,-32.575 v1(41,-32.575)
MIPI_EXT_CLK_N: J30.14 R207.2 | length 13.5
  1-TOP w0.15: v1(34.725,-56) 34.725,-55.905 34.577,-55.757 34.577,-55.477 34.665,-55.389 35.011,-55.389 R207.2@35.3,-55.1 ; v1@41.8,-61.5 41.8,-59.875 J30.14@42,-59.675
  8-BOTTOM w0.15: v1(34.725,-56) 34.725,-56.095 34.577,-56.243 34.577,-56.377 35.446,-57.246 38.047,-57.246 41.677,-60.876 41.677,-61.257 41.825,-61.405 v1(41.825,-61.5)
MIPI_EXT_CLK_P: J30.13 R205.2 | length 13.5
  1-TOP w0.15: R205.2@33.5,-55.1 33.789,-55.389 34.135,-55.389 34.223,-55.477 34.223,-55.757 34.075,-55.905 v1(34.075,-56) ; J30.13@41,-63.325 41.2,-63.125 v1@41.2,-61.499
  8-BOTTOM w0.15: v1(34.075,-56) 34.075,-56.095 34.223,-56.243 34.223,-56.524 35.299,-57.6 37.9,-57.6 41.323,-61.023 41.323,-61.257 41.175,-61.405 v1(41.175,-61.5)
MIPI_EXT_DATA0_N: J30.2 R211.2 | length 16.7
  1-TOP w0.15: R211.2@28.7,-55.1 28.411,-55.389 28.065,-55.389 27.977,-55.477 27.977,-55.923 27.6,-56.3 26.701,-56.3 26.6,-56.401 26.6,-60.693 26.807,-60.9 27.4,-60.9 27.646,-60.654 27.646,-58.854 28.131,-58.369 28.57,-58.369 29.001,-58.8 29.001,-59.155 29.071,-59.225 29.152,-59.225 29.222,-59.295 29.222,-59.505 29.152,-59.575 29.071,-59.575 29.001,-59.645 29.001,-59.855 29.071,-59.925 29.152,-59.925 29.222,-59.995 29.222,-60.205 29.152,-60.275 29.071,-60.275 29.001,-60.345 29.001,-60.625 29.001,-60.8 29.001,-60.999 29.089,-61.087 29.213,-61.087 30,-60.3 J30.2@30,-59.675
MIPI_EXT_DATA0_P: J30.1 R209.2 | length 16.6
  1-TOP w0.15: R209.2@26.9,-55.1 27.189,-55.389 27.535,-55.389 27.623,-55.477 27.623,-55.776 27.453,-55.946 26.554,-55.946 26.246,-56.254 26.246,-60.839 26.661,-61.254 27.547,-61.254 28,-60.801 28,-59.001 28.277,-58.723 28.423,-58.723 28.647,-58.947 28.647,-61.146 29,-61.499 J30.1@29,-63.325
MIPI_EXT_DATA1_N: J30.5 R215.2 | length 16.6
  1-TOP w0.15: R215.2@32,-55.1 31.711,-55.389 31.365,-55.389 31.277,-55.477 31.277,-56.123 30.946,-56.454 28.847,-56.454 28.654,-56.647 28.654,-56.953 29.701,-58 30.099,-58 31.399,-56.7 32.5,-56.7 33.353,-57.553 33.353,-61.146 33,-61.499 J30.5@33,-63.325
MIPI_EXT_DATA1_P: J30.4 R213.2 | length 16.7
  1-TOP w0.15: R213.2@30.2,-55.1 30.489,-55.389 30.835,-55.389 30.923,-55.477 30.923,-55.645 30.923,-55.976 30.799,-56.1 28.7,-56.1 28.3,-56.5 28.3,-57.1 29.554,-58.354 30.246,-58.354 31.546,-57.054 32.353,-57.054 32.999,-57.7 32.999,-59 32.999,-59.205 32.929,-59.275 32.848,-59.275 32.778,-59.345 32.778,-59.555 32.848,-59.625 32.929,-59.625 32.999,-59.695 32.999,-59.905 32.929,-59.975 32.848,-59.975 32.778,-60.045 32.778,-60.255 32.848,-60.325 32.929,-60.325 32.999,-60.395 32.999,-60.5 32.999,-60.999 32.911,-61.087 32.787,-61.087 32,-60.3 J30.4@32,-59.675
MIPI_EXT_DATA2_N: J30.8 R219.2 | length 16.8
  1-TOP w0.15: 35.001,-58.6 35.001,-58.5 ; J30.8@36,-59.675 36,-60.3 35.213,-61.087 35.089,-61.087 35.001,-60.999 35.001,-60.5 35.001,-60.325 35.001,-60.045 35.071,-59.975 35.153,-59.975 35.223,-59.905 35.223,-59.695 35.153,-59.625 35.071,-59.625 35.001,-59.555 35.001,-59.345 35.071,-59.275 35.153,-59.275 35.223,-59.205 35.223,-58.995 35.153,-58.925 35.071,-58.925 35.001,-58.855 35.001,-58.5 ; R219.2@38.6,-55.1 38.311,-55.389 37.965,-55.389 37.877,-55.477 37.877,-55.645 38.132,-55.9 38.8,-55.9 39.173,-56.273 39.173,-56.928 38.5,-57.601 38.5,-58 38.046,-58.454 37.461,-58.454 36.946,-57.939 36.946,-56.547 36.653,-56.254 36.447,-56.254 36.2,-56.501 36.2,-57.039 35.639,-57.6 35.208,-57.6 35.001,-57.807 35.001,-58.5
MIPI_EXT_DATA2_P: J30.7 R217.2 | length 16.6
  1-TOP w0.15: J30.7@35,-63.325 35,-61.499 34.647,-61.146 34.647,-57.655 35.056,-57.246 35.493,-57.246 35.842,-56.897 35.842,-56.358 36.3,-55.9 36.8,-55.9 37.3,-56.4 37.3,-57.793 37.607,-58.1 37.899,-58.1 38.146,-57.853 38.146,-57.454 38.819,-56.781 38.819,-56.481 38.592,-56.254 37.985,-56.254 37.746,-56.015 37.523,-55.792 37.523,-55.477 37.435,-55.389 37.089,-55.389 R217.2@36.8,-55.1
MIPI_EXT_DATA3_N: J30.11 R223.2 | length 16.6
  1-TOP w0.15: J30.11@39,-63.325 39,-61.499 39.353,-61.146 39.353,-58.047 39.7,-57.7 40.499,-57.7 40.753,-57.954 43.847,-57.954 44.4,-57.401 44.4,-56.6 44,-56.2 41.4,-56.2 41.177,-55.977 41.177,-55.792 41.177,-55.477 41.265,-55.389 41.611,-55.389 R223.2@41.9,-55.1
MIPI_EXT_DATA3_P: J30.10 R221.2 | length 16.7
  1-TOP w0.15: J30.10@38,-59.675 38,-60.3 38.787,-61.087 38.911,-61.087 38.999,-60.999 38.999,-60.5 38.999,-60.395 38.929,-60.325 38.848,-60.325 38.778,-60.255 38.778,-60.045 38.848,-59.975 38.929,-59.975 38.999,-59.905 38.999,-59.695 38.929,-59.625 38.848,-59.625 38.778,-59.555 38.778,-59.345 38.848,-59.275 38.929,-59.275 38.999,-59.205 38.999,-58 38.999,-57.9 39.553,-57.346 40.646,-57.346 40.9,-57.6 43.7,-57.6 44.046,-57.254 44.046,-56.747 43.853,-56.554 41.253,-56.554 40.823,-56.124 40.823,-55.645 40.823,-55.477 40.735,-55.389 40.389,-55.389 R221.2@40.1,-55.1
MIPI_SWITCH_CLK_N: R206.2 U17.2 | length 5.6
  1-TOP w0.15: R206.2@35.3,-51.9 35.011,-51.611 34.665,-51.611 34.577,-51.523 34.577,-51.323 36.146,-49.754 36.547,-49.754 37.377,-48.924 37.377,-48.268 U17.2@37.4,-48.245
MIPI_SWITCH_CLK_P: R204.2 U17.1 | length 5.6
  1-TOP w0.15: R204.2@33.5,-51.9 33.789,-51.611 34.135,-51.611 34.223,-51.523 34.223,-51.176 35.999,-49.4 36.4,-49.4 37.023,-48.777 37.023,-48.268 U17.1@37,-48.245
MIPI_SWITCH_DATA0_N: R210.2 U18.4 | length 5.6
  1-TOP w0.15: R210.2@28.7,-51.9 28.411,-51.611 28.065,-51.611 27.977,-51.523 27.977,-51.076 27.4,-50.499 27.4,-50.001 28.047,-49.354 28.77,-49.354 29.177,-48.947 29.177,-48.8 29.177,-48.268 U18.4@29.2,-48.245
MIPI_SWITCH_DATA0_P: R208.2 U18.3 | length 5.6
  1-TOP w0.15: R208.2@26.9,-51.9 27.189,-51.611 27.535,-51.611 27.623,-51.523 27.623,-51.223 27.046,-50.646 27.046,-49.854 27.9,-49 28.623,-49 28.823,-48.8 28.823,-48.268 U18.3@28.8,-48.245
MIPI_SWITCH_DATA1_N: R214.2 U18.6 | length 5.5
  1-TOP w0.15: U18.6@30,-48.245 29.977,-48.268 29.977,-48.8 30.177,-49 30.901,-49 31.754,-49.853 31.754,-50.746 31.277,-51.223 31.277,-51.523 31.365,-51.611 31.711,-51.611 R214.2@32,-51.9
MIPI_SWITCH_DATA1_P: R212.2 U18.5 | length 5.5
  1-TOP w0.15: U18.5@29.6,-48.245 29.623,-48.268 29.623,-48.947 30.03,-49.354 30.754,-49.354 31.4,-50 31.4,-50.599 30.923,-51.076 30.923,-51.4 30.923,-51.523 30.835,-51.611 30.489,-51.611 R212.2@30.2,-51.9
MIPI_SWITCH_DATA2_N: R218.2 U17.4 | length 5.5
  1-TOP w0.15: U17.4@38.2,-48.245 38.177,-48.268 38.177,-49.077 39.154,-50.054 39.154,-50.746 38.746,-51.154 38.046,-51.154 37.877,-51.323 37.877,-51.523 37.965,-51.611 38.311,-51.611 R218.2@38.6,-51.9
MIPI_SWITCH_DATA2_P: R216.2 U17.3 | length 5.5
  1-TOP w0.15: R216.2@36.8,-51.9 37.089,-51.611 37.435,-51.611 37.523,-51.523 37.523,-51.176 37.899,-50.8 38.599,-50.8 38.8,-50.599 38.8,-50.201 37.823,-49.224 37.823,-48.268 U17.3@37.8,-48.245
MIPI_SWITCH_DATA3_N: R222.2 U17.6 | length 5.5
  1-TOP w0.15: U17.6@39,-48.245 38.977,-48.268 38.977,-48.777 39.1,-48.9 39.901,-48.9 41.177,-50.176 41.177,-51.523 41.265,-51.611 41.611,-51.611 R222.2@41.9,-51.9
MIPI_SWITCH_DATA3_P: R220.2 U17.5 | length 5.5
  1-TOP w0.15: U17.5@38.6,-48.245 38.623,-48.268 38.623,-48.924 38.953,-49.254 39.754,-49.254 40.823,-50.323 40.823,-51.523 40.735,-51.611 40.389,-51.611 R220.2@40.1,-51.9
MIPI_SWITCH_OE: R203.2 U17.8 U18.8 | length 17.1
  1-TOP w0.2: U18.8@30.695,-47.6 31.2,-47.6 v1(32.4,-48.8) ; U17.8@39.695,-47.6 40.2,-47.6 43.5,-50.9 R203.2@43.5,-51.9
  3-INTOP w0.15: v1(32.4,-48.8) 32.8,-48.4 v1(41,-48.4)
MIPI_SWITCH_SEL: R337.1 R338.2 S1.4 U17.11 U18.11 | length 160.5
  1-TOP w0.2: U18.11@30.695,-46.4 31.2,-46.4 32.4,-45.2 v1(34.3,-45.2) ; U17.11@39.695,-46.4 40.2,-46.4 v1(41,-45.6) 41.6,-45.6 45.5,-49.5 v1(48.2,-49.5) ; v1(128.7,30) S1.4@128.7,31.19
  3-INTOP w0.15: v1(34.3,-45.2) 34.7,-45.6 v1(41,-45.6) ; v1(48.2,-49.5) 59.8,-49.5 66.8,-42.5 76.6,-42.5 86.1,-33 v1(107.5,-33)
  6-INBOT w0.15: v1(107.5,-33) 111.5,-29 111.5,12.8 v1(128.7,30)
MUX_3V3_1V8: R35.1 R155.2 R343.1 | length 21.5
  1-TOP w0.2: R155.2@-21.02,-53.7 -21.02,-44.02 -15.48,-38.48 R343.1@-11.5,-38.48
MUX_VSELECT: U5.AH13 U5.AN5 | length 16.8
  1-TOP w0.2: U5.AH13@13.97,-2.54 v1(14.605,-3.175) ; U5.AN5@20.32,-12.7 v1(20.955,-13.335)
  8-BOTTOM w0.2: v1(14.605,-3.175) 15.24,-3.81 15.24,-10.16 16.51,-11.43 20.32,-11.43 20.955,-12.065 v1(20.955,-13.335)
NetC5_2: C5.2 U1.6 | length 1.2
  1-TOP w0.3: U1.6@128.54,48.05 C5.2@128.54,49.2
NetC6_2: C6.2 D3.3 J3.2 R13.1 R16.2 | length 9.3
  1-TOP w0.4: R16.2@95.3,58.48 95.3,61.47 J3.2@95.27,61.5 D3.3@99.5,61.5
  1-TOP w0.8: J3.2@94.8,61.5 R13.1@94.8,63.5
NetC8_1: C8.1 J54.2 | length 9.3
  1-TOP w0.4: J54.2@92,54.46 95.3,51.16 C8.1@95.3,46.5
NetC9_1: C9.1 U4.10 | length 1.4
  1-TOP w0.2: C9.1@103.8,49.5 U4.10@105.2,49.5
NetC9_2: C9.2 R18.1 | length 2.2
  1-TOP w0.4: R18.1@102,47.8 102,49.064 102.336,49.4 C9.2@102.84,49.4
NetC14_1: C14.1 C19.2 C20.2 R19.1 U3.1 | length 6.1
  1-TOP w0.5: R19.1@71,-47.86 C20.2@76,-47.86 77.1,-47.86
NetC21_1: C21.1 U4.8 | length 1.1
  1-TOP w0.2: C21.1@104.1,50.5 U4.8@105.2,50.5
NetC22_2: C22.2 R20.1 U4.11 | length 9.6
  1-TOP w0.2: v1(104.5,49) U4.11@105.2,49 ; R20.1@107.2,53.48 v1(107.2,54.1)
  1-TOP w0.4: C22.2@103.5,47.77 104.17,47.77 104.5,48.1 v1(104.5,49)
  3-INTOP w0.2: v1(104.5,49) 107.2,51.7 v1(107.2,54.1)
NetC23_2: C23.2 U4.6 | length 1.1
  1-TOP w0.2: U4.6@106,51.45 C23.2@106,52.54
NetC29_2: C29.2 R136.1 R137.2 U8.5 | length 9
  1-TOP w0.2: -28.7,57.05 R137.2@-28.7,60.4
  1-TOP w0.4: R136.1@-29.5,53.3 C29.2@-29.5,57.05 ; C29.2@-29.5,57.15 C29.2@-29.5,57.05 ; U8.5@-27.68,57.05 -28.7,57.05 C29.2@-29.5,57.05
NetC31_2: C31.2 L3.3 R138.1 | length 1.9
  1-TOP w0.15: R138.1@-19.667,55.155 L3.3@-19.667,57.1
NetC32_2: C32.2 L3.2 R139.1 | length 1.9
  1-TOP w0.15: R139.1@-20.317,55.155 L3.2@-20.317,57.1
NetC33_2: C33.2 U9.43 X1.2 | length 12.4
  1-TOP w0.2: U9.43@-17.83,47.75 -14.35,47.75 -14.1,47.5 -12.9,47.5 -12.65,47.75 -10.25,47.75 -10,47.5 X1.2@-10,43.225
NetC34_2: C34.2 U9.44 X1.1 | length 12.4
  1-TOP w0.2: U9.44@-17.83,48.25 -14.35,48.25 -14.1,48.5 -12.9,48.5 -12.65,48.25 -10.25,48.25 -10,48.5 X1.1@-10,52.775
NetC35_2: C35.2 R149.2 U9.46 | length 2.7
  1-TOP w0.2: U9.46@-17.83,49.25 -16.085,49.25 C35.2@-16.085,49.2 ; C35.2@-16.2,49.5 R149.2@-16.2,50.415
NetC43_2: C43.2 C44.2 J18.4 R155.1 R156.1 R157.2 R158.1 R159.2 | length 26
  1-TOP w0.3: v1(-26.2,-47.6) R157.2@-26.2,-46.98 ; v1(-25,-47.6) R158.1@-25,-46.98 ; v1(-23.8,-47.6) R159.2@-23.8,-46.98
  1-TOP w0.5: J18.4@-31.3,-60 -31.3,-58.3 -30,-57 C44.2@-21.98,-57 ; v1(-21.98,-53.1) R155.1@-21.98,-53.7 R156.1@-21.98,-54.8 C44.2@-21.98,-57 ; C44.2@-21.96,-57 C44.2@-21.98,-57
  8-BOTTOM w0.5: v1(-26.2,-47.6) v1(-25,-47.6) v1(-23.8,-47.6) -21.98,-49.42 v1(-21.98,-53.1)
NetC57_2: C57.2 U10.6 X2.3 | length 5.2
  1-TOP w0.2: X2.3@0.5,45.1 0.5,45.8 0.6,45.9 2.26,45.9 C57.2@2.6,45.56 2.94,45.9 3.4,45.9 3.7,45.6 4.39,45.6 U10.6@4.53,45.46
NetC58_2: C58.2 U10.5 X2.1 | length 6.1
  1-TOP w0.2: X2.1@-0.5,47.1 -0.5,46.6 -0.2,46.3 2.26,46.3 C58.2@2.6,46.64 2.94,46.3 3.4,46.3 3.7,46.6 4.4,46.6 U10.5@4.53,46.73
NetC62_2: C62.2 R175.1 U15.7 X3.3 | length 9.3
  1-TOP w0.15: R175.1@-60.5,-33.5 -59.9,-33.5 -59.6,-33.2 U15.7@-55.95,-33.2
  1-TOP w0.2: X3.3@-64,-34.2 -64,-33.4 -63.8,-33.2 -62.44,-33.2 -62.31,-33.33 -62.31,-33.34 C62.2@-62.11,-33.54 ; X3.3@-63.525,-34.25 X3.3@-63.525,-34.125 ; C62.2@-62.11,-33.6 R175.1@-60.5,-33.6
NetC63_2: C63.2 R175.2 U15.6 X3.1 | length 10.1
  1-TOP w0.15: R175.2@-60.5,-32.5 -59.9,-32.5 -59.6,-32.8 U15.6@-55.95,-32.8
  1-TOP w0.2: X3.1@-65.4,-31.9 -64.5,-32.8 -62.44,-32.8 -62.31,-32.67 -62.31,-32.66 C63.2@-62.11,-32.46 ; C63.2@-62.11,-32.4 R175.2@-60.5,-32.4
NetC64_1: C64.1 Q2.D Q3.G R171.2 U13.G | length 11.7
  1-TOP w0.2: R171.2@-49.52,-12.3 -48.55,-12.3 ; Q3.G@-48.55,-20.25 U13.G@-48.55,-13.85 -48.55,-12.3 ; Q2.D@-48.55,-9.5 -48.55,-12.3
NetC70_2: C70.2 C71.2 L6.2 U15.16 | length 4.9
  1-TOP w0.15: C70.2@-54,-38.2 U15.16@-54,-35.95
  1-TOP w0.3: L6.2@-54.14,-40.8 C71.2@-54.14,-39.6 C70.2@-54.14,-38.2
NetC75_2: C75.2 C76.2 C77.2 C78.2 L7.1 U15.8 U15.13 U15.19 U15.44 | length 7.6
  1-TOP w0.15: v1(-57.4,-33.8) -57.3,-33.8 -57.1,-33.6 U15.8@-55.95,-33.6 ; v1@-55.9,-36.2 U15.13@-55.2,-36.2 ; U15.44@-53.6,-29.95 v1(-53.6,-29.1) ; U15.19@-52.8,-35.95 -52.8,-36.8 -52.6,-37 v1(-52.6,-37.1)
  1-TOP w0.3: C75.2@-58.04,-33.8 v1(-57.4,-33.8) ; C77.2@-56.6,-36.4 v1(-55.9,-36.4) ; v1(-53.7,-26.125) L7.1@-53.7,-25.48 ; v1(-53.6,-29.1) C78.2@-53.6,-28.46 ; C76.2@-52.6,-37.74 v1(-52.6,-37.1)
NetC84_2: C84.2 R224.1 U20.2 | length 4.1
  1-TOP w0.2: U20.2@66.5,-47.6 66.5,-48.5 67.4,-49.4 C84.2@68.12,-49.4 ; R224.1@68.12,-50.6 C84.2@68.12,-49.4 ; C84.2@68.14,-49.4 C84.2@68.12,-49.4
NetC85_2: C85.2 R227.2 U19.53 X4.1 | length 9.6
  1-TOP w0.15: U19.53@63.4,-34.82 63.4,-31 63.5,-30.9 R227.2@63.5,-30.3 ; R227.2@63.6,-30.3 C85.2@63.6,-29.3 ; C85.2@63.74,-29.3 63.4,-28.96 63.4,-26.7 63.6,-26.5 63.975,-26.5 X4.1@64.45,-26.025
NetC86_2: C86.2 R227.1 U19.54 X4.3 | length 8.7
  1-TOP w0.15: X4.3@61.95,-27.975 62.425,-27.5 62.9,-27.5 63,-27.6 63,-28.96 C86.2@62.66,-29.3 ; R227.1@62.8,-30.3 C86.2@62.8,-29.3 ; R227.1@62.9,-30.3 62.9,-30.9 63,-31 U19.54@63,-34.82
NetC87_1: C87.1 U19.35 | length 2.3
  1-TOP w0.15: U19.35@65.68,-40.7 U19.35@65.705,-40.7 66.3,-40.7 66.5,-40.5 66.5,-40 66.7,-39.8 C87.1@67.3,-39.8
NetC93_2: C93.2 U20.37 | length 2.7
  1-TOP w0.2: U20.37@66.5,-53.4 66.5,-52.5 66.8,-52.2 v1(67.5,-52.2) C93.2@68.14,-52.2
NetC110_1: C110.1 C111.2 U21.31 | length 3
  1-TOP w0.2: U21.31@2.68,-42.75 C110.1@4.5,-42.75 ; C110.1@4.54,-42.7 C111.2@4.54,-41.5
NetC124_1: C124.1 R249.1 U24.32 X5.3 | length 10.5
  1-TOP w0.2: C124.1@112.04,-34.5 112.04,-36.74 112.3,-37 U24.32@120.2,-37
NetC125_1: C125.1 R249.2 U24.33 X5.1 | length 9
  1-TOP w0.2: C125.1@112.96,-39.5 112.96,-37.98 115.02,-37.98 115.5,-37.5 U24.33@120.2,-37.5
NetC128_2: C128.2 C131.2 L19.2 U23.8 | length 8.8
  1-TOP w0.3: U23.8@111.415,-46.97 111.415,-45.385 112.84,-43.96 C131.2@113.4,-43.96 C128.2@114.6,-43.96 ; L19.2@113.5,-45.7 C131.2@113.5,-44 ; L19.2@114.5,-45.7 C128.2@114.5,-44
NetC129_2: C129.2 C130.2 L18.2 U23.5 | length 17.8
  1-TOP w0.3: U23.5@107.605,-46.97 107.605,-45.795 108.9,-44.5 111,-44.5 112.5,-43 112.5,-42.5 113.2,-41.8 114.8,-41.8 115.25,-42.25 115.25,-43.75 115.46,-43.96 C130.2@115.9,-43.96 C129.2@117.1,-43.96 ; L18.2@116,-45.7 C130.2@116,-44 ; L18.2@117,-45.7 C129.2@117,-44
NetC132_2: C132.2 C133.2 C134.2 C135.2 C136.2 C137.2 L22.1 U24.5 U24.10 U24.15 U24.23 U24.29 U24.36 | length 13.7
  1-TOP w0.2: C132.2@118.46,-39.3 v1(119.1,-39.3) 119.4,-39 U24.36@120.2,-39 ; C136.2@118.46,-35.5 v1(119.1,-35.5) U24.29@120.2,-35.5 ; C133.2@122.9,-42.54 122.9,-41.92 v1(122.9,-41.895) 122.9,-41.1 123,-41 U24.5@123,-39.8 ; U24.23@123,-34.2 C137.2@123,-32.46 ; U24.10@125.8,-39 v1(127.2,-39) C134.2@128.04,-39 ; U24.15@125.8,-36.5 127.64,-36.5 C135.2@128.04,-36.1
  1-TOP w0.3: v1(115.4,-33.8) L22.1@115.4,-32.85
  other v1: 127.2,-36.5 123,-33.1
NetC138_2: C138.2 U24.14 | length 2.4
  1-TOP w0.2: U24.14@125.8,-37 127.64,-37 C138.2@128.04,-37.4
NetC139_2: C139.2 U24.34 | length 1.8
  1-TOP w0.2: C139.2@118.46,-38.1 118.56,-38 U24.34@120.2,-38
NetC140_1: C140.1 Q4.D Q5.G R258.2 U26.G | length 11.7
  1-TOP w0.2: Q4.D@95,-34.05 97.8,-34.05 ; R258.2@97.8,-35.02 97.8,-34.05 ; Q5.G@105.75,-34.05 U26.G@99.25,-34.05 97.8,-34.05
NetC145_1: C145.1 R273.2 U29.44 | length 5.6
  1-TOP w0.15: C145.1@-60.6,38.7 C145.1@-60.54,38.7 -59.5,38.7 -58,37.2 U29.44@-57.43,37.2
  1-TOP w0.2: R273.2@-61.48,37.5 -61.34,37.64 -61.34,37.96 -61.24,38.06 -60.783,38.06 -60.6,38.243 C145.1@-60.6,38.7
NetC146_1: C146.1 U29.42 | length 3.5
  1-TOP w0.15: C146.1@-58.8,40.7 C146.1@-58.8,40.64 -58.8,40.3 -57.2,38.7 -56.6,38.7 U29.42@-56.6,38.43
NetC147_1: C147.1 U29.43 | length 4.3
  1-TOP w0.15: C147.1@-59.9,40.7 C147.1@-59.9,40.64 -59.9,40.3 -57.7,38.1 -57.7,37.6 U29.43@-57.43,37.6
NetC147_2: C147.2 L33.2 | length 1.6
  1-TOP w0.2: C147.2@-59.9,41.5 C147.2@-59.9,41.56 L33.2@-59.9,43.12
NetC148_1: C148.1 C149.1 U29.39 | length 6.8
  1-TOP w0.15: C148.1@-57.7,40.64 -58.235,41.175 -58.235,42.665 C149.1@-57.7,43.2 ; C148.1@-57.7,40.64 -57.698,40.198 -56.7,39.2 -55.7,39.2 -55.4,38.9 U29.39@-55.4,38.43
NetC149_2: C149.2 L34.2 | length 1.1
  1-TOP w0.2: C149.2@-57.7,44 L34.2@-57.7,45.12
NetC150_1: C150.1 C152.1 U29.38 | length 6.2
  1-TOP w0.15: C150.1@-56.6,43.2 -57.135,42.665 -57.135,41.175 C152.1@-56.6,40.64 -56.6,40.2 -56,39.6 -55.5,39.6 -55,39.1 U29.38@-55,38.43
NetC150_2: C150.2 L35.2 | length 1.1
  1-TOP w0.2: C150.2@-56.6,44 L35.2@-56.6,45.12
NetC151_1: C151.1 R276.1 U29.35 | length 8.3
  1-TOP w0.15: U29.35@-53.8,38.43 -53.8,39
  1-TOP w0.2: -53.8,39 -53.8,42.9 -52.2,44.5 R276.1@-52.2,46.02
NetC153_1: C153.1 C154.1 U29.37 | length 5.6
  1-TOP w0.15: C153.1@-55.5,40.64 -56.035,41.175 -56.035,42.665 C154.1@-55.5,43.2 ; C153.1@-55.5,40.64 -55.498,40.198 -54.6,39.3 U29.37@-54.6,38.43
NetC154_2: C154.2 L36.2 | length 1.1
  1-TOP w0.2: C154.2@-55.5,44 C154.2@-55.5,44.06 L36.2@-55.5,45.12
NetC155_1: C155.1 R277.1 U29.33 | length 8.4
  1-TOP w0.15: U29.33@-53,38.43 -53,39
  1-TOP w0.2: -53,39 -53,42.5 -51,44.5 R277.1@-51,46.02
NetC156_1: C156.1 C157.1 U29.36 | length 5.3
  1-TOP w0.15: C156.1@-54.4,43.2 -54.935,42.665 -54.935,41.175 C157.1@-54.4,40.64 -54.4,40.1 -54.2,39.9 U29.36@-54.2,38.43
NetC156_2: C156.2 L37.2 | length 1.1
  1-TOP w0.2: C156.2@-54.4,44 C156.2@-54.4,44.06 L37.2@-54.4,45.12
NetC158_1: C158.1 Q7.D Q8.G R279.2 U30.G | length 11.7
  1-TOP w0.2: Q7.D@-57.45,11.5 -57.45,14.3 ; Q8.G@-57.45,22.25 -57.45,14.3 ; R279.2@-56.48,14.3 -57.45,14.3
NetC160_1: C160.1 U29.27 | length 2.1
  1-TOP w0.15: U29.27@-50.57,37.2 -49.966,37.2 -49.566,37.6 C160.1@-48.6,37.6
NetC160_2: C160.2 U29.26 | length 3.2
  1-TOP w0.15: U29.26@-50.57,36.8 -49.8,36.8 -49.4,37.2 -48.34,37.2 -47.975,37.565 -47.973,37.565 C160.2@-47.74,37.8 C160.2@-47.74,37.8
NetC162_1: C162.1 Q9.D Q10.G R283.2 U16.G | length 12.7
  1-TOP w0.2: Q9.D@-51.95,10.5 -51.95,14.3 ; Q10.G@-51.95,22.25 -51.95,14.3 ; R283.2@-50.98,14.3 -51.95,14.3
NetC163_2: C163.2 U29.32 | length 2.2
  1-TOP w0.15: U29.32@-52.6,38.43 -52.6,39.8 -52.4,40 C163.2@-52.4,40.54
NetC168_2: C168.2 U29.31 | length 2.6
  1-TOP w0.15: U29.31@-52.2,38.43 -52.2,39 -52.3,39.1 -52.3,39.54 C168.2@-51.3,40.54
NetC169_2: C169.2 U29.48 | length 3.2
  1-TOP w0.15: C169.2@-60.23,36.4 -59.5,36.4 -58.625,35.525 -58.075,35.525 -58,35.6 U29.48@-57.43,35.6
NetC170_2: C170.2 U29.49 | length 3.1
  1-TOP w0.15: C170.2@-60.5,35.2 U29.49@-57.43,35.2
NetC187_1: C187.1 C188.2 C189.2 J7.2 R31.1 U33.1
NetC191_1: C191.1 C192.2 C193.2 J8.2 R32.1 U34.1
NetC195_2: C195.2 C196.2 R342.2 R356.2 U36.8 | length 68.6
  1-TOP w0.2: v1(44.5,-35) R342.2@44.5,-31.98 ; v1(79.5,-35.3) 85.2,-41 92.6,-41 92.915,-41.315 U36.8@92.915,-42.47
  1-TOP w0.5: R356.2@92.882,-55.7 92.902,-47.7 92.905,-46.5 U36.8@92.915,-42.47
  3-INTOP w0.15: v1(44.5,-35) 64.8,-35 65.3,-35.5 78.9,-35.5 79.1,-35.3 v1(79.5,-35.3)
NetC198_2: C198.2 R357.2 R360.1 U31.5 | length 5.4
  1-TOP w0.5: R357.2@60.5,0.02 U31.5@61.8,0.02 ; R360.1@61.8,-4.02 U31.5@61.8,0.02 ; U31.5@61.82,0.05 61.82,0.02 U31.5@61.8,0.02
NetD1_A: D1.A R10.1 | length 1.7
  1-TOP w0.2: D1.A@87.52,61.8 R10.1@87.52,63.5
NetD1_K: D1.K Q1.D | length 1.5
  1-TOP w0.2: Q1.D@88,57.69 D1.K@88,59.2
NetD3_1: D3.1 R14.2 R15.2 U2.5 | length 12.2
  1-TOP w0.4: R15.2@98.85,58.48 D3.1@98.85,59.4 ; R15.2@98.9,58.48 99.52,58.48 101,57 106.9,57 107.1,56.8 R14.2@107.1,56.2 ; R14.2@107,56.05 U2.5@108.82,56.05
NetD4_A: D4.A R143.2 | length 1.7
  1-TOP w0.2: R143.2@-34,38.02 D4.A@-32.3,38.02
NetD4_K: D4.K U9.12 | length 17.5
  1-TOP w0.2: D4.K@-29.7,38.5 v1(-29.7,40) ; U9.12@-24.75,51.67 v1(-24.75,52.8)
  6-INBOT w0.2: v1(-29.7,40) -29.7,44.3 -24.75,49.25 v1(-24.75,52.8)
NetD5_A: D5.A R144.2 | length 1.7
  1-TOP w0.2: R144.2@-28,38.02 D5.A@-26.3,38.02
NetD5_K: D5.K U9.11 | length 14.4
  1-TOP w0.2: v1(-24.25,50.6) U9.11@-24.25,51.67 ; D5.K@-23.7,38.5 v1(-23.7,40)
  6-INBOT w0.2: v1(-24.25,50.6) -24.25,47.25 -25.5,46 -25.5,41.8 v1(-23.7,40)
NetD6_A: D6.A R148.2 | length 1.7
  1-TOP w0.2: R148.2@-16,38.02 D6.A@-14.3,38.02
NetD6_K: D6.K U9.28 | length 15.9
  1-TOP w0.2: U9.28@-23.25,43.33 v1(-23.25,44.4) ; D6.K@-11.7,38.5 v1(-11.7,40)
  6-INBOT w0.2: v1(-23.25,44.4) -22.35,43.5 -15.2,43.5 v1(-11.7,40)
NetD7_A: D7.A R150.2 | length 1.7
  1-TOP w0.2: R150.2@-22,38.02 D7.A@-20.3,38.02
NetD7_K: D7.K U9.27 | length 9.6
  1-TOP w0.2: v1(-23.75,42.2) U9.27@-23.75,43.33 ; D7.K@-17.7,38.5 v1(-17.7,40)
  6-INBOT w0.2: v1(-23.75,42.2) -22.55,41 -18.7,41 v1(-17.7,40)
NetD8_K: D8.K R226.1 | length 2.4
  1-TOP w0.2: R226.1@55.92,-49.6 55.92,-48.88 56.55,-48.25 D8.K@56.55,-47.5
NetD9_2: D9.2 J34.1 L27.1 | length 3
  1-TOP w0.3: D9.2@-17.3,-58.85 L27.1@-15.8,-58.85 ; J34.1@-15.3,-60.5 L27.1@-15.3,-59.025
NetD10_A: D10.A R314.1 | length 1.7
  1-TOP w0.2: D10.A@67.52,61.8 R314.1@67.52,63.5
NetD10_K: D10.K Q12.D | length 1.5
  1-TOP w0.2: Q12.D@68,57.69 D10.K@68,59.2
NetD11_A: D11.A R315.1 | length 1.7
  1-TOP w0.2: D11.A@71.52,61.8 R315.1@71.52,63.5
NetD11_K: D11.K Q11.D | length 1.5
  1-TOP w0.2: Q11.D@72,57.69 D11.K@72,59.2
NetD12_A: D12.A R316.1 | length 1.7
  1-TOP w0.2: D12.A@63.52,61.8 R316.1@63.52,63.5
NetD12_K: D12.K Q13.D | length 1.5
  1-TOP w0.2: Q13.D@64,57.69 D12.K@64,59.2
NetD14_2: D14.2 J21.3 R324.2 | length 50.8
  1-TOP w0.2: R324.2@62.6,-21.98 62.6,-22.4 63,-22.8 63.786,-22.8 81.1,-40.114 81.1,-45.4 81.25,-45.55 D14.2@81.6,-45.55 81.6,-48.7 82,-49.1 82,-57.5 81.3,-58.2 J21.3@81.3,-63.83
NetD16_2: D16.2 J21.7 R325.2 | length 43.2
  1-TOP w0.2: R325.2@61.6,-21.98 61.6,-22.4 62.5,-23.3 63.579,-23.3 79.9,-39.621 79.9,-45.4 80.05,-45.55 D16.2@80.4,-45.55 80.4,-48.8 81.3,-49.7 J21.7@81.3,-56.21
NetD21_2: D21.2 J35.1 L30.1 | length 3
  1-TOP w0.3: J35.1@98.7,-60 L30.1@98.7,-57
NetFIL1_1: FIL1.1 J1.1 J2.1 | length 13.7
  1-TOP w0.8: 136.6,46.6 FIL1.1@137.5,46.6 ; 137.5,47.5 FIL1.1@137.5,46.6 ; 138.4,46.6 FIL1.1@137.5,46.6
  1-TOP w1: 122.8,52 J1.1@125,52 ; 125,50.9 J1.1@125,52 ; 125,53.1 J1.1@125,52 ; 127.2,52 J1.1@125,52 ; 134.9,50.73 J2.1@136,50.73 ; 136,49.63 J2.1@136,50.73 ; 136,51.83 J2.1@136,50.73 ; 137.1,50.73 J2.1@136,50.73
NetJ4_1: J4.1 R12.1 | length 3.4
  1-TOP w0.4: R12.1@101.5,61.3 102.3,61.3 103.5,62.5 J4.1@104.375,62.5
NetJ6_2: J6.2 R28.2 R29.1 R30.1
NetJ9_2: J9.2 U5.AL20 | length 88.6
  1-TOP w0.2: v1(17.145,5.715) U5.AL20@17.78,6.35
  3-INTOP w0.15: v1(17.145,5.715) 17.62,5.24 25.16,5.24 27.4,3 83.3,3 101.27,3 J9.2@103,1.27
NetJ10_1: J10.1 R51.2 R54.2 | length 3
  1-TOP w0.2: R51.2@-65,-44.52 J10.1@-65,-41.525
NetJ11_1: J11.1 R51.1 R55.2 | length 5.5
  1-TOP w0.2: J11.1@-65,-51 R51.1@-65,-45.48
NetJ13_1: J13.1 R60.2 R61.2 | length 3
  1-TOP w0.2: J13.1@-65,41.525 R60.2@-65,44.52
NetJ14_1: J14.1 R60.1 R62.2 | length 5.5
  1-TOP w0.2: R60.1@-65,45.48 J14.1@-65,51
NetJ15_1: J15.1 R322.2 R331.1 | length 3
  1-TOP w0.2: R331.1@135,-44.52 J15.1@135,-41.525
NetJ16_1: J16.1 L2.1 | length 1.5
  1-TOP w0.3: L2.1@-18.7,59.025 J16.1@-18.7,60.5
NetJ16_2: J16.2 L3.4 | length 2.3
  1-TOP w0.168: L3.4@-19.6,58.85 -19.6,59.1 -19.716,59.216 -19.743,59.216 -19.841,59.314 -19.841,59.509 -19.516,59.834 -19.516,60.184 -19.35,60.35 J16.2@-19.35,60.85
NetJ16_3: J16.3 L3.1 | length 2.3
  1-TOP w0.168: L3.1@-20.4,58.85 -20.4,59.1 -20.284,59.216 -20.257,59.216 -20.159,59.314 -20.159,59.641 -19.834,59.966 -19.834,60.184 -20,60.35 J16.3@-20,60.85
NetJ16_5: J16.5 L4.1 | length 1.5
  1-TOP w0.3: L4.1@-21.3,59 J16.5@-21.3,60.475
NetJ18_5: J18.5 R161.2 | length 27.8
  1-TOP w0.2: J18.5@-32.4,-59.5 -32.4,-57.7 -21.5,-46.8 -21.5,-43.5 R161.2@-16.339,-38.339
NetJ23_2: J23.2 R166.2 | length 2.1
  1-TOP w0.2: R166.2@1.58,60 1.58,59.42 1.84,59.16 J23.2@1.84,58
NetJ25_2: J25.2 R169.2 | length 2.1
  1-TOP w0.2: R169.2@81.58,60 81.58,58.315 J25.2@81.895,58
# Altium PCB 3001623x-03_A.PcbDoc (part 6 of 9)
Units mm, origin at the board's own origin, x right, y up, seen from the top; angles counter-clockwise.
Board outline 210 x 130 mm, 9 copper layers (1-TOP, 2-GND, 3-INTOP, 4-PWR, 5-PWR, 6-INBOT, Signal_4, 7-GND, 8-BOTTOM), stack 1.979 mm thick; 755 components, 650 nets, 2980 pads, 2365 vias.

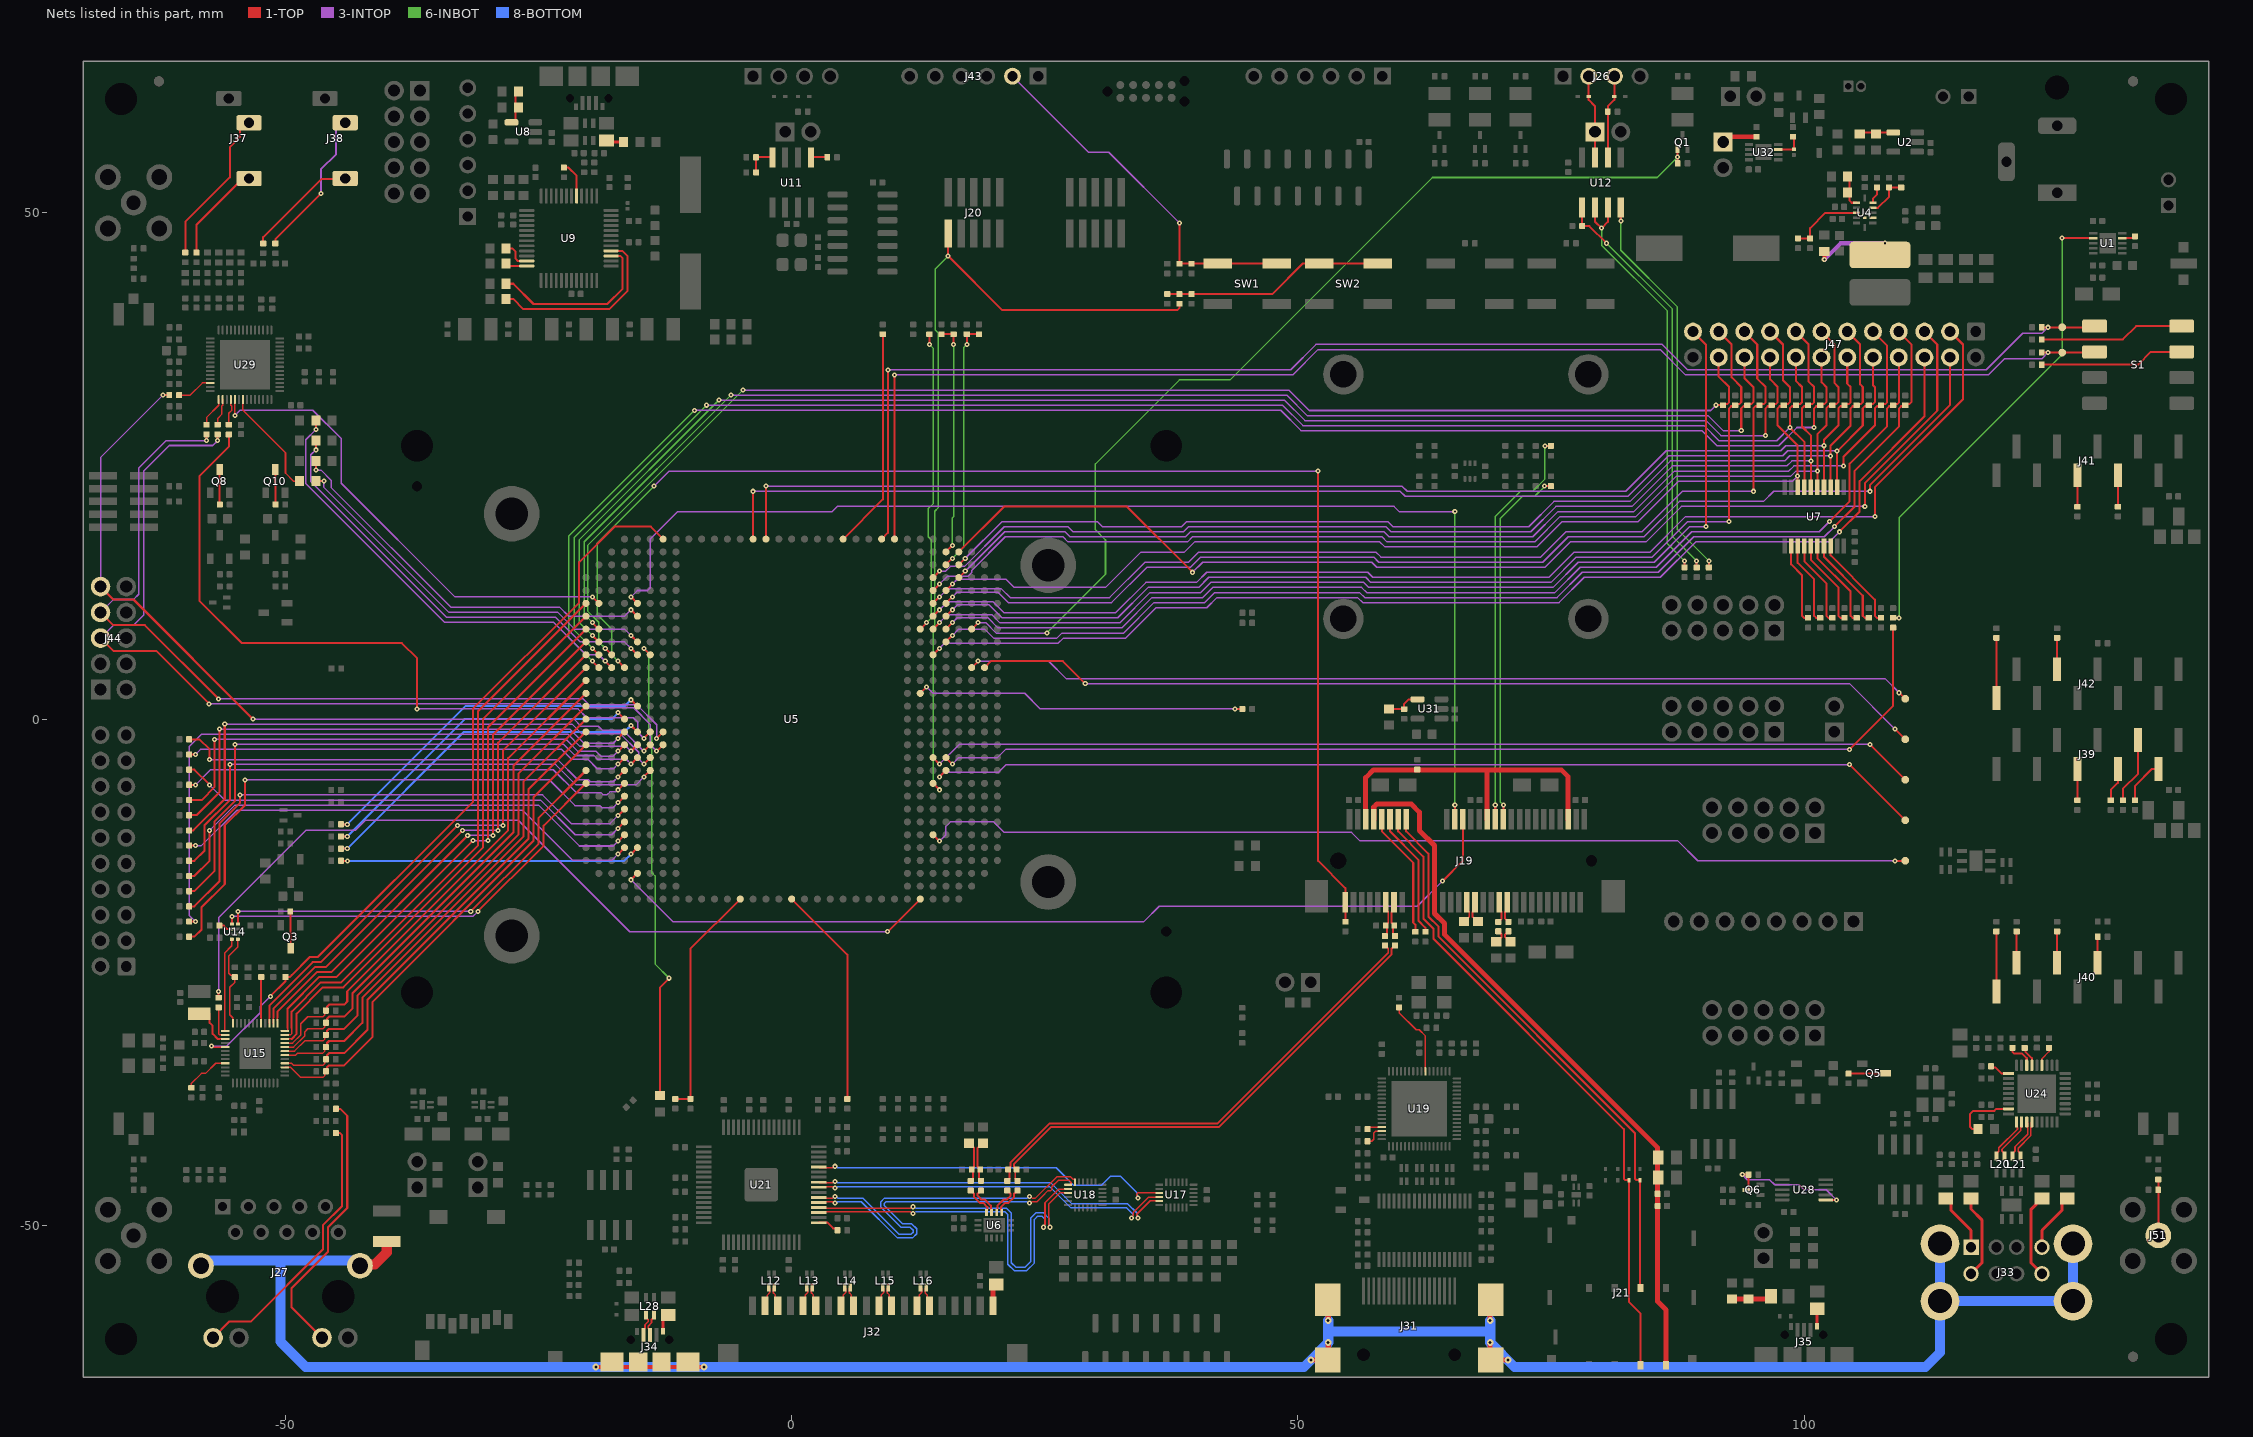
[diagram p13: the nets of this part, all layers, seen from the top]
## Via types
v1: diameter 0.5, hole 0.2, 1-TOP to 8-BOTTOM, 1743 vias
v2: diameter 0.5/0.5/0.5/0.5/0.5 (per signal layer), hole 0.2, 1-TOP to 8-BOTTOM, 440 vias
v3: diameter 0.68, hole 0.3, 1-TOP to 8-BOTTOM, 182 vias

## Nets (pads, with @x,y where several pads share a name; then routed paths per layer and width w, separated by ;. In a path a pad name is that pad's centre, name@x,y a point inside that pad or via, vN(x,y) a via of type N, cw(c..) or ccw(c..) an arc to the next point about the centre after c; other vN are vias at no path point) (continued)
NetJ27_D1: J27.D1 R182.2 | length 27.2
  1-TOP w0.2: J27.D1@-57.145,-61.112 -55.533,-59.5 -53.4,-59.5 -46.3,-52.4 -46.3,-50 -44.4,-48.1 -44.4,-41.1 -44.6,-40.9 R182.2@-45.02,-40.9
NetJ27_D3: J27.D3 R176.2 | length 26.9
  1-TOP w0.2: J27.D3@-46.395,-61.112 -49.407,-58.1 -49.407,-56.207 -45.8,-52.6 -45.8,-50.2 -43.9,-48.3 -43.9,-39.2 -44.6,-38.5 R176.2@-45.02,-38.5
NetJ32_2: J32.2 L12.2 | length 2
  1-TOP w0.15: J32.2@-2.4,-58 -2.4,-56.9 -2.177,-56.677 -2.177,-56.248 L12.2@-2.275,-56.15
NetJ32_3: J32.3 L12.3 | length 2
  1-TOP w0.15: L12.3@-1.725,-56.15 -1.823,-56.248 -1.823,-56.677 -1.6,-56.9 J32.3@-1.6,-58
NetJ32_5: J32.5 L13.2 | length 2
  1-TOP w0.15: J32.5@1.35,-58 1.35,-56.9 1.573,-56.677 1.573,-56.248 L13.2@1.475,-56.15
NetJ32_6: J32.6 L13.3 | length 2
  1-TOP w0.15: L13.3@2.025,-56.15 1.927,-56.248 1.927,-56.677 2.15,-56.9 J32.6@2.15,-58
NetJ32_8: J32.8 L14.2 | length 2
  1-TOP w0.15: J32.8@5.1,-58 5.1,-56.9 5.323,-56.677 5.323,-56.248 L14.2@5.225,-56.15
NetJ32_9: J32.9 L14.3 | length 2
  1-TOP w0.15: L14.3@5.775,-56.15 5.677,-56.248 5.677,-56.677 5.9,-56.9 J32.9@5.9,-58
NetJ32_11: J32.11 L15.2 | length 2
  1-TOP w0.15: J32.11@8.85,-58 8.85,-56.9 9.073,-56.677 9.073,-56.248 L15.2@8.975,-56.15
NetJ32_12: J32.12 L15.3 | length 2
  1-TOP w0.15: L15.3@9.525,-56.15 9.427,-56.248 9.427,-56.677 9.65,-56.9 J32.12@9.65,-58
NetJ32_14: J32.14 L16.2 | length 2
  1-TOP w0.15: J32.14@12.6,-58 12.6,-56.9 12.823,-56.677 12.823,-56.248 L16.2@12.725,-56.15
NetJ32_15: J32.15 L16.3 | length 2
  1-TOP w0.15: L16.3@13.275,-56.15 13.177,-56.248 13.177,-56.677 13.4,-56.9 J32.15@13.4,-58
NetJ32_20: J32.20 L17.2 | length 2.1
  1-TOP w0.5: J32.20@19.875,-57.95 L17.2@19.875,-55.8
NetJ33_A1: J33.A1 L19.1 | length 5.6
  1-TOP w0.3: L19.1@114.5,-47.4 114.5,-48.5 116.5,-50.5 J33.A1@116.5,-52.17
NetJ33_A4: J33.A4 L24.2 | length 5.6
  1-TOP w0.3: J33.A4@123.5,-52.17 123.5,-50.5 125.5,-48.5 L24.2@125.5,-47.4
NetJ33_B1: J33.B1 L18.1 | length 8.3
  1-TOP w0.3: J33.B1@116.5,-54.79 117.562,-53.728 117.562,-49.462 116.5,-48.4 L18.1@116.5,-47.35
NetJ33_B4: J33.B4 L23.2 | length 8.3
  1-TOP w0.3: J33.B4@123.5,-54.79 122.438,-53.728 122.438,-48.412 L23.2@123.5,-47.35
NetJ34_5: J34.5 L29.2 | length 1.5
  1-TOP w0.3: J34.5@-12.7,-60.475 L29.2@-12.7,-59
NetJ35_5: J35.5 L31.1 | length 1.7
  1-TOP w0.3: J35.5@101.3,-59.975 L31.1@101.3,-58.25
NetJ37_2: J37.2 R275.2 | length 16
  1-TOP w0.2: R275.2@-59.9,46.08 -59.9,49.114 -55.5,53.514 -55.5,56.5 -54.5,57.5 -54.5,58.9 J37.2@-53.6,58.9
NetJ37_3: J37.3 R274.2 | length 10
  1-TOP w0.2: R274.2@-58.8,46.08 -58.8,48.8 -54.5,53.1 -54.5,53.4 J37.3@-53.6,53.4
NetJ38_2: J38.2 R277.2 | length 15.3
  1-TOP w0.2: R277.2@-51,46.98 -51,47.4 v1(-46.5,51.9)
  3-INTOP w0.2: v1(-46.5,51.9) -46.5,54.3 -45,55.8 -45,58.9 J38.2@-44.1,58.9
NetJ38_3: J38.3 R276.2 | length 10.6
  1-TOP w0.2: R276.2@-52.2,46.98 -52.2,47.6 -46.433,53.367 -44.633,53.367 J38.3@-44.6,53.4
NetJ39_2: J39.2 R333.2 | length 4.4
  1-TOP w0.2: R333.2@132.7,-8.02 132.7,-6.6 134.375,-4.925 J39.2@135,-4.925
NetJ39_3: J39.3 R334.2 | length 6.6
  1-TOP w0.2: R334.2@131.5,-8.02 131.5,-6.9 133,-5.4 J39.3@133,-2.075
NetJ39_4: J39.4 R304.2 | length 3.4
  1-TOP w0.2: R304.2@130.3,-8.02 130.3,-7 131,-6.3 J39.4@131,-4.925
NetJ39_6: J39.6 R305.2 | length 3.1
  1-TOP w0.2: R305.2@127,-8.02 J39.6@127,-4.925
NetJ40_5: J40.5 R335.1 | length 2.6
  1-TOP w0.2: J40.5@129,-24.075 R335.1@129,-21.5
NetJ40_7: J40.7 R306.1 | length 3.1
  1-TOP w0.2: J40.7@125,-24.075 R306.1@125,-20.98
NetJ40_9: J40.9 R336.1 | length 3.1
  1-TOP w0.2: J40.9@121,-24.075 R336.1@121,-20.98
NetJ40_10: J40.10 R308.1 | length 5.9
  1-TOP w0.2: J40.10@119,-26.925 R308.1@119,-20.98
NetJ41_4: J41.4 R309.2 | length 3.1
  1-TOP w0.2: R309.2@131,20.98 J41.4@131,24.075
NetJ41_6: J41.6 R310.2 | length 3.1
  1-TOP w0.2: R310.2@127,20.98 J41.6@127,24.075
NetJ42_7: J42.7 R311.1 | length 3.1
  1-TOP w0.2: J42.7@125,4.925 R311.1@125,8.02
NetJ42_10: J42.10 R313.1 | length 5.9
  1-TOP w0.2: J42.10@119,2.075 R313.1@119,8.02
NetJ51_1: J51.1 R331.2 R332.2 | length 5.5
  1-TOP w0.2: J51.1@135,-51 R331.2@135,-45.48
NetJ54_1: J54.1 R16.1 | length 3.5
  1-TOP w0.4: J54.1@92,57 92.52,57.52 R16.1@95.3,57.52
NetL1_1: L1.1 R18.2 U4.2 U4.13 | length 7.5
  1-TOP w0.4: v1(102,45.4) R18.2@102,46.2
  3-INTOP w0.4: v1(102,45.4) 103.6,47 v1(108,47)
NetL2_2: L2.2 R135.1 | length 1.9
  1-TOP w0.3: L2.2@-18.5,57 R135.1@-16.6,57
NetL5_1: L5.1 U15.3 | length 4.1
  1-TOP w0.15: -56.5,-31.6 U15.3@-55.95,-31.6
  1-TOP w0.2: L5.1@-58,-29.1 -57.5,-29.1 -57.5,-30 -57.2,-30.3 -57.2,-31.1 -56.7,-31.6 -56.5,-31.6
NetL20_1: L20.1 U24.1 | length 4.3
  1-TOP w0.168: L20.1@119,-43.15 119,-42.9 119.116,-42.784 119.143,-42.784 119.241,-42.686 119.241,-42.359 121.091,-40.509 121.091,-40.364 121.066,-40.339 121.066,-39.866 U24.1@121,-39.8
NetL20_4: L20.4 U24.2 | length 4.3
  1-TOP w0.168: L20.4@119.8,-43.15 119.8,-42.9 119.684,-42.784 119.657,-42.784 119.559,-42.686 119.559,-42.491 121.409,-40.641 121.409,-40.364 121.434,-40.339 121.434,-39.866 U24.2@121.5,-39.8
NetL21_1: L21.1 U24.3 | length 4
  1-TOP w0.168: L21.1@120.6,-43.15 120.6,-42.9 120.716,-42.784 120.743,-42.784 120.841,-42.686 120.841,-42.259 122.091,-41.009 122.091,-40.364 122.066,-40.339 122.066,-39.866 U24.3@122,-39.8
NetL21_4: L21.4 U24.4 | length 4
  1-TOP w0.168: L21.4@121.4,-43.15 121.4,-42.9 121.284,-42.784 121.257,-42.784 121.159,-42.686 121.159,-42.391 122.409,-41.141 122.409,-40.364 122.434,-40.339 122.434,-39.866 U24.4@122.5,-39.8
NetL30_2: L30.2 R355.2 R356.1 | length 3.4
  1-TOP w0.5: R356.1@92.9,-57.3 R355.2@94.5,-57.3 L30.2@96.3,-57.3
NetQ3_D: Q3.D R172.2 | length 3.7
  1-TOP w0.2: R172.2@-49.52,-18.9 -49.5,-18.92 Q3.D@-49.5,-22.55
NetQ5_D: Q5.D R259.2 | length 3.7
  1-TOP w0.2: R259.2@104.4,-35.02 104.42,-35 Q5.D@108.05,-35
NetQ6_D: Q6.D R262.2 U28.1 | length 13.5
  1-TOP w0.2: v1(93.9,-45) R262.2@94.52,-45 Q6.D@94.52,-46.5 ; U28.1@102.16,-47.5 v1(103.2,-47.5)
  3-INTOP w0.15: v1(93.9,-45) 94.4,-45.5 96.6,-45.5 97.1,-46 99.5,-46 100,-46.5 102.2,-46.5 v1(103.2,-47.5)
NetQ8_D: Q8.D R280.2 | length 3.4
  1-TOP w0.2: R280.2@-56.5,21.2 Q8.D@-56.5,24.55
NetQ10_D: Q10.D R284.2 | length 3.4
  1-TOP w0.2: R284.2@-51,21.2 Q10.D@-51,24.55
NetR3_1: R3.1 R5.1 R6.1 SW2.3 SW2.4 | length 22.1
  1-TOP w0.2: R5.1@37.1,41.98 R6.1@38.3,41.98 R3.1@39.5,41.98 47.48,41.98 50.5,45 SW2.4@52.1,45 55.48,45 SW2.3@57.9,45
NetR7_1: R7.1 U1.4 | length 1.3
  1-TOP w0.2: U1.4@131.44,47.5 R7.1@132.7,47.5
NetR8_2: R8.2 R9.1 U1.7 | length 47.8
  1-TOP w0.2: R8.2@108.8,10 v1(109.4,10) ; v1(125.5,47.5) U1.7@128.56,47.5
  6-INBOT w0.15: v1(109.4,10) 109.4,19.9 125.5,36 v1(125.5,47.5)
NetR14_1: R14.1 R17.2 U2.4 | length 2.9
  1-TOP w0.2: R17.2@105.87,57.95 U2.4@108.82,57.95
NetR15_1: R15.1 R339.1 U32.3 | length 2.8
  1-TOP w0.2: U32.3@97.45,56.25 R339.1@99,56.25 ; R339.1@99,56.285 R15.1@99,57.52
NetR20_2: R20.2 U4.5 | length 1.7
  1-TOP w0.2: U4.5@106.8,51 106.8,51.4 107.2,51.8 R20.2@107.2,52.52
NetR21_1: R21.1 R22.2 U4.9 | length 7.4
  1-TOP w0.2: R22.2@99.4,47.48 R21.1@100.6,47.48 100.6,48.5 102.1,50 U4.9@105.2,50
NetR23_1: R23.1 R26.2 U4.4 | length 4.2
  1-TOP w0.2: U4.4@106.8,50.5 107.3,50.5 108.4,51.6 R26.2@108.4,52.52 R23.1@109.6,52.52
NetR24_1: R24.1 R27.2 U4.7 | length 3.2
  1-TOP w0.2: R27.2@104.5,53.6 104.5,51.2 104.7,51 U4.7@105.2,51
NetR35_2: R35.2 U5.F20 | length 46.5
  1-TOP w0.2: v1(-14.605,6.985) U5.F20@-13.97,6.35 ; R35.2@-13,-37.2 -13,-26.5 v1(-12.1,-25.6)
  6-INBOT w0.15: v1(-14.605,6.985) -14.11,6.49 -14.11,-1.304 -13.825,-1.589 -13.825,-15.175 -13.5,-15.5 -13.5,-24.2 v1(-12.1,-25.6)
NetR36_2: R36.2 U5.U1 | length 22
  1-TOP w0.2: U5.U1@0,-17.78 5.5,-23.28 R36.2@5.5,-37.52
NetR37_2: R37.2 U5.D15 | length 33.3
  1-TOP w0.2: R37.2@-44.52,-11.6 v1(-43.9,-11.6) ; v1(-17.145,0.635) U5.D15@-16.51,0
  8-BOTTOM w0.2: v1(-43.9,-11.6) -32.3,0 -17.78,0 v1(-17.145,0.635)
NetR38_2: R38.2 U5.E16 | length 34.6
  1-TOP w0.2: R38.2@-44.52,-10.4 v1(-43.9,-10.4) ; v1(-15.875,1.905) U5.E16@-15.24,1.27
  8-BOTTOM w0.2: v1(-43.9,-10.4) -32.23,1.27 -16.51,1.27 v1(-15.875,1.905)
NetR39_2: R39.2 U5.AG22 | length 30.1
  1-TOP w0.2: U5.AG22@12.7,8.89 v1(13.335,9.525) ; v1(13.6,37) R39.2@13.6,38.04
  6-INBOT w0.15: v1(13.335,9.525) 13.81,10 13.81,17.69 13.5,18 13.5,20.8 14,21.3 14,36.6 v1(13.6,37)
NetR40_1: R40.1 U5.D12 | length 44.5
  1-TOP w0.2: R40.1@-59.52,-3.5 v1(-58.9,-3.5) ; v1(-17.145,-4.445) U5.D12@-16.51,-3.81
  3-INTOP w0.15: v1(-58.9,-3.5) -58.4,-3 -54.5,-3 -22.714,-3 -21.744,-3.97 -20.13,-3.97 -19.2,-4.9 ; -19.2,-4.92 -17.62,-4.92 v1(-17.145,-4.445)
NetR41_1: R41.1 U5.D11 | length 45.8
  1-TOP w0.2: R41.1@-59.52,-2 -58.5,-2 -57.5,-3 v1(-57.5,-4) ; v1(-17.145,-5.715) U5.D11@-16.51,-5.08
  3-INTOP w0.15: v1(-57.5,-4) -23.128,-4 -21.128,-6 -20.1,-6 -19.9,-6.2 -17.63,-6.2 v1(-17.145,-5.715)
NetR43_1: R43.1 U5.D9 | length 57.2
  1-TOP w0.2: R43.1@-59.52,-21.5 -59,-21.5 -58.3,-20.8 -58.3,-18.6 -56,-16.3 -56,-10.5 -54,-8.5 v1(-54,-6) ; v1(-17.145,-8.255) U5.D9@-16.51,-7.62
  3-INTOP w0.15: v1(-54,-6) -23.957,-6 -21.407,-8.55 -18.95,-8.55 -18.75,-8.75 -17.658,-8.75 -17.163,-8.255 v1(-17.145,-8.255)
NetR44_1: R44.1 U5.D8 | length 53.1
  1-TOP w0.2: R44.1@-59.52,-18.5 -59,-18.5 -56.5,-16 -56.5,-10.3 -54.5,-8.3 v1(-54.5,-7.5) ; v1(-17.145,-9.525) U5.D8@-16.51,-8.89
  3-INTOP w0.15: v1(-54.5,-7.5) -24.6,-7.5 -21.78,-10.32 -17.94,-10.32 v1(-17.145,-9.525)
NetR45_1: R45.1 U5.D6 | length 49.8
  1-TOP w0.2: R45.1@-59.52,-15.5 -59,-15.5 -57.5,-14 v1(-57.5,-11) ; v1(-17.145,-12.065) U5.D6@-16.51,-11.43
  3-INTOP w0.15: v1(-57.5,-11) -55,-8.5 -50.5,-8.5 -25,-8.5 -20.96,-12.54 -17.62,-12.54 v1(-17.145,-12.065)
NetR47_1: R47.1 U5.D5 | length 47
  1-TOP w0.2: R47.1@-59.52,-12.5 v1(-58.9,-12.5) ; v1(-17.145,-13.335) U5.D5@-16.51,-12.7
  3-INTOP w0.15: v1(-58.9,-12.5) -58.3,-12.5 -54.8,-9 -51,-9 -27.5,-9 -26.6,-9 -21.63,-13.97 -17.78,-13.97 v1(-17.145,-13.335)
NetR48_1: R48.1 U5.D14 | length 51.2
  1-TOP w0.2: R48.1@-59.52,-9.5 -58.793,-9.5 -56.5,-7.207 v1(-56.5,-1) ; v1(-17.145,-1.905) U5.D14@-16.51,-1.27
  3-INTOP w0.15: v1(-56.5,-1) -21.9,-1 -20.52,-2.38 -17.62,-2.38 v1(-17.145,-1.905)
NetR49_1: R49.1 U5.D13 | length 49.4
  1-TOP w0.2: R49.1@-59.52,-8 -58.293,-8 -57,-6.707 v1(-57,-2) ; v1(-17.145,-3.175) U5.D13@-16.51,-2.54
  3-INTOP w0.15: v1(-57,-2) -22.3,-2 -21.1,-3.2 -19.3,-3.2 -18.85,-3.65 -17.62,-3.65 v1(-17.145,-3.175)
NetR50_1: R50.1 U5.D10 | length 45.1
  1-TOP w0.2: R50.1@-59.52,-6.5 v1(-58.9,-6.5) ; v1(-17.145,-6.985) U5.D10@-16.51,-6.35
  3-INTOP w0.15: v1(-58.9,-6.5) -57.4,-5 -23.543,-5 -21.283,-7.26 -18.84,-7.26 -18.64,-7.46 -18.218,-7.46 -17.958,-7.2 -17.36,-7.2 v1(-17.145,-6.985)
NetR52_1: R52.1 U5.D7 | length 46.2
  1-TOP w0.2: R52.1@-59.52,-5 -59,-5 v1(-57.5,-6.5) ; v1(-17.145,-10.795) U5.D7@-16.51,-10.16
  3-INTOP w0.15: v1(-57.5,-6.5) -56,-8 -24.807,-8 -21.377,-11.43 -17.78,-11.43 v1(-17.145,-10.795)
NetR56_1: R56.1 U5.E13 | length 63.9
  1-TOP w0.2: R56.1@-59.52,-20 v1(-58.9,-20) ; v1(-15.875,-3.175) U5.E13@-15.24,-2.54
  3-INTOP w0.15: v1(-58.9,-20) -59.5,-19.4 -59.5,-2.7 -58.3,-1.5 -22.1,-1.5 -20.9,-2.7 -16.35,-2.7 v1(-15.875,-3.175)
NetR57_1: R57.1 U5.E12 | length 57.5
  1-TOP w0.2: R57.1@-59.52,-17 -59,-17 -57,-15 -57,-10.1 -55,-8.1 v1(-55,-2.5) ; v1(-15.875,-4.445) U5.E12@-15.24,-3.81
  3-INTOP w0.15: v1(-55,-2.5) -22.507,-2.5 -21.407,-3.6 -19.54,-3.6 -19.17,-3.97 -16.35,-3.97 v1(-15.875,-4.445)
NetR58_1: R58.1 U5.F12 | length 56.5
  1-TOP w0.2: R58.1@-59.52,-11 -59.1,-11 -56,-7.9 v1(-56,-0.5) ; v1(-14.605,-4.445) U5.F12@-13.97,-3.81
  3-INTOP w0.15: v1(-56,-0.5) -21.7,-0.5 -20.77,-1.43 -16.948,-1.43 -15.1,-3.278 -15.1,-3.95 v1(-14.605,-4.445)
NetR59_1: R59.1 U5.F11 | length 54.4
  1-TOP w0.2: R59.1@-59.52,-14 -59,-14 -58,-13 -58,-10.5 -55.5,-8 v1(-55.5,-4.5) ; v1(-14.605,-5.715) U5.F11@-13.97,-5.08
  3-INTOP w0.15: v1@-55.5,-4.485 -23.329,-4.485 -21.314,-6.5 -15.39,-6.5 v1(-14.605,-5.715)
NetR69_1: R69.1 U6.11 | length 3.1
  1-TOP w0.192: R69.1@17.7,-46.58 17.889,-46.769 17.917,-46.769 18.029,-46.881 18.029,-47.229 18.6,-47.8 18.916,-47.8 19.329,-48.213 19.329,-48.384 19.289,-48.424 19.289,-48.711 U6.11@19.25,-48.75
NetR70_1: R70.1 U6.10 | length 3.1
  1-TOP w0.192: R70.1@18.7,-46.58 18.511,-46.769 18.483,-46.769 18.371,-46.881 18.371,-47.087 18.742,-47.458 19.058,-47.458 19.671,-48.071 19.671,-48.384 19.711,-48.424 19.711,-48.711 U6.10@19.75,-48.75
NetR71_1: R71.1 U6.8 | length 3.1
  1-TOP w0.192: U6.8@20.75,-48.75 20.711,-48.711 20.711,-48.424 20.671,-48.384 20.671,-48.213 21.084,-47.8 21.4,-47.8 21.971,-47.229 21.971,-46.881 22.083,-46.769 22.111,-46.769 R71.1@22.3,-46.58
NetR72_1: R72.1 U6.9 | length 3.1
  1-TOP w0.192: U6.9@20.25,-48.75 20.289,-48.711 20.289,-48.424 20.329,-48.384 20.329,-48.071 20.942,-47.458 21.258,-47.458 21.629,-47.087 21.629,-46.881 21.517,-46.769 21.489,-46.769 R72.1@21.3,-46.58
NetR78_1: R78.1 S1.8 | length 14.4
  1-TOP w0.2: R78.1@123.48,37.5 131.5,37.5 132.81,38.81 S1.8@137.3,38.81
NetR79_1: R79.1 S1.7 | length 14.3
  1-TOP w0.2: R79.1@123.48,35 133,35 134.27,36.27 S1.7@137.3,36.27
NetR118_2: R118.2 R125.2 U7.18 | length 9.4
  1-TOP w0.2: U7.18@102.625,17.1 102.625,16.175 107,11.8 107,10.2 107.2,10 R118.2@107.6,10
NetR119_2: R119.2 R126.2 U7.16 | length 8.9
  1-TOP w0.2: U7.16@101.325,17.1 101.325,15.875 104.6,12.6 104.6,10.2 104.8,10 R119.2@105.2,10
NetR120_2: R120.2 R127.2 U7.13 | length 8.3
  1-TOP w0.2: U7.13@99.375,17.1 99.375,15.425 101,13.8 101,10.2 101.2,10 R120.2@101.6,10
NetR121_2: R121.2 R128.2 U7.17 | length 9.2
  1-TOP w0.2: U7.17@101.975,17.1 101.975,16.025 105.8,12.2 105.8,10.2 106,10 R121.2@106.4,10
NetR122_2: R122.2 R129.2 U7.15 | length 8.7
  1-TOP w0.2: U7.15@100.675,17.1 100.7,17.075 100.7,15.7 103.4,13 103.4,10.2 103.6,10 R122.2@104,10
NetR123_2: R123.2 R130.2 U7.14 | length 8.5
  1-TOP w0.2: U7.14@100.025,17.1 100.025,15.575 102.2,13.4 102.2,10.2 102.4,10 R130.2@102.8,10
NetR124_2: R124.2 R131.2 U7.12 | length 8
  1-TOP w0.2: U7.12@98.725,17.1 98.725,15.275 99.8,14.2 99.8,10.2 100,10 R131.2@100.4,10
NetR137_1: R137.1 R140.2 U8.4 | length 2.9
  1-TOP w0.2: U8.4@-27.3,58.95 R140.2@-27.3,61.9
NetR141_1: R141.1 U9.24 | length 2.1
  1-TOP w0.2: R141.1@-28.2,45 -27.95,44.75 U9.24@-26.17,44.75
NetR142_1: R142.1 U9.23 | length 3
  1-TOP w0.2: R142.1@-28.2,46.5 -27.6,46.5 -27.3,46.2 -27.3,45.5 -27.05,45.25 U9.23@-26.17,45.25
NetR145_2: R145.2 U9.5 | length 3.6
  1-TOP w0.2: R145.2@-22.5,54.48 -22.08,54.48 -21.25,53.65 U9.5@-21.25,51.67
NetR146_1: R146.1 U9.40 | length 18.4
  1-TOP w0.2: R146.1@-28.2,41.5 -27.5,41.5 -26.5,40.5 -18,40.5 -16.2,42.3 -16.2,45.7 -16.75,46.25 U9.40@-17.83,46.25
NetR147_1: R147.1 U9.39 | length 17.2
  1-TOP w0.2: R147.1@-28.2,43 -27.5,43 -25.5,41 -18.2,41 -16.7,42.5 -16.7,45.5 -16.95,45.75 U9.39@-17.83,45.75
NetR165_1: R165.1 U11.5 | length 1.6
  1-TOP w0.2: U11.5@1.895,55.5 R165.1@3.52,55.5
NetR167_2: R167.2 R168.2 U11.8 | length 3.1
  1-TOP w0.2: R167.2@-3.52,54 R168.2@-3.52,55.5 -1.915,55.5 U11.8@-1.895,55.5
NetR173_2: R173.2 U14.6 | length 1.4
  1-TOP w0.2: R173.2@-56.52,-20.4 -56.1,-20.4 -55.75,-20.75 U14.6@-55.3,-20.75
NetR177_1: R177.1 R291.2 U12.1 | length 40.8
  1-TOP w0.2: R177.1@78.08,48.7 R177.1@78.085,48.7 ; U12.1@78.085,50.53 R177.1@78.085,48.7 ; v1(80.5,47) 78.8,48.7 R177.1@78.085,48.7 ; R291.2@89.4,14.98 v1(89.4,15.62) v1@89.4,15.72
  6-INBOT w0.15: v1(80.5,47) 87,40.5 87,18.02 v1(89.4,15.62)
NetR179_2: R179.2 U15.2 | length 3.3
  1-TOP w0.15: R179.2@-56.6,-28.5 -56.6,-31.1 -56.5,-31.2 U15.2@-55.95,-31.2
NetR185_2: R185.2 U15.41 | length 4.7
  1-TOP w0.15: U15.41@-52.4,-30.05 -52.4,-29.5
  1-TOP w0.2: -52.4,-29.5 R185.2@-52.4,-25.48 R185.2@-52.4,-25.38
NetR194_2: R194.2 U15.9 | length 4.6
  1-TOP w0.15: R194.2@-59.3,-36.42 -59.3,-36 -58.3,-35 -57.9,-35 -56.9,-34 U15.9@-55.95,-34
NetR228_1: R228.1 U19.13 | length 1.4
  1-TOP w0.15: R228.1@56.9,-40.3 U19.13@58.295,-40.3 U19.13@58.32,-40.3
NetR229_2: R229.2 U19.55 | length 7.6
  1-TOP w0.15: R229.2@60,-28.48 60,-29 61.7,-30.7 62,-30.7 62.6,-31.3 U19.55@62.6,-34.795 U19.55@62.6,-34.82
NetR242_1: R242.1 U21.17 | length 2
  1-TOP w0.2: U21.17@2.68,-49.75 3.55,-49.75 4.1,-50.3 R242.1@4.5,-50.3
NetR251_1: R251.1 U24.28 | length 2
  1-TOP w0.2: R251.1@118.48,-34.4 118.9,-34.4 119.5,-35 U24.28@120.2,-35
NetR253_2: R253.2 U24.35 | length 6.2
  1-TOP w0.2: R253.2@117.2,-40.5 116.6,-40.5 116.4,-40.3 116.4,-39 116.7,-38.7 118.8,-38.7 119,-38.5 U24.35@120.2,-38.5
NetR254_2: R254.2 U24.22 | length 2
  1-TOP w0.15: U24.22@123.5,-34.2 123.5,-33.55 124.2,-32.85 R254.2@124.2,-32.48
NetR255_2: R255.2 U24.24 | length 1.9
  1-TOP w0.2: R255.2@121.9,-32.5 121.9,-32.9 122.5,-33.5 U24.24@122.5,-34.2
NetR256_2: R256.2 U24.25 | length 2.8
  1-TOP w0.2: R256.2@120.6,-32.48 120.6,-32.9 120.75,-33.05 121.55,-33.05 122,-33.5 U24.25@122,-34.2
NetR269_2: R269.2 U29.2 | length 2.7
  1-TOP w0.15: R269.2@-56.7,29.08 -56.7,29.7 -56.275,30.125 -56.275,30.925 -56.2,31 U29.2@-56.2,31.57
NetR270_2: R270.2 U29.4 | length 2.6
  1-TOP w0.15: R270.2@-55.6,29.08 -55.6,30.2 -55.325,30.475 -55.325,30.925 -55.4,31 U29.4@-55.4,31.57
NetR271_2: R271.2 U29.54 | length 3.6
  1-TOP w0.15: R271.2@-60.52,32 -59.4,32 -58.2,33.2 U29.54@-57.43,33.2
NetR272_2: R272.2 U29.1 | length 3
  1-TOP w0.15: R272.2@-57.8,29.08 -57.8,29.8 -56.6,31 U29.1@-56.6,31.57
NetR292_2: R292.2 U12.4 | length 39.3
  1-TOP w0.2: v1@81.895,49.2 U12.4@81.895,50.53 ; R292.2@90.6,14.98 v1(90.6,15.62) v1@90.6,15.72
  6-INBOT w0.15: v1(81.9,49.2) 81.9,46.3 87.5,40.7 87.5,18.72 v1(90.6,15.62)
NetR323_2: R323.2 U5.AA29 | length 21.8
  1-TOP w0.2: U5.AA29@5.08,17.78 9,21.7 R323.2@9,38
NetR326_2: R326.2 U19.14 | length 2.2
  1-TOP w0.15: R326.2@56.88,-41.7 57.3,-41.7 57.5,-41.5 57.5,-40.9 57.7,-40.7 U19.14@58.295,-40.7 U19.14@58.32,-40.7
NetR343_2: R343.2 R344.2 U5.N1 | length 23.3
  1-TOP w0.2: R343.2@-11.5,-37.52 R344.2@-10,-37.52 -10,-22.7 U5.N1@-5.08,-17.78
NetR345_2: R345.2 U5.E14 | length 34.6
  1-TOP w0.2: R345.2@-44.52,-12.8 v1(-43.9,-12.8) ; v1(-15.875,-0.635) U5.E14@-15.24,-1.27
  8-BOTTOM w0.2: v1(-43.9,-12.8) -32.37,-1.27 -16.51,-1.27 v1(-15.875,-0.635)
NetR346_2: R346.2 U5.AG17 | length 33
  1-TOP w0.2: U5.AG17@12.7,2.54 v1(13.335,3.175) ; v1(43.78,1) R346.2@44.52,1
  3-INTOP w0.15: v1(13.335,3.175) 13.97,2.54 23.02,2.54 24.56,1 v1(43.78,1)
NetR347_2: R347.2 U5.E5 | length 29.8
  1-TOP w0.2: R347.2@-44.52,-14 v1(-43.88,-14) ; v1(-15.875,-13.335) U5.E5@-15.24,-12.7
  8-BOTTOM w0.2: v1(-43.88,-14) -16.54,-14 v1(-15.875,-13.335)
NetR357_1: R357.1 R358.2 U31.4 | length 3.5
  1-TOP w0.2: R358.2@59,0.98 R357.1@60.5,0.98 60.5,1.5 60.95,1.95 U31.4@61.82,1.95
NetR359_2: R359.2 U12.2 U12.3 | length 41.5
  1-TOP w0.2: U12.2@79.355,50.53 79.355,49.145 v1(80,48.5) 80.625,49.125 U12.3@80.625,50.53 ; R359.2@88.2,14.98 v1(88.2,15.62)
  6-INBOT w0.15: v1(80,48.5) 80,46.8 86.5,40.3 86.5,17.32 v1(88.2,15.62)
NetTP1_1: TP1.1 U5.AJ11 | length 99.1
  1-TOP w0.2: v1(14.605,-5.715) U5.AJ11@15.24,-5.08 ; v1(104.5,-4.5) TP1.1@110,-10
  3-INTOP w0.15: v1(14.605,-5.715) 15.08,-5.24 20.46,-5.24 21.2,-4.5 v1(104.5,-4.5)
NetTP2_1: TP2.1 U5.AH6 | length 99.2
  1-TOP w0.2: U5.AH6@13.97,-11.43 v1(14.605,-12.065) ; v1(109,-14) TP2.1@110,-14
  3-INTOP w0.15: v1(14.605,-12.065) 15.24,-11.43 15.24,-10.6 15.68,-10.16 19.96,-10.16 21,-11.2 55.3,-11.2 56.1,-12 87.5,-12 89.5,-14 v1(109,-14)
NetTP3_1: TP3.1 U5.AH12 | length 98.5
  1-TOP w0.2: U5.AH12@13.97,-3.81 v1(14.605,-4.445) ; v1(106.5,-2.5) TP3.1@110,-6
  3-INTOP w0.15: v1(14.605,-4.445) 16.55,-2.5 v1(106.5,-2.5)
NetTP4_1: TP4.1 U5.AM19 | length 94.4
  1-TOP w0.2: U5.AM19@19.05,5.08 19.685,5.715 26.785,5.715 v1(29,3.5) ; v1(109,-1) TP4.1@110,-2
  3-INTOP w0.15: v1(29,3.5) 104.5,3.5 v1(109,-1)
NetTP5_1: TP5.1 U5.AL19 | length 94
  1-TOP w0.2: U5.AL19@17.78,5.08 v1(18.415,5.715) ; v1(109.4,2.6) TP5.1@110,2
  3-INTOP w0.15: v1(18.415,5.715) 25.385,5.715 27.1,4 108,4 v1(109.4,2.6)
OTGD_N: J34.2 L28.2 | length 2.3
  1-TOP w0.168: J34.2@-14.65,-60.85 -14.65,-60.35 -14.484,-60.184 -14.484,-59.834 -14.159,-59.509 -14.159,-59.314 -14.257,-59.216 -14.284,-59.216 -14.4,-59.1 L28.2@-14.4,-58.85
OTGD_P: J34.3 L28.3 | length 2.3
  1-TOP w0.168: J34.3@-14,-60.85 -14,-60.35 -14.166,-60.184 -14.166,-59.966 -13.841,-59.641 -13.841,-59.314 -13.743,-59.216 -13.716,-59.216 -13.6,-59.1 L28.3@-13.6,-58.85
PCIE_1V5: J19.6 J19.28 J19.48 R360.2 | length 33.8
  1-TOP w0.5: J19.6@56.7,-9.9 56.7,-5.8 57.48,-5.02 68.7,-5.02 ; J19.28@68.7,-9.9 68.7,-5.02 ; J19.48@76.7,-9.9 76.7,-5.7 76.02,-5.02 68.7,-5.02
PCIE_CLK_N: C45.1 R72.2 R74.2 | length 48.7
  1-TOP w0.192: R72.2@21.3,-45.62 21.489,-45.431 21.517,-45.431 21.517,-44.338 21.629,-44.226 21.629,-43.787 25.458,-39.958 42.058,-39.958 58.929,-23.087 58.929,-22.676 58.817,-22.564 58.804,-22.564 C45.1@58.6,-22.36
PCIE_CLK_P: C46.1 R71.2 R73.2 | length 48.7
  1-TOP w0.192: R71.2@22.3,-45.62 22.111,-45.431 22.083,-45.431 22.083,-44.338 21.971,-44.226 21.971,-43.929 25.6,-40.3 42.2,-40.3 59.271,-23.229 59.271,-22.676 59.383,-22.564 59.396,-22.564 C46.1@59.6,-22.36
PCIE_DIS_N: J19.20 U5.E24 | length 119.4
  1-TOP w0.2: v1(-15.875,12.065) U5.E24@-15.24,11.43 ; J19.20@65.5,-9.9 v1(65.5,-8.5)
  3-INTOP w0.15: v1(-15.875,12.065) -15.24,12.7 -14.24,12.7 -13.97,12.97 -13.97,17.78 -11.25,20.5 4,20.5 4.5,21 59.5,21 60,20.5 v1(65.5,20.5)
  6-INBOT w0.15: v1(65.5,-8.5) v1(65.5,20.5)
PCIE_I2C_SCL: J19.30 R300.2 | length 40.2
  1-TOP w0.2: J19.30@69.5,-9.9 v1(69.5,-8.5) ; v1(74.4,26.98) R300.2@75,26.98
  6-INBOT w0.15: v1(69.5,-8.5) 69.5,19 69.5,20 72,22.5 73.2,22.5 74.4,23.7 v1(74.4,26.98)
PCIE_I2C_SDA: J19.32 R302.2 | length 36.1
  1-TOP w0.2: J19.32@70.3,-9.9 v1(70.3,-8.5) ; v1@74.4,23 R302.2@75,23
  6-INBOT w0.15: v1(70.3,-8.5) 70,-8.2 70,18.9 70,19.8 72.2,22 73.4,22 v1@74.4,23
  other v1: 74.375,23
PCIE_RESET_N: J19.22 U5.E3 | length 91.4
  1-TOP w0.2: v1(-15.875,-15.875) U5.E3@-15.24,-15.24 ; v1(64.3,-16) 66.3,-14 J19.22@66.3,-9.9
  3-INTOP w0.15: v1(-15.875,-15.875) -11.75,-20 34.8,-20 36.3,-18.5 61.8,-18.5 v1(64.3,-16)
PCIE_RX_N: J19.23 R68.1 | length 2.3
  1-TOP w0.192: R68.1@66.4,-20 66.754,-19.646 66.817,-19.646 66.929,-19.534 66.929,-19.054 66.7,-18.825 J19.23@66.7,-18.1
PCIE_RX_P: J19.25 R67.1 | length 2.3
  1-TOP w0.192: J19.25@67.5,-18.1 67.5,-18.825 67.271,-19.054 67.271,-19.534 67.383,-19.646 67.446,-19.646 R67.1@67.8,-20
PCIE_SOM_CLK_N: R64.1 R70.2 R76.1 | length 4.1
  1-TOP w0.192: R70.2@18.7,-45.62 18.511,-45.431 18.483,-45.431 18.483,-44.338 18.371,-44.226 18.371,-42.366 18.483,-42.254 18.546,-42.254 R64.1@18.9,-41.9
PCIE_SOM_CLK_P: R63.1 R69.2 R75.1 | length 4.1
  1-TOP w0.192: R63.1@17.5,-41.9 17.854,-42.254 17.917,-42.254 18.029,-42.366 18.029,-44.226 17.917,-44.338 17.917,-45.431 17.889,-45.431 R69.2@17.7,-45.62
PCIE_TX_N: C25.2 J19.31 | length 2.2
  1-TOP w0.192: C25.2@69.8,-20.04 70.004,-19.836 70.017,-19.836 70.129,-19.724 70.129,-19.054 69.9,-18.825 J19.31@69.9,-18.1
PCIE_TX_P: C24.2 J19.33 | length 2.2
  1-TOP w0.192: J19.33@70.7,-18.1 70.7,-18.825 70.471,-19.054 70.471,-19.724 70.583,-19.836 70.596,-19.836 C24.2@70.8,-20.04
PCIE_UIM_CLK: J19.12 R324.1 | length 12.4
  1-TOP w0.2: J19.12@59.1,-9.9 59.1,-11.1 61.9,-13.9 61.9,-19.9 62.6,-20.6 R324.1@62.6,-20.9
PCIE_UIM_DATA: J19.10 R325.1 | length 12.5
  1-TOP w0.2: J19.10@58.3,-9.9 58.3,-11.1 61.4,-14.2 61.4,-20.1 61.6,-20.3 R325.1@61.6,-21.02
PCIE_UIM_PWR: C178.2 C179.2 C180.2 C181.2 J19.8 J21.1 | length 70.9
  1-TOP w0.5: J19.8@57.5,-9.9 57.5,-8.7 57.8,-8.4 61.2,-8.4 62,-9.2 62,-11 63.5,-12.5 63.5,-19.2 64.5,-20.2 64.5,-21.3 85.54,-42.34 C181.2@85.54,-46.9 C180.2@85.54,-48.1 85.54,-57.54 86.38,-58.38 J21.1@86.38,-63.83
PCIE_UIM_RST: D13.2 J19.14 J21.2 | length 64.1
  1-TOP w0.2: J19.14@59.9,-9.9 59.9,-11.1 62.4,-13.6 62.4,-19.7 63.4,-20.7 63.4,-21.707 82.2,-40.507 82.2,-45.4 82.35,-45.55 D13.2@82.7,-45.55 82.7,-57.56 83.84,-58.7 J21.2@83.84,-63.83
PCIE_UIM_VPP: D15.2 J19.16 J21.6 | length 56.1
  1-TOP w0.2: J19.16@60.7,-9.9 60.7,-11.1 62.9,-13.3 62.9,-19.5 63.9,-20.5 63.9,-21.5 83.3,-40.9 83.3,-45.4 83.45,-45.55 D15.2@83.8,-45.55 J21.6@83.8,-56.2
PCIE_WAKE_N: J19.1 R160.1 U5.D19 | length 133.2
  1-TOP w0.2: v1(-17.145,5.715) U5.D19@-16.51,5.08 ; v1(52,24.5) 52,-14 54.7,-16.7 J19.1@54.7,-18.1 R160.1@54.7,-20.02
  3-INTOP w0.15: v1(-13.6,23) -12.1,24.5 v1(52,24.5)
  6-INBOT w0.15: v1(-17.145,5.715) -17.78,6.35 -17.78,8.89 -19.21,10.32 -19.21,17.39 v1(-13.6,23)
PCIECLK_N: C45.2 J19.11 R163.2 | length 3.4
  1-TOP w0.192: J19.11@58.7,-18.1 58.7,-18.825 58.929,-19.054 58.929,-20.126 58.8,-20.255 C45.2@58.8,-21.4
PCIECLK_P: C46.2 J19.13 R162.2 | length 3.4
  1-TOP w0.192: C46.2@59.4,-21.4 59.4,-20.255 59.271,-20.126 59.271,-19.054 59.5,-18.825 J19.13@59.5,-18.1
PCIETX_N: C25.1 R66.1 | length 1.4
  1-TOP w0.192: R66.1@69.6,-22 69.954,-21.646 70.017,-21.646 70.129,-21.534 70.129,-21.276 70.017,-21.164 70.004,-21.164 C25.1@69.8,-20.96
PCIETX_P: C24.1 R65.1 | length 1.4
  1-TOP w0.192: C24.1@70.8,-20.96 70.596,-21.164 70.583,-21.164 70.471,-21.276 70.471,-21.534 70.583,-21.646 70.646,-21.646 R65.1@71,-22
PCM_CLK: J44.5 R269.1 U5.G13 | length 90.2
  1-TOP w0.2: J44.5@-68.27,8 -67,6.73 -62.766,6.73 v1(-57.536,1.5) ; v1(-56.7,27.5) R269.1@-56.7,28.12 ; v1(-13.335,-3.175) U5.G13@-12.7,-2.54
  3-INTOP w0.15: J44.5@-68.27,8 -67,9.27 -65.017,9.27 -64,10.287 -64,24.5 -61.478,27.022 -57.178,27.022 v1(-56.7,27.5) ; v1(-57.536,1.5) -20.9,1.5 -20.51,1.11 -15.608,1.11 -13.97,-0.528 -13.97,-2.54 v1(-13.335,-3.175)
PCM_IN: J44.7 R272.1 U5.G14 | length 87.2
  1-TOP w0.2: J44.7@-68.27,10.54 -67,9.27 -63.891,9.27 v1(-56.621,2) ; v1(-57.8,27.5) R272.1@-57.8,28.12 ; v1(-13.335,-1.905) U5.G14@-12.7,-1.27
  3-INTOP w0.15: J44.7@-68.27,10.54 -67,11.81 -65.017,11.81 -64.5,12.327 -64.5,24.8 -61.8,27.5 v1(-57.8,27.5) ; v1(-56.621,2) -20.6,2 -20.03,1.43 -15.33,1.43 -13.335,-0.565 v1(-13.335,-1.905)
PCM_OUT: J44.9 R271.1 U5.F13 | length 83.4
  1-TOP w0.2: J44.9@-68.27,13.08 -67,11.81 -65.017,11.81 v1(-53.207,0) ; v1(-62.1,32) R271.1@-61.48,32 ; v1(-14.605,-3.175) U5.F13@-13.97,-2.54
  3-INTOP w0.15: J44.9@-68.27,13.08 -68.27,25.83 v1(-62.1,32) ; v1(-53.207,0) -21.5,0 -20.8,-0.7 -19.112,-0.7 -18.7,-1.112 -16.668,-1.112 v1(-14.605,-3.175)
PCM_SYNC: R270.1 U5.F14 | length 71.6
  1-TOP w0.2: R270.1@-55.6,28.12 -55.6,26.9 -58.5,24 -58.5,11.7 -54.3,7.5 -38.5,7.5 -37,6 v1(-37,1) ; v1(-14.605,-1.905) U5.F14@-13.97,-1.27
  3-INTOP w0.15: v1(-37,1) -21.1,1 -20.24,0.14 -15.64,0.14 -15.2,-0.3 -15.2,-1.31 v1(-14.605,-1.905)
POR_B: J20.10 R6.2 U5.AH10 | length 82.5
  1-TOP w0.2: U5.AH10@13.97,-6.35 v1(14.605,-6.985) ; J20.10@15.46,47.968 v1(15.46,45.74) 20.8,40.4 38.1,40.4 38.3,40.6 R6.2@38.3,41.02
  6-INBOT w0.15: v1(14.605,-6.985) 13.97,-6.35 13.97,9.1 14.13,9.26 14.13,20.53 14.5,20.9 14.5,38.1 14.2,38.4 14.2,44.48 v1(15.46,45.74)
POWER_BUTTON: J43.2 R2.1 R4.1 SW1.3 SW1.4 | length 35.5
  1-TOP w0.2: v1(38.3,49.01) R2.1@38.3,44.98 R4.1@39.5,44.98 SW1.4@41.5,44.98 ; SW1.4@42.1,45 45.48,45 SW1.3@47.9,45
  3-INTOP w0.15: J43.2@21.81,63.5 29.31,56 31.31,56 v1(38.3,49.01)
POWER_LED: Q1.G R11.1 U5.AL22 | length 99.1
  1-TOP w0.2: U5.AL22@17.78,8.89 v1(18.415,9.525) ; R11.1@87.5,54.9 Q1.G@87.5,56.31
  3-INTOP w0.15: v1(18.415,9.525) 19.16,9.525 20.185,8.5 v1(25.2,8.5)
  6-INBOT w0.15: v1(25.2,8.5) 31,14.3 31,17.7 30,18.7 30,25.2 38.3,33.5 43.3,33.5 63.295,53.495 85.495,53.495 v1(87.5,55.5)
PWR_ON: R8.1 U5.AJ12 | length 103.9
  1-TOP w0.2: U5.AJ12@15.24,-3.81 v1(15.875,-4.445) ; v1(104.5,-3) 108.8,1.3 R8.1@108.8,9.04
  3-INTOP w0.15: v1(15.875,-4.445) 16.51,-3.81 20.32,-3.81 21.13,-3 44.6,-3 v1(104.5,-3)
"RGMII_INT_ B": R183.1 U5.G29 U15.5 | length 76.1
  1-TOP w0.15: v1(-57.3,-32.3) -57.2,-32.4 U15.5@-55.95,-32.4
  1-TOP w0.2: v1(-51.5,-27.4) -50,-25.9 R183.1@-50,-25.48 -49.58,-25.48 -49.4,-25.3 -47.6,-23.5 -46.8,-23.5 -31.5,-8.2 -31.5,1 -21,11.5 -21,15.5 -17.5,19 -13.92,19 U5.G29@-12.7,17.78
  3-INTOP w0.15: v1(-57.3,-32.3) -55.8,-32.3 -52.5,-29 -52.5,-28.4 v1(-51.5,-27.4)
RGMII_MDC: U5.A10 U14.5 | length 42.3
  1-TOP w0.2: U14.5@-55.3,-20.25 v1(-55.3,-19.5) ; v1(-30.993,-19) -24.5,-12.507 -24.5,-10.53 U5.A10@-20.32,-6.35
  3-INTOP w0.15: v1(-55.3,-19.5) -31.493,-19.5 v1(-30.993,-19)
RGMII_MDC_3V3: U14.8 U15.1 | length 9.3
  1-TOP w0.15: U15.1@-56,-30.8 -56,-23.1 -55.3,-22.4 U14.8@-55.3,-21.75
RGMII_MDIO: U5.A11 U14.4 | length 42.8
  1-TOP w0.2: U14.4@-54.7,-20.12 v1(-54.7,-19) ; v1(-31.7,-19) -25,-12.3 -25,-9.76 U5.A11@-20.32,-5.08
  3-INTOP w0.15: v1(-54.7,-19) v1(-31.7,-19)
RGMII_MDIO_3V3: R178.1 U14.1 U15.48 | length 9.2
  1-TOP w0.15: U15.48@-55.2,-30.05 -55.2,-29.5 -55.5,-29.2 -55.5,-26.5 -55,-26 R178.1@-55,-25.48 ; R178.1@-55.1,-25.3 -55.4,-25.3 -55.6,-25.1 -55.6,-23.4 -54.7,-22.5 U14.1@-54.7,-21.75
RGMII_RD0: R186.1 R195.2 U5.A16 U15.31 | length 48.8
  1-TOP w0.15: U15.31@-50.05,-32.8 -49.1,-32.8 -48.1,-31.8 -46.3,-31.8 -46.1,-31.6 R195.2@-46.1,-31.2
  1-TOP w0.2: R195.2@-45.9,-31.2 -45.9,-30.8 -45.7,-30.6 -44.2,-30.6 -42.9,-29.3 -42.9,-27.314 -27,-11.414 -27,-5.41 U5.A16@-20.32,1.27
RGMII_RD1: R187.1 R196.2 U5.A15 U15.30 | length 48.4
  1-TOP w0.15: U15.30@-50.05,-33.2 -49,-33.2 -48.8,-33 -46.3,-33 -46.1,-32.8 R196.2@-46.1,-32.4
  1-TOP w0.2: R196.2@-45.9,-32.4 -45.9,-32 -45.7,-31.8 -44.2,-31.8 -42.4,-30 -42.4,-27.521 -26.5,-11.621 -26.5,-6.18 U5.A15@-20.32,0
RGMII_RD2: R190.1 R199.2 U5.A14 U15.28 | length 48.3
  1-TOP w0.15: U15.28@-50.05,-34 -49.4,-34 -49.2,-34.2 -46.3,-34.2 -46.1,-34 R199.2@-46.1,-33.6
  1-TOP w0.2: R199.2@-45.9,-33.6 -45.9,-33.2 -45.7,-33 -44.2,-33 -41.9,-30.7 -41.9,-27.728 -26,-11.828 -26,-6.95 U5.A14@-20.32,-1.27
RGMII_RD3: R192.1 R201.2 U5.A13 U15.27 | length 48.6
  1-TOP w0.15: U15.27@-50.05,-34.4 -49.5,-34.4 -48.5,-35.4 -46.3,-35.4 -46.1,-35.2 R201.2@-46.1,-34.8
  1-TOP w0.2: R201.2@-45.9,-34.8 -45.9,-34.4 -45.7,-34.2 -44.2,-34.2 -41.4,-31.4 -41.4,-27.936 -25.5,-12.036 -25.5,-7.72 U5.A13@-20.32,-2.54
RGMII_RESET_N: R179.1 U5.AG1 | length 87.1
  1-TOP w0.2: R179.1@-56.6,-27.52 v1(-56.6,-26.9) ; v1(9.48,-21) U5.AG1@12.7,-17.78
  3-INTOP w0.15: v1(-56.6,-26.9) -56.6,-19.6 -48,-11 -43.1,-11 -42.1,-10 -27,-10 -16,-21 v1(9.48,-21)
RGMII_RX_CTL: R189.1 R198.2 U5.A17 U15.32 | length 49.4
  1-TOP w0.15: U15.32@-50.05,-32.4 -49.2,-32.4 -48.1,-31.3 -48.1,-30.9 -47.8,-30.6 -46.3,-30.6 -46.1,-30.4 R198.2@-46.1,-30
  1-TOP w0.2: R198.2@-45.9,-30 -45.9,-29.6 -45.7,-29.4 -44.2,-29.4 -43.4,-28.6 -43.4,-27.107 -27.5,-11.207 -27.5,-4.64 U5.A17@-20.32,2.54
RGMII_RXC: R191.1 R200.2 U5.A18 U15.33 | length 50.2
  1-TOP w0.15: U15.33@-50.05,-32 -49.3,-32 -48.5,-31.2 -48.5,-30.1 -47.8,-29.4 -46.3,-29.4 -46.1,-29.2 R200.2@-46.1,-28.8
  1-TOP w0.2: R200.2@-45.9,-28.8 -45.9,-28.4 -45.7,-28.2 -44.2,-28.2 -43.9,-27.9 -43.9,-26.9 -28,-11 -28,-3.87 U5.A18@-20.32,3.81
RGMII_TD0: U5.A22 U15.36 | length 53.8
  1-TOP w0.15: U15.36@-49.8,-30.8 -49.8,-30.5
  1-TOP w0.2: -49.8,-30.5 -49.8,-28.6 -46.695,-25.495 -44.995,-25.495 v1(-31.5,-12) ; v1(-30,-12) -30,-0.79 U5.A22@-20.32,8.89
  3-INTOP w0.15: v1(-31.5,-12) v1(-30,-12)
RGMII_TD1: U5.A21 U15.37 | length 52.1
  1-TOP w0.15: U15.37@-50.8,-29.8 -50.8,-29.5
  1-TOP w0.2: -50.8,-29.5 -50.8,-28.9 -46.9,-25 -45.5,-25 v1@-32.15,-11.65 ; v1(-29.5,-11.5) -29.5,-1.56 U5.A21@-20.32,7.62
  3-INTOP w0.15: v1(-32,-11.5) v1(-29.5,-11.5)
RGMII_TD2: U5.A20 U15.38 | length 51.7
  1-TOP w0.15: U15.38@-51.2,-30.05 -51.2,-29.5
  1-TOP w0.2: -51.2,-29.5 -51.2,-28.6 -47.105,-24.505 -46.005,-24.505 v1@-32.65,-11.15 ; v1(-29,-11) -29,-2.33 U5.A20@-20.32,6.35
  3-INTOP w0.15: v1(-32.5,-11) v1(-29,-11)
RGMII_TD3: U5.A19 U15.39 | length 51.2
  1-TOP w0.15: U15.39@-51.6,-30.05 -51.6,-29.5
  1-TOP w0.2: -51.6,-29.5 -51.6,-28.3 -47.31,-24.01 -46.51,-24.01 v1(-33,-10.5) ; v1(-28.5,-10.5) -28.5,-3.1 U5.A19@-20.32,5.08
  3-INTOP w0.15: v1(-33,-10.5) v1(-28.5,-10.5)
RGMII_TX_CTL: U5.A23 U15.34 | length 55.6
  1-TOP w0.15: U15.34@-50.05,-31.6 -49.4,-31.6
  1-TOP w0.2: -49.4,-31.6 -48.9,-31.1 -48.9,-29.1 -46.3,-26.5 -44.293,-26.5 -30.5,-12.707 -30.5,-0.02 U5.A23@-20.32,10.16
RGMII_TXC: U5.A24 U15.35 | length 56.4
  1-TOP w0.15: U15.35@-50.05,-31.2 -49.5,-31.2 -49.4,-31.1 -49.4,-30.5
  1-TOP w0.2: -49.4,-30.5 -49.4,-28.893 -46.507,-26 -44.5,-26 -31,-12.5 -31,0.75 U5.A24@-20.32,11.43
RS485_A: D19.2 J26.3 R169.1 U12.6 | length 8.3
  1-TOP w0.2: U12.6@80.625,55.47 80.625,60.525 81.27,61.17 J26.3@81.27,63.5
RS485_B: D20.2 J25.1 J26.2 U12.7 | length 8.3
  1-TOP w0.2: J26.2@78.73,63.5 78.73,61.17 79.355,60.545 J25.1@79.355,58 U12.7@79.355,55.47
RXD_MAX98089: R237.2 U29.7 | length 10.7
  1-TOP w0.15: U29.7@-54.2,31.57 -54.2,30.503 -50,26.303 -50,24.3 -49.2,23.5 R237.2@-48.6,23.5
SAI1_MCLK: J47.23 U5.AH22 | length 101.4
  1-TOP w0.2: U5.AH22@13.97,8.89 v1(14.605,9.525) ; J47.23@89.03,38.27 90.3,37 v1(90.3,19)
  3-INTOP w0.15: v1(14.605,9.525) 15.4,10.32 19.765,10.32 20.585,9.5 32.4,9.5 35.4,12.5 40.4,12.5 41.4,13.5 56.5,13.5 57,13 75.2,13 77.7,15.5 85.2,15.5 88.7,19 v1(90.3,19)
SAI1_RXC: J47.6 U5.AH20 | length 115.7
  1-TOP w0.2: U5.AH20@13.97,6.35 v1(14.605,6.985) ; v1(103.5,18.5) 105.5,20.5 105.5,23.5 111.89,29.89 J47.6@111.89,35.73
  3-INTOP w0.15: v1(14.605,6.985) 15.12,7.5 26.34,7.5 26.84,8 33,8 36,11 41,11 42,12 55.9,12 56.4,11.5 75.8,11.5 78.3,14 85.8,14 89.3,17.5 102.5,17.5 v1(103.5,18.5)
SAI1_RXD0: J47.8 R85.2 R101.1 U5.AJ22 | length 112.3
  1-TOP w0.2: U5.AJ22@15.24,8.89 v1(15.875,9.525) ; v1(102.5,19.5) 104.5,21.5 104.5,25.225 108.2,28.925 108.2,30.7 108.4,30.9 R85.2@108.8,30.9 ; R85.2@108.8,31.1 109.2,31.1 109.4,31.3 J47.8@109.4,35.73
  3-INTOP w0.15: v1(15.875,9.525) 16.35,10 19.385,10 20.385,9 32.6,9 35.6,12 40.6,12 41.6,13 56.3,13 56.8,12.5 75.4,12.5 77.9,15 85.4,15 88.9,18.5 101.5,18.5 v1(102.5,19.5)
SAI1_RXD1: J47.10 R86.2 R102.1 U5.P29 U7.2 | length 128.6
  1-TOP w0.2: U5.P29@-3.81,17.78 v1(-3.81,22.5) ; U7.2@103.275,22.9 v1@103.275,26.475 ; v1(103.275,26.5) v1@103.275,26.475 ; R86.2@106.4,30.9 106,30.9 105.8,30.7 105.8,29 v1@103.275,26.475 ; R86.2@106.4,31.1 106.8,31.1 107,31.3 107,32.8 106.81,32.99 J47.10@106.81,35.73
  3-INTOP w0.15: v1(-3.81,22.5) 60.1,22.5 60.6,22 82.6,22 86.6,26 97.9,26 98.4,26.5 v1(103.275,26.5)
SAI1_RXD2: J47.12 R87.2 R103.1 U5.R29 U7.4 | length 126.1
  1-TOP w0.2: U5.R29@-2.54,17.78 v1(-2.54,23) ; U7.4@101.975,22.9 v1(101.975,27) 101.975,27.575 103.4,29 103.4,30.7 103.6,30.9 R87.2@104,30.9 ; R87.2@104,31.1 104.4,31.1 104.6,31.3 104.6,32.8 104.27,33.13 J47.12@104.27,35.73
  3-INTOP w0.15: v1(-2.54,23) 60.3,23 60.8,22.5 82.4,22.5 86.4,26.5 97.7,26.5 98.2,27 v1(101.975,27)
SAI1_RXD3: J47.14 R88.2 R104.1 U5.B19 | length 152.5
  1-TOP w0.2: v1(-19.685,5.715) U5.B19@-19.05,5.08 ; v1(101,28.8) 101,30.7 101.2,30.9 R88.2@101.6,30.9 ; R88.2@101.6,31.1 102,31.1 102.2,31.3 102.2,32.8 101.73,33.27 J47.14@101.73,35.73
  3-INTOP w0.15: v1(-9.6,30.5) 48.3,30.5 50.3,28.5 89.907,28.5 91.407,27 97.5,27 99.3,28.8 v1(101,28.8)
  6-INBOT w0.15: v1(-19.685,5.715) -22,8.03 -22,18.1 v1(-9.6,30.5)
SAI1_RXD4: J47.16 R89.2 R105.1 U5.B20 U7.7 | length 154.5
  1-TOP w0.2: v1(-19.685,6.985) U5.B20@-19.05,6.35 ; J47.16@99.19,35.73 99.19,33.41 99.8,32.8 99.8,31.3 99.6,31.1 R89.2@99.2,31.1 ; R89.2@99.2,30.9 98.8,30.9 98.6,30.7 v1(98.6,28.8) 100.025,27.375 U7.7@100.025,22.9
  3-INTOP w0.15: v1(-8.4,31) 48.493,31 50.503,28.99 90.11,28.99 91.6,27.5 97.3,27.5 v1(98.6,28.8)
  6-INBOT w0.15: v1(-19.685,6.985) -21.5,8.8 -21.5,17.9 v1(-8.4,31)
SAI1_RXD5: J47.18 R90.2 R106.1 U5.B21 | length 144.1
  1-TOP w0.2: v1(-19.685,8.255) U5.B21@-19.05,7.62 ; v1(96.2,28) 96.2,30.7 96.4,30.9 R90.2@96.8,30.9 ; J47.18@96.65,35.73 96.65,33.55 97.4,32.8 97.4,31.3 97.2,31.1 R90.2@96.8,31.1
  3-INTOP w0.15: v1(-7.2,31.5) 48.686,31.5 50.706,29.48 90.313,29.48 91.793,28 v1(96.2,28)
  6-INBOT w0.15: v1(-19.685,8.255) -21,9.57 -21,17.7 v1(-7.2,31.5)
SAI1_RXD6: J47.20 R91.2 R107.1 U5.B22 | length 139.3
  1-TOP w0.2: v1(-19.685,9.525) U5.B22@-19.05,8.89 ; v1(93.8,28.5) 93.8,30.7 94,30.9 R91.2@94.4,30.9 ; J47.20@94.11,35.73 94.11,33.69 95,32.8 95,31.3 94.8,31.1 R91.2@94.4,31.1
  3-INTOP w0.15: v1(-6,32) 48.893,32 50.913,29.98 90.52,29.98 92,28.5 v1(93.8,28.5)
  6-INBOT w0.15: v1(-19.685,9.525) -20.48,10.32 -20.48,17.52 v1(-6,32)
SAI1_RXD7: J47.22 R92.2 R108.1 U5.C20 | length 136.9
  1-TOP w0.2: v1(-18.415,6.985) U5.C20@-17.78,6.35 ; v1(91.3,31) R92.2@92,31 ; J47.22@91.57,35.73 91.57,33.83 92.6,32.8 92.6,31.3 92.4,31.1 R92.2@92,31.1
  3-INTOP w0.15: v1(-4.8,32.5) 49.1,32.5 51.12,30.48 90.78,30.48 v1(91.3,31)
  6-INBOT w0.15: v1(-18.415,6.985) -19.05,7.62 -19.05,9.562 -20.16,10.672 -20.16,17.14 v1(-4.8,32.5)
SAI1_RXFS: J47.4 U5.AJ24 | length 113.6
  1-TOP w0.2: U5.AJ24@15.24,11.43 v1(15.875,12.065) ; v1(106.5,22.5) 106.5,23.1 114.43,31.03 J47.4@114.43,35.73
  3-INTOP w0.15: v1(15.875,12.065) 16.35,12.54 20.345,12.54 21.385,11.5 31.6,11.5 35.1,15 39.4,15 40.4,16 57.5,16 58,15.5 74.2,15.5 76.7,18 84.2,18 87.7,21.5 96,21.5 97,22.5 v1(106.5,22.5)
SAI1_TXC: J47.5 U5.AK28 | length 117.9
  1-TOP w0.2: U5.AK28@16.51,16.51 21,21 33.1,21 v1(39.6,14.5) ; v1(106,21) 106,23.3 113.16,30.46 113.16,37 J47.5@111.89,38.27
  3-INTOP w0.15: v1(39.6,14.5) 40.6,15.5 57.3,15.5 57.8,15 74.4,15 76.9,17.5 84.393,17.5 87.893,21 v1(106,21)
SAI1_TXD0: J47.7 R93.2 R109.1 U5.AJ21 | length 116.8
  1-TOP w0.2: U5.AJ21@15.24,7.62 v1(15.875,8.255) ; v1(103,19) 105,21 105,24.525 109.4,28.925 109.4,30.7 109.6,30.9 R93.2@110,30.9 ; J47.7@109.35,38.27 110.6,37.02 110.6,31.3 110.4,31.1 R93.2@110,31.1
  3-INTOP w0.15: v1(15.875,8.255) 16.51,8.89 19.05,8.89 19.94,8 26.2,8 26.7,8.5 32.8,8.5 35.8,11.5 40.8,11.5 41.8,12.5 56.1,12.5 56.6,12 75.6,12 78.1,14.5 85.6,14.5 89.1,18 102,18 v1(103,19)
SAI1_TXD1: J47.9 R94.2 R110.1 U5.AK26 | length 108.7
  1-TOP w0.2: U5.AK26@16.51,13.97 v1(17.145,14.605) ; v1(103.9,25) 103.9,25.9 107,29 107,30.7 107.2,30.9 R94.2@107.6,30.9 ; J47.9@106.81,38.27 108.2,36.88 108.2,31.3 108,31.1 R94.2@107.6,31.1
  3-INTOP w0.15: v1(17.145,14.605) 21.04,18.5 27,18.5 27.5,18 38.9,18 39.4,18.5 58.5,18.5 59,18 73.2,18 75.7,20.5 83.2,20.5 87.2,24.5 98.5,24.5 99,25 v1(103.9,25)
SAI1_TXD2: J47.11 R95.2 R111.1 U5.AK27 U7.3 | length 109
  1-TOP w0.2: U5.AK27@16.51,15.24 v1(17.145,15.875) ; U7.3@102.625,22.9 v1(102.625,26) 102.625,27.025 104.6,29 104.6,30.7 104.8,30.9 R95.2@105.2,30.9 ; J47.11@104.27,38.27 105.54,37 105.54,33.06 105.8,32.8 105.8,31.3 105.6,31.1 R95.2@105.2,31.1
  3-INTOP w0.15: v1(17.145,15.875) 20.77,19.5 30.2,19.5 30.7,19 38.5,19 39,19.5 58.9,19.5 59.4,19 72.8,19 75.3,21.5 82.8,21.5 86.8,25.5 98.1,25.5 98.6,26 v1(102.625,26)
SAI1_TXD3: J47.13 R96.2 R112.1 U5.AH25 U7.5 | length 110.4
  1-TOP w0.2: U5.AH25@13.97,12.7 v1(14.605,13.335) ; U7.5@101.325,22.9 v1(101.325,24.5) 101.325,28.125 102.2,29 102.2,30.7 102.4,30.9 R96.2@102.8,30.9 ; J47.13@101.73,38.27 103,37 103,33.2 103.4,32.8 103.4,31.3 103.2,31.1 R96.2@102.8,31.1
  3-INTOP w0.15: v1(14.605,13.335) 15.38,14.11 17.41,14.11 17.78,14.48 17.78,14.68 21.1,18 26.8,18 27.3,17.5 39.1,17.5 39.6,18 58.3,18 58.8,17.5 73.4,17.5 75.9,20 83.4,20 87.4,24 98.7,24 99.2,24.5 v1(101.325,24.5)
SAI1_TXD4: J47.15 R97.2 R113.1 U5.AH26 U7.6 | length 109.6
  1-TOP w0.2: U5.AH26@13.97,13.97 v1(14.605,14.605) ; J47.15@99.19,38.27 100.46,37 100.46,33.34 101,32.8 101,31.3 100.8,31.1 R97.2@100.4,31.1 ; R97.2@100.4,30.9 100,30.9 99.8,30.7 99.8,28.9 100.675,28.025 v1(100.675,25.5) U7.6@100.675,22.9
  3-INTOP w0.15: v1(14.605,14.605) 15.203,14.605 15.678,15.08 17.08,15.08 21,19 27.3,19 27.8,18.5 38.7,18.5 39.2,19 58.7,19 59.2,18.5 73,18.5 75.5,21 83,21 87,25 98.3,25 98.8,25.5 v1(100.675,25.5)
SAI1_TXD5: J47.17 R98.2 R114.1 U5.AJ25 U7.8 | length 107.7
  1-TOP w0.2: U5.AJ25@15.24,12.7 v1(15.875,13.335) ; J47.17@96.65,38.27 97.92,37 97.92,33.48 98.6,32.8 98.6,31.3 98.4,31.1 R98.2@98,31.1 ; R98.2@98,30.9 97.6,30.9 97.4,30.7 97.4,29 99.375,27.025 v1(99.375,24) U7.8@99.375,22.9
  3-INTOP w0.15: v1(15.875,13.335) 16.35,13.81 21.175,13.81 21.985,13 31,13 34.5,16.5 38.8,16.5 39.8,17.5 58.1,17.5 58.6,17 73.6,17 76.1,19.5 83.6,19.5 87.6,23.5 98.875,23.5 v1(99.375,24)
SAI1_TXD6: J47.19 R99.2 R115.1 U5.AH24 | length 104.1
  1-TOP w0.2: U5.AH24@13.97,11.43 v1(14.605,12.065) ; J47.19@94.11,38.27 95.38,37 95.38,33.62 96.2,32.8 96.2,31.3 96,31.1 R99.2@95.6,31.1 ; v1(95,22.5) 95,30.7 95.2,30.9 R99.2@95.6,30.9
  3-INTOP w0.15: v1(14.605,12.065) 15.4,12.86 20.725,12.86 21.585,12 31.4,12 34.9,15.5 39.2,15.5 40.2,16.5 57.7,16.5 58.2,16 74,16 76.5,18.5 84,18.5 88,22.5 v1(95,22.5)
SAI1_TXD7: J47.21 R100.2 R116.1 U5.AJ23 | length 103.2
  1-TOP w0.2: U5.AJ23@15.24,10.16 v1(15.875,10.795) ; J47.21@91.57,38.27 92.84,37 92.84,33.76 93.8,32.8 93.8,31.3 93.6,31.1 R100.2@93.2,31.1 ; v1(92.6,19.5) 92.6,30.7 92.8,30.9 R100.2@93.2,30.9
  3-INTOP w0.15: v1(15.875,10.795) 16.35,11.27 19.515,11.27 20.785,10 32.2,10 35.2,13 40.2,13 41.2,14 56.7,14 57.2,13.5 75,13.5 77.5,16 85,16 88.5,19.5 v1(92.6,19.5)
SAI1_TXFS: J47.3 U5.AH23 | length 120.8
  1-TOP w0.2: U5.AH23@13.97,10.16 v1(14.605,10.795) ; v1(107,20) 107,22.9 115.7,31.6 115.7,37 J47.3@114.43,38.27
  3-INTOP w0.15: v1(14.605,10.795) 15.4,11.59 19.895,11.59 20.985,10.5 32,10.5 35,13.5 40,13.5 41,14.5 56.9,14.5 57.4,14 74.8,14 77.3,16.5 84.8,16.5 88.3,20 v1(107,20)
SAI2_MCLK: U5.B24 U29.5 | length 48.2
  1-TOP w0.15: v1(-55,30) U29.5@-55,31.57
  1-TOP w0.2: v1(-19.685,12.065) U5.B24@-19.05,11.43
  3-INTOP w0.15: v1(-55,30) -54.5,30.5 -47.3,30.5 -44.5,27.7 -44.5,23.3 -33.265,12.065 v1(-19.685,12.065)
SAI2_RXD: R237.1 U5.E21 | length 38.7
  1-TOP w0.2: R237.1@-47,23.5 v1(-46.2,23.5) ; v1(-15.875,8.255) U5.E21@-15.24,7.62
  3-INTOP w0.15: v1(-46.2,23.5) -46.2,22.879 -33.886,10.565 -23.135,10.565 -21.46,8.89 -16.51,8.89 v1(-15.875,8.255)
SAI2_TXC: R238.1 R239.1 U5.E23 | length 39.6
  1-TOP w0.2: v1(-47,24.6) R238.1@-47,25.5 ; v1(-15.875,10.795) U5.E23@-15.24,10.16
  3-INTOP w0.15: v1(-47,24.6) -46.5,24.6 -45.5,23.6 -45.5,22.886 -33.679,11.065 -22.935,11.065 -22.03,10.16 -16.51,10.16 v1(-15.875,10.795)
SAI2_TXD: R235.1 R236.1 U5.E20 | length 43.6
  1-TOP w0.2: v1(-47,26.6) R235.1@-47,27.5 ; v1(-15.875,6.985) U5.E20@-15.24,6.35
  3-INTOP w0.15: v1(-47,26.6) -47.5,26.1 -47.5,23.472 -34.093,10.065 -23.335,10.065 -20.89,7.62 -16.51,7.62 v1(-15.875,6.985)
SAI2_TXFS: R240.1 R241.1 U5.C19 | length 44.4
  1-TOP w0.2: v1(-47,28.6) R240.1@-47,29.5 ; v1(-18.415,5.715) U5.C19@-17.78,5.08
  3-INTOP w0.15: v1(-47,28.6) -48,27.6 -48,23.264 -34.301,9.565 -23.535,9.565 -20.32,6.35 -19.05,6.35 v1(-18.415,5.715)
SCU_BOOT_MODE0: R80.2 S1.2 TP7.1 U5.AE29 | length 138.1
  1-TOP w0.2: U5.AE29@10.16,17.78 v1(10.16,34) ; R80.2@123.48,36.2 v1(124.1,36.2) S1.2@128.43,36.2
  3-INTOP w0.15: v1(10.16,34) 49.5,34 52,36.5 85.793,36.5 88.293,34 118.2,34 119.8,35.6 123.5,35.6 v1(124.1,36.2)
SCU_BOOT_MODE1: R77.1 S1.1 TP6.1 U5.AD29 | length 140.4
  1-TOP w0.2: U5.AD29@8.89,17.78 9.5,18.39 v1(9.5,34.5) ; R77.1@123.48,38.7 v1(124.1,38.7) S1.1@128.51,38.7
  3-INTOP w0.15: v1(9.5,34.5) 49.293,34.5 51.793,37 86,37 88.5,34.5 118,34.5 121.6,38.1 123.5,38.1 v1(124.1,38.7)
SCU_BOOT_MODE2: R81.2 R82.2 U5.AJ28 | length 23
  1-TOP w0.2: R82.2@14.8,38.02 R81.2@15.99,38.02 ; U5.AJ28@15.24,16.51 v1(15.875,17.145) ; v1(16,37) R81.2@16,38.02
  6-INBOT w0.15: v1(15.875,17.145) 15.875,19.875 16,20 v1(16,37)
SCU_BOOT_MODE3: R83.2 R84.2 U5.AJ27 | length 24.8
  1-TOP w0.2: U5.AJ27@15.24,15.24 v1(15.875,15.875) ; v1(17.3,37) R84.2@17.3,38.02 R83.2@18.5,38.02
  6-INBOT w0.15: v1(15.875,15.875) 17,17 17,36.7 v1(17.3,37)
SHLD: J27.SHLD1 J27.SHLD2 J31.M1 J31.M2 J31.M3 J31.M4 J33.SH1 J33.SH2 J33.SH3 J33.SH4 J34.6 J34.7 J34.8 J34.9 R180.2 | length 251.6
  1-TOP w0.4: v3(-19.35,-64) -15.15,-64 -12.85,-64 v3(-8.65,-64)
  1-TOP w0.5: v3(51.29,-63.31) J31.M4@52.95,-63.31 53,-63.31 v3(53,-61.6) ; v3(53,-59.4) J31.M2@53,-57.35 ; J31.M3@69,-63.31 v3(69,-61.6) ; v3(69,-59.4) J31.M1@69,-57.35 ; J31.M3@69.05,-63.31 v3(70.76,-63.31)
  1-TOP w1: J27.SHLD2@-42.645,-54 -42.509,-53.864 -41.164,-53.864 -40,-52.7 R180.2@-40,-51.6
  8-BOTTOM w1: J27.SHLD1@-58.355,-53.5 -50.5,-53.5 ; J27.SHLD2@-42.645,-53.5 -50.5,-53.5 ; v3(53,-59.4) 53,-60.5 ; v3(69,-59.4) 69,-60.5 ; J33.SH1@112.939,-57.5 J33.SH1@113.43,-57.5 ; J33.SH2@113.43,-51.82 J33.SH1@113.43,-57.5 ; J33.SH4@126.57,-51.82 J33.SH3@126.57,-57.5 J33.SH1@113.43,-57.5 ; -50.5,-53.5 -50.5,-61.5 -48,-64 -42,-64 -19.4,-64 -19.2,-64 -8.8,-64 v3(-8.65,-64) 50.6,-64 v3(51.29,-63.31) v3(53,-61.6) 53,-60.5 ; 53,-60.5 69,-60.5 ; 69,-60.5 v3(69,-61.6) 71.4,-64 112,-64 113.43,-62.57 J33.SH1@113.43,-57.5
SN65DSI83_CLK_N: U17.23 U21.25 | length 36.6
  1-TOP w0.15: U21.25@2.68,-45.75 2.745,-45.815 3.465,-45.815 3.473,-45.823 3.7,-45.823 4.057,-45.823 4.205,-45.675 v1(4.3,-45.675) ; v1(34.225,-49.3) 34.225,-49.205 34.077,-49.057 34.077,-48.923 35.423,-47.577 36.282,-47.577 U17.23@36.305,-47.6
  8-BOTTOM w0.15: v1(4.3,-45.675) 4.395,-45.675 4.543,-45.823 25.623,-45.823 27.7,-47.9 33.2,-47.9 34.077,-48.777 34.077,-49.057 34.225,-49.205 v1(34.225,-49.3)
SN65DSI83_CLK_P: U17.22 U21.24 | length 36.6
  1-TOP w0.15: U21.24@2.68,-46.25 2.745,-46.185 3.465,-46.185 3.473,-46.177 3.678,-46.177 4.057,-46.177 4.205,-46.325 v1(4.3,-46.325) ; v1(33.575,-49.3) 33.575,-49.205 33.723,-49.057 33.723,-48.776 35.276,-47.223 36.282,-47.223 U17.22@36.305,-47.2
  8-BOTTOM w0.15: v1(4.3,-46.325) 4.395,-46.325 4.543,-46.177 25.476,-46.177 27.553,-48.254 33.053,-48.254 33.723,-48.924 33.723,-49.057 33.575,-49.205 v1(33.575,-49.3)
SN65DSI83_D0_N: U18.21 U21.20 | length 38.2
  1-TOP w0.15: U21.20@2.68,-48.25 2.745,-48.315 3.465,-48.315 3.473,-48.323 11.757,-48.323 ; v1(25.525,-50.2) 25.525,-50.105 25.377,-49.957 25.377,-47.923 26.523,-46.777 27.282,-46.777 U18.21@27.305,-46.8
  8-BOTTOM w0.15: 12.243,-48.323 21.223,-48.323 21.7,-48.8 21.7,-53.7 22.146,-54.146 23.054,-54.146 23.623,-53.577 23.623,-49.276 24.153,-48.746 24.847,-48.746 25.377,-49.276 25.377,-49.957 25.525,-50.105 v1(25.525,-50.2)
  other v1: 12,-48.175
SN65DSI83_D0_P: U18.20 U21.19 | length 38.2
  1-TOP w0.15: U21.19@2.68,-48.75 2.745,-48.685 3.465,-48.685 3.473,-48.677 11.757,-48.677 ; v1(24.875,-50.2) 24.875,-50.105 25.023,-49.957 25.023,-47.776 26.376,-46.423 27.282,-46.423 U18.20@27.305,-46.4
  8-BOTTOM w0.15: 12.243,-48.677 21.076,-48.677 21.346,-48.947 21.346,-53.847 21.999,-54.5 23.201,-54.5 23.977,-53.724 23.977,-49.423 24.3,-49.1 24.7,-49.1 25.023,-49.423 25.023,-49.957 24.875,-50.105 v1(24.875,-50.2)
  other v1: 12,-48.825
SN65DSI83_D1_N: U18.18 U21.22 | length 36.6
  1-TOP w0.15: U21.22@2.68,-47.25 2.745,-47.315 3.465,-47.315 3.473,-47.323 3.825,-47.323 4.057,-47.323 4.205,-47.175 v1(4.3,-47.175) ; v1(23.5,-47.175) 23.595,-47.175 23.743,-47.323 24.076,-47.323 26.176,-45.223 27.573,-45.223 27.798,-45.448 27.975,-45.448 28,-45.472 U18.18@28,-45.755
  8-BOTTOM w0.15: v1(4.3,-47.175) 4.395,-47.175 4.543,-47.323 7.024,-47.323 10.601,-50.9 11.799,-50.9 12,-50.699 12,-50.501 11.699,-50.2 10.8,-50.2 8.8,-48.2 8.8,-47.7 9.177,-47.323 11.3,-47.323 23.257,-47.323 23.405,-47.175 v1(23.5,-47.175)
SN65DSI83_D1_P: U18.19 U21.21 | length 36.6
  1-TOP w0.15: U21.21@2.68,-47.75 2.745,-47.685 3.465,-47.685 3.473,-47.677 3.678,-47.677 4.057,-47.677 4.205,-47.825 v1(4.3,-47.825) ; v1(23.5,-47.825) 23.595,-47.825 23.743,-47.677 24.223,-47.677 24.75,-47.15 25.329,-46.571 25.428,-46.571 25.464,-46.606 25.563,-46.606 25.711,-46.458 25.711,-46.359 25.676,-46.323 25.676,-46.224 25.75,-46.15 26.323,-45.577 27.427,-45.577 27.591,-45.741 27.591,-45.975 27.566,-46 U18.19@27.305,-46
  8-BOTTOM w0.15: v1(4.3,-47.825) 4.395,-47.825 4.543,-47.677 6.877,-47.677 10.454,-51.254 11.946,-51.254 12.354,-50.846 12.354,-50.354 11.846,-49.846 10.947,-49.846 9.154,-48.053 9.154,-47.847 9.324,-47.677 11.3,-47.677 23.257,-47.677 23.405,-47.825 v1(23.5,-47.825)
SN65DSI83_D2_N: U17.21 U21.28 | length 36.6
  1-TOP w0.15: U21.28@2.68,-44.25 2.745,-44.315 3.465,-44.315 3.473,-44.323 3.825,-44.323 4.057,-44.323 4.205,-44.175 v1(4.3,-44.175) ; v1(34.225,-47.3) 34.225,-47.205 34.077,-47.057 34.077,-46.923 34.223,-46.777 36.282,-46.777 U17.21@36.305,-46.8
  8-BOTTOM w0.15: v1(4.3,-44.175) 4.395,-44.175 4.543,-44.323 26.124,-44.323 27.847,-46.046 30.614,-46.046 31.514,-45.146 32.447,-45.146 34.077,-46.776 34.077,-47.057 34.225,-47.205 v1(34.225,-47.3)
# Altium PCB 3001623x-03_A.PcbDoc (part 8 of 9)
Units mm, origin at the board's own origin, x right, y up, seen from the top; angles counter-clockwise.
Board outline 210 x 130 mm, 9 copper layers (1-TOP, 2-GND, 3-INTOP, 4-PWR, 5-PWR, 6-INBOT, Signal_4, 7-GND, 8-BOTTOM), stack 1.979 mm thick; 755 components, 650 nets, 2980 pads, 2365 vias.

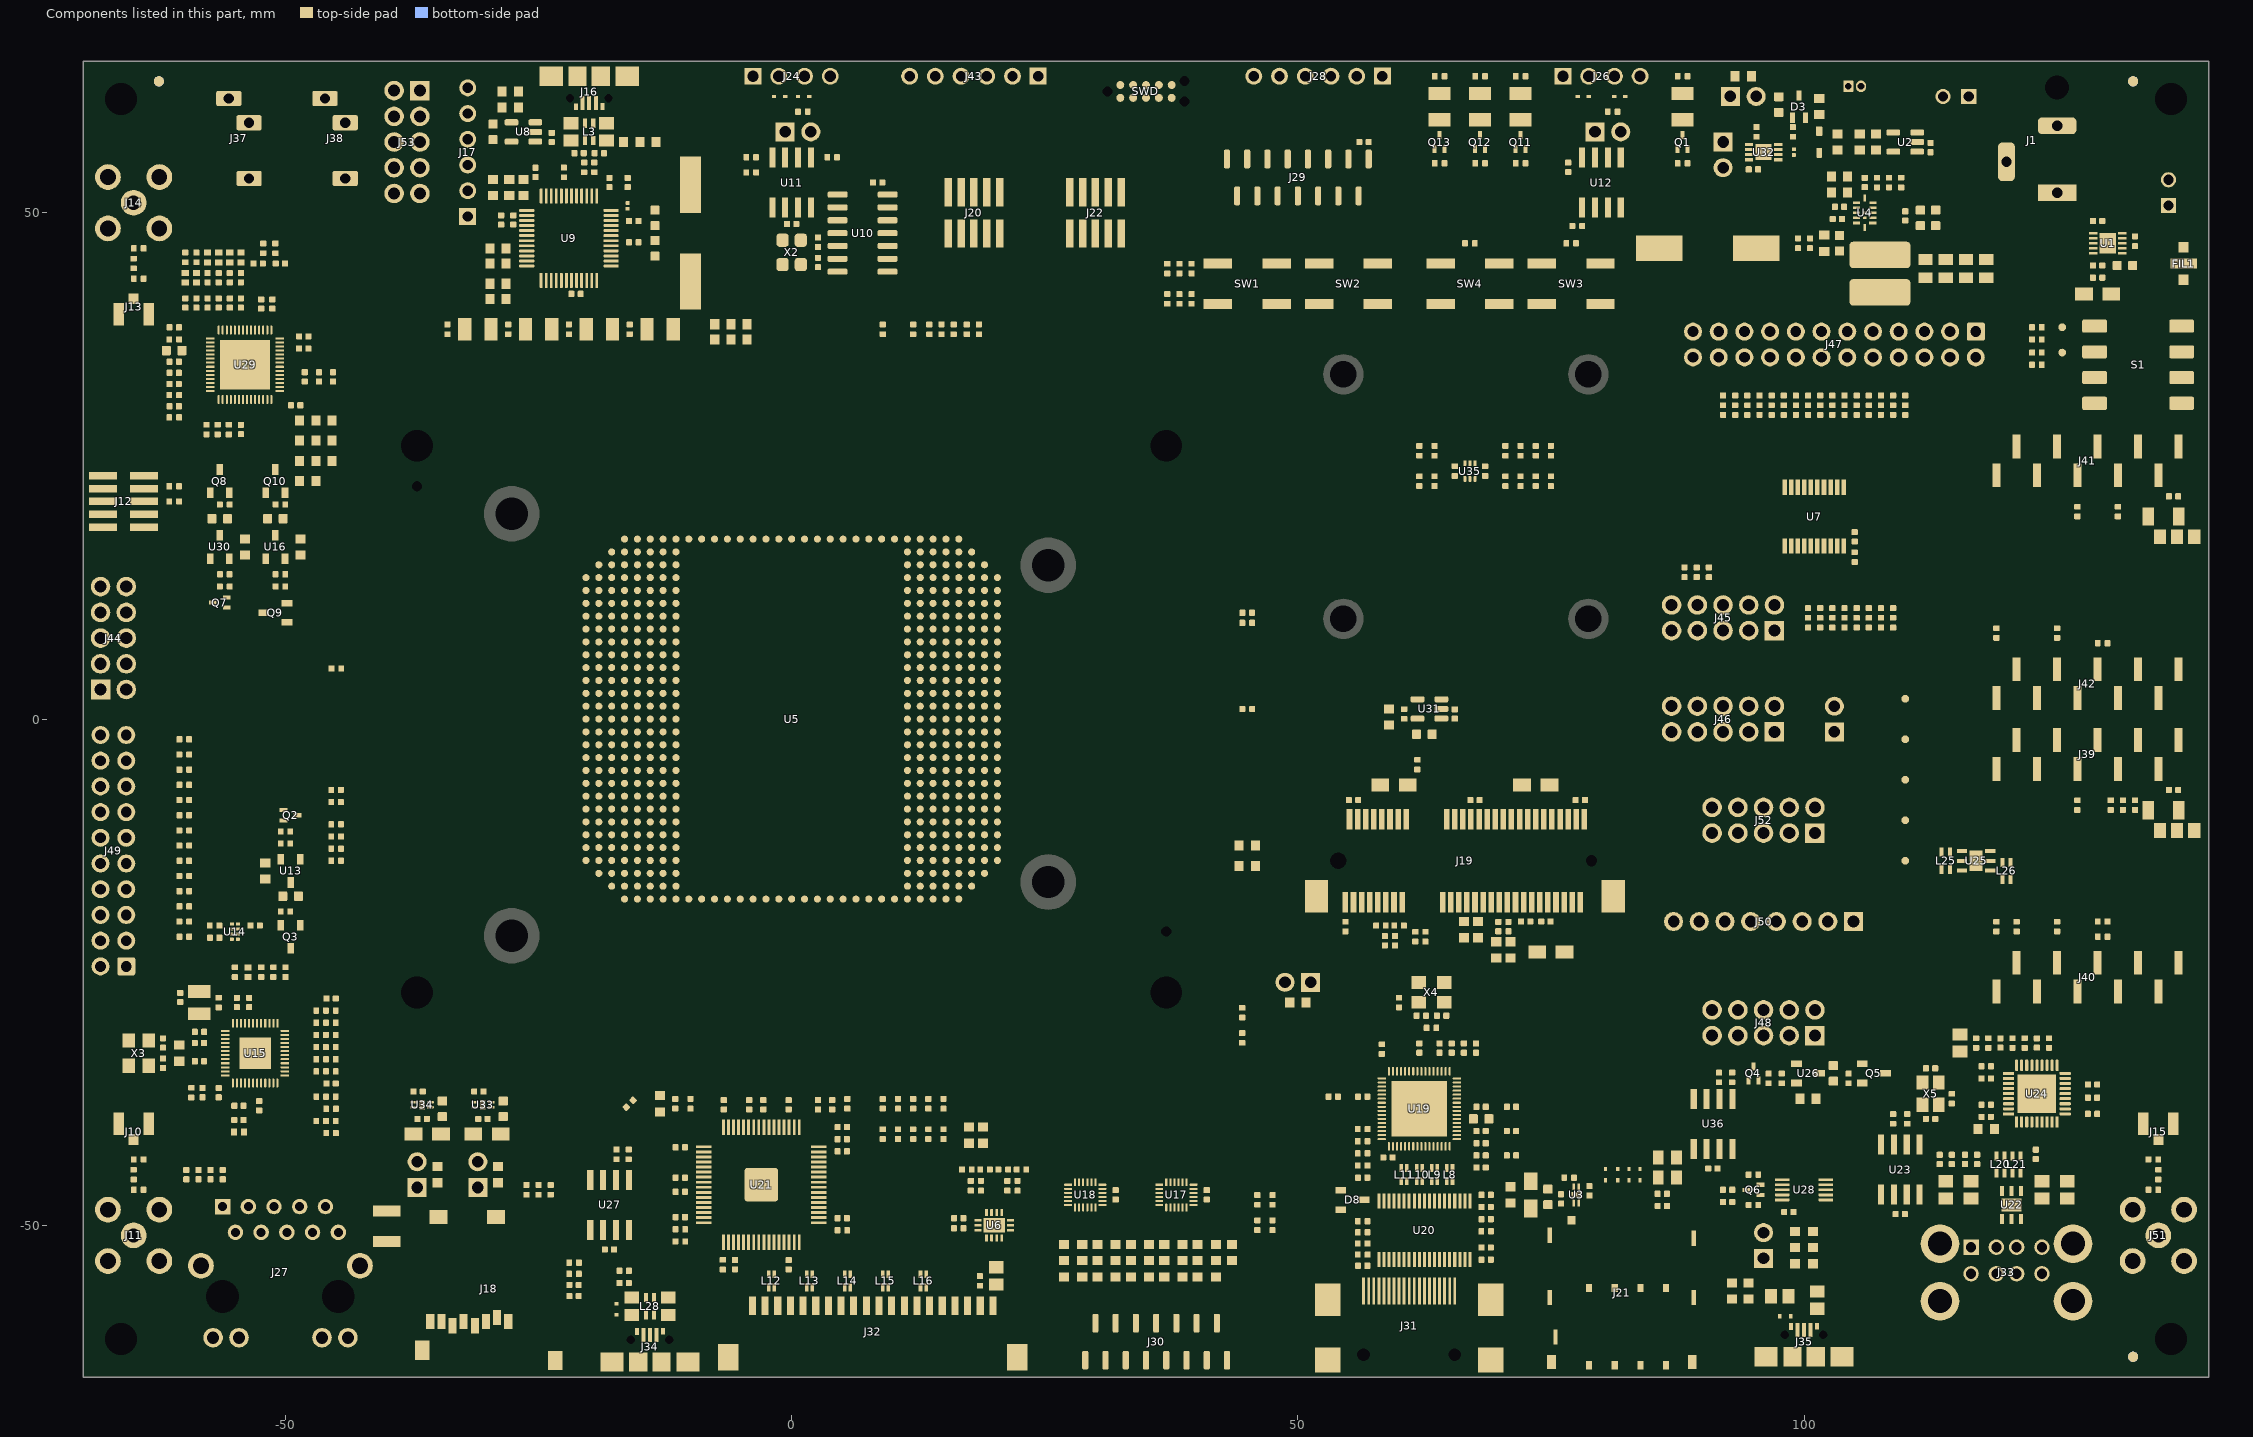
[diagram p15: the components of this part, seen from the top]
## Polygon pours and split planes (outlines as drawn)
GND on 1-TOP "GND_PLANE" (solid, remove dead copper, pour order 62): -70,-65 140,-65 140,65 -70,65
NetC187_1 on 1-TOP "NetC187_1" (solid, remove dead copper, pour order 42): -32.4,-44.6 -32.1,-44.9 -27.9,-44.9 -27.3,-44.3 -27.3,-38.5 -27.5,-38.3 -30.099,-38.299 -30.3,-38.5 -30.3,-41.8 -30.5,-42 -31.4,-42 -32.4,-43
NetC191_1 on 1-TOP "NetC191_1" (solid, remove dead copper, pour order 40): -38.4,-44.6 -38.1,-44.9 -33.9,-44.9 -33.3,-44.3 -33.3,-38.5 -33.5,-38.3 -36.099,-38.299 -36.3,-38.5 -36.3,-41.8 -36.5,-42 -37.4,-42 -38.4,-43
GND on 1-TOP "GND" (solid, remove dead copper, pour order 28): 108.8,49.3 108.8,47.6 109,47.4 110.3,47.4 110.8,46.9 110.8,44.8 111,44.6 119,44.6 119.2,44.8 119.2,47.3 117,49.5 109,49.5
VIN_PROT on 1-TOP "VIN_PROT" (solid, remove dead copper, pour order 26): 107.1,49.9 110.283,49.9 110.783,49.4 113.7,49.4 114.1,49.8 114.1,52 113.9,52.2 110.2,52.2 110,52 109.2,52
VIN_PROT on 1-TOP "VIN_PROT" (solid, remove dead copper, pour order 4): 125.5,41.5 126.5,40.5 128.5,40.5 129,41 129,47.3 127.8,47.3 126.3,47.3 125.5,46.5
CT on 1-TOP "AGND" (solid, remove dead copper, pour order 2): -60.5,-45.2 -60.3,-45 -55.7,-45 -55.5,-45.2 -55.5,-48 -56.9,-48 -56.9,-47.2 -57.6,-46.5 -60,-46.5 -60.5,-46
3V3_SOM_EXT on 1-TOP "3V3_SOM_EXT" (solid, remove dead copper, pour order 22): -54.3,12.3 -53,13.6 -53,16.6 -53.2,16.8 -55.9,16.8 -56.1,16.6 -56.1,12.5 -55.9,12.3
3V3_CODEC on 1-TOP "3V3_USB" (solid, remove dead copper, pour order 20): -54.3,21.5 -53,20.2 -53,17.2 -53.2,17 -57,17 -57.2,17.2 -57.2,19.8 -55.5,21.5
1V8_SOM_EXT on 1-TOP "3V3_SOM_EXT" (solid, remove dead copper, pour order 18): -48.8,12.3 -47.5,13.6 -47.5,16.6 -47.7,16.8 -50.4,16.8 -50.6,16.6 -50.6,12.5 -50.4,12.3
1V8_CODEC on 1-TOP "3V3_USB" (solid, remove dead copper, pour order 16): -48.8,21.5 -47.5,20.2 -47.5,17.2 -47.7,17 -51.5,17 -51.7,17.2 -51.7,19.8 -50,21.5
3V3_SOM_EXT on 1-TOP "3V3_SOM_EXT" (solid, remove dead copper, pour order 14): -51.7,-10.3 -53,-11.6 -53,-14.6 -52.8,-14.8 -50.1,-14.8 -49.9,-14.6 -49.9,-10.5 -50.1,-10.3
3V3_ETH on 1-TOP "3V3_USB" (solid, remove dead copper, pour order 12): -52,-19.2 -53,-18.2 -53,-15.2 -52.8,-15 -49,-15 -48.8,-15.2 -48.8,-17.5 -50.5,-19.2
3V3_USB on 1-TOP "3V3_USB" (solid, remove dead copper, pour order 10): 104.7,-37.5 103.7,-38.5 100.7,-38.5 100.5,-38.3 100.5,-34.5 100.7,-34.3 103,-34.3 104.7,-36
3V3_SOM_EXT on 1-TOP "3V3_SOM_EXT" (solid, remove dead copper, pour order 8): 95.8,-37.2 97.1,-38.5 100.1,-38.5 100.3,-38.3 100.3,-35.6 100.1,-35.4 96,-35.4 95.8,-35.6
VIN on 1-TOP "VIN" (solid, remove dead copper, pour order 6): 131.6,42.9 134,40.5 138.5,40.5 139,41 139,43.5 138.6,43.9 135.8,43.9 135.5,44.2 135.5,45.5 133.7,47.3 131,47.3 131,45.6 131.2,45.4 131.4,45.4 131.6,45.2
3V3_BOARD on 1-TOP "3V3_BOARD" (solid, remove dead copper, pour order 24): 110.8,40.7 111,40.5 117.8,40.5 119.2,41.9 119.2,44.3 119,44.5 111,44.5 110.8,44.3
GND on 1-TOP "GND" (solid, remove dead copper, pour order 52): 122,57 122.5,56.5 127.5,56.5 128,57 128,60 127.5,60.5 122.5,60.5 122,60
VIN_PROT on 1-TOP "3V3" (solid, remove dead copper, pour order 44): 50.4,-24.6 50.1,-24.9 50.1,-29.1 50.4,-29.4 51.9,-29.4 56.2,-25.1 56.2,-24.9 55.9,-24.6
1V8_SOM_EXT on 1-TOP "3V3_SOM_EXT" (solid, remove dead copper, pour order 38): -38.4,-45.4 -38.1,-45.1 -33.9,-45.1 -33.6,-45.4 -33.6,-47.9 -33.9,-48.2 -38.1,-48.2 -38.4,-47.9
3V3_SOM_EXT on 1-TOP "3V3_SOM_EXT" (solid, remove dead copper, pour order 36): -32.4,-45.4 -32.1,-45.1 -27.9,-45.1 -27.6,-45.4 -27.6,-47.9 -27.9,-48.2 -32.1,-48.2 -32.4,-47.9
NetFIL1_1 on 1-TOP "VIN_PROT" (solid, remove dead copper, pour order 32): 121.5,51 122.5,50 131.5,50 135.4,46.1 138.6,46.1 139,46.5 139,54.5 138,55.5 122.5,55.5 121.5,54.5
NetJ6_2 on 1-TOP "NetJ6_2" (solid, remove dead copper, pour order 30): 45,-11.7 45.2,-11.5 49,-11.5 49.8,-12.3 49.8,-29.1 49.5,-29.4 46.4,-29.4 45,-28
GND on 3-INTOP "GND_PLANE" (solid, remove dead copper, pour order 60): -70,-65 140,-65 140,65 -70,65
5V_OUT_HDMI on 3-INTOP "5V_OUT_HDMI" (solid, remove dead copper, pour order 46): 54.5,-54.5 55.5,-55.5 67.5,-55.5 68.5,-54.5 68.5,-51 67.5,-50 55.5,-50 54.5,-51
GND on 8-BOTTOM "GND_PLANE" (solid, remove dead copper, pour order 64): -70,-65 140,-65 140,65 -70,65
3V3_RF on 8-BOTTOM "3V3_RF" (solid, remove dead copper, pour order 48): -18.872,2.337 -14.173,2.337 -13.767,2.743 -13.767,7.267 -14.3,7.8 -45.7,7.8 -47,6.5 -32,6.5 -29.107,3.607 -19.482,3.607 -19.253,3.378 -19.253,2.718
GND on 8-BOTTOM "GND" (solid, remove dead copper, pour order 50): 122,57 122.5,56.5 127.5,56.5 128,57 128,60 127.5,60.5 122.5,60.5 122,60
GND on 6-INBOT "GND_PLANE" (solid, remove dead copper, pour order 58): -70,-65 140,-65 140,65 -70,65
VCC_MCA on 5-PWR (split plane): 104.849,-9.937 101.937,-12.849 69.063,-12.849 45.651,10.563 45.651,21.849 66,21.849 66.039,21.854 66.076,21.869 66.107,21.893 67.607,23.393 67.631,23.424 67.646,23.461 67.651,23.5 67.651,25 67.646,25.039 67.637,25.061 67.631,25.076 67.607,25.107 65.107,27.607 65.076,27.631 65.061,27.637 65.039,27.646 65,27.651 45.063,27.651 23.151,49.563 23.151,64.598 104.849,64.598
VSYS2 on 5-PWR (split plane): 44.849,-16.937 40.937,-20.849 19.158,-20.849 15.391,-17.082 15.391,-16.8 15.391,-14.668 16.573,-13.486 44.849,-13.486
no net on 5-PWR (split plane): -14.151,44.937 -14.151,40.063 -15.063,39.151 -34.849,39.151 -34.849,47.937 -29.437,53.349 -22.563,53.349
VSYS on 5-PWR (split plane): 44.849,-10.063 44.849,-13.184 17.931,-13.184 17.931,-9.588 18.478,-9.041 43.827,-9.041
VIN_PROT on 5-PWR (split plane): 139.598,-64.598 -18.849,-64.598 -18.849,-53.563 -17.937,-52.651 -17.063,-52.651 -12.607,-57.107 -12.576,-57.131 -12.539,-57.146 -12.5,-57.151 69,-57.151 69.039,-57.146 69.061,-57.137 69.076,-57.131 69.107,-57.107 75.107,-51.107 75.131,-51.076 75.146,-51.039 75.151,-51 75.151,-37.563 80.107,-32.607 80.131,-32.576 80.146,-32.539 80.151,-32.5 80.151,-31 80.146,-30.961 80.131,-30.924 80.107,-30.893 79.107,-29.893 79.076,-29.869 79.061,-29.863 79.039,-29.854 79,-29.849 50.151,-29.849 50.151,-24.063 54.063,-20.151 105.5,-20.151 105.539,-20.146 105.561,-20.137 105.576,-20.131 105.607,-20.107 123.107,-2.607 123.131,-2.576 123.146,-2.539 123.151,-2.5 123.151,38.5 123.146,38.539 123.137,38.561 123.131,38.576 123.107,38.607 122.107,39.607 122.076,39.631 122.039,39.646 122,39.651 105.151,39.651 105.151,64.598 139.598,64.598
1V8 on 5-PWR (split plane): 45.349,25.437 45.349,10.5 45.354,10.461 45.363,10.439 45.369,10.424 45.393,10.393 68.893,-13.107 68.924,-13.131 68.961,-13.146 69,-13.151 102,-13.151 102.039,-13.146 102.061,-13.137 102.076,-13.131 102.107,-13.107 105.107,-10.107 105.131,-10.076 105.146,-10.039 105.151,-10 105.151,39.349 121.937,39.349 122.849,38.437 122.849,-2.437 105.437,-19.849 54,-19.849 53.961,-19.854 53.924,-19.869 53.893,-19.893 49.893,-23.893 49.869,-23.924 49.854,-23.961 49.849,-24 49.849,-29.937 42.937,-36.849 8.2,-36.849 8.161,-36.854 8.124,-36.869 8.093,-36.893 6.237,-38.749 5.963,-38.749 5.107,-37.893 5.076,-37.869 5.061,-37.863 5.039,-37.854 5,-37.849 -18,-37.849 -18.039,-37.854 -18.065,-37.865 -18.076,-37.869 -18.107,-37.893 -22.063,-41.849 -35.937,-41.849 -37.849,-39.937 -37.849,-23 -37.854,-22.961 -37.869,-22.924 -37.893,-22.893 -47.849,-12.937 -47.849,5.437 -28.437,24.849 -10.5,24.849 -10.461,24.854 -10.439,24.863 -10.424,24.869 -10.393,24.893 5.063,40.349 30.437,40.349
VDDIO1 on 5-PWR (split plane): -43.151,-28.063 -43.151,-36.349 -50.349,-36.349 -50.349,-27.151 -44.063,-27.151
1V8_CODEC on 5-PWR (split plane): -45.151,20.563 -47.563,18.151 -60.849,18.151 -60.849,34.437 -56.437,38.849 -45.151,38.849
DVDDL1 on 5-PWR (split plane): -50.651,-23.563 -50.651,-24.849 -53.5,-24.849 -53.539,-24.854 -53.576,-24.869 -53.607,-24.893 -54.307,-25.593 -54.331,-25.624 -54.346,-25.661 -54.351,-25.7 -54.351,-29.137 -54.963,-29.749 -60.849,-29.749 -60.849,-23.151 -51.063,-23.151
NetC75_2 on 5-PWR (split plane): -50.651,-36.437 -52.063,-37.849 -54.937,-37.849 -57.893,-34.893 -57.924,-34.869 -57.939,-34.863 -57.961,-34.854 -58,-34.849 -60.849,-34.849 -60.849,-30.051 -54.9,-30.051 -54.861,-30.046 -54.824,-30.031 -54.793,-30.007 -54.093,-29.307 -54.069,-29.276 -54.054,-29.239 -54.049,-29.2 -54.049,-25.763 -53.437,-25.151 -50.651,-25.151
1V8_SOM_EXT on 5-PWR (split plane): 168 vertices, not listed, extent -60.849,-53.849 70.849,64.598
5V on 5-PWR (split plane): 4.849,52.063 -2.063,45.151 -13.937,45.151 -22.393,53.607 -22.424,53.631 -22.461,53.646 -22.5,53.651 -29.5,53.651 -29.539,53.646 -29.576,53.631 -29.607,53.607 -35.107,48.107 -35.131,48.076 -35.137,48.061 -35.146,48.039 -35.151,48 -35.151,39.151 -56.5,39.151 -56.539,39.146 -56.576,39.131 -56.607,39.107 -61.107,34.607 -61.131,34.576 -61.146,34.539 -61.151,34.5 -61.151,-37 -61.146,-37.039 -61.131,-37.076 -61.107,-37.107 -54.607,-43.607 -54.576,-43.631 -54.539,-43.646 -54.5,-43.651 -43.063,-43.651 -36.607,-50.107 -36.576,-50.131 -36.561,-50.137 -36.539,-50.146 -36.5,-50.151 -14.563,-50.151 -10.607,-54.107 -10.576,-54.131 -10.539,-54.146 -10.5,-54.151 18,-54.151 18.039,-54.146 18.061,-54.137 18.076,-54.131 18.107,-54.107 19.563,-52.651 20.937,-52.651 22.393,-54.107 22.424,-54.131 22.461,-54.146 22.5,-54.151 67.5,-54.151 67.539,-54.146 67.576,-54.131 67.607,-54.107 69.607,-52.107 69.631,-52.076 69.646,-52.039 69.651,-52 69.651,-50.9 69.646,-50.861 69.631,-50.824 69.607,-50.793 67.151,-48.337 67.151,-46.863 71.107,-42.907 71.131,-42.876 71.146,-42.839 71.151,-42.8 71.151,-30.151 78.937,-30.151 79.849,-31.063 79.849,-32.437 74.893,-37.393 74.869,-37.424 74.854,-37.461 74.849,-37.5 74.849,-50.937 68.937,-56.849 -12.437,-56.849 -16.893,-52.393 -16.924,-52.369 -16.939,-52.363 -16.961,-52.354 -17,-52.349 -18,-52.349 -18.039,-52.354 -18.065,-52.365 -18.076,-52.369 -18.107,-52.393 -19.107,-53.393 -19.131,-53.424 -19.146,-53.461 -19.151,-53.5 -19.151,-64.598 -69.598,-64.598 -69.598,64.598 4.849,64.598
VDDH1 on 5-PWR (split plane): -55.107,-38.107 -55.076,-38.131 -55.065,-38.135 -55.039,-38.146 -55,-38.151 -52,-38.151 -51.961,-38.146 -51.924,-38.131 -51.893,-38.107 -50.437,-36.651 -43.151,-36.651 -43.151,-43.349 -54.437,-43.349 -60.849,-36.937 -60.849,-35.151 -58.063,-35.151
GND on 2-GND (split plane): 139.598,-64.598 -69.598,-64.598 -69.598,64.598 139.598,64.598
GND on 7-GND (split plane): 139.598,-64.598 -69.598,-64.598 -69.598,64.598 139.598,64.598
3V3_USB on 4-PWR (split plane): 123.186,-31.9 120.737,-34.349 118.563,-34.349 117.107,-32.893 117.076,-32.869 117.039,-32.854 117,-32.849 115,-32.849 114.961,-32.854 114.924,-32.869 114.893,-32.893 113.893,-33.893 113.869,-33.924 113.863,-33.939 113.854,-33.961 113.849,-34 113.849,-42.349 105.563,-42.349 101.651,-38.437 101.651,-36.563 108.563,-29.651 120.937,-29.651
NetC132_2 on 4-PWR (split plane): 127.849,-36.563 127.849,-39.006 124.506,-42.349 114.151,-42.349 114.151,-34.063 115.063,-33.151 116.937,-33.151 118.393,-34.607 118.424,-34.631 118.435,-34.635 118.461,-34.646 118.5,-34.651 120.8,-34.651 120.839,-34.646 120.861,-34.637 120.876,-34.631 120.907,-34.607 123.4,-32.114
3V3_DBG on 4-PWR (split plane): -14.151,44.937 -14.151,40.063 -15.063,39.151 -33.937,39.151 -34.849,40.063 -34.849,47.937 -29.437,53.349 -22.563,53.349
VIN on 4-PWR (split plane): 139.598,-64.598 94.151,-64.598 94.151,-53.063 95.063,-52.151 128,-52.151 128.039,-52.146 128.061,-52.137 128.076,-52.131 128.107,-52.107 135.107,-45.107 135.131,-45.076 135.146,-45.039 135.151,-45 135.151,50 135.146,50.039 135.137,50.061 135.131,50.076 135.107,50.107 130.107,55.107 130.076,55.131 130.039,55.146 130,55.151 113.063,55.151 112.151,56.063 112.151,64.598 139.598,64.598
3V3_BOARD on 4-PWR (split plane): 118.349,42.937 118.349,39.863 115.393,36.907 115.369,36.876 115.354,36.839 115.349,36.8 115.349,35 115.354,34.961 115.369,34.924 115.393,34.893 127.849,22.437 127.849,-16.437 125.437,-18.849 116.063,-18.849 104.107,-6.893 104.076,-6.869 104.061,-6.863 104.039,-6.854 104,-6.849 98,-6.849 97.961,-6.854 97.924,-6.869 97.893,-6.893 97.163,-7.623 97.139,-7.654 97.124,-7.691 97.119,-7.73 97.119,-15.667 89.937,-22.849 81,-22.849 80.961,-22.854 80.924,-22.869 80.893,-22.893 74.937,-28.849 24.5,-28.849 24.461,-28.854 24.439,-28.863 24.424,-28.869 24.393,-28.893 18.893,-34.393 18.869,-34.424 18.854,-34.461 18.849,-34.5 18.849,-49.937 17.937,-50.849 17.063,-50.849 16.151,-49.937 16.151,-47.3 16.146,-47.261 16.131,-47.224 16.107,-47.193 11.557,-42.643 11.526,-42.619 11.511,-42.613 11.489,-42.604 11.45,-42.599 9.813,-42.599 6.314,-39.1 36.263,-9.151 45,-9.151 45.039,-9.146 45.076,-9.131 45.107,-9.107 59.063,4.849 105,4.849 105.039,4.854 105.076,4.869 105.107,4.893 108.607,8.393 108.631,8.424 108.646,8.461 108.651,8.5 108.651,15.5 108.646,15.539 108.631,15.576 108.607,15.607 105.151,19.063 105.151,41.937 106.563,43.349 117.937,43.349
3V3_CODEC on 4-PWR (split plane): -45.151,37.937 -45.151,20.563 -47.563,18.151 -60.437,18.151 -60.849,18.563 -60.849,34.437 -56.437,38.849 -46.063,38.849
3V3_ETH on 4-PWR (split plane): -50.651,-16.563 -50.651,-38.437 -54.063,-41.849 -55.937,-41.849 -60.849,-36.937 -60.849,-24.063 -52.937,-16.151 -51.063,-16.151
3V3_SOM_EXT on 4-PWR (split plane): 111.849,56 111.854,55.961 111.863,55.939 111.869,55.924 111.893,55.893 112.893,54.893 112.924,54.869 112.961,54.854 113,54.849 129.937,54.849 134.849,49.937 134.849,-44.937 127.937,-51.849 95,-51.849 94.961,-51.854 94.924,-51.869 94.893,-51.893 93.893,-52.893 93.869,-52.924 93.854,-52.961 93.849,-53 93.849,-64.598 -69.598,-64.598 -69.598,64.598 111.849,64.598
3V3 on 4-PWR (split plane): 48.893,21.893 48.924,21.869 48.961,21.854 49,21.849 75.1,21.849 75.139,21.854 75.176,21.869 75.207,21.893 85.163,31.849 104.849,31.849 104.849,19 104.854,18.961 104.869,18.924 104.893,18.893 108.349,15.437 108.349,8.563 104.937,5.151 59,5.151 58.961,5.146 58.924,5.131 58.893,5.107 44.937,-8.849 36.2,-8.849 36.161,-8.854 36.124,-8.869 36.093,-8.893 6.1,-38.886 5.107,-37.893 5.076,-37.869 5.061,-37.863 5.039,-37.854 5,-37.849 4.8,-37.849 -18,-37.849 -18.039,-37.854 -18.065,-37.865 -18.076,-37.869 -18.107,-37.893 -22.063,-41.849 -35.937,-41.849 -37.849,-39.937 -37.849,-23 -37.854,-22.961 -37.863,-22.939 -37.869,-22.924 -37.893,-22.893 -47.849,-12.937 -47.849,5.437 -28.437,24.849 -10.5,24.849 -10.461,24.854 -10.439,24.863 -10.424,24.869 -10.393,24.893 5.063,40.349 30.437,40.349

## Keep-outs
Keep-Out Layer:
  the board outline again, w0.15

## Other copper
1-TOP:
  pour cut-out: -57.5,-47 -60.5,-50 -60.5,-65 -41,-65 -41,-52.5 -45.5,-52.5 -45.5,-47
  pour cut-out: -20.5,-61 -20.5,-65 -7.5,-65 -7.5,-61
  pour cut-out: 110,-51 110,-65 130,-65 130,-51 127.5,-48.5 112.5,-48.5
  pour cut-out: 50.5,-54.5 50.5,-65 71.5,-65 71.5,-54.5
  region net 1V8: -37.6,-37.8 -37.6,-34 -37.4,-33.8 -35.4,-33.8 -35.2,-34 -35.2,-36 -35.4,-36.2 -36.9,-36.2 -37.1,-36.4 -37.1,-37.8
  region net NetC191_1: -35.4,-38.4 -35.4,-38.8 -35.9,-38.8 -35.9,-38.4
  region net 3V3: -31.6,-37.8 -31.6,-34 -31.4,-33.8 -29.4,-33.8 -29.2,-34 -29.2,-36 -29.4,-36.2 -30.9,-36.2 -31.1,-36.4 -31.1,-37.8
  region net NetC187_1: -29.4,-38.4 -29.4,-38.8 -29.9,-38.8 -29.9,-38.4
  region net 3V3_BOARD: 110.9,43.2 110.9,41.1 109.1,41.1 109.1,43.2
  region net VIN_PROT: 128.8,45.9 128.8,45.6 128.2,45.6 128.2,45.9
  region net VIN: 131.2,45.9 131.2,45.6 131.8,45.6 131.8,45.9
  pour cut-out: -58,39 -50,39 -50,31 -58,31
  pour cut-out: -26,51.5 -18,51.5 -18,43.5 -26,43.5
  pour cut-out: -8,-41 -8,-51 2,-51 2,-41
  pour cut-out: -56,-36 -50,-36 -50,-30 -56,-30
  pour cut-out: -22,-14 -17,-19 17,-19 21,-15 21,15 17,19 -17,19 -22,14
  region net VIN_PROT: 126.5,40.5 126.5,47 124.5,47 119.3,52.2 113.8,52.2 113.8,49.8 117.2,49.8
  region net NetL1_1: 108.6,49.4 108.6,45.85 107.4,45.85 107.4,49.2 107.2,49.4 106,49.4 106,49.6 107.2,49.6 107.3,49.7 108.3,49.7
  region net VIN_PROT: 108,49.9 108,50.4 107.6,50.4 107.3,50.1 106,50.1 106,49.9
  region net CT: -56.9,-47 -56.9,-48 -55.5,-48 -55.5,-47
  text "30016232-02_TOP" at 7.5,56 h1.2
  text ".Layer_Name" at 28.6,-76.5 h2.54
3-INTOP:
  text ".Layer_Name" at 28.3,-76.6 h2.54
6-INBOT:
  text ".Layer_Name" at 28.4,-76.6 h2.54
Signal_4:
  text ".Layer_Name" at 15.875,-73.625 h2.54
  text ".Layer_Name" at 27.275,-74.225 h2.54
8-BOTTOM:
  text "30016232-02_BOT" at 25,56 h1.2
  text ".Layer_Name" at 28.4,-76.6 h2.54
2-GND (plane layer: these items are gaps in the copper):
  text "NEGATIVE IMAGE" at 27.975,-72.7 h2.54
  text ".Layer_Name" at 28.225,-76.575 h2.54
4-PWR (plane layer: these items are gaps in the copper):
  lines w0.3: 4.8,-38 5,-38 ; 94,-65 94,-53 95,-52 128,-52 135,-45 135,50 130,55 113,55 112,56 112,65 ; 105,32 85.1,32 75.1,22 49,22 30.5,40.5 5,40.5 -10.5,25 -28.5,25 -48,5.5 -48,-13 -38,-23 -38,-40 -36,-42 -22,-42 -18,-38 5,-38 ; 114,-42.5 114,-34 115,-33 117,-33 118.5,-34.5 120.8,-34.5 123.4,-31.9 ; 5,-38 9.75,-42.75 11.45,-42.75 16,-47.3 16,-50 17,-51 18,-51 19,-50 19,-34.5 24.5,-29 75,-29 81,-23 90,-23 97.27,-15.73 97.27,-7.73 98,-7 104,-7 116,-19 125.5,-19 128,-16.5 128,22.5 115.5,35 115.5,36.8 118.5,39.8 118.5,43 118,43.5 106.5,43.5 105,42 105,19 108.5,15.5 108.5,8.5 105,5 59,5 45,-9 36.2,-9 6.1,-39.1 5,-38 ; 123.4,-31.9 121,-29.5 108.5,-29.5 101.5,-36.5 101.5,-38.5 105.5,-42.5 124.568,-42.5 128,-39.068 128,-36.5 123.4,-31.9 ; -61,-37 -61,-24 -53,-16 -51,-16 -50.5,-16.5 -50.5,-38.5 -54,-42 -56,-42 -61,-37 ; -61,18.5 -60.5,18 -47.5,18 -45,20.5 -45,38 -46,39 -56.5,39 -61,34.5 -61,18.5 ; -35,40 -34,39 -15,39 -14,40 -14,45 -22.5,53.5 -29.5,53.5 -35,48 -35,40
  text ".Layer_Name" at 28.4,-76.8 h2.54
5-PWR (plane layer: these items are gaps in the copper):
  lines w0.3: -61,-29.9 -54.9,-29.9 -54.2,-29.2 -54.2,-25.7 -53.5,-25 -50.5,-25 ; -61,18 -47.5,18 -45,20.5 -45,39 ; -50.5,-27 -44,-27 -43,-28 -43,-43.5 ; -43,-36.5 -50.5,-36.5 ; -19,-65 -19,-53.5 -18,-52.5 -17,-52.5 -12.5,-57 69,-57 75,-51 75,-37.5 80,-32.5 80,-31 79,-30 71,-30 ; 5,65 5,52 -2,45 -14,45 ; 17.78,-13.335 17.78,-9.525 18.415,-8.89 43.89,-8.89 45,-10 45,-17 41,-21 19.095,-21 15.24,-17.145 15.24,-16.8 15.24,-14.605 16.51,-13.335 45,-13.335 ; 23,65 23,49.5 45,27.5 65,27.5 67.5,25 67.5,23.5 66,22 45.5,22 ; 105,39.5 122,39.5 123,38.5 123,-2.5 105.5,-20 54,-20 50,-24 50,-30 ; 105,65 105,-10 102,-13 69,-13 45.5,10.5 45.5,25.5 30.5,40.5 5,40.5 -10.5,25 -28.5,25 -48,5.5 -48,-13 -38,-23 -38,-40 -36,-42 -22,-42 -18,-38 5,-38 5.9,-38.9 6.3,-38.9 8.2,-37 43,-37 50,-30 ; -61,-37 -54.5,-43.5 -43,-43.5 ; -61,-37 -61,-35 ; -61,-37 -61,34.5 -56.5,39 -45,39 ; -61,-35 -58,-35 -55,-38 -52,-38 -50.5,-36.5 ; -61,-35 -61,-23 -51,-23 -50.5,-23.5 -50.5,-36.5 ; -45,39 -35,39 ; -43,-43.5 -36.5,-50 -14.5,-50 -10.5,-54 18,-54 19.5,-52.5 21,-52.5 22.5,-54 67.5,-54 69.5,-52 69.5,-50.9 67,-48.4 67,-46.8 71,-42.8 71,-30 ; -35,39 -35,48 -29.5,53.5 -22.5,53.5 -14,45 ; -35,39 -15,39 -14,40 -14,45 ; 50,-30 71,-30
  text ".Layer_Name" at 28.6,-76.7 h2.54
7-GND (plane layer: these items are gaps in the copper):
  text "NEGATIVE IMAGE" at 27.9,-72.7 h2.54
  text ".Layer_Name" at 28.7,-76.8 h2.54

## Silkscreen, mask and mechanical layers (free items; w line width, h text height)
Top Overlay:
  drawing of 38 lines, arcs and shapes, not listed
  text "CONSOLE" at -16,60.5 h1
  text "CAN" at -5.5,60.5 h1
  text "COIN-CELL" at 102.5,60 h1
  text "RS485" at 74.9,59.8 h1
  text "LED3" at 62.6,58.7 h1 r90
  text "LED2" at 66.6,58.7 h1 r90
  text "LED1" at 70.6,58.7 h1 r90
  text "MIPI Camera" at 49,49 h1
  text "POWER" at 42.5,38.5 h1
  text "RESET" at 52.5,38.5 h1
  text "USER2" at 64.5,38.5 h1
  text "USER1" at 74.5,38.5 h1
  text "Table in" at 119.8,33.1 h1
  text "bottom side" at 117,31.6 h1
  text "I2C2" at 65.2,26.2 h1
  text "XBEE USER" at 123.5,14 h1
  text "XBEE CELLULAR" at 122,-15 h1
  text "I2C3" at 10.3,-37 h1
  text "LVDS Display" at 3.6,-53.1 h1
  text "MIPI Display" at 30.3,-57.9 h1
  text "RECOVERY" at 107,-63 h1 r90
Bottom Overlay:
  drawing of 153 lines, arcs and shapes, not listed
  text "J24" at -5,62.3 h2
  text "J26" at 74.6,62.3 h2
  text "J43" at 20.6,59.9 h2
  text "J28" at 54.9,59.8 h2
  text "J4" at 107.6,59.6 h2
  text "J5" at 117.1,58.4 h2
  text "J3" at 96.1,58.3 h2
  text "J25" at 77.9,57 h2
  text "J23" at -2.2,56.9 h2
  text "J14" at -62.3,55.3 h2
  text "J1" at 126.5,54.1 h2
  text "J17" at -30.7,53.6 h2 r270
  text "J37" at -57.3,53.4 h2 r270
  text "J38" at -48,53.4 h2 r270
  text "J54" at 93.3,52.6 h2 r270
  text "J53" at -14.092,51.843 h2.05
  text "J52" at 18.748,51.843 h2.05
  text "J48" at 51.589,51.843 h2.05
  text "J45" at 84.43,51.843 h2.05
  text "J44" at 117.27,51.843 h2.05
  text "J2" at 137.2,50.2 h2 r270
  text "GND" at 11.4,49.3 h0.82
  text "LINE1_IN_R" at -21.789,49.277 h0.82
  text "1" at -18.197,49.277 h0.82
  text "2" at -15.118,49.277 h0.82
  text "LINE1_IN_L" at -5.369,49.277 h0.82
  text "1" at 14.643,49.277 h0.82
  text "2" at 17.722,49.277 h0.82
  text "EXP_I2C_SCL" at 43.892,49.277 h0.82
  text "1" at 47.484,49.277 h0.82
  text "2" at 50.563,49.277 h0.82
  text "I2C2_SCL_3V3" at 62.365,49.277 h0.82
  text "UART3_TX" at 76.733,49.277 h0.82
  text "1" at 80.324,49.277 h0.82
  text "2" at 83.403,49.277 h0.82
  text "XBEE1_UART_TX" at 95.719,49.277 h0.82
  text "BT_WAKEUP_HOST" at 109.573,49.277 h0.82
  text "1" at 113.165,49.277 h0.82
  text "2" at 116.244,49.277 h0.82
  text "VCC_MCA" at 25.1,49.2 h0.82
  text "BT_GPIO_2" at 125.6,49.2 h0.82
  text "LINE2_IN_R" at -21.789,47.225 h0.82
  text "3" at -18.197,47.225 h0.82
  text "4" at -15.118,47.225 h0.82
  text "LINE2_IN_L" at -5.369,47.225 h0.82
  text "3" at 14.643,47.225 h0.82
  text "4" at 17.722,47.225 h0.82
  text "EXP_I2C_SDA" at 43.892,47.225 h0.82
  text "3" at 47.484,47.225 h0.82
  text "4" at 50.563,47.225 h0.82
  text "I2C2_SDA_3V3" at 62.365,47.225 h0.82
  text "UART3_RX" at 76.733,47.225 h0.82
  text "3" at 80.324,47.225 h0.82
  text "4" at 83.403,47.225 h0.82
  text "XBEE1_UART_RX" at 95.719,47.225 h0.82
  text "BT_WAKEUP_SLAVE" at 109.573,47.225 h0.82
  text "3" at 113.165,47.225 h0.82
  text "4" at 116.244,47.225 h0.82
  text "5V" at 11.4,47.2 h0.82
  text "3V3_SOM_EXT" at 28.4,47.2 h0.82
  text "BT_GPIO_3" at 125.6,47.2 h0.82
  text "3V3_RF" at 24.3,45.2 h0.82
  text "BT_GPIO_5" at 125.6,45.2 h0.82
  text "LINE_OUT_R" at -21.789,45.172 h0.82
  text "5" at -18.197,45.172 h0.82
  text "6" at -15.118,45.172 h0.82
  text "LINE_OUT_L" at -5.369,45.172 h0.82
  text "5" at 14.643,45.172 h0.82
  text "6" at 17.722,45.172 h0.82
  text "EXP_I2C_IRQ_N" at 43.892,45.172 h0.82
  text "5" at 47.484,45.172 h0.82
  text "6" at 50.563,45.172 h0.82
  text "I2C3_SCL_1V8" at 62.365,45.172 h0.82
  text "GND" at 76.733,45.172 h0.82
  text "5" at 80.324,45.172 h0.82
  text "6" at 83.403,45.172 h0.82
  text "VCC_MCA" at 91.1,45.172 h0.82
  text "PCM_CLK" at 109.573,45.172 h0.82
  text "5" at 113.165,45.172 h0.82
  text "6" at 116.244,45.172 h0.82
  text "J53" at -39.2,45.1 h2 r270
  text "3V3_BOARD" at 11.4,45.1 h0.82
  text "1V8_SOM_EXT" at 11.4,43.2 h0.82
  text "SPKL_P" at -21.789,43.12 h0.82
  text "7" at -18.197,43.12 h0.82
  text "8" at -15.118,43.12 h0.82
  text "SPKL_N" at -7.935,43.12 h0.82
  text "7" at 14.643,43.12 h0.82
  text "8" at 17.722,43.12 h0.82
  text "VDDA_1V8" at 25.8,43.1 h0.82
  text "EXP_I2C_GPIO" at 43.892,43.12 h0.82
  text "7" at 47.484,43.12 h0.82
  text "8" at 50.563,43.12 h0.82
  text "I2C3_SDA_1V8" at 62.365,43.12 h0.82
  text "UART3_RTS_B" at 76.733,43.12 h0.82
  text "7" at 80.324,43.12 h0.82
  text "8" at 83.403,43.12 h0.82
  text "XBEE1_UART_RTS" at 96.745,43.12 h0.82
  text "PCM_IN" at 109.573,43.12 h0.82
  text "7" at 113.165,43.12 h0.82
  text "8" at 116.244,43.12 h0.82
  text "JTAG_SEL" at 124.9,43.1 h0.82
  text "LDO4" at 11.4,41.1 h0.82
  text "LDO5" at 22.6,41.1 h0.82
  text "GND" at 120.8,41.1 h0.82
  text "SPKR_P" at -21.789,41.067 h0.82
  text "9" at -18.197,41.067 h0.82
  text "10" at -15.118,41.067 h0.82
  text "SPKR_N" at -7.935,41.067 h0.82
  text "9" at 14.643,41.067 h0.82
  text "10" at 17.722,41.067 h0.82
  text "GND" at 43.892,41.067 h0.82
  text "9" at 47.484,41.067 h0.82
  text "10" at 50.563,41.067 h0.82
  text "GND" at 55.181,41.067 h0.82
  text "UART3_CTS_B" at 76.733,41.067 h0.82
  text "9" at 80.324,41.067 h0.82
  text "10" at 83.403,41.067 h0.82
  text "XBEE1_UART_CTS" at 96.745,41.067 h0.82
  text "PCM_OUT" at 109.573,41.067 h0.82
  text "9" at 113.165,41.067 h0.82
  text "10" at 116.244,41.067 h0.82
  text "J45" at 94.8,12.9 h2
  text "S1" at -35.655,11.464 h2.55
  text "Description" at -40.113,8.152 h2.55
  text "SW1.1" at -33.235,8.152 h2.55
  text "SW1.2" at -27.12,8.152 h2.55
  text "SW1.3" at -20.751,8.152 h2.55
  text "SW1.4" at -14.382,8.152 h2.55
  text "J49" at 40.579,7.826 h2.25
  text "J47" at 74.368,7.826 h2.25
  text "Bot from eMMC" at -40.113,5.732 h2.55
  text "Open" at -33.744,5.732 h2.55
  text "Open" at -27.375,5.732 h2.55
  text "Open" at -21.006,5.732 h2.55
  text "-" at -17.185,5.732 h2.55
  text "J44" at -64.1,5.3 h2 r270
  text "WLAN_SD1_D0" at 32.132,5.011 h0.9
  text "2" at 36.074,5.011 h0.9
  text "1" at 39.453,5.011 h0.9
  text "3V3_RF" at 46.774,5.011 h0.9
  text "3V3_SOM_EXT" at 65.921,5.011 h0.9
  text "2" at 69.863,5.011 h0.9
  text "1" at 73.242,5.011 h0.9
  text "GND" at 78.31,5.011 h0.9
  text "Boot from MicroSD" at -40.113,3.185 h2.55
  text "Open" at -33.744,3.185 h2.55
  text "Close" at -27.375,3.185 h2.55
  text "Close" at -21.006,3.185 h2.55
  text "-" at -17.185,3.185 h2.55
  text "WLAN_SD1_D1" at 32.132,2.758 h0.9
  text "4" at 36.074,2.758 h0.9
  text "3" at 39.453,2.758 h0.9
  text "BT_UART1_TX" at 51.279,2.758 h0.9
  text "SAI1_RXFS" at 65.921,2.758 h0.9
  text "4" at 69.863,2.758 h0.9
  text "3" at 73.242,2.758 h0.9
  text "SAI1_TXFS" at 83.378,2.758 h0.9
  text "J46" at 94.1,2.7 h2
  text "Boot from Fuses" at -40.113,0.637 h2.55
  text "Close" at -33.744,0.637 h2.55
  text "Open" at -27.375,0.637 h2.55
  text "-" at -23.554,0.637 h2.55
  text "-" at -17.185,0.637 h2.55
  text "WLAN_SD1_D2" at 32.132,0.505 h0.9
  text "6" at 36.074,0.505 h0.9
  text "5" at 39.453,0.505 h0.9
  text "BT_UART1_RX" at 51.279,0.505 h0.9
  text "SAI1_RXC" at 65.921,0.505 h0.9
  text "6" at 69.863,0.505 h0.9
  text "5" at 73.242,0.505 h0.9
  text "SAI1_TXC" at 82.815,0.505 h0.9
  text "WLAN_SD1_D3" at 32.132,-1.747 h0.9
  text "8" at 36.074,-1.747 h0.9
  text "7" at 39.453,-1.747 h0.9
  text "BT_UART1_RTS#" at 52.968,-1.747 h0.9
  text "SAI1_RXD0" at 65.921,-1.747 h0.9
  text "8" at 69.863,-1.747 h0.9
  text "7" at 73.242,-1.747 h0.9
  text "SAI1_TXD0" at 83.378,-1.747 h0.9
  text "J9" at 104.5,-1.9 h2 r270
  text "Serial downloader" at -40.113,-1.911 h2.55
  text "Close" at -33.744,-1.911 h2.55
  text "Close" at -27.375,-1.911 h2.55
  text "-" at -23.554,-1.911 h2.55
  text "-" at -17.185,-1.911 h2.55
  text "WLAN_SD1_D4" at 32.132,-4 h0.9
  text "10" at 36.074,-4 h0.9
  text "9" at 39.453,-4 h0.9
  text "BT_UART1_CTS#" at 52.968,-4 h0.9
  text "SAI1_RXD1" at 65.921,-4 h0.9
  text "10" at 69.863,-4 h0.9
  text "9" at 73.242,-4 h0.9
  text "SAI1_TXD1" at 83.378,-4 h0.9
  text "MIPI connected to HDMI" at -40.113,-4.458 h2.55
  text "-" at -36.292,-4.458 h2.55
  text "-" at -29.923,-4.458 h2.55
  text "-" at -23.554,-4.458 h2.55
  text "Open" at -14.637,-4.458 h2.55
  text "WLAN_SD1_D5" at 32.132,-6.252 h0.9
  text "12" at 36.074,-6.252 h0.9
  text "11" at 39.453,-6.252 h0.9
  text "GND" at 44.521,-6.252 h0.9
  text "SAI1_RXD2" at 65.921,-6.252 h0.9
  text "12" at 69.863,-6.252 h0.9
  text "11" at 73.242,-6.252 h0.9
  text "SAI1_TXD2" at 83.378,-6.252 h0.9
  text "MIPI connected to LVDS" at -40.113,-7.006 h2.55
  text "-" at -36.292,-7.006 h2.55
  text "-" at -29.923,-7.006 h2.55
  text "-" at -23.554,-7.006 h2.55
  text "Close" at -14.637,-7.006 h2.55
  text "J52" at 98.9,-7 h2
  text "WLAN_SD1_D6" at 32.132,-8.505 h0.9
  text "14" at 36.074,-8.505 h0.9
  text "13" at 39.453,-8.505 h0.9
  text "WL_HOST_WAKE" at 51.9,-8.5 h0.9
  text "SAI1_RXD3" at 65.921,-8.505 h0.9
  text "14" at 69.863,-8.505 h0.9
  text "13" at 73.242,-8.505 h0.9
  text "SAI1_TXD3" at 83.378,-8.505 h0.9
  text "WLAN_SD1_D7" at 32.132,-10.758 h0.9
  text "16" at 36.074,-10.758 h0.9
  text "15" at 39.453,-10.758 h0.9
  text "SAI1_RXD4" at 65.921,-10.758 h0.9
  text "16" at 69.863,-10.758 h0.9
  text "15" at 73.242,-10.758 h0.9
  text "SAI1_TXD4" at 83.378,-10.758 h0.9
  text "WL_DEV_WAKE" at 51.9,-10.8 h0.9
  text "WLAN_SD1_CLK" at 51.9,-13 h0.9
  text "GND" at 32.132,-13.01 h0.9
  text "18" at 36.074,-13.01 h0.9
  text "17" at 39.453,-13.01 h0.9
  text "SAI1_RXD5" at 65.921,-13.01 h0.9
  text "18" at 69.863,-13.01 h0.9
  text "17" at 73.242,-13.01 h0.9
  text "SAI1_TXD5" at 83.378,-13.01 h0.9
  text "J49" at -64.3,-14.9 h2 r270
  text "GND" at 32.132,-15.263 h0.9
  text "20" at 36.074,-15.263 h0.9
  text "19" at 39.453,-15.263 h0.9
  text "SAI1_RXD6" at 65.921,-15.263 h0.9
  text "20" at 69.863,-15.263 h0.9
  text "19" at 73.242,-15.263 h0.9
  text "SAI1_TXD6" at 83.378,-15.263 h0.9
  text "WLAN_SD1_CMD" at 51.9,-15.3 h0.9
  text "SAI1_RXD7" at 65.921,-17.515 h0.9
  text "22" at 69.863,-17.515 h0.9
  text "21" at 73.242,-17.515 h0.9
  text "SAI1_TXD7" at 83.378,-17.515 h0.9
  text "J50" at 98.6,-18.5 h2
  text "GND" at 65.921,-19.768 h0.9
  text "24" at 69.863,-19.768 h0.9
  text "23" at 73.242,-19.768 h0.9
  text "SAI1_MCLK" at 83.378,-19.768 h0.9
  text "J6" at 51.8,-24.5 h2
  text "J48" at 98.8,-27 h2
  text "J46" at 30,-33 h2.26
  text "J50" at 3.704,-33.11 h2.26
  text "J43" at 50.912,-33.11 h2.26
  text "J28" at 69.016,-33.11 h2.26
  text "1" at -0.822,-35.939 h0.91
  text "CLKIN1" at 6.532,-35.939 h0.91
  text "GPIO1_IO03" at 21.314,-35.931 h0.9
  text "2" at 25.256,-35.931 h0.9
  text "1" at 28.635,-35.931 h0.9
  text "1" at 46.386,-35.939 h0.91
  text "VCC_MCA" at 54.872,-35.939 h0.91
  text "1" at 64.49,-35.939 h0.91
  text "MIPI_CSI_DATA3_P" at 80.897,-35.939 h0.91
  text "3V3_SOM_EXT" at 40.833,-36.025 h0.9
  text "2" at -0.822,-38.202 h0.91
  text "GND" at 4.269,-38.202 h0.91
  text "GPIO1_IO15" at 21.314,-38.184 h0.9
  text "4" at 25.256,-38.184 h0.9
  text "3" at 28.635,-38.184 h0.9
  text "2" at 46.386,-38.202 h0.91
  text "POWER_BUTTON" at 59.398,-38.202 h0.91
  text "2" at 64.49,-38.202 h0.91
  text "MIPI_CSI_DATA3_N" at 80.897,-38.202 h0.91
  text "GPIO1_IO10" at 39.332,-38.225 h0.9
  text "GPIO3_IO01_1V8" at 21.314,-40.436 h0.9
  text "6" at 25.256,-40.436 h0.9
  text "5" at 28.635,-40.436 h0.9
  text "GPIO1_IO11" at 39.032,-40.425 h0.9
  text "3" at -0.822,-40.465 h0.91
  text "CLKIN2" at 6.532,-40.465 h0.91
  text "3" at 46.386,-40.465 h0.91
  text "SYS_RESET" at 56.569,-40.465 h0.91
  text "3" at 64.49,-40.465 h0.91
  text "GND" at 69.582,-40.465 h0.91
  text "J7" at -32,-42.3 h2 r270
  text "J8" at -38,-42.4 h2 r270
  text "GPIO1_IO13" at 39.332,-42.625 h0.9
  text "GPIO3_IO14_1V8" at 21.314,-42.689 h0.9
  text "8" at 25.256,-42.689 h0.9
  text "7" at 28.635,-42.689 h0.9
  text "4" at -0.822,-42.728 h0.91
  text "GND" at 4.269,-42.728 h0.91
  text "4" at 46.386,-42.728 h0.91
  text "MCA_CLKOUT32K" at 60.53,-42.728 h0.91
  text "4" at 64.49,-42.728 h0.91
  text "MIPI_CSI_DATA2_P" at 80.897,-42.728 h0.91
  text "GPIO1_IO14" at 39.332,-44.925 h0.9
  text "GND" at 21.314,-44.941 h0.9
  text "10" at 25.256,-44.941 h0.9
  text "9" at 28.635,-44.941 h0.9
  text "5" at -0.822,-44.991 h0.91
  text "CLKOUT1" at 7.664,-44.991 h0.91
  text "5" at 46.386,-44.991 h0.91
  text "GND" at 51.478,-44.991 h0.91
  text "5" at 64.49,-44.991 h0.91
  text "MIPI_CSI_DATA2_N" at 80.897,-44.991 h0.91
  text "J11" at -62.2,-46.9 h2
  text "6" at -0.822,-47.254 h0.91
  text "GND" at 4.269,-47.254 h0.91
  text "6" at 46.386,-47.254 h0.91
  text "MCA_VREF_OUT" at 59.398,-47.254 h0.91
  text "6" at 64.49,-47.254 h0.91
  text "GND" at 69.582,-47.254 h0.91
  text "7" at -0.822,-49.517 h0.91
  text "CLKOUT2" at 7.664,-49.517 h0.91
  text "8" at -0.822,-51.78 h0.91
  text "GND" at 4.269,-51.78 h0.91
  text "J27" at -48.192,-54.152 h2
  text "J36" at 97.5,-55 h2 r270
  text "J51" at 137.9,-57.6 h2
  text "J33" at 123,-58.7 h2
Board Outline:
  the board outline again, w0.25
Top Assembly:
  drawing of 1079 lines, arcs and shapes, not listed
Sheet Graphics:
  drawing of 618 lines, arcs and shapes, not listed
  text "1" at 357.523,112.943 h4.57
  text "4" at -60.942,112.308 h4.57
  text "3" at 81.298,112.308 h4.57
  text "2" at 220.363,111.673 h4.57
  text "1. Manufacture in accordance with IPC-6012, class 2. Inspect to IPC-A-600, class 2." at 213.05,96.75 h6
  text "2. Manufacturing process and materials used must comply with ROHS directive / 2002/95/EC." at 213.05,81.75 h6
  text "D" at -121.267,73.573 h7.11
  text "D" at 424.071,69.128 h7.11
  text "3. MATERIAL: ITEQ IT-180A /     Material should comply with IPC-4104/99/101/126 /     See Stack-up for details." at 213.05,61.75 h6
  text "4. SURFACE FINISH: Apply ENIG to all exposed copper per IPC-4552." at 213.05,54.25 h6
  text "5. Starting copper weight is 1/2oz. on all layers" at 213.05,46.75 h6
  text "6. SOLDER MASK: LPI over bare copper. / SOLDER MASK COLOR: BLUE" at 213.05,31.75 h6
  text "7. SILKSCREEN: Apply on top and bottom sides of PCB. / SILKSCREEN COLOR: WHITE" at 213.05,9.25 h6
  text "8. GERBER FILE FORMAT: 274-X WITH 4/3 accuracy (XXXX.XXX). / Gerber and drill in mm." at 213.05,-5.75 h6
  text "9. Maximum warp and twist per IPC-6012 of 0.75% inch/inch." at 213.05,-15.75 h6
  text "10. Copper thieving is NOT allowed within board outline. / Thieving may be placed in array rails." at 213.05,-33.25 h6
  text "C" at -121.267,-35.647 h7.11
  text "C" at 422.801,-35.647 h7.11
  text "11. Plated holes are specified as finished hole sizes (see table). / Plated hole tolerance ±0.003\" (±76µm) / NPTH tolerance ±0.0015\" (±38.1µm)" at 213.05,-55.75 h6
  text "12. Slot/Cut-Out tolerance ±0.005\" (±127µm)" at 213.05,-63.25 h6
  text "13. Finished thickness is 2mm (+/- 200µm)" at 213.4,-71.9 h6
  text "Layer" at -102.038,-78.6 h2
  text "Name" at -88.533,-78.6 h2
  text "Material" at -57.7,-78.6 h2
  text "Thickness" at -37.864,-78.6 h2
  text "Constant" at -16.361,-78.6 h2
  text "Board Layer Stack" at 2.476,-78.6 h2
  text "1" at -102.038,-82.6 h2
  text "Top Overlay" at -88.533,-82.6 h2
  text "2" at -102.038,-86.6 h2
  text "Top Solder" at -88.533,-86.6 h2
  text "SM-001" at -57.7,-86.6 h2
  text "0.010mm" at -37.864,-86.6 h2
  text "4" at -16.361,-86.6 h2
  text "3" at -102.038,-90.6 h2
  text "1-TOP" at -88.533,-90.6 h2
  text "Copper" at -57.7,-90.6 h2
  text "0.018mm" at -37.864,-90.6 h2
  text "4" at -102.038,-94.6 h2
  text "Dielectric1" at -88.533,-94.6 h2
  text "PP-017" at -57.7,-94.6 h2
  text "0.120mm" at -37.864,-94.6 h2
  text "4.2" at -16.361,-94.6 h2
  text "5" at -102.038,-98.6 h2
  text "2-GND" at -88.533,-98.6 h2
  text "Copper" at -57.7,-98.6 h2
  text "0.035mm" at -37.864,-98.6 h2
  text "6" at -102.038,-102.6 h2
  text "Dielectric2" at -88.533,-102.6 h2
  text "Core-015" at -57.7,-102.6 h2
  text "0.300mm" at -37.864,-102.6 h2
  text "4.2" at -16.361,-102.6 h2
  text "7" at -102.038,-106.6 h2
  text "3-INTOP" at -88.533,-106.6 h2
  text "Copper" at -57.7,-106.6 h2
  text "0.035mm" at -37.864,-106.6 h2
  text "8" at -102.038,-110.6 h2
  text "Dielectric3" at -88.533,-110.6 h2
  text "PP-017" at -57.7,-110.6 h2
  text "0.180mm" at -37.864,-110.6 h2
  text "4.2" at -16.361,-110.6 h2
  text "9" at -102.038,-114.6 h2
  text "4-PWR" at -88.533,-114.6 h2
  text "Copper" at -57.7,-114.6 h2
  text "0.035mm" at -37.864,-114.6 h2
  text "10" at -102.038,-118.6 h2
  text "Dielectric6" at -88.533,-118.6 h2
  text "Core-036" at -57.7,-118.6 h2
  text "0.200mm" at -37.864,-118.6 h2
  text "4.2" at -16.361,-118.6 h2
  text "11" at -102.038,-122.6 h2
  text "5-PWR" at -88.533,-122.6 h2
  text "Copper" at -57.7,-122.6 h2
  text "0.035mm" at -37.864,-122.6 h2
  text "12" at -102.038,-126.6 h2
  text "Dielectric10" at -88.533,-126.6 h2
  text "PP-017" at -57.7,-126.6 h2
  text "0.180mm" at -37.864,-126.6 h2
  text "4.2" at -16.361,-126.6 h2
  text "13" at -102.038,-130.6 h2
  text "6-INBOT" at -88.533,-130.6 h2
  text "Copper" at -57.7,-130.6 h2
  text "0.035mm" at -37.864,-130.6 h2
  text "14" at -102.038,-134.6 h2
  text "Dielectric 12" at -88.533,-134.6 h2
  text "Core-015" at -57.7,-134.6 h2
  text "0.300mm" at -37.864,-134.6 h2
  text "4.2" at -16.361,-134.6 h2
  text "15" at -102.038,-138.6 h2
  text "Signal_4" at -88.533,-138.6 h2
  text "Copper" at -57.7,-138.6 h2
  text "0.013mm" at -37.864,-138.6 h2
  text "B" at -121.267,-141.692 h7.11
  text "B" at 422.801,-141.692 h7.11
  text "16" at -102.038,-142.6 h2
  text "Dielectric1" at -88.533,-142.6 h2
  text "FR-4" at -57.7,-142.6 h2
  text "0.320mm" at -37.864,-142.6 h2
  text "4.8" at -16.361,-142.6 h2
  text "17" at -102.038,-146.6 h2
  text "7-GND" at -88.533,-146.6 h2
  text "Copper" at -57.7,-146.6 h2
  text "0.035mm" at -37.864,-146.6 h2
  text "18" at -102.038,-150.6 h2
  text "Dielectric11" at -88.533,-150.6 h2
  text "PP-017" at -57.7,-150.6 h2
  text "0.120mm" at -37.864,-150.6 h2
  text "4.2" at -16.361,-150.6 h2
  text "19" at -102.038,-154.6 h2
  text "8-BOTTOM" at -88.533,-154.6 h2
  text "Copper" at -57.7,-154.6 h2
  text "0.018mm" at -37.864,-154.6 h2
  text "20" at -102.038,-158.6 h2
  text "Bottom Solder" at -88.533,-158.6 h2
  text "SM-001" at -57.7,-158.6 h2
  text "0.010mm" at -37.864,-158.6 h2
  text "4" at -16.361,-158.6 h2
  text "21" at -102.038,-162.6 h2
  text "Bottom Overlay" at -88.533,-162.6 h2
  text "A" at -120.835,-234.402 h7.11
  text "A" at 423.233,-234.402 h7.11
  text "CAD GENERATED:" at 361.968,-239.482 h1.27
  text "CAD GENERATED:" at 361.968,-239.482 h1.27
  text ".pcb_File_Name_No_Path" at 377.462,-239.482 h2.17
  text "EXCEPT AS MAY BE OTHERWISE PROVIDED BY" at 262.908,-243.546 h2.17
  text "DIGI INTERNATIONAL INC" at 356.888,-245.07 h2.54
  text "CONTRACT, THIS DOCUMENT IS THE PROPERTY" at 262.908,-245.578 h2.17
  text "OF DIGI INTERNATIONAL.  IF RELEASED TO OTHER" at 262.908,-247.61 h2.17
  text "9350 Excelsior Blvd Suite 700" at 356.888,-248.626 h2.54
  text "SOURCES, IT SHALL BE RECEIVED BY SUCH" at 262.908,-249.642 h2.17
  text "SOURCES IN TOTAL CONFIDENCE AND SHALL NOT" at 262.908,-251.674 h2.17
  text "Hopkins, MN 55343" at 357.396,-252.182 h2.54
  text "BE RELEASED TO ANY THIRD PARTY OR PARTIES," at 262.908,-253.706 h2.17
  text "NOR USED FOR MANUFACTURE OR SALE OF THE" at 262.908,-255.738 h2.17
  text "ARTICLES WITHOUT PRIOR WRITTEN" at 262.908,-257.77 h2.17
  text "DIGI INTERNATIONAL" at 346,-258.175 h2.54
  text "AUTHORIZATION." at 262.908,-259.802 h2.17
  text "ConnectCore 8M Nano" at 341.746,-262.194 h2.54
  text "DEVELOPMENT BOARD" at 343.6,-266.3 h2.54
  text "ENGINEER" at 262.4,-266.406 h1.27
  text "JUAN ANZOLA" at 279.774,-267.066 h1.27
  text "PCB DESIGNER" at 262.4,-271.486 h1.27
  text "SIZE" at 315.74,-271.486 h1.27
  text "CAGE NO." at 323.868,-271.486 h1.27
  text "PCB NO." at 351.808,-271.486 h1.27
  text "REV." at 413.784,-271.486 h1.27
  text "JUAN ANZOLA" at 279.774,-272.146 h1.27
  text "30016232-03" at 367.75,-275.55 h2.54
  text "DATE" at 262.4,-276.058 h1.27
  text "C" at 316.248,-276.058 h2.54
  text "A" at 413.784,-276.058 h2.54
  text ".Print_Date" at 279.164,-277.074 h1.27
  text "JIRA EPIC:" at 262.4,-281.138 h1.27
  text ".Print_Scale" at 313.708,-282.662 h1.27
  text "SVN HEAD REV:" at 339.108,-282.662 h1.27
  text ".VersionControl_RevNumber" at 354.856,-282.662 h1.27
  text "SHEET:" at 377.208,-282.662 h1.27
  text "1 OF 1" at 395.75,-282.662 h1.27
  text "1" at 357.523,-292.187 h4.57
  text "4" at -60.942,-292.822 h4.57
  text "3" at 81.298,-292.822 h4.57
  text "2" at 220.363,-293.457 h4.57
